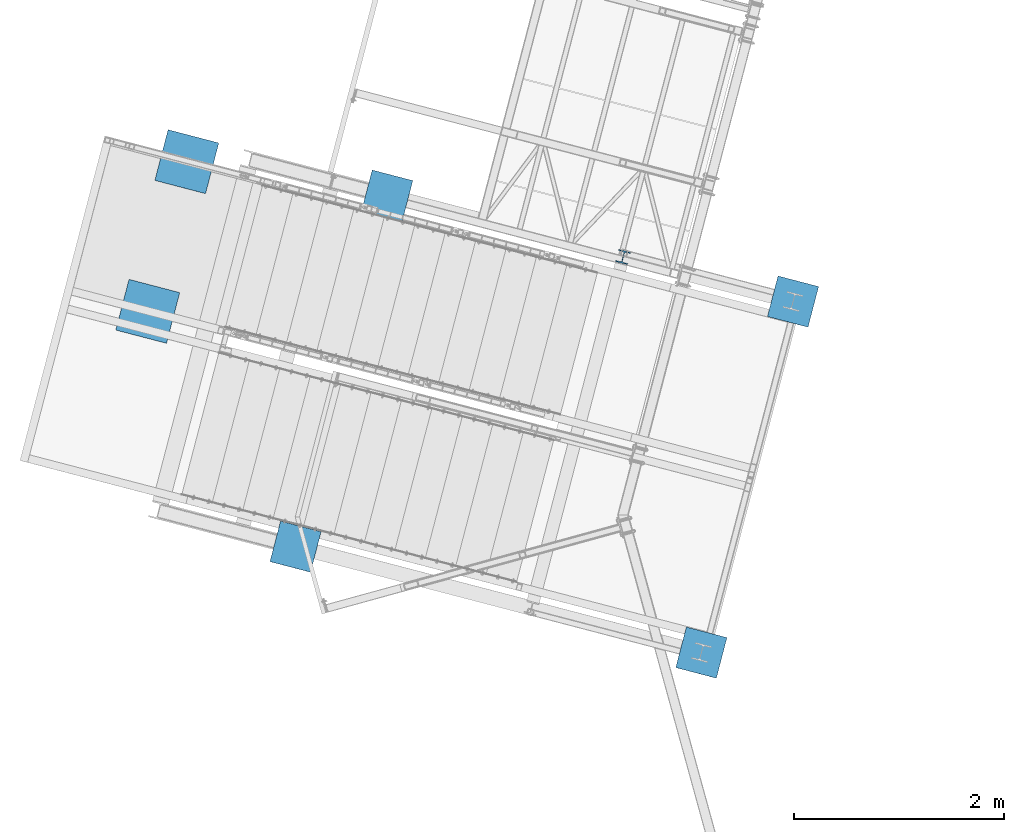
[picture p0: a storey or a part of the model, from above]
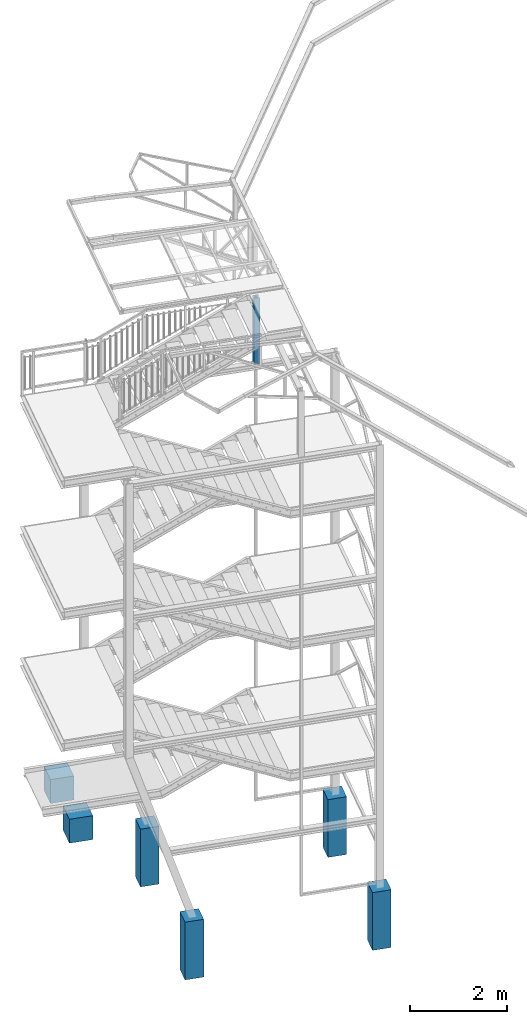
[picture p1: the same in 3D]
Properties of the parts of a building model (IFC2X3), part 1 of 5

# File
Description: ViewDefinition[CoordinationView_V2.0, QuantityTakeOffAddOnView], Option [BaseQuantities:On], Option [GridExport:On], Option [Assemblies:On], Option [Bolts:On], Option [Rebars:On], Option [PourObjects:Off], Option [Welds:Off], Option [SurfaceTreatments:Off], Option [LocationBy:0], Option [ViewColors:Off], Option [SectionedSpine:Off], Option [PropertySets:On], Option [Export all:Off]
File name: IR_026-25_ifc_kładka.ifc
Time: 2025-10-13T10:14:06
Author: INFRARED\aneta.moskala
Organization: Structural Designer
Written by: IFC Database Version: Work
Made in: Tekla Structures Educational 2018, IFC Export Version: 4.0.0.0 Mar 15 2018

# IfcSite, Undefined
RefElevation: 0 mm

# IfcBuildingStorey, Undefined
In: Undefined
Elevation: 0 mm

# IfcBeam: 200*1500, BEAM
In: Undefined
Description: 200*1500; Material: CONCRETE/C45/55
Tekla Common - Bottom elevation: +5.080; Top elevation: +5.280; Phase: 1; Class: 4
Tekla Quantity - Weight: 3339 kg; Volume: 1.4 m3; Gross footprint area: 7 m2; Area per tons: 5 m2; Net surface area: 16.6 m2; Height: 200 mm; Width: 1500 mm; Length: 6146 mm
Pset_BeamCommon - LoadBearing: yes; Reference: Z3
BaseQuantities - Length: 6146 mm; OuterSurfaceArea: 16.6194 m2; NetVolume: 1.39123 m3; NetWeight: 3338.95 kg

# IfcBeam: 350*350 (4)
In: Undefined
Description: 350*350; Material: CONCRETE/C45/55
Tekla Common - Bottom elevation: +3.670; Top elevation: +4.480; Phase: 1; Class: 4
Tekla Quantity - Weight: 238.1 kg; Volume: 0.1 m3; Gross footprint area: 0.1 m2; Area per tons: 5.8 m2; Net surface area: 1.5 m2; Height: 350 mm; Width: 350 mm; Length: 810 mm
Pset_BeamCommon - LoadBearing: yes; Reference: Z1
BaseQuantities - Length: 810 mm; OuterSurfaceArea: 1.379 m2; NetVolume: 0.099225 m3; NetWeight: 238.14 kg

# IfcBeam: 800*350 (3)
In: Undefined
Description: 800*350; Material: CONCRETE/C45/55
Tekla Common - Bottom elevation: +4.480; Top elevation: +5.280; Phase: 1; Class: 4
Tekla Quantity - Height: 800 mm; Width: 350 mm
Pset_BeamCommon - LoadBearing: yes
Name | Weight (kg) | Volume (m3) | Gross footprint area (m2) | Area per tons (m2) | Net surface area (m2) | Tekla Quantity, Length (mm) | Reference | BaseQuantities, Length (mm) | OuterSurfaceArea (m2) | NetVolume (m3) | NetWeight (kg)
BEAM | 3281.2 | 1.4 | 1.6 | 3.7 | 12.1 | 5289.9 | Z4 | 5289.87 | 12.1456 | 1.36717 | 3281.21
BEAM | 3628.8 | 1.4 | 2 | 3.6 | 13 | 5400 | Z2 | 5400 | 12.98 | 1.512 | 3628.8
BEAM | 8295.2 | 3.5 | 4.2 | 3.5 | 29 | 12350 | Z5 | 12350 | 28.9882 | 3.45632 | 8295.16

# IfcBeam: C100*20*2 (12)
In: Undefined
Description: C100*20*2
Tekla Common - Class: 1
Tekla Quantity - Volume: 0 m3; Gross footprint area: 0 m2; Height: 100 mm; Width: 20 mm
Name | Material | Bottom elevation | Top elevation | Phase | Weight (kg) | Area per tons (m2) | Net surface area (m2) | Tekla Quantity, Length (mm) = BaseQuantities, Length (mm) | LoadBearing | Reference | OuterSurfaceArea (m2) | NetVolume (m3) | NetWeight (kg)
KICK_PLATE | STEEL/S235JR | +13.946 | +14.065 | 1 | 3.2 | 129.4 | 0.4 | 1492.5 | yes | F15 | 0.410671 | 0.000404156 | 3.17263
KICK_PLATE | STEEL/S235JR | +13.946 | +14.047 | 1 | 3.2 | 129.4 | 0.4 | 1490 | yes | F7 | 0.411784 | 0.00040528 | 3.18145
KICK_PLATE | STEEL/S235JR | +13.915 | +14.046 | 1 | 5.4 | 129.4 | 0.7 | 2475.5 | yes | F17 | 0.683782 | 0.000673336 | 5.28569
KICK_PLATE | STEEL/S235JR | +13.812 | +13.961 | 1 | 8.2 | 129.4 | 1.1 | 3895 | yes | F10 | 1.07556 | 0.00105944 | 8.3166
KICK_PLATE | STEEL/S235JR | +13.915 | +14.015 | 1 | 3.2 | 129.4 | 0.4 | 1490 | yes | F7 | 0.411784 | 0.00040528 | 3.18145
KICK_PLATE | STEEL/S235JR | +13.861 | +14.015 | 1 | 9 | 129.4 | 1.2 | 4220 | yes | F9 | 1.16346 | 0.00114603 | 8.99636
KICK_PLATE | STEEL/S235JR | +13.865 | +14.014 | 1 | 8.2 | 129.4 | 1.1 | 3862 | yes | F8 | 1.06646 | 0.00105046 | 8.24614
KICK_PLATE | STEEL/S235JR | +13.914 | +14.065 | 1 | 8.6 | 129.4 | 1.1 | 4042 | yes | F6 | 1.11614 | 0.00109942 | 8.63048
KICK_PLATE | STEEL/S235JR | +13.800 | +13.900 | 5 | 4.2 | 129.4 | 0.4 | 1975 | yes | p8 | 0.544689 | 0.000536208 | 4.20923
KICK_PLATE | STEEL/S235JR | +13.800 | +13.900 | 5 | 4.6 | 129.4 | 0.7 | 2182 | yes | F19 | 0.602776 | 0.000593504 | 4.65901
PORĘCZ | STEEL/S235 | +13.811 | +13.911 | 1 | 0.6 | 130.1 | 0.1 | 300 | no | fk79 | 0.0828763 | 0.0000811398 | 0.636947
KICK_PLATE | STEEL/S235JR | +13.800 | +13.965 | 1 | 10.8 | 129.4 | 1.5 | 5060 | yes | F11 | 1.3971 | 0.00137632 | 10.8041

# IfcBeam: C100*50*3 (2)
In: Undefined
Description: C100*50*3; Material: STEEL/S235
Tekla Common - Bottom elevation: +13.925; Phase: 2
Tekla Quantity - Volume: 0 m3; Gross footprint area: 0 m2; Area per tons: 86.3 m2; Height: 100 mm; Width: 50 mm
Name | Top elevation | Class | Weight (kg) | Net surface area (m2) | Tekla Quantity, Length (mm) = BaseQuantities, Length (mm) | LoadBearing | Reference | OuterSurfaceArea (m2) | NetVolume (m3) | NetWeight (kg)
BEAM | +14.026 | 14 | 11.6 | 1 | 2540 | yes | k159 | 1.00192 | 0.00147828 | 11.6045
BEAM | +14.025 | 6 | 7.2 | 0.7 | 1570 | no | k101 | 0.619744 | 0.00091374 | 7.17286

# IfcBeam: C70*40*4 (3)
In: Undefined
Description: C70*40*4; Material: STEEL/S235
Tekla Common - Class: 6
Tekla Quantity - Volume: 0 m3; Height: 70 mm; Width: 40 mm
Pset_BeamCommon - LoadBearing: no
Name | Bottom elevation | Top elevation | Phase | Weight (kg) | Gross footprint area (m2) | Area per tons (m2) | Net surface area (m2) | Tekla Quantity, Length (mm) | Reference | BaseQuantities, Length (mm) | OuterSurfaceArea (m2) | NetVolume (m3) | NetWeight (kg)
BEAM | +13.910 | +13.980 | 2 | 2.7 | 0 | 65.9 | 0.2 | 598.9 | k106 | 598.9 | 0.175014 | 0.000338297 | 2.65563
BEAM | +13.911 | +13.982 | 3 | 11.9 | 0.1 | 65.6 | 0.7 | 2679.8 | Ws13 | 2679.83 | 0.783647 | 0.00152215 | 11.9488
BEAM | +13.910 | +13.980 | 3 | 10.1 | 0.1 | 65.6 | 0.7 | 2257.7 | Ws15 | 2257.68 | 0.660377 | 0.00128236 | 10.0665

# IfcBeam: C80*40*3 (6)
In: Undefined
Description: C80*40*3
Tekla Common - Class: 6
Tekla Quantity - Volume: 0 m3; Height: 80 mm; Width: 40 mm
Name | Material | Bottom elevation | Top elevation | Phase | Weight (kg) | Gross footprint area (m2) | Area per tons (m2) | Net surface area (m2) | Tekla Quantity, Length (mm) | LoadBearing | Reference | BaseQuantities, Length (mm) | OuterSurfaceArea (m2) | NetVolume (m3) | NetWeight (kg)
BEAM | STEEL/S355 | +13.860 | +13.973 | 1 | 8.2 | 0 | 86.7 | 0.7 | 2262 | yes | k166 | 2262 | 0.711192 | 0.00104504 | 8.2036
BEAM | STEEL/S235 | +13.909 | +13.989 | 2 | 5.2 | 0.1 | 86.9 | 0.4 | 1438.6 | no | k103 | 1438.61 | 0.451684 | 0.000663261 | 5.2066
BEAM | STEEL/S355 | +13.806 | +13.955 | 1 | 18.4 | 0 | 86.7 | 1.6 | 5100 | yes | k80 | 5100 | 1.60232 | 0.0023562 | 18.4962
BEAM | STEEL/S355 | +13.809 | +13.944 | 1 | 14.5 | 0 | 86.7 | 1.2 | 3990 | yes | k74 | 3990 | 1.25378 | 0.00184338 | 14.4705
BEAM | STEEL/S235 | +13.910 | +13.990 | 3 | 4.9 | 0.1 | 86.9 | 0.4 | 1366 | no | k72 | 1365.95 | 0.42887 | 0.000629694 | 4.9431
BEAM | STEEL/S235 | +13.910 | +13.990 | 3 | 5.4 | 0.1 | 86.7 | 0.4 | 1500 | no | k70 | 1500 | 0.471924 | 0.000693 | 5.44005

# IfcBeam: D10 (2)
In: Undefined
Description: D10; Material: STEEL/S235
Tekla Common - Phase: 3; Class: 11
Tekla Quantity - Weight: 1.1 kg; Volume: 0 m3; Gross footprint area: 0 m2; Area per tons: 55.3 m2; Net surface area: 0.1 m2; Height: 10 mm; Width: 10 mm
Pset_BeamCommon - LoadBearing: no
Name | Bottom elevation | Top elevation | Tekla Quantity, Length (mm) | Reference | BaseQuantities, Length (mm) | OuterSurfaceArea (m2) | NetVolume (m3) | NetWeight (kg)
BEAM | +13.885 | +13.948 | 1980 | k79 | 1980 | 0.0607585 | 0.000140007 | 1.09906
BEAM | +13.866 | +13.929 | 1978.7 | k78 | 1978.68 | 0.060718 | 0.000139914 | 1.09832

# IfcBeam: HEB140 (10)
In: Undefined
Description: HEB140
Tekla Common - Class: 4
Tekla Quantity - Volume: 0 m3; Area per tons: 23.8 m2; Height: 140 mm; Width: 140 mm
Pset_BeamCommon - LoadBearing: no
Name | Material | Bottom elevation | Top elevation | Phase | Weight (kg) | Gross footprint area (m2) | Net surface area (m2) | Tekla Quantity, Length (mm) | Reference | BaseQuantities, Length (mm) | OuterSurfaceArea (m2) | NetVolume (m3) | NetWeight (kg)
COLUMN | STEEL/S235 | +2.640 | +2.780 | 2 | 111.4 | 0 | 2.7 | 3300 | xx15 | 3300 | 2.6565 | 0.0137676 | 108.076
2 x BEAM | STEEL/S355 | +13.400 | +13.540 | 5 | 8.4 | 0 | 0.2 | 250 | zz2 | 250 | 0.20125 | 0.001043 | 8.18755
BEAM | STEEL/S355 | +13.400 | +13.540 | 5 | 167.4 | 0.7 | 4.2 | 4959.9 | zz8 | 4959.92 | 3.99274 | 0.0206928 | 162.438
2 x BEAM | STEEL/S355 | +13.400 | +13.540 | 5 | 10.8 | 0 | 0.2 | 320 | zz3 | 320 | 0.2576 | 0.001043 | 8.18755
BEAM | STEEL/S355 | +13.400 | +13.540 | 5 | 53.5 | 0.2 | 1.2 | 1584.7 | zz6 | 1584.71 | 1.27569 | 0.0064666 | 50.7628
BEAM | STEEL/S355 | +13.400 | +13.540 | 5 | 94.7 | 0.3 | 2.3 | 2805 | zz9 | 2805 | 2.25803 | 0.0117025 | 91.8643
BEAM | STEEL/S355 | +13.400 | +13.540 | 5 | 9 | 0 | 0.2 | 267.8 | zz27 | 267.81 | 0.215587 | 0.00101888 | 7.99817
BEAM | STEEL/S355 | +13.400 | +13.540 | 5 | 129.8 | 0.5 | 3.2 | 3846 | tt1 | 3846 | 3.09603 | 0.0160455 | 125.957

# IfcBeam: HEB160 (7)
In: Undefined
Description: HEB160
Tekla Quantity - Gross footprint area: 0 m2; Area per tons: 21.5 m2; Height: 160 mm; Width: 160 mm
Pset_BeamCommon - LoadBearing: no
Name | Material | Bottom elevation | Top elevation | Phase | Class | Weight (kg) | Volume (m3) | Net surface area (m2) | Tekla Quantity, Length (mm) | Reference | BaseQuantities, Length (mm) | OuterSurfaceArea (m2) | NetVolume (m3) | NetWeight (kg)
COLUMN | STEEL/S235 | +11.990 | +12.150 | 2 | 4 | 140.7 | 0 | 3.1 | 3300 | xx13 | 3300 | 3.0294 | 0.0172656 | 135.535
COLUMN | STEEL/S235 | +8.690 | +8.850 | 2 | 4 | 140.7 | 0 | 3.1 | 3300 | xx13 | 3300 | 3.0294 | 0.0172656 | 135.535
COLUMN | STEEL/S235 | +5.390 | +5.550 | 2 | 4 | 140.7 | 0 | 3.1 | 3300 | xx13 | 3300 | 3.0294 | 0.0172656 | 135.535
2 x COLUMN | STEEL/S235 | +1.020 | +12.140 | 2 | 4 | 474 | 0.1 | 10.5 | 11120 | xx35 | 11120 | 10.2082 | 0.0581798 | 456.712
2 x BEAM | STEEL/S355 | +13.620 | +13.700 | 1 | 3 | 3.4 | 0 | 0.1 | 79.6 | k45 | 79.6292 | 0.0730996 | 0.00041595 | 3.26521

# IfcBeam: K60/4 (2)
In: Undefined
Description: K60/4; Material: STEEL/S355
Tekla Common - Bottom elevation: +13.848; Top elevation: +13.915; Phase: 1; Class: 9
Tekla Quantity - Weight: 6.2 kg; Volume: 0 m3; Gross footprint area: 0 m2; Area per tons: 34.4 m2; Net surface area: 0.2 m2; Height: 60 mm; Width: 60 mm; Length: 911.6 mm
Pset_BeamCommon - LoadBearing: no; Reference: k43
BaseQuantities - OuterSurfaceArea: 0.209657 m2; NetVolume: 0.000816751 m3
Name | Length (mm) | NetWeight (kg)
BEAM | 911.552 | 6.41149
BEAM | 911.553 | 6.4115

# IfcBeam: L100*50*5 (12)
In: Undefined
Description: L100*50*5; Material: STEEL/S235
Tekla Common - Bottom elevation: +13.715; Top elevation: +13.765; Phase: 5; Class: 11
Tekla Quantity - Volume: 0 m3; Height: 100 mm; Width: 50 mm
Pset_BeamCommon - LoadBearing: no
Name | Weight (kg) | Gross footprint area (m2) | Area per tons (m2) | Net surface area (m2) | Tekla Quantity, Length (mm) = BaseQuantities, Length (mm) | Reference | OuterSurfaceArea (m2) | NetVolume (m3) | NetWeight (kg)
BEAM | 3.9 | 0.1 | 53.1 | 0.2 | 700 | K10 | 0.21145 | 0.0005075 | 3.98387
BEAM | 6.2 | 0.1 | 52.9 | 0.4 | 1080 | K4 | 0.32545 | 0.000783 | 6.14655
BEAM | 3.9 | 0.1 | 53.1 | 0.2 | 690 | K3 | 0.20845 | 0.00050025 | 3.92696
BEAM | 4.6 | 0.1 | 52.9 | 0.2 | 800 | K9 | 0.24145 | 0.00058 | 4.553
BEAM | 0.6 | 0 | 54.8 | 0 | 120 | K15 | 0.03745 | 0.000087 | 0.68295
BEAM | 0.8 | 0 | 54.4 | 0 | 150 | K13 | 0.04645 | 0.00010875 | 0.853688
BEAM | 4.9 | 0.1 | 52.9 | 0.4 | 850 | K14 | 0.25645 | 0.00061625 | 4.83756
BEAM | 3.9 | 0.1 | 53.1 | 0.2 | 700 | K10 | 0.21145 | 0.0005075 | 3.98388
BEAM | 5.2 | 0.1 | 52.9 | 0.4 | 900 | K7 | 0.27145 | 0.0006525 | 5.12212
2 x BEAM | 5.4 | 0.1 | 52.9 | 0.4 | 950 | K11 | 0.28645 | 0.00068875 | 5.40669
BEAM | 5.4 | 0.1 | 52.9 | 0.4 | 950 | K6 | 0.28645 | 0.00068875 | 5.40669

# IfcBeam: L40*3 (2)
In: Undefined
Description: L40*3; Material: STEEL/S235
Tekla Common - Bottom elevation: +13.725; Top elevation: +13.765; Phase: 5; Class: 4
Tekla Quantity - Volume: 0 m3; Gross footprint area: 0 m2; Area per tons: 84.4 m2; Height: 40 mm; Width: 40 mm
Pset_BeamCommon - LoadBearing: no
Name | Weight (kg) | Net surface area (m2) | Tekla Quantity, Length (mm) = BaseQuantities, Length (mm) | Reference | OuterSurfaceArea (m2) | NetVolume (m3) | NetWeight (kg)
BEAM | 1.6 | 0.1 | 885 | D1 | 0.137175 | 0.000204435 | 1.60481
BEAM | 1.9 | 0.2 | 1055 | D3 | 0.163525 | 0.000243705 | 1.91308

# IfcBeam: L40*60*6, BEAM
In: Undefined
Description: L40*60*6; Material: STEEL/S235
Tekla Common - Bottom elevation: +13.984; Top elevation: +14.024; Phase: 3; Class: 4
Tekla Quantity - Weight: 28.5 kg; Volume: 0 m3; Gross footprint area: 0 m2; Area per tons: 45.2 m2; Net surface area: 1.2 m2; Height: 40 mm; Width: 60 mm; Length: 6436 mm
Pset_BeamCommon - LoadBearing: no; Reference: xx21
BaseQuantities - Length: 6436 mm; OuterSurfaceArea: 1.28723 m2; NetVolume: 0.00362685 m3; NetWeight: 28.4708 kg

# IfcBeam: L50*3 (6)
In: Undefined
Description: L50*3; Material: STEEL/S235
Tekla Common - Bottom elevation: +13.715; Top elevation: +13.765; Phase: 5; Class: 11
Tekla Quantity - Volume: 0 m3; Area per tons: 84.9 m2; Net surface area: 0.2 m2; Height: 50 mm; Width: 50 mm
Pset_BeamCommon - LoadBearing: no
Name | Weight (kg) | Gross footprint area (m2) | Tekla Quantity, Length (mm) = BaseQuantities, Length (mm) | Reference | OuterSurfaceArea (m2) | NetVolume (m3) | NetWeight (kg)
BEAM | 2.7 | 0.1 | 1200 | K5 | 0.2328 | 0.0003492 | 2.74122
BEAM | 2.2 | 0 | 980 | K1 | 0.19012 | 0.00028518 | 2.23866
BEAM | 1.8 | 0 | 780 | K2 | 0.15132 | 0.00022698 | 1.78179
BEAM | 1.8 | 0 | 800 | K8 | 0.1552 | 0.0002328 | 1.82748
2 x BEAM | 2.2 | 0 | 950 | K12 | 0.1843 | 0.00027645 | 2.17013

# IfcBeam: L70*5, BEAM
In: Undefined
Description: L70*5; Material: STEEL/S235
Tekla Common - Bottom elevation: +13.665; Top elevation: +13.785; Phase: 5; Class: 1
Tekla Quantity - Weight: 0.6 kg; Volume: 0 m3; Gross footprint area: 0 m2; Area per tons: 51.3 m2; Net surface area: 0 m2; Height: 70 mm; Width: 70 mm; Length: 120 mm
Pset_BeamCommon - LoadBearing: no; Reference: F20
BaseQuantities - Length: 120 mm; OuterSurfaceArea: 0.03264 m2; NetVolume: 0.000081 m3; NetWeight: 0.63585 kg

# IfcBeam: L80*50*3, PORĘCZ
In: Undefined
Description: L80*50*3; Material: STEEL/S235
Tekla Common - Bottom elevation: +13.350; Top elevation: +13.430; Phase: 2; Class: 1
Tekla Quantity - Weight: 0.1 kg; Volume: 0 m3; Gross footprint area: 0 m2; Area per tons: 92 m2; Net surface area: 0 m2; Height: 80 mm; Width: 50 mm; Length: 50 mm
Pset_BeamCommon - LoadBearing: yes; Reference: 5
BaseQuantities - Length: 50.0001 mm; OuterSurfaceArea: 0.013762 m2; NetVolume: 0.00001905 m3; NetWeight: 0.149543 kg

# IfcBeam: L85*5, BEAM
In: Undefined
Description: L85*5; Material: STEEL/S235
Tekla Common - Bottom elevation: +13.665; Top elevation: +13.785; Phase: 5; Class: 1
Tekla Quantity - Weight: 0.8 kg; Volume: 0 m3; Gross footprint area: 0 m2; Area per tons: 54.6 m2; Net surface area: 0 m2; Height: 85 mm; Width: 85 mm; Length: 120 mm
Pset_BeamCommon - LoadBearing: no; Reference: F21
BaseQuantities - Length: 120 mm; OuterSurfaceArea: 0.04245 m2; NetVolume: 0.000099 m3; NetWeight: 0.77715 kg

# IfcBeam: RHS100*60*6 (2)
In: Undefined
Description: RHS100*60*6; Material: STEEL/S235
Tekla Common - Phase: 3; Class: 4
Tekla Quantity - Weight: 89.6 kg; Volume: 0 m3; Gross footprint area: 0.3 m2; Area per tons: 22.6 m2; Net surface area: 1.9 m2; Height: 100 mm; Width: 60 mm; Length: 6476 mm
Pset_BeamCommon - LoadBearing: no
BaseQuantities - Length: 6476 mm; OuterSurfaceArea: 2.02685 m2; NetVolume: 0.0114161 m3; NetWeight: 89.6161 kg
Name | Bottom elevation | Top elevation | Reference
BEAM | +12.781 | +12.881 | xx22
BEAM | +13.780 | +13.880 | xx19

# IfcBeam: RHS100*80*4 (3)
In: Undefined
Description: RHS100*80*4
Tekla Quantity - Volume: 0 m3; Area per tons: 33.2 m2; Height: 100 mm; Width: 80 mm
Tekla Common - Top elevation: +14.025; Phase: 2
Name | Material | Weight (kg) | Gross footprint area (m2) | Net surface area (m2) | Tekla Quantity, Length (mm) | Bottom elevation | Class | LoadBearing | Reference | BaseQuantities, Length (mm) | OuterSurfaceArea (m2) | NetVolume (m3) | NetWeight (kg)
BEAM | STEEL/S355 | 36.4 | 0.3 | 1.2 | 3412 | +13.925 | 14 | no | k119 | 3412 | 1.20993 | 0.00463987 | 36.4229
2 x BEAM | STEEL/S235 | 31.3 | 0 | 1 | 2905.5 | +13.781 | 6 | yes | k47 | 2905.54 | 1.04124 | 0.00399286 | 31.3439

# IfcBeam: RHS120*4 (2)
In: Undefined
Description: RHS120*4; Material: STEEL/S355
Tekla Common - Phase: 1; Class: 11
Tekla Quantity - Volume: 0 m3; Gross footprint area: 0 m2; Area per tons: 33 m2; Height: 120 mm; Width: 120 mm
Pset_BeamCommon - LoadBearing: no
Name | Bottom elevation | Top elevation | Weight (kg) | Net surface area (m2) | Tekla Quantity, Length (mm) | Reference | BaseQuantities, Length (mm) | OuterSurfaceArea (m2) | NetVolume (m3) | NetWeight (kg)
BEAM | +13.652 | +13.941 | 193.6 | 6.4 | 13286 | k37 | 13286 | 6.3792 | 0.0246588 | 193.572
BEAM | +13.821 | +14.019 | 88.2 | 3 | 6070.3 | k2 | 6070.25 | 2.90826 | 0.0112377 | 88.2161

# IfcBeam: RHS120*60*3, BEAM
In: Undefined
Description: RHS120*60*3; Material: STEEL/S355
Tekla Quantity - Weight: 11.9 kg; Volume: 0 m3; Gross footprint area: 0 m2; Area per tons: 43.7 m2; Net surface area: 0.4 m2; Height: 120 mm; Width: 60 mm; Length: 1485 mm
Tekla Common - Bottom elevation: +13.796; Top elevation: +13.916; Phase: 1; Class: 14
Pset_BeamCommon - LoadBearing: no; Reference: k65
BaseQuantities - Length: 1485 mm; OuterSurfaceArea: 0.520616 m2; NetVolume: 0.00151902 m3; NetWeight: 11.9243 kg

# IfcBeam: RHS50*3 (8)
In: Undefined
Description: RHS50*3; Material: STEEL/S235
Tekla Quantity - Volume: 0 m3; Height: 50 mm; Width: 50 mm
Name | Bottom elevation | Top elevation | Phase | Class | Weight (kg) | Gross footprint area (m2) | Area per tons (m2) | Net surface area (m2) | Tekla Quantity, Length (mm) | LoadBearing | Reference | BaseQuantities, Length (mm) | OuterSurfaceArea (m2) | NetVolume (m3) | NetWeight (kg)
PORĘCZ | +13.615 | +13.665 | 3 | 5 | 6 | 0.1 | 45.3 | 0.4 | 1348 | yes | fk117 | 1348.01 | 0.270202 | 0.000760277 | 5.96818
PORĘCZ | +13.324 | +13.374 | 2 | 4 | 0 | 0 | 60.1 | 0 | 19 | yes | fk116 | 18.9883 | 0.00252067 | 0.00000534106 | 0.0419273
PORĘCZ | +13.324 | +13.374 | 2 | 4 | 0.5 | 0 | 46.4 | 0 | 110 | yes | 3 | 110 | 0.0226 | 0.00006204 | 0.487014
PORĘCZ | +13.430 | +13.480 | 2 | 4 | 0.5 | 0 | 46.4 | 0 | 110 | yes | 4 | 110 | 0.0226 | 0.00006204 | 0.487014
PORĘCZ | +14.850 | +14.900 | 5 | 4 | 8.4 | 0.1 | 45.3 | 0.4 | 1924.3 | yes | xx45 | 1924.3 | 0.380584 | 0.0010712 | 8.40895
2 x PORĘCZ | +13.980 | +14.030 | 2 | 5 | 9 | 0.1 | 45.2 | 0.4 | 2054.9 | no | fk56 | 2054.9 | 0.410408 | 0.00115564 | 9.07174
PORĘCZ | +13.430 | +13.480 | 2 | 4 | 6.2 | 0.1 | 45.3 | 0.4 | 1390 | yes | fk60 | 1390 | 0.2786 | 0.00078396 | 6.15409

# IfcBeam: SHS100*5, BEAM
In: Undefined
Description: SHS100*5; Material: STEEL/S235
Tekla Quantity - Weight: 96.9 kg; Volume: 0 m3; Gross footprint area: 0 m2; Area per tons: 26.8 m2; Net surface area: 2.6 m2; Height: 100 mm; Width: 100 mm; Length: 6524.6 mm
Tekla Common - Bottom elevation: +12.781; Top elevation: +12.882; Phase: 2; Class: 4
Pset_BeamCommon - LoadBearing: no; Reference: xx60
BaseQuantities - Length: 6524.64 mm; OuterSurfaceArea: 2.6012 m2; NetVolume: 0.0123459 m3; NetWeight: 96.915 kg

# IfcBeam: SHS50*3 (2)
In: Undefined
Description: SHS50*3; Material: STEEL/S235
Tekla Common - Phase: 3; Class: 5
Tekla Quantity - Volume: 0 m3; Height: 50 mm; Width: 50 mm
Name | Bottom elevation | Top elevation | Weight (kg) | Gross footprint area (m2) | Area per tons (m2) | Net surface area (m2) | Tekla Quantity, Length (mm) | LoadBearing | Reference | BaseQuantities, Length (mm) | OuterSurfaceArea (m2) | NetVolume (m3) | NetWeight (kg)
PORĘCZ | +13.615 | +13.665 | 0.5 | 0 | 46.6 | 0 | 142.7 | yes | xx65 | 142.728 | 0.0242698 | 0.0000663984 | 0.521228
PORĘCZ | +13.990 | +14.040 | 9.2 | 0.1 | 45.2 | 0.4 | 2111 | no | fk17 | 2110.99 | 0.421636 | 0.0011873 | 9.32029

# IfcBeam: SHS60*3 (16)
In: Undefined
Description: SHS60*3
Tekla Quantity - Volume: 0 m3; Gross footprint area: 0 m2; Height: 60 mm; Width: 60 mm
Name | Material | Bottom elevation | Top elevation | Phase | Class | Weight (kg) | Area per tons (m2) | Net surface area (m2) | Tekla Quantity, Length (mm) | LoadBearing | Reference | BaseQuantities, Length (mm) | OuterSurfaceArea (m2) | NetVolume (m3) | NetWeight (kg)
BEAM | STEEL/S355 | +13.686 | +13.905 | 1 | 6 | 7.3 | 44.8 | 0.4 | 1400 | no | k61 | 1399.96 | 0.330434 | 0.000939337 | 7.3738
BEAM | STEEL/S355 | +13.693 | +13.925 | 1 | 6 | 7.8 | 44.8 | 0.4 | 1464.1 | no | k54 | 1464.12 | 0.351257 | 0.000999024 | 7.84234
BEAM | STEEL/S355 | +13.654 | +13.887 | 1 | 6 | 7.8 | 44.8 | 0.4 | 1464.1 | no | k54 | 1464.12 | 0.351257 | 0.000999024 | 7.84234
2 x BEAM | STEEL/S235 | +16.306 | +16.518 | 5 | 12 | 4.5 | 45 | 0.2 | 841.2 | yes | k117 | 841.18 | 0.202603 | 0.000575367 | 4.51663
3 x BEAM | STEEL/S235 | +16.286 | +16.637 | 5 | 12 | 10 | 44.8 | 0.4 | 1856.5 | yes | k113 | 1856.51 | 0.446283 | 0.00126985 | 9.96836
BEAM | STEEL/S235 | +16.286 | +16.637 | 5 | 12 | 10 | 44.8 | 0.4 | 1856.5 | yes | k73 | 1856.51 | 0.446283 | 0.00126985 | 9.96836
BEAM | STEEL/S355 | +13.716 | +13.947 | 1 | 6 | 8 | 44.8 | 0.4 | 1508.5 | no | k59 | 1508.5 | 0.358119 | 0.00101851 | 7.9953
BEAM | STEEL/S355 | +13.686 | +13.905 | 1 | 6 | 7.3 | 44.8 | 0.4 | 1399.5 | no | k61 | 1399.48 | 0.330319 | 0.000939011 | 7.37124
BEAM | STEEL/S355 | +13.713 | +13.945 | 1 | 6 | 7.8 | 44.8 | 0.4 | 1463.6 | no | k54 | 1463.63 | 0.351141 | 0.000998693 | 7.83974
BEAM | STEEL/S355 | +13.693 | +13.925 | 1 | 6 | 7.8 | 44.8 | 0.4 | 1463.6 | no | k54 | 1463.63 | 0.351141 | 0.000998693 | 7.83974
BEAM | STEEL/S355 | +13.652 | +13.884 | 1 | 6 | 7.8 | 44.8 | 0.4 | 1463.6 | no | k54 | 1463.63 | 0.351141 | 0.000998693 | 7.83974
BEAM | STEEL/S355 | +13.729 | +13.965 | 1 | 6 | 8 | 44.8 | 0.4 | 1508.2 | no | k59 | 1508.19 | 0.358059 | 0.00101834 | 7.99396
BEAM | STEEL/S355 | +13.713 | +13.945 | 1 | 6 | 7.8 | 44.8 | 0.4 | 1464.1 | no | k54 | 1464.12 | 0.351257 | 0.000999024 | 7.84234

# IfcBeam: SHS60*4 (10)
In: Undefined
Description: SHS60*4; Material: STEEL/S235
Tekla Common - Phase: 2; Class: 4
Tekla Quantity - Volume: 0 m3; Gross footprint area: 0 m2; Area per tons: 34.2 m2; Net surface area: 0.7 m2; Height: 60 mm; Width: 60 mm
Pset_BeamCommon - LoadBearing: no
Name | Bottom elevation | Top elevation | Weight (kg) | Tekla Quantity, Length (mm) = BaseQuantities, Length (mm) | Reference | OuterSurfaceArea (m2) | NetVolume (m3) | NetWeight (kg)
2 x BEAM | +2.780 | +5.400 | 18.4 | 2620 | xx17 | 0.62976 | 0.00234752 | 18.428
2 x BEAM | +8.840 | +12.000 | 22.2 | 3160 | xx18 | 0.75936 | 0.00283136 | 22.2262
2 x BEAM | +5.540 | +8.700 | 22.2 | 3160 | xx18 | 0.75936 | 0.00283136 | 22.2262
COLUMN | +12.040 | +12.100 | 23.2 | 3300 | xx37 | 0.79296 | 0.0029568 | 23.2109
COLUMN | +8.740 | +8.800 | 23.2 | 3300 | xx37 | 0.79296 | 0.0029568 | 23.2109
COLUMN | +5.440 | +5.500 | 23.2 | 3300 | xx37 | 0.79296 | 0.0029568 | 23.2109
COLUMN | +1.880 | +1.940 | 23.2 | 3300 | xx26 | 0.79296 | 0.0029568 | 23.2109

# IfcBeam: SHS80*4 (8)
In: Undefined
Description: SHS80*4; Material: STEEL/S235
Tekla Quantity - Volume: 0 m3; Area per tons: 33.6 m2; Net surface area: 0.7 m2; Height: 80 mm; Width: 80 mm
Pset_BeamCommon - LoadBearing: yes
Name | Bottom elevation | Top elevation | Phase | Class | Weight (kg) | Gross footprint area (m2) | Tekla Quantity, Length (mm) | Reference | BaseQuantities, Length (mm) | OuterSurfaceArea (m2) | NetVolume (m3) | NetWeight (kg)
BEAM | +16.460 | +16.540 | 5 | 12 | 24.7 | 0.2 | 2590 | k116 | 2590 | 0.83008 | 0.00314944 | 24.7231
BEAM | +16.284 | +16.364 | 5 | 12 | 24.7 | 0.2 | 2590 | k116 | 2590 | 0.83008 | 0.00314944 | 24.7231
BEAM | +13.801 | +13.989 | 2 | 6 | 20.8 | 0 | 2172.2 | k49 | 2172.23 | 0.695433 | 0.00263778 | 20.7066
BEAM | +13.801 | +13.989 | 2 | 6 | 20.8 | 0 | 2172.2 | k49 | 2172.28 | 0.695451 | 0.00263785 | 20.7071
BEAM | +13.802 | +13.990 | 3 | 6 | 20.8 | 0 | 2172.2 | k49 | 2172.16 | 0.695414 | 0.0026377 | 20.706
3 x BEAM | +13.801 | +13.990 | 3 | 6 | 21 | 0 | 2192.4 | k67 | 2192.42 | 0.701897 | 0.00266234 | 20.8994

# IfcBeam: UPE200 (3)
In: Undefined
Description: UPE200; Material: STEEL/S235
Tekla Common - Phase: 2; Class: 4
Tekla Quantity - Weight: 81.6 kg; Volume: 0 m3; Gross footprint area: 0 m2; Area per tons: 27.9 m2; Net surface area: 2.3 m2; Height: 200 mm; Width: 80 mm; Length: 3300 mm
Pset_BeamCommon - LoadBearing: no; Reference: xx36
BaseQuantities - Length: 3300 mm; OuterSurfaceArea: 2.277 m2; NetVolume: 0.0102135 m3; NetWeight: 80.176 kg
Name | Bottom elevation | Top elevation
COLUMN | +10.500 | +10.700
COLUMN | +7.200 | +7.400
COLUMN | +3.900 | +4.100

# IfcBeam: UPN140, BEAM
In: Undefined
Description: UPN140; Material: STEEL/S355
Tekla Common - Bottom elevation: +13.655; Top elevation: +13.795; Phase: 5; Class: 4
Tekla Quantity - Weight: 35.6 kg; Volume: 0 m3; Gross footprint area: 0.1 m2; Area per tons: 30.6 m2; Net surface area: 1.1 m2; Height: 140 mm; Width: 60 mm; Length: 2225 mm
Pset_BeamCommon - LoadBearing: no; Reference: zz9
BaseQuantities - Length: 2225 mm; OuterSurfaceArea: 1.09025 m2; NetVolume: 0.00450006 m3; NetWeight: 35.3255 kg

# IfcBeam: UPN200 (5)
In: Undefined
Description: UPN200
Tekla Common - Class: 4
Tekla Quantity - Volume: 0 m3; Gross footprint area: 0 m2; Area per tons: 26.1 m2; Height: 200 mm; Width: 75 mm
Pset_BeamCommon - LoadBearing: no
Name | Material | Bottom elevation | Top elevation | Phase | Weight (kg) | Net surface area (m2) | Tekla Quantity, Length (mm) = BaseQuantities, Length (mm) | Reference | OuterSurfaceArea (m2) | NetVolume (m3) | NetWeight (kg)
BELKA | STEEL/S235 | +12.150 | +12.350 | 2 | 80.9 | 2.2 | 3200 | xx10 | 2.112 | 0.0103344 | 81.125
BELKA | STEEL/S235 | +8.850 | +9.050 | 2 | 80.9 | 2.2 | 3200 | xx10 | 2.112 | 0.0103344 | 81.125
BELKA | STEEL/S235 | +5.550 | +5.750 | 2 | 80.9 | 2.2 | 3200 | xx10 | 2.112 | 0.0103344 | 81.125
BEAM | STEEL/S355 | +13.565 | +13.765 | 5 | 8.6 | 0.2 | 341 | zz7 | 0.22506 | 0.00110126 | 8.64489
BEAM | STEEL/S355 | +13.565 | +13.765 | 5 | 8.6 | 0.2 | 341 | zz11 | 0.22506 | 0.00110126 | 8.64489

# IfcColumn: 400*400 (4)
In: Undefined
Description: 400*400; Material: CONCRETE/C25/30
Tekla Common - Bottom elevation: -0.430; Top elevation: +1.020; Phase: 2; Class: 4
Tekla Quantity - Weight: 556.8 kg; Volume: 0.2 m3; Gross footprint area: 0.2 m2; Area per tons: 4.7 m2; Net surface area: 2.6 m2; Height: 400 mm; Width: 400 mm; Length: 1450 mm
Pset_ColumnCommon - LoadBearing: yes; Reference: xx16
BaseQuantities - Length: 1450 mm; OuterSurfaceArea: 2.64 m2; NetVolume: 0.232 m3; NetWeight: 556.8 kg

# IfcColumn: 500*500 (2)
In: Undefined
Description: 500*500; Material: CONCRETE/C25/30
Tekla Common - Bottom elevation: +2.180; Top elevation: +2.780; Phase: 2; Class: 4
Tekla Quantity - Weight: 360 kg; Volume: 0.2 m3; Gross footprint area: 0.3 m2; Area per tons: 4.7 m2; Net surface area: 1.8 m2; Height: 500 mm; Width: 500 mm; Length: 600 mm
Pset_ColumnCommon - LoadBearing: yes; Reference: xx12
BaseQuantities - Length: 600 mm; OuterSurfaceArea: 1.7 m2; NetVolume: 0.15 m3; NetWeight: 360 kg

# IfcColumn: HEB120, BEAM
In: Undefined
Description: HEB120; Material: STEEL/S235
Tekla Common - Bottom elevation: +12.140; Top elevation: +13.800; Phase: 2; Class: 4
Tekla Quantity - Weight: 44.3 kg; Volume: 0 m3; Gross footprint area: 0 m2; Area per tons: 25.7 m2; Net surface area: 1.2 m2; Height: 120 mm; Width: 120 mm; Length: 1660 mm
Pset_ColumnCommon - LoadBearing: no; Reference: xx45
BaseQuantities - Length: 1660 mm; OuterSurfaceArea: 1.13876 m2; NetVolume: 0.00543982 m3; NetWeight: 42.7026 kg

# IfcColumn: HEB140 (5)
In: Undefined
Description: HEB140; Material: STEEL/S355
Tekla Common - Bottom elevation: +8.070; Top elevation: +13.540; Phase: 5; Class: 4
Tekla Quantity - Weight: 184.6 kg; Volume: 0 m3; Gross footprint area: 0 m2; Area per tons: 23.8 m2; Net surface area: 4.4 m2; Height: 140 mm; Width: 140 mm; Length: 5469.6 mm
Pset_ColumnCommon - LoadBearing: no; Reference: zz1
BaseQuantities - Length: 5469.58 mm; OuterSurfaceArea: 4.40301 m2; NetVolume: 0.0228191 m3; NetWeight: 179.13 kg

# IfcColumn: L60*3, BEAM
In: Undefined
Description: L60*3; Material: STEEL/S235
Tekla Quantity - Weight: 0.2 kg; Volume: 0 m3; Gross footprint area: 0 m2; Area per tons: 90.3 m2; Net surface area: 0 m2; Height: 60 mm; Width: 60 mm; Length: 80 mm
Tekla Common - Bottom elevation: +13.874; Top elevation: +13.955; Phase: 1; Class: 1
Pset_ColumnCommon - LoadBearing: no; Reference: F18
BaseQuantities - Length: 80 mm; OuterSurfaceArea: 0.019902 m2; NetVolume: 0.00002808 m3; NetWeight: 0.220428 kg

# IfcColumn: L70*5 (2)
In: Undefined
Description: L70*5; Material: STEEL/S235
Tekla Common - Bottom elevation: +13.665; Top elevation: +13.785; Phase: 5; Class: 1
Tekla Quantity - Weight: 0.6 kg; Volume: 0 m3; Gross footprint area: 0 m2; Area per tons: 51.3 m2; Net surface area: 0 m2; Height: 70 mm; Width: 70 mm; Length: 120 mm
Pset_ColumnCommon - LoadBearing: no; Reference: F20
BaseQuantities - Length: 120 mm; OuterSurfaceArea: 0.03264 m2; NetVolume: 0.000081 m3; NetWeight: 0.63585 kg

# IfcColumn: L85*5 (2)
In: Undefined
Description: L85*5; Material: STEEL/S235
Tekla Common - Bottom elevation: +13.665; Top elevation: +13.785; Phase: 5; Class: 1
Tekla Quantity - Weight: 0.8 kg; Volume: 0 m3; Gross footprint area: 0 m2; Area per tons: 54.6 m2; Net surface area: 0 m2; Height: 85 mm; Width: 85 mm; Length: 120 mm
Pset_ColumnCommon - LoadBearing: no; Reference: F21
BaseQuantities - Length: 120 mm; OuterSurfaceArea: 0.04245 m2; NetVolume: 0.000099 m3; NetWeight: 0.77715 kg

# IfcColumn: RHS60*40*6, BEAM
In: Undefined
Description: RHS60*40*6; Material: STEEL/S235
Tekla Common - Bottom elevation: +13.880; Top elevation: +13.984; Phase: 3; Class: 4
Tekla Quantity - Weight: 0.8 kg; Volume: 0 m3; Gross footprint area: 0 m2; Area per tons: 25 m2; Net surface area: 0 m2; Height: 60 mm; Width: 40 mm; Length: 103.9 mm
Pset_ColumnCommon - LoadBearing: no; Reference: xx6
BaseQuantities - Length: 103.914 mm; OuterSurfaceArea: 0.0214944 m2; NetVolume: 0.000109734 m3; NetWeight: 0.861409 kg

# IfcColumn: SHS100*8 (3)
In: Undefined
Description: SHS100*8; Material: STEEL/S235
Tekla Common - Bottom elevation: +12.882; Top elevation: +13.782; Phase: 2; Class: 4
Tekla Quantity - Weight: 20.8 kg; Volume: 0 m3; Gross footprint area: 0 m2; Area per tons: 17.5 m2; Net surface area: 0.4 m2; Height: 100 mm; Width: 100 mm; Length: 900 mm
Pset_ColumnCommon - LoadBearing: no; Reference: B11
BaseQuantities - Length: 900 mm; OuterSurfaceArea: 0.3632 m2; NetVolume: 0.0026496 m3; NetWeight: 20.7994 kg

# IfcColumn: SHS50*3 (5)
In: Undefined
Description: SHS50*3; Material: STEEL/S235
Tekla Quantity - Volume: 0 m3; Gross footprint area: 0 m2; Area per tons: 45.3 m2; Net surface area: 0.2 m2; Height: 50 mm; Width: 50 mm
Pset_ColumnCommon - LoadBearing: yes
Name | Bottom elevation | Top elevation | Phase | Class | Weight (kg) | Tekla Quantity, Length (mm) = BaseQuantities, Length (mm) | Reference | OuterSurfaceArea (m2) | NetVolume (m3) | NetWeight (kg)
STANCHION | +13.665 | +14.845 | 5 | 10 | 5.2 | 1180 | fb24 | 0.2366 | 0.00066552 | 5.22433
STANCHION | +13.765 | +14.850 | 5 | 4 | 4.9 | 1085 | xx46 | 0.2176 | 0.00061194 | 4.80373
STANCHION | +13.795 | +14.850 | 5 | 4 | 4.6 | 1055 | xx44 | 0.2116 | 0.00059502 | 4.67091
STANCHION | +13.795 | +14.900 | 5 | 4 | 4.9 | 1105 | xx41 | 0.216724 | 0.00060912 | 4.78159
STANCHION | +12.575 | +13.615 | 3 | 10 | 4.6 | 1040 | fb13 | 0.2086 | 0.00058656 | 4.6045

# IfcDiscreteAccessory: ANGLE (168)
In: Undefined
Tekla Quantity - Volume: 0 m3; Gross footprint area: 0 m2; Net surface area: 0 m2
Pset_PlateCommon - LoadBearing: yes
Name | Description | Material | Bottom elevation | Top elevation | Phase | Class | Weight (kg) | Area per tons (m2) | Height (mm) | Width (mm) | Length (mm) | Reference | NetArea (m2) | GrossArea (m2) | CrossSectionArea (m2) | NetVolume (m3) | GrossVolume (m3)
ANGLE | BL85X10 | STEEL/S355 | +13.796 | +13.916 | 1 | 99 | 0.8 | 30.6 | 85 | 10 | 120 | k125 | 0.0245 | 0.0245 | 0.00085 | 0.000102 | 0.000102
ANGLE | BL85X10 | STEEL/S355 | +13.786 | +13.906 | 1 | 99 | 0.8 | 30.6 | 85 | 10 | 120 | k125 | 0.0245 | 0.0245 | 0.00085 | 0.000102 | 0.000102
ANGLE | BL85X10 | STEEL/S355 | +13.776 | +13.896 | 1 | 99 | 0.8 | 30.6 | 85 | 10 | 120 | k125 | 0.0245 | 0.0245 | 0.00085 | 0.000102 | 0.000102
ANGLE | BL85X10 | STEEL/S355 | +13.766 | +13.886 | 1 | 99 | 0.8 | 30.6 | 85 | 10 | 120 | k125 | 0.0245 | 0.0245 | 0.00085 | 0.000102 | 0.000102
2 x ANGLE | 3*30 | STEEL/S235JR | +13.823 | +13.853 | 3 | 1 | 0.2 | 94.5 | 3 | 30 | 300 | bs5 | 0.0190273 | 0.01998 | 0.00009 | 0.00002565 | 0.000027
2 x ANGLE | 3*30 | STEEL/S235JR | +13.676 | +13.706 | 3 | 1 | 0.2 | 94.5 | 3 | 30 | 300 | bs5 | 0.0190273 | 0.01998 | 0.00009 | 0.00002565 | 0.000027
2 x ANGLE | 3*30 | STEEL/S235JR | +13.528 | +13.558 | 3 | 1 | 0.2 | 94.5 | 3 | 30 | 300 | bs5 | 0.0190273 | 0.01998 | 0.00009 | 0.00002565 | 0.000027
2 x ANGLE | 3*30 | STEEL/S235JR | +13.381 | +13.411 | 3 | 1 | 0.2 | 94.5 | 3 | 30 | 300 | bs5 | 0.0190273 | 0.01998 | 0.00009 | 0.00002565 | 0.000027
2 x ANGLE | 3*30 | STEEL/S235JR | +13.233 | +13.263 | 3 | 1 | 0.2 | 94.5 | 3 | 30 | 300 | bs5 | 0.0190273 | 0.01998 | 0.00009 | 0.00002565 | 0.000027
2 x ANGLE | 3*30 | STEEL/S235JR | +13.086 | +13.116 | 3 | 1 | 0.2 | 94.5 | 3 | 30 | 300 | bs5 | 0.0190273 | 0.01998 | 0.00009 | 0.00002565 | 0.000027
2 x ANGLE | 3*30 | STEEL/S235JR | +12.939 | +12.969 | 3 | 1 | 0.2 | 94.5 | 3 | 30 | 300 | bs5 | 0.0190273 | 0.01998 | 0.00009 | 0.00002565 | 0.000027
2 x ANGLE | 3*30 | STEEL/S235JR | +12.791 | +12.821 | 3 | 1 | 0.2 | 94.5 | 3 | 30 | 300 | bs5 | 0.0190273 | 0.01998 | 0.00009 | 0.00002565 | 0.000027
2 x ANGLE | 3*30 | STEEL/S235JR | +12.644 | +12.674 | 3 | 1 | 0.2 | 94.5 | 3 | 30 | 300 | bs5 | 0.0190273 | 0.01998 | 0.00009 | 0.00002565 | 0.000027
2 x ANGLE | 3*40 | STEEL/S235JR | +13.810 | +13.850 | 2 | 1 | 0.3 | 92.1 | 3 | 40 | 300 | bs2 | 0.02604 | 0.02604 | 0.00012 | 0.000036 | 0.000036
2 x ANGLE | 3*40 | STEEL/S235JR | +13.660 | +13.700 | 2 | 1 | 0.3 | 92.1 | 3 | 40 | 300 | bs2 | 0.02604 | 0.02604 | 0.00012 | 0.000036 | 0.000036
2 x ANGLE | 3*40 | STEEL/S235JR | +13.510 | +13.550 | 2 | 1 | 0.3 | 92.1 | 3 | 40 | 300 | bs2 | 0.02604 | 0.02604 | 0.00012 | 0.000036 | 0.000036
2 x ANGLE | 3*40 | STEEL/S235JR | +13.360 | +13.400 | 2 | 1 | 0.3 | 92.1 | 3 | 40 | 300 | bs2 | 0.02604 | 0.02604 | 0.00012 | 0.000036 | 0.000036
2 x ANGLE | 3*40 | STEEL/S235JR | +13.210 | +13.250 | 2 | 1 | 0.3 | 92.1 | 3 | 40 | 300 | bs2 | 0.02604 | 0.02604 | 0.00012 | 0.000036 | 0.000036
2 x ANGLE | 3*40 | STEEL/S235JR | +13.060 | +13.100 | 2 | 1 | 0.3 | 92.1 | 3 | 40 | 300 | bs2 | 0.02604 | 0.02604 | 0.00012 | 0.000036 | 0.000036
2 x ANGLE | 3*40 | STEEL/S235JR | +12.910 | +12.950 | 2 | 1 | 0.3 | 92.1 | 3 | 40 | 300 | bs2 | 0.02604 | 0.02604 | 0.00012 | 0.000036 | 0.000036
2 x ANGLE | 3*40 | STEEL/S235JR | +12.760 | +12.800 | 2 | 1 | 0.3 | 92.1 | 3 | 40 | 300 | bs2 | 0.02604 | 0.02604 | 0.00012 | 0.000036 | 0.000036
2 x ANGLE | 3*40 | STEEL/S235JR | +12.610 | +12.650 | 2 | 1 | 0.3 | 92.1 | 3 | 40 | 300 | bs2 | 0.02604 | 0.02604 | 0.00012 | 0.000036 | 0.000036
2 x ANGLE | 3*40 | STEEL/S235JR | +12.460 | +12.500 | 2 | 1 | 0.3 | 92.1 | 3 | 40 | 300 | bs2 | 0.02604 | 0.02604 | 0.00012 | 0.000036 | 0.000036
2 x ANGLE | 3*40 | STEEL/S235JR | +12.310 | +12.350 | 2 | 1 | 0.3 | 92.1 | 3 | 40 | 300 | bs2 | 0.02604 | 0.02604 | 0.00012 | 0.000036 | 0.000036
2 x ANGLE | 3*40 | STEEL/S235JR | +12.160 | +12.200 | 2 | 1 | 0.3 | 92.1 | 3 | 40 | 300 | bs2 | 0.02604 | 0.02604 | 0.00012 | 0.000036 | 0.000036
2 x ANGLE | 3*40 | STEEL/S235JR | +12.010 | +12.050 | 2 | 1 | 0.3 | 92.1 | 3 | 40 | 300 | bs2 | 0.02604 | 0.02604 | 0.00012 | 0.000036 | 0.000036
2 x ANGLE | 3*40 | STEEL/S235JR | +11.860 | +11.900 | 2 | 1 | 0.3 | 92.1 | 3 | 40 | 300 | bs2 | 0.02604 | 0.02604 | 0.00012 | 0.000036 | 0.000036
2 x ANGLE | 3*40 | STEEL/S235JR | +11.710 | +11.750 | 2 | 1 | 0.3 | 92.1 | 3 | 40 | 300 | bs2 | 0.02604 | 0.02604 | 0.00012 | 0.000036 | 0.000036
2 x ANGLE | 3*40 | STEEL/S235JR | +11.560 | +11.600 | 2 | 1 | 0.3 | 92.1 | 3 | 40 | 300 | bs2 | 0.02604 | 0.02604 | 0.00012 | 0.000036 | 0.000036
2 x ANGLE | 3*40 | STEEL/S235JR | +11.410 | +11.450 | 2 | 1 | 0.3 | 92.1 | 3 | 40 | 300 | bs2 | 0.02604 | 0.02604 | 0.00012 | 0.000036 | 0.000036
2 x ANGLE | 3*40 | STEEL/S235JR | +11.260 | +11.300 | 2 | 1 | 0.3 | 92.1 | 3 | 40 | 300 | bs2 | 0.02604 | 0.02604 | 0.00012 | 0.000036 | 0.000036
2 x ANGLE | 3*40 | STEEL/S235JR | +11.110 | +11.150 | 2 | 1 | 0.3 | 92.1 | 3 | 40 | 300 | bs2 | 0.02604 | 0.02604 | 0.00012 | 0.000036 | 0.000036
2 x ANGLE | 3*40 | STEEL/S235JR | +10.960 | +11.000 | 2 | 1 | 0.3 | 92.1 | 3 | 40 | 300 | bs2 | 0.02604 | 0.02604 | 0.00012 | 0.000036 | 0.000036
2 x ANGLE | 3*40 | STEEL/S235JR | +10.810 | +10.850 | 2 | 1 | 0.3 | 92.1 | 3 | 40 | 300 | bs2 | 0.02604 | 0.02604 | 0.00012 | 0.000036 | 0.000036
2 x ANGLE | 3*40 | STEEL/S235JR | +10.660 | +10.700 | 2 | 1 | 0.3 | 92.1 | 3 | 40 | 300 | bs2 | 0.02604 | 0.02604 | 0.00012 | 0.000036 | 0.000036
2 x ANGLE | 3*40 | STEEL/S235JR | +10.510 | +10.550 | 2 | 1 | 0.3 | 92.1 | 3 | 40 | 300 | bs2 | 0.02604 | 0.02604 | 0.00012 | 0.000036 | 0.000036
2 x ANGLE | 3*40 | STEEL/S235JR | +10.360 | +10.400 | 2 | 1 | 0.3 | 92.1 | 3 | 40 | 300 | bs2 | 0.02604 | 0.02604 | 0.00012 | 0.000036 | 0.000036
2 x ANGLE | 3*40 | STEEL/S235JR | +10.210 | +10.250 | 2 | 1 | 0.3 | 92.1 | 3 | 40 | 300 | bs2 | 0.02604 | 0.02604 | 0.00012 | 0.000036 | 0.000036
2 x ANGLE | 3*40 | STEEL/S235JR | +10.060 | +10.100 | 2 | 1 | 0.3 | 92.1 | 3 | 40 | 300 | bs2 | 0.02604 | 0.02604 | 0.00012 | 0.000036 | 0.000036
2 x ANGLE | 3*40 | STEEL/S235JR | +9.910 | +9.950 | 2 | 1 | 0.3 | 92.1 | 3 | 40 | 300 | bs2 | 0.02604 | 0.02604 | 0.00012 | 0.000036 | 0.000036
2 x ANGLE | 3*40 | STEEL/S235JR | +9.760 | +9.800 | 2 | 1 | 0.3 | 92.1 | 3 | 40 | 300 | bs2 | 0.02604 | 0.02604 | 0.00012 | 0.000036 | 0.000036
2 x ANGLE | 3*40 | STEEL/S235JR | +9.610 | +9.650 | 2 | 1 | 0.3 | 92.1 | 3 | 40 | 300 | bs2 | 0.02604 | 0.02604 | 0.00012 | 0.000036 | 0.000036
2 x ANGLE | 3*40 | STEEL/S235JR | +9.460 | +9.500 | 2 | 1 | 0.3 | 92.1 | 3 | 40 | 300 | bs2 | 0.02604 | 0.02604 | 0.00012 | 0.000036 | 0.000036
2 x ANGLE | 3*40 | STEEL/S235JR | +9.310 | +9.350 | 2 | 1 | 0.3 | 92.1 | 3 | 40 | 300 | bs2 | 0.02604 | 0.02604 | 0.00012 | 0.000036 | 0.000036
2 x ANGLE | 3*40 | STEEL/S235JR | +9.160 | +9.200 | 2 | 1 | 0.3 | 92.1 | 3 | 40 | 300 | bs2 | 0.02604 | 0.02604 | 0.00012 | 0.000036 | 0.000036
2 x ANGLE | 3*40 | STEEL/S235JR | +9.010 | +9.050 | 2 | 1 | 0.3 | 92.1 | 3 | 40 | 300 | bs2 | 0.02604 | 0.02604 | 0.00012 | 0.000036 | 0.000036
2 x ANGLE | 3*40 | STEEL/S235JR | +8.860 | +8.900 | 2 | 1 | 0.3 | 92.1 | 3 | 40 | 300 | bs2 | 0.02604 | 0.02604 | 0.00012 | 0.000036 | 0.000036
2 x ANGLE | 3*40 | STEEL/S235JR | +8.710 | +8.750 | 2 | 1 | 0.3 | 92.1 | 3 | 40 | 300 | bs2 | 0.02604 | 0.02604 | 0.00012 | 0.000036 | 0.000036
2 x ANGLE | 3*40 | STEEL/S235JR | +8.560 | +8.600 | 2 | 1 | 0.3 | 92.1 | 3 | 40 | 300 | bs2 | 0.02604 | 0.02604 | 0.00012 | 0.000036 | 0.000036
2 x ANGLE | 3*40 | STEEL/S235JR | +8.410 | +8.450 | 2 | 1 | 0.3 | 92.1 | 3 | 40 | 300 | bs2 | 0.02604 | 0.02604 | 0.00012 | 0.000036 | 0.000036
2 x ANGLE | 3*40 | STEEL/S235JR | +8.260 | +8.300 | 2 | 1 | 0.3 | 92.1 | 3 | 40 | 300 | bs2 | 0.02604 | 0.02604 | 0.00012 | 0.000036 | 0.000036
2 x ANGLE | 3*40 | STEEL/S235JR | +8.110 | +8.150 | 2 | 1 | 0.3 | 92.1 | 3 | 40 | 300 | bs2 | 0.02604 | 0.02604 | 0.00012 | 0.000036 | 0.000036
2 x ANGLE | 3*40 | STEEL/S235JR | +7.960 | +8.000 | 2 | 1 | 0.3 | 92.1 | 3 | 40 | 300 | bs2 | 0.02604 | 0.02604 | 0.00012 | 0.000036 | 0.000036
2 x ANGLE | 3*40 | STEEL/S235JR | +7.810 | +7.850 | 2 | 1 | 0.3 | 92.1 | 3 | 40 | 300 | bs2 | 0.02604 | 0.02604 | 0.00012 | 0.000036 | 0.000036
2 x ANGLE | 3*40 | STEEL/S235JR | +7.660 | +7.700 | 2 | 1 | 0.3 | 92.1 | 3 | 40 | 300 | bs2 | 0.02604 | 0.02604 | 0.00012 | 0.000036 | 0.000036
2 x ANGLE | 3*40 | STEEL/S235JR | +7.510 | +7.550 | 2 | 1 | 0.3 | 92.1 | 3 | 40 | 300 | bs2 | 0.02604 | 0.02604 | 0.00012 | 0.000036 | 0.000036
2 x ANGLE | 3*40 | STEEL/S235JR | +7.360 | +7.400 | 2 | 1 | 0.3 | 92.1 | 3 | 40 | 300 | bs2 | 0.02604 | 0.02604 | 0.00012 | 0.000036 | 0.000036
2 x ANGLE | 3*40 | STEEL/S235JR | +7.210 | +7.250 | 2 | 1 | 0.3 | 92.1 | 3 | 40 | 300 | bs2 | 0.02604 | 0.02604 | 0.00012 | 0.000036 | 0.000036
2 x ANGLE | 3*40 | STEEL/S235JR | +7.060 | +7.100 | 2 | 1 | 0.3 | 92.1 | 3 | 40 | 300 | bs2 | 0.02604 | 0.02604 | 0.00012 | 0.000036 | 0.000036
2 x ANGLE | 3*40 | STEEL/S235JR | +6.910 | +6.950 | 2 | 1 | 0.3 | 92.1 | 3 | 40 | 300 | bs2 | 0.02604 | 0.02604 | 0.00012 | 0.000036 | 0.000036
2 x ANGLE | 3*40 | STEEL/S235JR | +6.760 | +6.800 | 2 | 1 | 0.3 | 92.1 | 3 | 40 | 300 | bs2 | 0.02604 | 0.02604 | 0.00012 | 0.000036 | 0.000036
2 x ANGLE | 3*40 | STEEL/S235JR | +6.610 | +6.650 | 2 | 1 | 0.3 | 92.1 | 3 | 40 | 300 | bs2 | 0.02604 | 0.02604 | 0.00012 | 0.000036 | 0.000036
2 x ANGLE | 3*40 | STEEL/S235JR | +6.460 | +6.500 | 2 | 1 | 0.3 | 92.1 | 3 | 40 | 300 | bs2 | 0.02604 | 0.02604 | 0.00012 | 0.000036 | 0.000036
2 x ANGLE | 3*40 | STEEL/S235JR | +6.310 | +6.350 | 2 | 1 | 0.3 | 92.1 | 3 | 40 | 300 | bs2 | 0.02604 | 0.02604 | 0.00012 | 0.000036 | 0.000036
2 x ANGLE | 3*40 | STEEL/S235JR | +6.160 | +6.200 | 2 | 1 | 0.3 | 92.1 | 3 | 40 | 300 | bs2 | 0.02604 | 0.02604 | 0.00012 | 0.000036 | 0.000036
2 x ANGLE | 3*40 | STEEL/S235JR | +6.010 | +6.050 | 2 | 1 | 0.3 | 92.1 | 3 | 40 | 300 | bs2 | 0.02604 | 0.02604 | 0.00012 | 0.000036 | 0.000036
2 x ANGLE | 3*40 | STEEL/S235JR | +5.860 | +5.900 | 2 | 1 | 0.3 | 92.1 | 3 | 40 | 300 | bs2 | 0.02604 | 0.02604 | 0.00012 | 0.000036 | 0.000036
2 x ANGLE | 3*40 | STEEL/S235JR | +5.710 | +5.750 | 2 | 1 | 0.3 | 92.1 | 3 | 40 | 300 | bs2 | 0.02604 | 0.02604 | 0.00012 | 0.000036 | 0.000036
2 x ANGLE | 3*40 | STEEL/S235JR | +5.560 | +5.600 | 2 | 1 | 0.3 | 92.1 | 3 | 40 | 300 | bs2 | 0.02604 | 0.02604 | 0.00012 | 0.000036 | 0.000036
2 x ANGLE | 3*40 | STEEL/S235JR | +5.410 | +5.450 | 2 | 1 | 0.3 | 92.1 | 3 | 40 | 300 | bs2 | 0.02604 | 0.02604 | 0.00012 | 0.000036 | 0.000036
2 x ANGLE | 3*40 | STEEL/S235JR | +5.260 | +5.300 | 2 | 1 | 0.3 | 92.1 | 3 | 40 | 300 | bs2 | 0.02604 | 0.02604 | 0.00012 | 0.000036 | 0.000036
2 x ANGLE | 3*40 | STEEL/S235JR | +5.110 | +5.150 | 2 | 1 | 0.3 | 92.1 | 3 | 40 | 300 | bs2 | 0.02604 | 0.02604 | 0.00012 | 0.000036 | 0.000036
2 x ANGLE | 3*40 | STEEL/S235JR | +4.960 | +5.000 | 2 | 1 | 0.3 | 92.1 | 3 | 40 | 300 | bs2 | 0.02604 | 0.02604 | 0.00012 | 0.000036 | 0.000036
2 x ANGLE | 3*40 | STEEL/S235JR | +4.810 | +4.850 | 2 | 1 | 0.3 | 92.1 | 3 | 40 | 300 | bs2 | 0.02604 | 0.02604 | 0.00012 | 0.000036 | 0.000036
2 x ANGLE | 3*40 | STEEL/S235JR | +4.660 | +4.700 | 2 | 1 | 0.3 | 92.1 | 3 | 40 | 300 | bs2 | 0.02604 | 0.02604 | 0.00012 | 0.000036 | 0.000036
2 x ANGLE | 3*40 | STEEL/S235JR | +4.510 | +4.550 | 2 | 1 | 0.3 | 92.1 | 3 | 40 | 300 | bs2 | 0.02604 | 0.02604 | 0.00012 | 0.000036 | 0.000036
2 x ANGLE | 3*40 | STEEL/S235JR | +4.360 | +4.400 | 2 | 1 | 0.3 | 92.1 | 3 | 40 | 300 | bs2 | 0.02604 | 0.02604 | 0.00012 | 0.000036 | 0.000036
2 x ANGLE | 3*40 | STEEL/S235JR | +4.210 | +4.250 | 2 | 1 | 0.3 | 92.1 | 3 | 40 | 300 | bs2 | 0.02604 | 0.02604 | 0.00012 | 0.000036 | 0.000036
2 x ANGLE | 3*40 | STEEL/S235JR | +4.060 | +4.100 | 2 | 1 | 0.3 | 92.1 | 3 | 40 | 300 | bs2 | 0.02604 | 0.02604 | 0.00012 | 0.000036 | 0.000036
2 x ANGLE | 3*40 | STEEL/S235JR | +3.910 | +3.950 | 2 | 1 | 0.3 | 92.1 | 3 | 40 | 300 | bs2 | 0.02604 | 0.02604 | 0.00012 | 0.000036 | 0.000036
2 x ANGLE | 3*40 | STEEL/S235JR | +3.760 | +3.800 | 2 | 1 | 0.3 | 92.1 | 3 | 40 | 300 | bs2 | 0.02604 | 0.02604 | 0.00012 | 0.000036 | 0.000036
2 x ANGLE | 3*40 | STEEL/S235JR | +3.610 | +3.650 | 2 | 1 | 0.3 | 92.1 | 3 | 40 | 300 | bs2 | 0.02604 | 0.02604 | 0.00012 | 0.000036 | 0.000036
2 x ANGLE | 3*40 | STEEL/S235JR | +3.460 | +3.500 | 2 | 1 | 0.3 | 92.1 | 3 | 40 | 300 | bs2 | 0.02604 | 0.02604 | 0.00012 | 0.000036 | 0.000036
2 x ANGLE | 3*40 | STEEL/S235JR | +3.310 | +3.350 | 2 | 1 | 0.3 | 92.1 | 3 | 40 | 300 | bs2 | 0.02604 | 0.02604 | 0.00012 | 0.000036 | 0.000036
2 x ANGLE | 3*40 | STEEL/S235JR | +3.160 | +3.200 | 2 | 1 | 0.3 | 92.1 | 3 | 40 | 300 | bs2 | 0.02604 | 0.02604 | 0.00012 | 0.000036 | 0.000036
2 x ANGLE | 3*40 | STEEL/S235JR | +3.010 | +3.050 | 2 | 1 | 0.3 | 92.1 | 3 | 40 | 300 | bs2 | 0.02604 | 0.02604 | 0.00012 | 0.000036 | 0.000036

# IfcDiscreteAccessory: BEAM (311)
In: Undefined
Tekla Quantity - Volume: 0 m3
Name | Description | Material | Bottom elevation | Top elevation | Phase | Class | Weight (kg) | Gross footprint area (m2) | Area per tons (m2) | Net surface area (m2) | Height (mm) | Width (mm) | Length (mm) | LoadBearing | Reference | NetArea (m2) | GrossArea (m2) | CrossSectionArea (m2) | NetVolume (m3) | GrossVolume (m3)
BEAM | SHS40*3 | STEEL/S355 | +13.976 | +14.016 | 2 | 5 | 2.8 | 0 | 46.3 | 0.1 | 40 | 40 | 870.2 | no | k165 | 0.12789 | 0.150187 | 0.00041866 | 0.000351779 | 0.000414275
BEAM | SHS40*3 | STEEL/S355 | +13.976 | +14.016 | 2 | 5 | 3.1 | 0 | 46.1 | 0.1 | 40 | 40 | 934.4 | no | k164 | 0.144613 | 0.150248 | 0.00041866 | 0.000399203 | 0.000415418
2 x BEAM | SHS40*3 | STEEL/S355 | +13.976 | +14.016 | 2 | 5 | 3.1 | 0 | 46.1 | 0.1 | 40 | 40 | 934.4 | no | k163 | 0.144754 | 0.150248 | 0.00041866 | 0.000399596 | 0.000415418
BEAM | SHS60*3 | STEEL/S355 | +13.404 | +13.465 | 1 | 6 | 0.5 | 0 | 46.1 | 0 | 60 | 60 | 92.6 | yes | k64 | 0.0229558 | 0.0229558 | 0.00065866 | 0.000063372 | 0.000063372
2 x BEAM | SHS60*3 | STEEL/S355 | +12.956 | +13.740 | 1 | 6 | 3.9 | 0 | 45 | 0.2 | 60 | 60 | 783.8 | yes | k63 | 0.175495 | 0.175495 | 0.00065866 | 0.000497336 | 0.000497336
2 x BEAM | SHS60*3 | STEEL/S355 | +12.778 | +13.788 | 1 | 6 | 7.3 | 0 | 44.8 | 0.4 | 60 | 60 | 1427.5 | no | k62 | 0.327359 | 0.327359 | 0.00065866 | 0.000929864 | 0.000929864
BEAM | SHS60*3 | STEEL/S355 | +12.854 | +13.809 | 1 | 6 | 6.9 | 0 | 45 | 0.4 | 60 | 60 | 1349 | no | k56 | 0.308515 | 0.308515 | 0.00065866 | 0.000876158 | 0.000876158
BEAM | SHS60*3 | STEEL/S355 | +12.816 | +13.770 | 1 | 6 | 6.9 | 0 | 45 | 0.4 | 60 | 60 | 1349 | no | k56 | 0.308515 | 0.308515 | 0.00065866 | 0.000876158 | 0.000876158
BEAM | C70*40*4 | STEEL/S235 | +13.910 | +13.980 | 2 | 6 | 3.4 | 0 | 65.8 | 0.2 | 70 | 40 | 755.8 | no | k158 | 0.220825 | 0.220825 | 0.000584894 | 0.000427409 | 0.000427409
4 x BEAM | SHS50*3 | STEEL/S355 | +13.976 | +14.026 | 2 | 12 | 3.6 | 0 | 45.3 | 0.2 | 50 | 50 | 820 | yes | k157 | 0.1646 | 0.1646 | 0.00053866 | 0.00046248 | 0.00046248
BEAM | SHS80*4 | STEEL/S355 | +13.946 | +14.026 | 2 | 14 | 7.8 | 0.1 | 33.7 | 0.4 | 80 | 80 | 820 | yes | k156 | 0.26368 | 0.26368 | 0.00117095 | 0.000997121 | 0.000997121
BEAM | SHS80*4 | STEEL/S355 | +13.777 | +14.026 | 2 | 7 | 1.9 | 0 | 34.4 | 0.1 | 80 | 80 | 249 | no | k155 | 0.0653445 | 0.0653445 | 0.00117095 | 0.000241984 | 0.000241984
2 x BEAM | RHS100*80*4 | STEEL/S355 | +13.926 | +14.026 | 2 | 14 | 36.4 | 0.3 | 33.2 | 1.2 | 100 | 80 | 3412 | no | k119 | 1.20993 | 1.20993 | 0.00133095 | 0.00463987 | 0.00463987
4 x BEAM | SHS50*3 | STEEL/S355 | +13.975 | +14.026 | 2 | 12 | 6.3 | 0.1 | 45.3 | 0.4 | 50 | 50 | 1415 | yes | k154 | 0.2836 | 0.2836 | 0.00053866 | 0.00079806 | 0.00079806
BEAM | SHS60*4 | STEEL/S355 | +13.311 | +13.926 | 2 | 9 | 4.2 | 0 | 34.4 | 0.1 | 60 | 60 | 614.9 | no | k152 | 0.144479 | 0.144479 | 0.00085095 | 0.000535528 | 0.000535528
BEAM | SHS60*4 | STEEL/S355 | +13.278 | +13.977 | 2 | 9 | 6.3 | 0 | 34.4 | 0.2 | 60 | 60 | 945.3 | no | k153 | 0.218908 | 0.232826 | 0.00085095 | 0.000812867 | 0.000864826
BEAM | SHS80*4 | STEEL/S355 | +12.878 | +14.026 | 2 | 7 | 10.3 | 0 | 33.7 | 0.4 | 80 | 80 | 1148 | no | k150 | 0.345751 | 0.345751 | 0.00117095 | 0.00130716 | 0.00130716
BEAM | SHS80*4 | STEEL/S355 | +12.785 | +13.926 | 2 | 7 | 21 | 0 | 33.6 | 0.7 | 80 | 80 | 2287.5 | yes | k148 | 0.704403 | 0.704403 | 0.00117095 | 0.00266905 | 0.00266905
BEAM | SHS60*4 | STEEL/S355 | +13.311 | +13.925 | 2 | 9 | 4.2 | 0 | 34.4 | 0.1 | 60 | 60 | 614.9 | no | k152 | 0.144479 | 0.144479 | 0.00085095 | 0.000535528 | 0.000535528
BEAM | SHS60*4 | STEEL/S355 | +13.277 | +13.925 | 2 | 9 | 6.2 | 0 | 34.4 | 0.2 | 60 | 60 | 909 | no | k151 | 0.21223 | 0.215857 | 0.00085095 | 0.000788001 | 0.000801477
BEAM | SHS80*4 | STEEL/S355 | +12.878 | +14.025 | 2 | 7 | 10.3 | 0 | 33.7 | 0.4 | 80 | 80 | 1148 | no | k150 | 0.345751 | 0.345751 | 0.00117095 | 0.00130716 | 0.00130716
BEAM | SHS100*5 | STEEL/S235 | +13.777 | +13.881 | 2 | 4 | 97.1 | 0 | 26.8 | 2.6 | 100 | 100 | 6524.6 | no | xx42 | 2.60651 | 2.60651 | 0.00182961 | 0.0123713 | 0.0123713
BEAM | SHS100*5 | STEEL/S235 | +12.777 | +12.881 | 2 | 4 | 97.1 | 0 | 26.8 | 2.6 | 100 | 100 | 6524.1 | no | xx42 | 2.6063 | 2.6063 | 0.00182961 | 0.0123703 | 0.0123703
BEAM | SHS80*4 | STEEL/S355 | +12.785 | +13.925 | 2 | 7 | 21 | 0 | 33.6 | 0.7 | 80 | 80 | 2287.5 | yes | k148 | 0.704403 | 0.704403 | 0.00117095 | 0.00266905 | 0.00266905
BEAM | SHS80*4 | STEEL/S355 | +13.945 | +14.026 | 2 | 14 | 13.5 | 0.1 | 33.6 | 0.4 | 80 | 80 | 1415 | yes | k147 | 0.45408 | 0.45408 | 0.00117095 | 0.00172064 | 0.00172064
BEAM | L40*60*6 | STEEL/S235 | +13.984 | +14.024 | 3 | 4 | 29 | 0 | 45.2 | 1.2 | 40 | 60 | 6559.4 | no | xx69 | 1.3119 | 1.3119 | 0.000583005 | 0.00369642 | 0.00369642
2 x BEAM | SHS60*3 | STEEL/S235 | +15.884 | +16.284 | 5 | 12 | 2.7 | 0 | 45.1 | 0.1 | 60 | 60 | 565.7 | no | k133 | 0.122383 | 0.122383 | 0.00065866 | 0.000345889 | 0.000345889
2 x BEAM | SHS60*3 | STEEL/S235 | +16.060 | +16.460 | 5 | 12 | 2.7 | 0 | 45.1 | 0.1 | 60 | 60 | 565.7 | no | k133 | 0.122383 | 0.122383 | 0.00065866 | 0.000345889 | 0.000345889
BEAM | L60*3 | STEEL/S235 | +13.870 | +13.951 | 1 | 1 | 0.2 | 0 | 90.3 | 0 | 60 | 60 | 80 | no | k127 | 0.019902 | 0.019902 | 0.000355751 | 0.00002808 | 0.00002808
BEAM | L60*3 | STEEL/S235 | +13.923 | +14.004 | 1 | 1 | 0.2 | 0 | 90.3 | 0 | 60 | 60 | 80 | no | k127 | 0.019902 | 0.019902 | 0.000355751 | 0.00002808 | 0.00002808
BEAM | K80/4 | STEEL/S355 | +13.578 | +13.799 | 1 | 2 | 1.9 | 0 | 33.6 | 0.1 | 80 | 80 | 220 | no | k126 | 0.0682 | 0.0682 | 0.001174 | 0.00026752 | 0.00025828
BEAM | K60/4 | STEEL/S355 | +13.796 | +13.865 | 1 | 9 | 10.3 | 0 | 34.4 | 0.4 | 60 | 60 | 1530.6 | no | k124 | 0.352031 | 0.352031 | 0.000854 | 0.00129769 | 0.0013071
BEAM | K60/4 | STEEL/S355 | +13.806 | +13.875 | 1 | 9 | 10.3 | 0 | 34.4 | 0.4 | 60 | 60 | 1530.6 | no | k124 | 0.352031 | 0.352031 | 0.000854 | 0.00129769 | 0.0013071
BEAM | K60/4 | STEEL/S355 | +13.816 | +13.886 | 1 | 9 | 10.3 | 0 | 34.4 | 0.4 | 60 | 60 | 1530.6 | no | k124 | 0.352031 | 0.352031 | 0.000854 | 0.00129769 | 0.0013071
BEAM | RHS100*60*3 | STEEL/S355 | +12.785 | +13.776 | 1 | 7 | 12.2 | 0 | 43.9 | 0.4 | 100 | 60 | 1784.8 | yes | k123 | 0.533737 | 0.549948 | 0.00089866 | 0.00154901 | 0.00159646
BEAM | RHS100*60*3 | STEEL/S355 | +12.806 | +13.796 | 1 | 7 | 12.2 | 0 | 43.9 | 0.4 | 100 | 60 | 1784.7 | yes | k123 | 0.533735 | 0.549948 | 0.00089866 | 0.001549 | 0.00159646
BEAM | RHS120*60*3 | STEEL/S355 | +13.785 | +13.906 | 1 | 14 | 11.6 | 0 | 43.6 | 0.4 | 120 | 60 | 1425 | no | k118 | 0.509686 | 0.509686 | 0.00101866 | 0.0014877 | 0.0014877
BEAM | RHS120*60*3 | STEEL/S355 | +13.765 | +13.916 | 1 | 14 | 19.8 | 0 | 43.6 | 1 | 120 | 60 | 2475 | yes | k122 | 0.863484 | 0.863484 | 0.00101866 | 0.00252126 | 0.00252126
BEAM | RHS120*60*3 | STEEL/S355 | +13.765 | +13.886 | 1 | 14 | 11.9 | 0 | 43.7 | 0.4 | 120 | 60 | 1485 | no | k65 | 0.520616 | 0.520616 | 0.00101866 | 0.00151902 | 0.00151902
BEAM | RHS120*60*3 | STEEL/S355 | +13.775 | +13.896 | 1 | 14 | 11.6 | 0 | 43.6 | 0.4 | 120 | 60 | 1425 | no | k118 | 0.509686 | 0.509686 | 0.00101866 | 0.0014877 | 0.0014877
BEAM | SHS80*4 | STEEL/S235 | +13.808 | +16.460 | 5 | 12 | 25.3 | 0 | 33.6 | 0.7 | 80 | 80 | 2651.8 | yes | k115 | 0.849859 | 0.849859 | 0.00117095 | 0.0032246 | 0.0032246
2 x BEAM | SHS80*4 | STEEL/S235 | +13.808 | +16.284 | 5 | 12 | 23.6 | 0 | 33.6 | 0.7 | 80 | 80 | 2475.8 | yes | k114 | 0.793539 | 0.793539 | 0.00117095 | 0.00301059 | 0.00301059
BEAM | SHS80*4 | STEEL/S235 | +13.807 | +16.460 | 5 | 12 | 25.3 | 0 | 33.6 | 1 | 80 | 80 | 2652.8 | yes | k115 | 0.850179 | 0.850179 | 0.00117095 | 0.00322582 | 0.00322582
BEAM | SHS50*4 | STEEL/S235 | +13.335 | +13.880 | 2 | 4 | 3.1 | 0 | 34.9 | 0.1 | 50 | 50 | 544.7 | yes | xx27 | 0.106916 | 0.106916 | 0.00069095 | 0.000390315 | 0.000390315
BEAM | SHS50*4 | STEEL/S235 | +12.780 | +13.860 | 2 | 4 | 12.9 | 0 | 34.7 | 0.4 | 50 | 50 | 2259.1 | yes | xx26 | 0.447086 | 0.447086 | 0.00069095 | 0.00164189 | 0.00164189
BEAM | SHS50*4 | STEEL/S235 | +13.830 | +13.980 | 2 | 4 | 0.6 | 0 | 36.3 | 0 | 50 | 50 | 150 | yes | xx25 | 0.0227703 | 0.0227703 | 0.00069095 | 0.0000799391 | 0.0000799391
BEAM | SHS50*4 | STEEL/S235 | +13.830 | +13.980 | 2 | 4 | 11.4 | 0 | 34.7 | 0.4 | 50 | 50 | 2005.3 | yes | xx41 | 0.396538 | 0.396538 | 0.00069095 | 0.00145565 | 0.00145565
BEAM | SHS80*4 | STEEL/S235 | +13.909 | +13.989 | 2 | 6 | 6.9 | 0.1 | 33.7 | 0.2 | 80 | 80 | 730.5 | no | k102 | 0.23471 | 0.23471 | 0.00117095 | 0.000887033 | 0.000887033
BEAM | SHS60*4 | STEEL/S235 | +13.344 | +13.851 | 2 | 6 | 3.4 | 0 | 34.4 | 0.1 | 60 | 60 | 506.2 | yes | k69 | 0.118368 | 0.118368 | 0.00085095 | 0.00043809 | 0.00043809
BEAM | SHS60*4 | STEEL/S235 | +12.787 | +13.908 | 2 | 6 | 16.4 | 0 | 34.2 | 0.7 | 60 | 60 | 2410 | yes | k68 | 0.560755 | 0.560755 | 0.00085095 | 0.00208719 | 0.00208719
BEAM | C80*40*3 | STEEL/S235 | +13.909 | +13.989 | 2 | 6 | 3.4 | 0 | 86.9 | 0.4 | 80 | 40 | 961 | no | k105 | 0.301727 | 0.301727 | 0.000471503 | 0.000442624 | 0.000442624
BEAM | SHS80*4 | STEEL/S235 | +13.909 | +13.989 | 2 | 6 | 6.9 | 0.1 | 33.7 | 0.2 | 80 | 80 | 730.5 | no | k102 | 0.234697 | 0.234697 | 0.00117095 | 0.000886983 | 0.000886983
BEAM | SHS60*4 | STEEL/S235 | +13.345 | +13.851 | 2 | 6 | 3.4 | 0 | 34.4 | 0.1 | 60 | 60 | 505.5 | yes | k69 | 0.118214 | 0.118214 | 0.00085095 | 0.000437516 | 0.000437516
BEAM | SHS60*4 | STEEL/S235 | +12.788 | +13.907 | 2 | 6 | 16.4 | 0 | 34.2 | 0.7 | 60 | 60 | 2408.8 | yes | k104 | 0.560452 | 0.560452 | 0.00085095 | 0.00208607 | 0.00208607
BEAM | RHS100*80*4 | STEEL/S235 | +13.925 | +14.025 | 2 | 6 | 5.6 | 0 | 33.3 | 0.2 | 100 | 80 | 519.1 | no | k51 | 0.186979 | 0.186979 | 0.00133095 | 0.000712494 | 0.000712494
BEAM | RHS100*80*4 | STEEL/S235 | +13.925 | +14.025 | 2 | 6 | 5.6 | 0 | 33.3 | 0.2 | 100 | 80 | 519.1 | no | k51 | 0.186979 | 0.186979 | 0.00133095 | 0.000712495 | 0.000712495
BEAM | SHS60*4 | STEEL/S235 | +13.344 | +13.830 | 2 | 6 | 3.3 | 0 | 34.4 | 0.1 | 60 | 60 | 486.3 | yes | k162 | 0.113604 | 0.113604 | 0.00085095 | 0.000420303 | 0.000420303
BEAM | SHS60*4 | STEEL/S235 | +12.787 | +13.885 | 2 | 6 | 16.1 | 0 | 34.2 | 0.4 | 60 | 60 | 2362.9 | yes | k50 | 0.549449 | 0.549449 | 0.00085095 | 0.00204499 | 0.00204499
BEAM | SHS60*4 | STEEL/S235 | +13.344 | +13.830 | 2 | 6 | 3.3 | 0 | 34.4 | 0.1 | 60 | 60 | 486.3 | yes | k162 | 0.113605 | 0.113605 | 0.00085095 | 0.000420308 | 0.000420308
BEAM | SHS60*4 | STEEL/S235 | +12.787 | +13.885 | 2 | 6 | 16.1 | 0 | 34.2 | 0.4 | 60 | 60 | 2362.9 | yes | k50 | 0.549452 | 0.549452 | 0.00085095 | 0.002045 | 0.002045
BEAM | SHS100*5 | STEEL/S235 | +13.781 | +13.882 | 2 | 4 | 97.1 | 0 | 26.8 | 2.6 | 100 | 100 | 6524.4 | no | xx63 | 2.60641 | 2.60641 | 0.00182961 | 0.0123708 | 0.0123708
BEAM | SHS100*5 | STEEL/S235 | +13.781 | +13.882 | 2 | 4 | 96.9 | 0 | 26.8 | 2.6 | 100 | 100 | 6524.6 | no | xx62 | 2.6012 | 2.6012 | 0.00182961 | 0.0123459 | 0.0123459
BEAM | SHS100*5 | STEEL/S235 | +12.781 | +12.882 | 2 | 4 | 97.1 | 0 | 26.8 | 2.6 | 100 | 100 | 6524.4 | no | xx61 | 2.60641 | 2.60641 | 0.00182961 | 0.0123708 | 0.0123708
BEAM | SHS60*4 | STEEL/S235 | +1.110 | +1.170 | 2 | 4 | 11.6 | 0.1 | 34.2 | 0.4 | 60 | 60 | 1700 | no | xx59 | 0.397459 | 0.401959 | 0.00085095 | 0.00147832 | 0.00149632
2 x BEAM | SHS60*4 | STEEL/S235 | +1.110 | +2.640 | 2 | 4 | 10.6 | 0 | 34.2 | 0.4 | 60 | 60 | 1530 | no | xx57 | 0.361159 | 0.361159 | 0.00085095 | 0.001344 | 0.001344
BEAM | SHS60*4 | STEEL/S235 | +1.110 | +1.170 | 2 | 4 | 11.6 | 0.1 | 34.2 | 0.4 | 60 | 60 | 1700 | no | xx58 | 0.397459 | 0.401959 | 0.00085095 | 0.00147832 | 0.00149632
BEAM | HEB120 | STEEL/S235 | +13.680 | +13.800 | 2 | 4 | 89.1 | 0 | 25.7 | 2.4 | 120 | 120 | 3340 | no | xx56 | 2.29124 | 2.29124 | 0.0034 | 0.0109452 | 0.011356
BEAM | HEB120 | STEEL/S235 | +12.140 | +13.800 | 2 | 4 | 44.3 | 0 | 25.7 | 1.2 | 120 | 120 | 1660 | no | xx45 | 1.13876 | 1.13876 | 0.0034 | 0.00543982 | 0.005644
BEAM | K80/4 | STEEL/S355 | +13.648 | +13.865 | 1 | 2 | 1.9 | 0 | 33.6 | 0.1 | 80 | 80 | 216 | no | k82 | 0.06696 | 0.06696 | 0.001174 | 0.000262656 | 0.000253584
BEAM | K80/4 | STEEL/S355 | +13.652 | +13.873 | 1 | 2 | 1.9 | 0 | 33.6 | 0.1 | 80 | 80 | 220 | no | k81 | 0.0682 | 0.0682 | 0.001174 | 0.00026752 | 0.00025828
BEAM | SHS60*3 | STEEL/S355 | +13.404 | +13.465 | 1 | 6 | 0.5 | 0 | 46.1 | 0 | 60 | 60 | 92.6 | yes | k64 | 0.0229558 | 0.0229558 | 0.00065866 | 0.0000633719 | 0.0000633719
BEAM | SHS60*3 | STEEL/S355 | +12.875 | +13.829 | 1 | 6 | 6.9 | 0 | 45 | 0.4 | 60 | 60 | 1348.3 | no | k56 | 0.308352 | 0.308352 | 0.00065866 | 0.000875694 | 0.000875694
BEAM | SHS60*3 | STEEL/S355 | +12.855 | +13.809 | 1 | 6 | 6.9 | 0 | 45 | 0.4 | 60 | 60 | 1348.3 | no | k56 | 0.308352 | 0.308352 | 0.00065866 | 0.000875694 | 0.000875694
BEAM | SHS60*3 | STEEL/S355 | +12.814 | +13.768 | 1 | 6 | 6.9 | 0 | 45 | 0.4 | 60 | 60 | 1348.3 | no | k56 | 0.308352 | 0.308352 | 0.00065866 | 0.000875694 | 0.000875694
BEAM | D10 | STEEL/S235 | +13.857 | +13.894 | 3 | 11 | 0.6 | 0 | 55.4 | 0 | 10 | 10 | 1047.8 | no | k77 | 0.0322196 | 0.0328319 | 0.0000707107 | 0.000074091 | 0.0000755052
BEAM | D10 | STEEL/S235 | +13.920 | +13.957 | 3 | 11 | 0.6 | 0 | 55.4 | 0 | 10 | 10 | 1047.8 | no | k77 | 0.0322196 | 0.0328319 | 0.0000707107 | 0.000074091 | 0.0000755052
BEAM | SHS50*4 | STEEL/S355 | +13.337 | +13.881 | 3 | 4 | 3.1 | 0 | 34.9 | 0.1 | 50 | 50 | 544.7 | yes | xx31 | 0.106916 | 0.106916 | 0.00069095 | 0.000390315 | 0.000390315
BEAM | SHS50*4 | STEEL/S355 | +12.781 | +13.862 | 3 | 4 | 12.9 | 0 | 34.7 | 0.4 | 50 | 50 | 2259.1 | yes | xx30 | 0.447075 | 0.447075 | 0.00069095 | 0.00164185 | 0.00164185
BEAM | SHS50*4 | STEEL/S355 | +13.831 | +13.981 | 3 | 4 | 0.6 | 0 | 36.3 | 0 | 50 | 50 | 150 | yes | xx29 | 0.0227703 | 0.0227703 | 0.00069095 | 0.0000799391 | 0.0000799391
BEAM | SHS50*4 | STEEL/S355 | +13.832 | +13.981 | 3 | 4 | 11.4 | 0 | 34.7 | 0.4 | 50 | 50 | 1995.1 | yes | xx28 | 0.394493 | 0.396243 | 0.00069095 | 0.00144812 | 0.00145457
BEAM | C80*40*3 | STEEL/S235 | +13.910 | +13.990 | 3 | 6 | 4.6 | 0.1 | 86.9 | 0.4 | 80 | 40 | 1304.5 | no | k76 | 0.409582 | 0.409582 | 0.000471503 | 0.000601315 | 0.000601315
BEAM | SHS80*4 | STEEL/S235 | +13.910 | +13.990 | 3 | 6 | 9.4 | 0.1 | 33.7 | 0.4 | 80 | 80 | 995 | no | k75 | 0.319375 | 0.319375 | 0.00117095 | 0.00120876 | 0.00120876
BEAM | SHS60*4 | STEEL/S235 | +13.345 | +13.852 | 3 | 6 | 3.4 | 0 | 34.4 | 0.1 | 60 | 60 | 506.2 | yes | k69 | 0.118381 | 0.118381 | 0.00085095 | 0.000438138 | 0.000438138
BEAM | SHS60*4 | STEEL/S235 | +12.788 | +13.909 | 3 | 6 | 16.4 | 0 | 34.2 | 0.7 | 60 | 60 | 2410.6 | yes | k68 | 0.560885 | 0.560885 | 0.00085095 | 0.00208768 | 0.00208768
3 x BEAM | SHS80*4 | STEEL/S235 | +13.910 | +13.990 | 3 | 6 | 9.2 | 0.1 | 33.7 | 0.4 | 80 | 80 | 974.8 | no | k71 | 0.312907 | 0.312907 | 0.00117095 | 0.00118418 | 0.00118418
3 x BEAM | SHS60*4 | STEEL/S235 | +13.344 | +13.851 | 3 | 6 | 3.4 | 0 | 34.4 | 0.1 | 60 | 60 | 506.2 | yes | k69 | 0.11838 | 0.11838 | 0.00085095 | 0.000438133 | 0.000438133
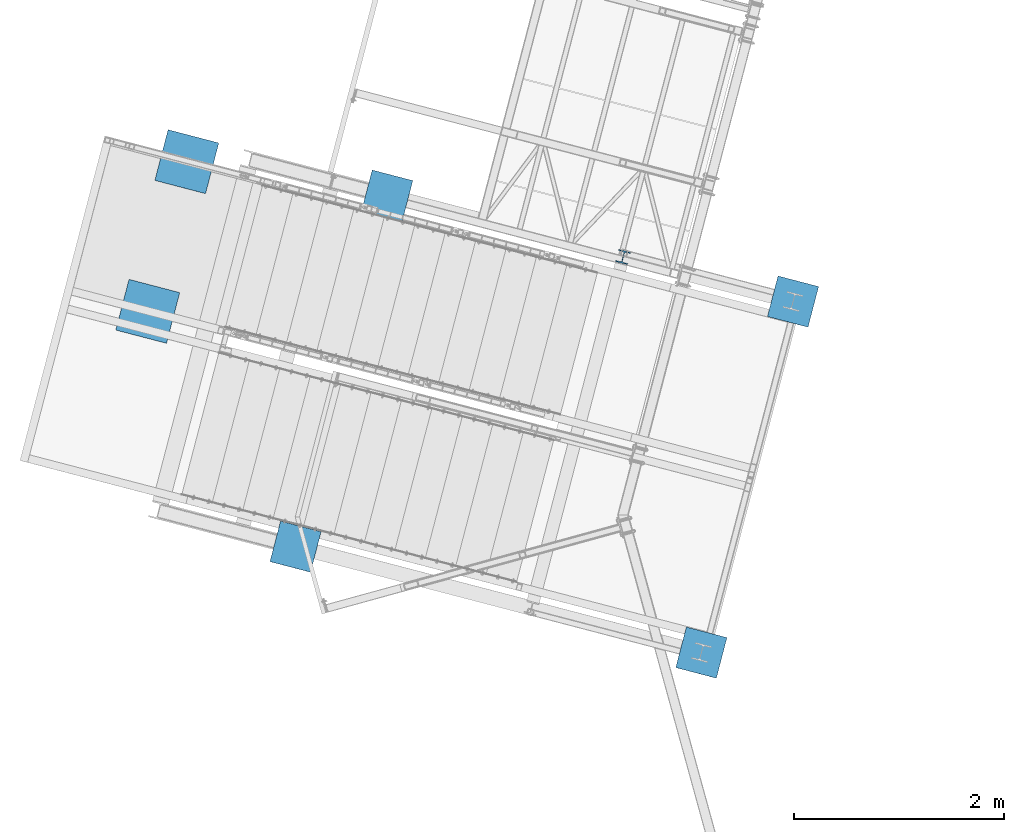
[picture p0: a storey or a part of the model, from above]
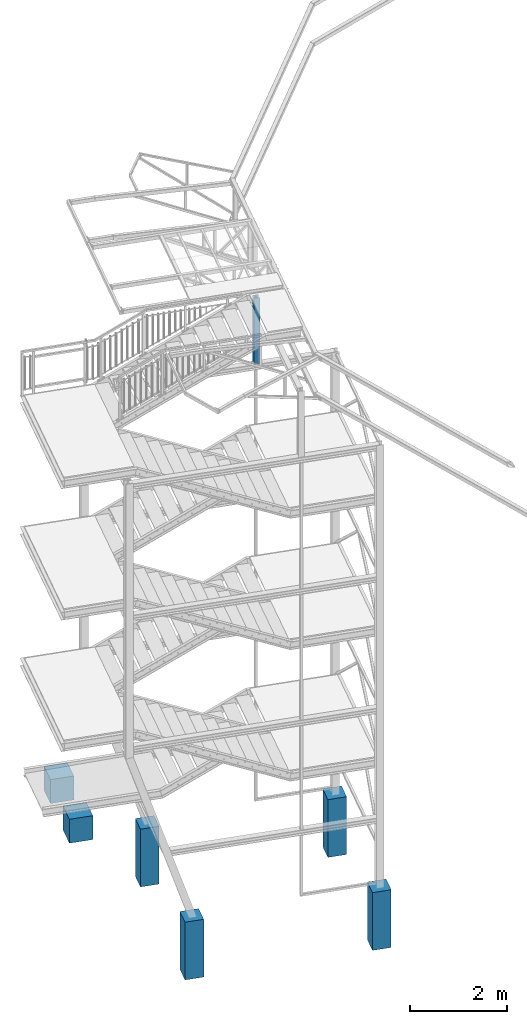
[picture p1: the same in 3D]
Properties of the parts of a building model (IFC2X3), part 2 of 5

# IfcDiscreteAccessory: BEAM (311)
Name | Description | Material | Bottom elevation | Top elevation | Phase | Class | Weight (kg) | Gross footprint area (m2) | Area per tons (m2) | Net surface area (m2) | Height (mm) | Width (mm) | Length (mm) | LoadBearing | Reference | NetArea (m2) | GrossArea (m2) | CrossSectionArea (m2) | NetVolume (m3) | GrossVolume (m3)
3 x BEAM | SHS60*4 | STEEL/S235 | +12.787 | +13.908 | 3 | 6 | 16.4 | 0 | 34.2 | 0.7 | 60 | 60 | 2410.6 | yes | k68 | 0.560869 | 0.560869 | 0.00085095 | 0.00208762 | 0.00208762
BEAM | SHS50*4 | STEEL/S235 | +13.336 | +13.880 | 3 | 4 | 3.1 | 0 | 34.9 | 0.1 | 50 | 50 | 544.7 | yes | xx27 | 0.106916 | 0.106916 | 0.00069095 | 0.000390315 | 0.000390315
BEAM | SHS50*4 | STEEL/S235 | +12.780 | +13.861 | 3 | 4 | 12.9 | 0 | 34.7 | 0.4 | 50 | 50 | 2259.1 | yes | xx26 | 0.447064 | 0.447064 | 0.00069095 | 0.00164181 | 0.00164181
BEAM | SHS50*4 | STEEL/S235 | +13.830 | +13.980 | 3 | 4 | 0.6 | 0 | 36.3 | 0 | 50 | 50 | 150 | yes | xx25 | 0.0227703 | 0.0227703 | 0.00069095 | 0.0000799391 | 0.0000799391
BEAM | SHS50*4 | STEEL/S235 | +13.831 | +13.980 | 3 | 4 | 11.4 | 0 | 34.7 | 0.4 | 50 | 50 | 2002.6 | yes | xx5 | 0.396243 | 0.396243 | 0.00069095 | 0.00145457 | 0.00145457
BEAM | SHS100*5 | STEEL/S235 | +12.781 | +12.881 | 3 | 4 | 97.7 | 0.7 | 26.8 | 2.6 | 100 | 100 | 6577.9 | no | xx24 | 2.62266 | 2.62266 | 0.00182961 | 0.0124475 | 0.0124475
BEAM | SHS100*5 | STEEL/S235 | +13.780 | +13.880 | 3 | 4 | 97.7 | 0.7 | 26.8 | 2.6 | 100 | 100 | 6577.9 | no | xx23 | 2.62266 | 2.62266 | 0.00182961 | 0.0124475 | 0.0124475
2 x BEAM | L40*3 | STEEL/S235 | +13.960 | +14.000 | 3 | 9 | 0.8 | 0 | 84.4 | 0.1 | 40 | 40 | 470 | no | k66 | 0.07285 | 0.07285 | 0.000234 | 0.00010857 | 0.00010998
BEAM | SHS60*3 | STEEL/S355 | +12.880 | +13.842 | 1 | 6 | 6.9 | 0 | 45 | 0.4 | 60 | 60 | 1355.6 | no | k58 | 0.307328 | 0.318455 | 0.00065866 | 0.000872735 | 0.000904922
BEAM | SHS60*3 | STEEL/S355 | +12.874 | +13.829 | 1 | 6 | 6.9 | 0 | 45 | 0.4 | 60 | 60 | 1349 | no | k56 | 0.308515 | 0.308515 | 0.00065866 | 0.000876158 | 0.000876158
2 x BEAM | HEB140 | STEEL/S355 | +13.400 | +13.540 | 5 | 4 | 10.8 | 0 | 23.8 | 0.2 | 140 | 140 | 320 | no | zz3 | 0.2576 | 0.2576 | 0.0043 | 0.001043 | 0.001376
BEAM | HEB140 | STEEL/S355 | +13.400 | +13.540 | 5 | 4 | 53.3 | 0.2 | 23.8 | 1.2 | 140 | 140 | 1578.2 | no | zz30 | 1.27045 | 1.27045 | 0.0043 | 0.0064858 | 0.00678624
BEAM | UPN140 | STEEL/S355 | +13.655 | +13.795 | 5 | 4 | 31.6 | 0.1 | 30.6 | 1 | 140 | 60 | 1971.3 | no | zz16 | 0.965951 | 0.965951 | 0.00204 | 0.00398058 | 0.00402151
BEAM | UPN140 | STEEL/S355 | +13.655 | +13.795 | 5 | 4 | 48.2 | 0.2 | 30.6 | 1.5 | 140 | 60 | 3011 | no | zz15 | 1.47539 | 1.47539 | 0.00204 | 0.0060772 | 0.00614244
BEAM | UPN140 | STEEL/S355 | +13.655 | +13.795 | 5 | 4 | 35.3 | 0.1 | 30.6 | 1.1 | 140 | 60 | 2201.3 | no | zz14 | 1.07861 | 1.07861 | 0.00204 | 0.00443263 | 0.00449056
BEAM | UPN140 | STEEL/S355 | +13.655 | +13.795 | 5 | 4 | 20.2 | 0.1 | 30.6 | 0.7 | 140 | 60 | 1261.5 | no | zz13 | 0.618134 | 0.618134 | 0.00204 | 0.00253278 | 0.00257346
BEAM | UPN140 | STEEL/S355 | +13.655 | +13.795 | 5 | 4 | 44.3 | 0.2 | 30.6 | 1.5 | 140 | 60 | 2765.8 | no | zz12 | 1.35523 | 1.35523 | 0.00204 | 0.0056008 | 0.00564218
BEAM | UPN140 | STEEL/S355 | +13.655 | +13.795 | 5 | 4 | 27.7 | 0.1 | 30.6 | 1 | 140 | 60 | 1730.2 | no | zz11 | 0.847782 | 0.847782 | 0.00204 | 0.00348816 | 0.00352954
BEAM | HEB140 | STEEL/S355 | +13.400 | +13.540 | 5 | 4 | 188.9 | 0.7 | 23.8 | 4.4 | 140 | 140 | 5596.4 | no | zz10 | 4.50512 | 4.50512 | 0.0043 | 0.0227642 | 0.0240646
BEAM | UPN140 | STEEL/S355 | +13.655 | +13.795 | 5 | 4 | 42.6 | 0.2 | 30.6 | 1.2 | 140 | 60 | 2658.6 | no | zz8 | 1.30272 | 1.30272 | 0.00204 | 0.00536009 | 0.00542356
BEAM | HEB140 | STEEL/S355 | +13.400 | +13.540 | 5 | 4 | 9.6 | 0 | 23.8 | 0.2 | 140 | 140 | 284.7 | no | zz2 | 0.229191 | 0.229191 | 0.0043 | 0.001043 | 0.00122425
BEAM | HEB160 | STEEL/S355 | +13.741 | +13.817 | 1 | 3 | 3.3 | 0 | 21.5 | 0.1 | 160 | 160 | 76.7 | no | k46 | 0.0703817 | 0.0703817 | 0.00543 | 0.000374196 | 0.00041631
2 x BEAM | K80/4 | STEEL/S355 | +12.597 | +12.836 | 1 | 2 | 2.8 | 0 | 33.6 | 0.1 | 80 | 80 | 302 | no | k29 | 0.0936137 | 0.0936137 | 0.001174 | 0.000328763 | 0.000354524
2 x BEAM | K80/4 | STEEL/S355 | +10.883 | +11.126 | 1 | 4 | 2.3 | 0 | 33.6 | 0.1 | 80 | 80 | 245.5 | no | xx10 | 0.0761047 | 0.0761047 | 0.001174 | 0.000235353 | 0.000288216
BEAM | K80/4 | STEEL/S355 | +12.547 | +12.797 | 1 | 2 | 2.9 | 0 | 33.6 | 0.1 | 80 | 80 | 317.9 | no | k31 | 0.0985418 | 0.0985418 | 0.001174 | 0.000349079 | 0.000373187
2 x BEAM | K80/4 | STEEL/S355 | +10.881 | +11.123 | 1 | 4 | 2.3 | 0 | 33.6 | 0.1 | 80 | 80 | 245.5 | no | xx11 | 0.0761051 | 0.0761051 | 0.001174 | 0.000237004 | 0.000288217
2 x BEAM | K60/4 | STEEL/S355 | +13.908 | +13.977 | 1 | 9 | 8.4 | 0 | 34.4 | 0.4 | 60 | 60 | 1247 | no | k6 | 0.286821 | 0.286821 | 0.000854 | 0.00106419 | 0.00106498
BEAM | K60/4 | STEEL/S355 | +13.918 | +13.987 | 1 | 9 | 8.4 | 0 | 34.4 | 0.4 | 60 | 60 | 1260.6 | no | k44 | 0.289931 | 0.289931 | 0.000854 | 0.00104183 | 0.00107653
BEAM | RHS120*60*3 | STEEL/S355 | +13.887 | +14.008 | 1 | 14 | 16.6 | 0 | 43.6 | 0.7 | 120 | 60 | 2020 | no | k4 | 0.722055 | 0.722055 | 0.00101866 | 0.00210888 | 0.00210888
2 x BEAM | K60/4 | STEEL/S355 | +13.857 | +13.926 | 1 | 9 | 8.4 | 0 | 34.4 | 0.4 | 60 | 60 | 1247 | no | k6 | 0.286821 | 0.286821 | 0.000854 | 0.00106419 | 0.00106498
BEAM | RHS120*60*3 | STEEL/S355 | +13.826 | +13.947 | 1 | 14 | 16.6 | 0 | 43.6 | 0.7 | 120 | 60 | 2020 | no | k4 | 0.722055 | 0.722055 | 0.00101866 | 0.00210888 | 0.00210888
2 x BEAM | K60/4 | STEEL/S355 | +13.888 | +13.957 | 1 | 9 | 8.4 | 0 | 34.4 | 0.4 | 60 | 60 | 1247 | no | k6 | 0.286821 | 0.286821 | 0.000854 | 0.00106419 | 0.00106498
2 x BEAM | K60/4 | STEEL/S355 | +13.898 | +13.967 | 1 | 9 | 8.4 | 0 | 34.4 | 0.4 | 60 | 60 | 1247 | no | k6 | 0.286821 | 0.286821 | 0.000854 | 0.00106419 | 0.00106498
BEAM | RHS120*60*3 | STEEL/S355 | +13.867 | +13.988 | 1 | 14 | 16.6 | 0 | 43.6 | 0.7 | 120 | 60 | 2020 | no | k4 | 0.722055 | 0.722055 | 0.00101866 | 0.00210888 | 0.00210888
BEAM | K80/4 | STEEL/S355 | +12.956 | +13.695 | 1 | 2 | 12.9 | 0 | 33.6 | 0.4 | 80 | 80 | 1404.5 | no | k42 | 0.435394 | 0.435394 | 0.001174 | 0.00164337 | 0.00164888
BEAM | K80/4 | STEEL/S355 | +13.651 | +13.818 | 1 | 2 | 2.5 | 0 | 33.6 | 0.1 | 80 | 80 | 268.4 | no | k41 | 0.0832175 | 0.0832175 | 0.001174 | 0.000281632 | 0.000315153
2 x BEAM | K80/4 | STEEL/S355 | +12.996 | +13.858 | 1 | 2 | 16.1 | 0 | 33.6 | 0.4 | 80 | 80 | 1753.9 | no | k16 | 0.543712 | 0.543712 | 0.001174 | 0.00200379 | 0.00205909
BEAM | K80/4 | STEEL/S355 | +12.958 | +13.856 | 1 | 2 | 16.1 | 0 | 33.6 | 0.4 | 80 | 80 | 1753.9 | no | k15 | 0.543712 | 0.543712 | 0.001174 | 0.00200381 | 0.00205909
BEAM | K80/4 | STEEL/S355 | +12.875 | +13.695 | 1 | 2 | 13.2 | 0 | 33.6 | 0.4 | 80 | 80 | 1448.2 | no | k55 | 0.448953 | 0.448953 | 0.001174 | 0.00173068 | 0.00170023
BEAM | K80/4 | STEEL/S355 | +13.651 | +13.818 | 1 | 2 | 2.5 | 0 | 33.6 | 0.1 | 80 | 80 | 268.4 | no | k41 | 0.0832184 | 0.0832184 | 0.001174 | 0.000281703 | 0.000315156
BEAM | K80/4 | STEEL/S355 | +13.931 | +14.018 | 1 | 2 | 19.5 | 0 | 33.6 | 0.7 | 80 | 80 | 2105.4 | no | k40 | 0.652689 | 0.652689 | 0.001174 | 0.00253518 | 0.0024718
BEAM | K60/4 | STEEL/S355 | +13.683 | +13.753 | 1 | 9 | 8.2 | 0 | 34.4 | 0.4 | 60 | 60 | 1233.2 | no | k39 | 0.283636 | 0.283636 | 0.000854 | 0.00103049 | 0.00105315
2 x BEAM | K60/4 | STEEL/S355 | +13.693 | +13.763 | 1 | 9 | 8.4 | 0 | 34.4 | 0.4 | 60 | 60 | 1249.6 | no | k5 | 0.28741 | 0.28741 | 0.000854 | 0.00106664 | 0.00106716
BEAM | RHS120*60*3 | STEEL/S355 | +13.663 | +13.783 | 1 | 14 | 16.6 | 0 | 43.6 | 0.7 | 120 | 60 | 2020 | no | k4 | 0.722055 | 0.722055 | 0.00101866 | 0.00210888 | 0.00210888
BEAM | K80/4 | STEEL/S355 | +12.776 | +13.692 | 1 | 2 | 16.1 | 0 | 33.6 | 0.4 | 80 | 80 | 1761.3 | no | k38 | 0.545989 | 0.545989 | 0.001174 | 0.00202435 | 0.00206771
2 x BEAM | K80/4 | STEEL/S355 | +12.833 | +13.695 | 1 | 2 | 16.1 | 0 | 33.6 | 0.4 | 80 | 80 | 1761.3 | no | k18 | 0.545989 | 0.545989 | 0.001174 | 0.00201173 | 0.00206771
2 x BEAM | K80/4 | STEEL/S355 | +12.836 | +13.733 | 1 | 2 | 16.1 | 0 | 33.6 | 0.4 | 80 | 80 | 1761.3 | no | k18 | 0.545989 | 0.545989 | 0.001174 | 0.00201173 | 0.00206771
2 x BEAM | K80/4 | STEEL/S355 | +12.874 | +13.736 | 1 | 2 | 16.1 | 0 | 33.6 | 0.4 | 80 | 80 | 1761.3 | no | k18 | 0.545989 | 0.545989 | 0.001174 | 0.00201173 | 0.00206771
BEAM | K80/4 | STEEL/S355 | +12.835 | +13.814 | 1 | 2 | 16.3 | 0 | 33.6 | 0.4 | 80 | 80 | 1769.9 | no | k53 | 0.54866 | 0.54866 | 0.001174 | 0.00207731 | 0.00207783
2 x BEAM | K80/4 | STEEL/S355 | +12.877 | +13.774 | 1 | 2 | 16.1 | 0 | 33.6 | 0.4 | 80 | 80 | 1761.3 | no | k18 | 0.545989 | 0.545989 | 0.001174 | 0.00201173 | 0.00206771
BEAM | K80/4 | STEEL/S355 | +12.834 | +13.777 | 1 | 2 | 16.6 | 0 | 33.6 | 0.7 | 80 | 80 | 1804.8 | no | k52 | 0.559503 | 0.559503 | 0.001174 | 0.00209951 | 0.00211889
BEAM | K80/4 | STEEL/S355 | +12.776 | +13.692 | 1 | 2 | 16.1 | 0 | 33.6 | 0.4 | 80 | 80 | 1761.3 | no | k38 | 0.545989 | 0.545989 | 0.001174 | 0.00202425 | 0.00206771
2 x BEAM | K60/4 | STEEL/S355 | +13.704 | +13.773 | 1 | 9 | 8.4 | 0 | 34.4 | 0.4 | 60 | 60 | 1249.6 | no | k5 | 0.28741 | 0.28741 | 0.000854 | 0.00106664 | 0.00106716
2 x BEAM | K60/4 | STEEL/S355 | +13.714 | +13.783 | 1 | 9 | 8.4 | 0 | 34.4 | 0.4 | 60 | 60 | 1249.6 | no | k5 | 0.28741 | 0.28741 | 0.000854 | 0.00106664 | 0.00106716
BEAM | RHS120*60*3 | STEEL/S355 | +13.683 | +13.804 | 1 | 14 | 16.6 | 0 | 43.6 | 0.7 | 120 | 60 | 2020 | no | k4 | 0.722055 | 0.722055 | 0.00101866 | 0.00210888 | 0.00210888
2 x BEAM | K60/4 | STEEL/S355 | +13.724 | +13.793 | 1 | 9 | 8.4 | 0 | 34.4 | 0.4 | 60 | 60 | 1249.6 | no | k5 | 0.28741 | 0.28741 | 0.000854 | 0.00106664 | 0.00106716
2 x BEAM | K60/4 | STEEL/S355 | +13.734 | +13.804 | 1 | 9 | 8.4 | 0 | 34.4 | 0.4 | 60 | 60 | 1249.6 | no | k5 | 0.28741 | 0.28741 | 0.000854 | 0.00106664 | 0.00106716
BEAM | RHS120*60*3 | STEEL/S355 | +13.703 | +13.824 | 1 | 14 | 16.6 | 0 | 43.6 | 0.7 | 120 | 60 | 2020 | no | k4 | 0.722055 | 0.722055 | 0.00101866 | 0.00210888 | 0.00210888
2 x BEAM | K60/4 | STEEL/S355 | +13.744 | +13.814 | 1 | 9 | 8.4 | 0 | 34.4 | 0.4 | 60 | 60 | 1249.6 | no | k5 | 0.28741 | 0.28741 | 0.000854 | 0.00106664 | 0.00106716
2 x BEAM | K60/4 | STEEL/S355 | +13.755 | +13.824 | 1 | 9 | 8.4 | 0 | 34.4 | 0.4 | 60 | 60 | 1249.6 | no | k5 | 0.28741 | 0.28741 | 0.000854 | 0.00106664 | 0.00106716
BEAM | RHS120*60*3 | STEEL/S355 | +13.724 | +13.845 | 1 | 14 | 16.6 | 0 | 43.6 | 0.7 | 120 | 60 | 2020 | no | k4 | 0.722055 | 0.722055 | 0.00101866 | 0.00210888 | 0.00210888
2 x BEAM | K60/4 | STEEL/S355 | +13.765 | +13.834 | 1 | 9 | 8.4 | 0 | 34.4 | 0.4 | 60 | 60 | 1249.6 | no | k5 | 0.28741 | 0.28741 | 0.000854 | 0.00106664 | 0.00106716
2 x BEAM | K60/4 | STEEL/S355 | +13.775 | +13.845 | 1 | 9 | 8.4 | 0 | 34.4 | 0.4 | 60 | 60 | 1249.6 | no | k5 | 0.28741 | 0.28741 | 0.000854 | 0.00106664 | 0.00106716
BEAM | RHS120*60*3 | STEEL/S355 | +13.744 | +13.865 | 1 | 14 | 16.6 | 0 | 43.6 | 0.7 | 120 | 60 | 2020 | no | k4 | 0.722055 | 0.722055 | 0.00101866 | 0.00210888 | 0.00210888
2 x BEAM | K60/4 | STEEL/S355 | +13.785 | +13.855 | 1 | 9 | 8.4 | 0 | 34.4 | 0.4 | 60 | 60 | 1249.6 | no | k5 | 0.28741 | 0.28741 | 0.000854 | 0.00106664 | 0.00106716
2 x BEAM | K60/4 | STEEL/S355 | +13.796 | +13.865 | 1 | 9 | 8.4 | 0 | 34.4 | 0.4 | 60 | 60 | 1249.6 | no | k5 | 0.28741 | 0.28741 | 0.000854 | 0.00106664 | 0.00106716
BEAM | RHS120*60*3 | STEEL/S355 | +13.765 | +13.886 | 1 | 14 | 16.6 | 0 | 43.6 | 0.7 | 120 | 60 | 2020 | no | k4 | 0.722055 | 0.722055 | 0.00101866 | 0.00210888 | 0.00210888
2 x BEAM | K60/4 | STEEL/S355 | +13.806 | +13.875 | 1 | 9 | 8.4 | 0 | 34.4 | 0.4 | 60 | 60 | 1249.6 | no | k5 | 0.28741 | 0.28741 | 0.000854 | 0.00106664 | 0.00106716
2 x BEAM | K60/4 | STEEL/S355 | +13.816 | +13.886 | 1 | 9 | 8.4 | 0 | 34.4 | 0.4 | 60 | 60 | 1249.6 | no | k5 | 0.28741 | 0.28741 | 0.000854 | 0.00106664 | 0.00106716
BEAM | RHS120*60*3 | STEEL/S355 | +13.785 | +13.906 | 1 | 14 | 16.6 | 0 | 43.6 | 0.7 | 120 | 60 | 2020 | no | k4 | 0.722055 | 0.722055 | 0.00101866 | 0.00210888 | 0.00210888
BEAM | BL12*80 | STEEL/S235 | +13.585 | +13.653 | 1 | 1 | 0.5 | 0 | 28.2 | 0 | 80 | 12 | 67.5 | no | b10 | 0.0143107 | 0.0143107 | 0.00096 | 0.0000646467 | 0.0000646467
BEAM | BL12*80 | STEEL/S235 | +13.585 | +13.653 | 1 | 1 | 0.5 | 0 | 28.2 | 0 | 80 | 12 | 67.7 | no | b10 | 0.0143655 | 0.0143655 | 0.00096 | 0.0000649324 | 0.0000649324
BEAM | BL12*140 | STEEL/S235 | +13.585 | +13.654 | 1 | 1 | 0.8 | 0 | 26.8 | 0 | 140 | 12 | 68.4 | no | b9 | 0.0238768 | 0.0238768 | 0.00168 | 0.000113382 | 0.000113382
BEAM | BL12*80 | STEEL/S235 | +13.585 | +13.660 | 1 | 1 | 0.6 | 0 | 27.8 | 0 | 80 | 12 | 74.7 | no | b8 | 0.0156258 | 0.0156258 | 0.00096 | 0.0000715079 | 0.0000715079
BEAM | BL12*80 | STEEL/S235 | +13.585 | +13.660 | 1 | 1 | 0.6 | 0 | 27.8 | 0 | 80 | 12 | 75 | no | b8 | 0.0156827 | 0.0156827 | 0.00096 | 0.000071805 | 0.000071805
BEAM | BL12*140 | STEEL/S235 | +13.585 | +13.661 | 1 | 1 | 1 | 0 | 26.4 | 0 | 140 | 12 | 75.5 | no | b7 | 0.0260531 | 0.0260531 | 0.00168 | 0.000125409 | 0.000125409
BEAM | K80/4 | STEEL/S355 | +12.918 | +13.814 | 1 | 2 | 15.9 | 0 | 33.6 | 0.4 | 80 | 80 | 1726.3 | no | k36 | 0.535146 | 0.535146 | 0.001174 | 0.00198953 | 0.00202665
BEAM | K80/4 | STEEL/S355 | +13.929 | +14.011 | 1 | 2 | 2.5 | 0 | 33.6 | 0.1 | 80 | 80 | 268.3 | no | k35 | 0.0831861 | 0.0831861 | 0.001174 | 0.000313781 | 0.000315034
BEAM | K80/4 | STEEL/S355 | +13.913 | +14.010 | 1 | 2 | 12.5 | 0 | 33.6 | 0.4 | 80 | 80 | 1352.9 | no | k34 | 0.419402 | 0.419402 | 0.001174 | 0.00145623 | 0.00158831
BEAM | RHS120*4 | STEEL/S355 | +12.818 | +12.997 | 1 | 11 | 68.6 | 0 | 33 | 2.3 | 120 | 120 | 4730.5 | no | k33 | 2.2607 | 2.2607 | 0.00181095 | 0.00873365 | 0.00873365
BEAM | RHS120*4 | STEEL/S355 | +12.818 | +12.997 | 1 | 11 | 68.6 | 0 | 33 | 2.3 | 120 | 120 | 4723.7 | no | k32 | 2.26071 | 2.26071 | 0.00181095 | 0.00873384 | 0.00873384
2 x BEAM | K90/4 | STEEL/S355 | +10.623 | +13.439 | 1 | 4 | 36 | 0 | 33.3 | 1.2 | 90 | 90 | 3441.7 | no | xx15 | 1.20459 | 1.20459 | 0.001334 | 0.00456903 | 0.0045912
BEAM | K90/4 | STEEL/S355 | +8.030 | +10.579 | 1 | 4 | 38.6 | 0 | 33.3 | 1.2 | 90 | 90 | 3688.2 | no | xx14 | 1.29086 | 1.29086 | 0.001334 | 0.00494632 | 0.00492002
BEAM | K90/4 | STEEL/S355 | +8.030 | +10.579 | 1 | 4 | 38.6 | 0 | 33.3 | 1.2 | 90 | 90 | 3688.2 | no | xx14 | 1.29084 | 1.29084 | 0.001334 | 0.00494624 | 0.00491994
2 x BEAM | K90/4 | STEEL/S355 | +5.467 | +8.013 | 1 | 4 | 50.1 | 0 | 33.3 | 1.8 | 90 | 90 | 4781 | no | xx13 | 1.67336 | 1.67336 | 0.001334 | 0.00649648 | 0.00637791
2 x BEAM | HEB160 | STEEL/S355 | +5.280 | +10.601 | 1 | 4 | 235.8 | 0 | 21.5 | 5.2 | 160 | 160 | 5531.3 | no | xx12 | 5.07774 | 5.07774 | 0.00543 | 0.0287717 | 0.030035
BEAM | K80/4 | STEEL/S355 | +12.547 | +12.797 | 1 | 2 | 2.9 | 0 | 33.6 | 0.1 | 80 | 80 | 317.9 | no | k31 | 0.0985417 | 0.0985417 | 0.001174 | 0.000349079 | 0.000373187
BEAM | RHS120*4 | STEEL/S355 | +13.659 | +13.941 | 1 | 11 | 185.3 | 0 | 33 | 6.1 | 120 | 120 | 12721.2 | no | k27 | 6.10809 | 6.10809 | 0.00181095 | 0.0236105 | 0.0236105
BEAM | K40/4 | STEEL/S355 | +7.990 | +8.030 | 1 | 4 | 14.1 | 0.1 | 35.8 | 0.4 | 40 | 40 | 3374.7 | no | xx4 | 0.506201 | 0.506201 | 0.000534 | 0.00193761 | 0.00180208
BEAM | K40/4 | STEEL/S355 | +10.570 | +10.610 | 1 | 4 | 8.2 | 0.1 | 35.8 | 0.4 | 40 | 40 | 1980 | no | xx3 | 0.297 | 0.297 | 0.000534 | 0.00114048 | 0.00105732
BEAM | K80/4 | STEEL/S355 | +12.834 | +12.915 | 1 | 2 | 18.7 | 0 | 33.6 | 0.7 | 80 | 80 | 2020 | no | k7 | 0.6262 | 0.6262 | 0.001174 | 0.00245632 | 0.00237148
BEAM | K80/4 | STEEL/S355 | +12.838 | +12.919 | 1 | 2 | 18.7 | 0 | 33.6 | 0.7 | 80 | 80 | 2020 | no | k7 | 0.6262 | 0.6262 | 0.001174 | 0.00245632 | 0.00237148
BEAM | HEB160 | STEEL/S355 | +13.741 | +13.817 | 1 | 3 | 3.3 | 0 | 21.5 | 0.1 | 160 | 160 | 76.7 | no | k26 | 0.0703917 | 0.0703917 | 0.00543 | 0.000373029 | 0.000416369
BEAM | K60/4 | STEEL/S355 | +12.749 | +13.674 | 1 | 9 | 9 | 0 | 34.4 | 0.4 | 60 | 60 | 1353.3 | no | k25 | 0.311263 | 0.311263 | 0.000854 | 0.001166 | 0.00115573
BEAM | K60/4 | STEEL/S355 | +12.749 | +13.674 | 1 | 9 | 9 | 0 | 34.4 | 0.4 | 60 | 60 | 1353.3 | no | k24 | 0.311263 | 0.311263 | 0.000854 | 0.00116365 | 0.00115573
2 x BEAM | K60/4 | STEEL/S355 | +12.794 | +13.694 | 1 | 9 | 9 | 0 | 34.4 | 0.4 | 60 | 60 | 1337.2 | no | k22 | 0.307549 | 0.307549 | 0.000854 | 0.00115934 | 0.00114194
2 x BEAM | K60/4 | STEEL/S355 | +12.815 | +13.714 | 1 | 9 | 9 | 0 | 34.4 | 0.4 | 60 | 60 | 1337.2 | no | k22 | 0.307549 | 0.307549 | 0.000854 | 0.00115934 | 0.00114194
2 x BEAM | K60/4 | STEEL/S355 | +12.835 | +13.735 | 1 | 9 | 9 | 0 | 34.4 | 0.4 | 60 | 60 | 1337.2 | no | k22 | 0.307549 | 0.307549 | 0.000854 | 0.00115934 | 0.00114194
2 x BEAM | K60/4 | STEEL/S355 | +12.856 | +13.755 | 1 | 9 | 9 | 0 | 34.4 | 0.4 | 60 | 60 | 1337.2 | no | k22 | 0.307549 | 0.307549 | 0.000854 | 0.00115934 | 0.00114194
2 x BEAM | K60/4 | STEEL/S355 | +12.876 | +13.776 | 1 | 9 | 9 | 0 | 34.4 | 0.4 | 60 | 60 | 1337.2 | no | k22 | 0.307549 | 0.307549 | 0.000854 | 0.00115934 | 0.00114194
2 x BEAM | K60/4 | STEEL/S355 | +12.897 | +13.796 | 1 | 9 | 9 | 0 | 34.4 | 0.4 | 60 | 60 | 1337.2 | no | k22 | 0.307549 | 0.307549 | 0.000854 | 0.00115934 | 0.00114194
BEAM | K60/4 | STEEL/S355 | +12.937 | +13.837 | 1 | 9 | 9 | 0 | 34.4 | 0.4 | 60 | 60 | 1337.2 | no | k22 | 0.307549 | 0.307549 | 0.000854 | 0.00115934 | 0.00114194
BEAM | K60/4 | STEEL/S355 | +12.937 | +13.837 | 1 | 9 | 9 | 0 | 34.4 | 0.4 | 60 | 60 | 1350.8 | no | k23 | 0.31069 | 0.31069 | 0.000854 | 0.00116254 | 0.0011536
BEAM | K60/4 | STEEL/S355 | +12.978 | +13.878 | 1 | 9 | 9 | 0 | 34.4 | 0.4 | 60 | 60 | 1337.2 | no | k22 | 0.307549 | 0.307549 | 0.000854 | 0.00115934 | 0.00114194
BEAM | K60/4 | STEEL/S355 | +12.978 | +13.878 | 1 | 9 | 9 | 0 | 34.4 | 0.4 | 60 | 60 | 1350.8 | no | k23 | 0.31069 | 0.31069 | 0.000854 | 0.00116254 | 0.0011536
2 x BEAM | K60/4 | STEEL/S355 | +12.958 | +13.858 | 1 | 9 | 9 | 0 | 34.4 | 0.4 | 60 | 60 | 1337.2 | no | k22 | 0.307549 | 0.307549 | 0.000854 | 0.00115934 | 0.00114194
BEAM | K80/4 | STEEL/S355 | +12.997 | +13.878 | 1 | 2 | 8 | 0 | 33.6 | 0.4 | 80 | 80 | 880 | no | k9 | 0.2728 | 0.2728 | 0.001174 | 0.00107008 | 0.00103312
2 x BEAM | K80/4 | STEEL/S355 | +12.977 | +13.858 | 1 | 2 | 8 | 0 | 33.6 | 0.4 | 80 | 80 | 880 | no | k8 | 0.2728 | 0.2728 | 0.001174 | 0.00107008 | 0.00103312
2 x BEAM | K80/4 | STEEL/S355 | +12.956 | +13.837 | 1 | 2 | 8 | 0 | 33.6 | 0.4 | 80 | 80 | 880 | no | k8 | 0.2728 | 0.2728 | 0.001174 | 0.00107008 | 0.00103312
BEAM | K80/4 | STEEL/S355 | +12.794 | +13.674 | 1 | 2 | 8 | 0 | 33.6 | 0.4 | 80 | 80 | 879 | no | k21 | 0.27249 | 0.27249 | 0.001174 | 0.00104993 | 0.00103195
2 x BEAM | K80/4 | STEEL/S355 | +12.813 | +13.694 | 1 | 2 | 8 | 0 | 33.6 | 0.4 | 80 | 80 | 880 | no | k9 | 0.2728 | 0.2728 | 0.001174 | 0.00107008 | 0.00103312
2 x BEAM | K80/4 | STEEL/S355 | +12.834 | +13.715 | 1 | 2 | 8 | 0 | 33.6 | 0.4 | 80 | 80 | 880 | no | k9 | 0.2728 | 0.2728 | 0.001174 | 0.00107008 | 0.00103312
2 x BEAM | K80/4 | STEEL/S355 | +12.854 | +13.735 | 1 | 2 | 8 | 0 | 33.6 | 0.4 | 80 | 80 | 880 | no | k9 | 0.2728 | 0.2728 | 0.001174 | 0.00107008 | 0.00103312
2 x BEAM | K80/4 | STEEL/S355 | +12.875 | +13.756 | 1 | 2 | 8 | 0 | 33.6 | 0.4 | 80 | 80 | 880 | no | k9 | 0.2728 | 0.2728 | 0.001174 | 0.00107008 | 0.00103312
2 x BEAM | K80/4 | STEEL/S355 | +12.895 | +13.776 | 1 | 2 | 8 | 0 | 33.6 | 0.4 | 80 | 80 | 880 | no | k9 | 0.2728 | 0.2728 | 0.001174 | 0.00107008 | 0.00103312
BEAM | K80/4 | STEEL/S355 | +12.916 | +13.796 | 1 | 2 | 8 | 0 | 33.6 | 0.4 | 80 | 80 | 880 | no | k8 | 0.2728 | 0.2728 | 0.001174 | 0.00107008 | 0.00103312
BEAM | RHS120*4 | STEEL/S355 | +12.878 | +13.891 | 1 | 11 | 19.8 | 0 | 33.1 | 0.7 | 120 | 120 | 1445.7 | no | k20 | 0.654737 | 0.654737 | 0.00181095 | 0.00252228 | 0.00252228
BEAM | RHS120*4 | STEEL/S355 | +12.673 | +13.656 | 1 | 11 | 25.4 | 0 | 33.1 | 0.7 | 120 | 120 | 1853 | no | k19 | 0.838436 | 0.838852 | 0.00181095 | 0.00323051 | 0.00323281
BEAM | RHS120*4 | STEEL/S355 | +12.878 | +13.898 | 1 | 11 | 25.9 | 0 | 33.1 | 1 | 120 | 120 | 1888 | no | k17 | 0.854691 | 0.854691 | 0.00181095 | 0.00329394 | 0.00329394
BEAM | K80/4 | STEEL/S355 | +12.876 | +13.856 | 1 | 2 | 16.6 | 0 | 33.6 | 0.7 | 80 | 80 | 1797.6 | no | k48 | 0.557267 | 0.557267 | 0.001174 | 0.00209108 | 0.00211043
BEAM | RHS120*4 | STEEL/S355 | +12.673 | +13.662 | 1 | 11 | 19.2 | 0 | 33.1 | 0.7 | 120 | 120 | 1403.6 | no | k14 | 0.635258 | 0.635714 | 0.00181095 | 0.00244622 | 0.00244886
BEAM | K80/4 | STEEL/S355 | +12.937 | +13.878 | 1 | 2 | 8.7 | 0 | 33.6 | 0.4 | 80 | 80 | 940 | no | k13 | 0.2914 | 0.2914 | 0.001174 | 0.00114304 | 0.00110356
BEAM | K80/4 | STEEL/S355 | +12.897 | +12.978 | 1 | 2 | 18.7 | 0 | 33.6 | 0.7 | 80 | 80 | 2020 | no | k7 | 0.6262 | 0.6262 | 0.001174 | 0.00245632 | 0.00237148
BEAM | RHS120*4 | STEEL/S355 | +12.673 | +12.935 | 1 | 11 | 162.4 | 0 | 33 | 5.4 | 120 | 120 | 11163.1 | no | k12 | 5.35144 | 5.35144 | 0.00181095 | 0.0206847 | 0.0206847
BEAM | RHS120*4 | STEEL/S355 | +12.673 | +12.935 | 1 | 11 | 162.4 | 0 | 33 | 5.4 | 120 | 120 | 11170.6 | no | k11 | 5.35148 | 5.35148 | 0.00181095 | 0.0206847 | 0.0206847
BEAM | K80/4 | STEEL/S355 | +12.795 | +13.674 | 1 | 2 | 8 | 0 | 33.6 | 0.4 | 80 | 80 | 879 | no | k10 | 0.27249 | 0.27249 | 0.001174 | 0.0010333 | 0.00103195
BEAM | K80/4 | STEEL/S355 | +12.916 | +13.796 | 1 | 2 | 8 | 0 | 33.6 | 0.4 | 80 | 80 | 880 | no | k9 | 0.2728 | 0.2728 | 0.001174 | 0.00107008 | 0.00103312
BEAM | K80/4 | STEEL/S355 | +12.877 | +12.958 | 1 | 2 | 18.7 | 0 | 33.6 | 0.7 | 80 | 80 | 2020 | no | k7 | 0.6262 | 0.6262 | 0.001174 | 0.00245632 | 0.00237148
BEAM | K80/4 | STEEL/S355 | +12.693 | +12.774 | 1 | 2 | 18.7 | 0 | 33.6 | 0.7 | 80 | 80 | 2020 | no | k7 | 0.6262 | 0.6262 | 0.001174 | 0.00245632 | 0.00237148
BEAM | K80/4 | STEEL/S355 | +12.713 | +12.794 | 1 | 2 | 18.7 | 0 | 33.6 | 0.7 | 80 | 80 | 2020 | no | k7 | 0.6262 | 0.6262 | 0.001174 | 0.00245632 | 0.00237148
BEAM | K80/4 | STEEL/S355 | +12.734 | +12.815 | 1 | 2 | 18.7 | 0 | 33.6 | 0.7 | 80 | 80 | 2020 | no | k7 | 0.6262 | 0.6262 | 0.001174 | 0.00245632 | 0.00237148
BEAM | K80/4 | STEEL/S355 | +12.754 | +12.835 | 1 | 2 | 18.7 | 0 | 33.6 | 0.7 | 80 | 80 | 2020 | no | k7 | 0.6262 | 0.6262 | 0.001174 | 0.00245632 | 0.00237148
BEAM | K80/4 | STEEL/S355 | +12.775 | +12.856 | 1 | 2 | 18.7 | 0 | 33.6 | 0.7 | 80 | 80 | 2020 | no | k7 | 0.6262 | 0.6262 | 0.001174 | 0.00245632 | 0.00237148
BEAM | K80/4 | STEEL/S355 | +12.795 | +12.876 | 1 | 2 | 18.7 | 0 | 33.6 | 0.7 | 80 | 80 | 2020 | no | k7 | 0.6262 | 0.6262 | 0.001174 | 0.00245632 | 0.00237148
BEAM | K80/4 | STEEL/S355 | +12.856 | +12.937 | 1 | 2 | 18.7 | 0 | 33.6 | 0.7 | 80 | 80 | 2020 | no | k7 | 0.6262 | 0.6262 | 0.001174 | 0.00245632 | 0.00237148
BEAM | K80/4 | STEEL/S355 | +12.816 | +12.897 | 1 | 2 | 18.7 | 0 | 33.6 | 0.7 | 80 | 80 | 2020 | no | k7 | 0.6262 | 0.6262 | 0.001174 | 0.00245632 | 0.00237148
2 x BEAM | K60/4 | STEEL/S355 | +13.867 | +13.937 | 1 | 9 | 8.4 | 0 | 34.4 | 0.4 | 60 | 60 | 1247 | no | k6 | 0.286821 | 0.286821 | 0.000854 | 0.00106419 | 0.00106498
2 x BEAM | K60/4 | STEEL/S355 | +13.877 | +13.947 | 1 | 9 | 8.4 | 0 | 34.4 | 0.4 | 60 | 60 | 1247 | no | k6 | 0.286821 | 0.286821 | 0.000854 | 0.00106419 | 0.00106498
BEAM | RHS120*60*3 | STEEL/S355 | +13.877 | +13.998 | 1 | 14 | 16.6 | 0 | 43.6 | 0.7 | 120 | 60 | 2020 | no | k4 | 0.722055 | 0.722055 | 0.00101866 | 0.00210888 | 0.00210888
BEAM | RHS120*60*3 | STEEL/S355 | +13.857 | +13.978 | 1 | 14 | 16.6 | 0 | 43.6 | 0.7 | 120 | 60 | 2020 | no | k4 | 0.722055 | 0.722055 | 0.00101866 | 0.00210888 | 0.00210888
BEAM | RHS120*60*3 | STEEL/S355 | +13.847 | +13.967 | 1 | 14 | 16.6 | 0 | 43.6 | 0.7 | 120 | 60 | 2020 | no | k4 | 0.722055 | 0.722055 | 0.00101866 | 0.00210888 | 0.00210888
BEAM | RHS120*60*3 | STEEL/S355 | +13.673 | +13.794 | 1 | 14 | 16.6 | 0 | 43.6 | 0.7 | 120 | 60 | 2020 | no | k4 | 0.722055 | 0.722055 | 0.00101866 | 0.00210888 | 0.00210888
BEAM | RHS120*60*3 | STEEL/S355 | +13.693 | +13.814 | 1 | 14 | 16.6 | 0 | 43.6 | 0.7 | 120 | 60 | 2020 | no | k4 | 0.722055 | 0.722055 | 0.00101866 | 0.00210888 | 0.00210888
BEAM | RHS120*60*3 | STEEL/S355 | +13.714 | +13.834 | 1 | 14 | 16.6 | 0 | 43.6 | 0.7 | 120 | 60 | 2020 | no | k4 | 0.722055 | 0.722055 | 0.00101866 | 0.00210888 | 0.00210888
BEAM | RHS120*60*3 | STEEL/S355 | +13.734 | +13.855 | 1 | 14 | 16.6 | 0 | 43.6 | 0.7 | 120 | 60 | 2020 | no | k4 | 0.722055 | 0.722055 | 0.00101866 | 0.00210888 | 0.00210888
BEAM | RHS120*60*3 | STEEL/S355 | +13.755 | +13.875 | 1 | 14 | 16.6 | 0 | 43.6 | 0.7 | 120 | 60 | 2020 | no | k4 | 0.722055 | 0.722055 | 0.00101866 | 0.00210888 | 0.00210888
BEAM | RHS120*60*3 | STEEL/S355 | +13.775 | +13.896 | 1 | 14 | 16.6 | 0 | 43.6 | 0.7 | 120 | 60 | 2020 | no | k4 | 0.722055 | 0.722055 | 0.00101866 | 0.00210888 | 0.00210888
2 x BEAM | K60/4 | STEEL/S355 | +13.826 | +13.896 | 1 | 9 | 8.4 | 0 | 34.4 | 0.4 | 60 | 60 | 1249.6 | no | k5 | 0.28741 | 0.28741 | 0.000854 | 0.00106664 | 0.00106716
2 x BEAM | K60/4 | STEEL/S355 | +13.837 | +13.906 | 1 | 9 | 8.4 | 0 | 34.4 | 0.4 | 60 | 60 | 1249.6 | no | k5 | 0.28741 | 0.28741 | 0.000854 | 0.00106664 | 0.00106716
BEAM | RHS120*60*3 | STEEL/S355 | +13.836 | +13.957 | 1 | 14 | 16.6 | 0 | 43.6 | 0.7 | 120 | 60 | 2020 | no | k4 | 0.722055 | 0.722055 | 0.00101866 | 0.00210888 | 0.00210888
BEAM | RHS120*60*3 | STEEL/S355 | +13.796 | +13.916 | 1 | 14 | 16.6 | 0 | 43.6 | 0.7 | 120 | 60 | 2020 | no | k4 | 0.722055 | 0.722055 | 0.00101866 | 0.00210888 | 0.00210888
BEAM | RHS120*60*3 | STEEL/S355 | +13.806 | +13.927 | 1 | 14 | 16.6 | 0 | 43.6 | 0.7 | 120 | 60 | 2020 | no | k4 | 0.722055 | 0.722055 | 0.00101866 | 0.00210888 | 0.00210888
BEAM | RHS120*60*3 | STEEL/S355 | +13.816 | +13.937 | 1 | 14 | 16.6 | 0 | 43.6 | 0.7 | 120 | 60 | 2020 | no | k4 | 0.722055 | 0.722055 | 0.00101866 | 0.00210888 | 0.00210888
BEAM | HEB160 | STEEL/S355 | +10.580 | +13.585 | 1 | 4 | 128.1 | 0 | 21.5 | 2.8 | 160 | 160 | 3005.6 | no | xx2 | 2.7591 | 2.7591 | 0.00543 | 0.015669 | 0.0163202
BEAM | K80/4 | STEEL/S355 | +13.672 | +13.760 | 1 | 2 | 19.5 | 0 | 33.6 | 0.7 | 80 | 80 | 2109.8 | no | k3 | 0.654041 | 0.654041 | 0.001174 | 0.00253993 | 0.00247692
BEAM | HEB160 | STEEL/S355 | +10.580 | +13.585 | 1 | 4 | 128.1 | 0 | 21.5 | 2.8 | 160 | 160 | 3005.5 | no | xx1 | 2.75909 | 2.75909 | 0.00543 | 0.015669 | 0.0163201
BEAM | RHS120*4 | STEEL/S355 | +13.821 | +14.012 | 1 | 11 | 80.2 | 0 | 33 | 2.6 | 120 | 120 | 5519.3 | no | k1 | 2.64379 | 2.68634 | 0.00181095 | 0.0102151 | 0.0103797

# IfcDiscreteAccessory: BELKA (32)
In: Undefined
Material: STEEL/S235
Tekla Quantity - Volume: 0 m3; Height: 200 mm
Pset_PlateCommon - LoadBearing: yes
Name | Description | Bottom elevation | Top elevation | Phase | Class | Weight (kg) | Gross footprint area (m2) | Area per tons (m2) | Net surface area (m2) | Width (mm) | Length (mm) | Reference | NetArea (m2) = GrossArea (m2) | CrossSectionArea (m2) | NetVolume (m3) | GrossVolume (m3)
BELKA | UPE200 | +13.840 | +14.040 | 3 | 3 | 12.6 | 0 | 27.9 | 0.4 | 80 | 508 | k112 | 0.35052 | 0.00315 | 0.00150012 | 0.0016002
BELKA | UPE200 | +13.840 | +14.040 | 3 | 3 | 12.6 | 0 | 27.9 | 0.4 | 80 | 508 | k111 | 0.35052 | 0.00315 | 0.00150012 | 0.0016002
BELKA | UPE200 | +12.582 | +12.714 | 3 | 3 | 3.3 | 0 | 27.9 | 0.1 | 80 | 132 | k110 | 0.09108 | 0.00315 | 0.000216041 | 0.0004158
BELKA | UPE200 | +12.581 | +12.714 | 3 | 3 | 3.3 | 0 | 27.9 | 0.1 | 80 | 132.3 | k109 | 0.0912835 | 0.00315 | 0.000216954 | 0.000416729
BELKA | UPN200 | +13.800 | +14.000 | 2 | 4 | 19.5 | 0.1 | 26.1 | 0.4 | 75 | 770 | k100 | 0.5082 | 0.00322 | 0.00241048 | 0.0024794
BELKA | UPN200 | +13.800 | +14.000 | 2 | 4 | 19.5 | 0.1 | 26.1 | 0.4 | 75 | 770 | k99 | 0.5082 | 0.00322 | 0.00241048 | 0.0024794
BELKA | UPN200 | +12.150 | +12.350 | 2 | 4 | 37.6 | 0.1 | 26.1 | 1 | 75 | 1487.2 | k96 | 0.981561 | 0.00322 | 0.00472672 | 0.00478883
BELKA | UPN200 | +12.150 | +12.350 | 2 | 4 | 37.6 | 0.1 | 26.1 | 1 | 75 | 1487.2 | k95 | 0.981561 | 0.00322 | 0.00472672 | 0.00478883
BELKA | UPN200 | +12.150 | +12.350 | 2 | 4 | 39.4 | 0.1 | 26.1 | 1.1 | 75 | 1560 | k94 | 1.0296 | 0.00322 | 0.00496178 | 0.0050232
BELKA | UPN200 | +12.150 | +12.350 | 2 | 4 | 39.4 | 0.1 | 26.1 | 1.1 | 75 | 1560 | k93 | 1.0296 | 0.00322 | 0.00496178 | 0.0050232
BELKA | UPN200 | +10.500 | +10.700 | 2 | 4 | 47.1 | 0.1 | 26.1 | 1.2 | 75 | 1862.2 | k92 | 1.22906 | 0.00322 | 0.00593778 | 0.00599633
BELKA | UPN200 | +10.500 | +10.700 | 2 | 4 | 47.1 | 0.1 | 26.1 | 1.2 | 75 | 1862.2 | k91 | 1.22906 | 0.00322 | 0.00593778 | 0.00599633
BELKA | UPN200 | +10.500 | +10.700 | 2 | 4 | 48.9 | 0.1 | 26.1 | 1.2 | 75 | 1935 | k88 | 1.2771 | 0.00322 | 0.00617284 | 0.0062307
BELKA | UPN200 | +10.500 | +10.700 | 2 | 4 | 48.9 | 0.1 | 26.1 | 1.2 | 75 | 1935 | k87 | 1.2771 | 0.00322 | 0.00617284 | 0.0062307
BELKA | UPN200 | +8.850 | +9.050 | 2 | 4 | 37.6 | 0.1 | 26.1 | 1 | 75 | 1487.2 | k96 | 0.981561 | 0.00322 | 0.00472672 | 0.00478883
BELKA | UPN200 | +8.850 | +9.050 | 2 | 4 | 37.6 | 0.1 | 26.1 | 1 | 75 | 1487.2 | k95 | 0.981561 | 0.00322 | 0.00472672 | 0.00478883
BELKA | UPN200 | +8.850 | +9.050 | 2 | 4 | 39.4 | 0.1 | 26.1 | 1.1 | 75 | 1560 | k94 | 1.0296 | 0.00322 | 0.00496178 | 0.0050232
BELKA | UPN200 | +8.850 | +9.050 | 2 | 4 | 39.4 | 0.1 | 26.1 | 1.1 | 75 | 1560 | k93 | 1.0296 | 0.00322 | 0.00496178 | 0.0050232
BELKA | UPN200 | +7.200 | +7.400 | 2 | 4 | 47.1 | 0.1 | 26.1 | 1.2 | 75 | 1862.2 | k92 | 1.22906 | 0.00322 | 0.00593778 | 0.00599633
BELKA | UPN200 | +7.200 | +7.400 | 2 | 4 | 47.1 | 0.1 | 26.1 | 1.2 | 75 | 1862.2 | k91 | 1.22906 | 0.00322 | 0.00593778 | 0.00599633
BELKA | UPN200 | +7.200 | +7.400 | 2 | 4 | 48.9 | 0.1 | 26.1 | 1.2 | 75 | 1935 | k88 | 1.2771 | 0.00322 | 0.00617284 | 0.0062307
BELKA | UPN200 | +7.200 | +7.400 | 2 | 4 | 48.9 | 0.1 | 26.1 | 1.2 | 75 | 1935 | k87 | 1.2771 | 0.00322 | 0.00617284 | 0.0062307
BELKA | UPN200 | +5.550 | +5.750 | 2 | 4 | 37.6 | 0.1 | 26.1 | 1 | 75 | 1487.2 | k96 | 0.981561 | 0.00322 | 0.00472672 | 0.00478883
BELKA | UPN200 | +5.550 | +5.750 | 2 | 4 | 37.6 | 0.1 | 26.1 | 1 | 75 | 1487.2 | k95 | 0.981561 | 0.00322 | 0.00472672 | 0.00478883
BELKA | UPN200 | +5.550 | +5.750 | 2 | 4 | 39.4 | 0.1 | 26.1 | 1.1 | 75 | 1560 | k94 | 1.0296 | 0.00322 | 0.00496178 | 0.0050232
BELKA | UPN200 | +5.550 | +5.750 | 2 | 4 | 39.4 | 0.1 | 26.1 | 1.1 | 75 | 1560 | k93 | 1.0296 | 0.00322 | 0.00496178 | 0.0050232
BELKA | UPN200 | +3.900 | +4.100 | 2 | 4 | 47.1 | 0.1 | 26.1 | 1.2 | 75 | 1862.2 | k92 | 1.22906 | 0.00322 | 0.00593778 | 0.00599633
BELKA | UPN200 | +3.900 | +4.100 | 2 | 4 | 47.1 | 0.1 | 26.1 | 1.2 | 75 | 1862.2 | k91 | 1.22906 | 0.00322 | 0.00593778 | 0.00599633
BELKA | UPN200 | +3.900 | +4.100 | 2 | 4 | 48.9 | 0.1 | 26.1 | 1.2 | 75 | 1935 | k88 | 1.2771 | 0.00322 | 0.00617284 | 0.0062307
BELKA | UPN200 | +3.900 | +4.100 | 2 | 4 | 48.9 | 0.1 | 26.1 | 1.2 | 75 | 1935 | k87 | 1.2771 | 0.00322 | 0.00617284 | 0.0062307
BELKA | UPN200 | +2.780 | +2.980 | 2 | 4 | 64.4 | 0.2 | 26.1 | 1.8 | 75 | 2547.2 | k86 | 1.68116 | 0.00322 | 0.00814999 | 0.00820203
BELKA | UPN200 | +2.780 | +2.980 | 2 | 4 | 64.4 | 0.2 | 26.1 | 1.8 | 75 | 2547.2 | k85 | 1.68116 | 0.00322 | 0.00814999 | 0.00820203

# IfcDiscreteAccessory: BLACHA (288)
In: Undefined
Name | Description | Material | Bottom elevation | Top elevation | Phase | Class | Weight (kg) | Volume (m3) | Gross footprint area (m2) | Area per tons (m2) | Net surface area (m2) | Height (mm) | Width (mm) | Length (mm) | LoadBearing | Reference | NetArea (m2) | GrossArea (m2) | CrossSectionArea (m2) | NetVolume (m3) = GrossVolume (m3)
2 x BLACHA | BL10*55 | STEEL/S235 | +13.858 | +13.944 | 1 | 99 | 0.3 | 0 | 0 | 33.3 | 0 | 55 | 10 | 80 | yes | b73 | 0.0115 | 0.0115 | 0.00055 | 0.000044
BLACHA | BL10*125 | STEEL/S235 | +13.885 | +13.968 | 1 | 99 | 0.8 | 0 | 0 | 30.7 | 0 | 125 | 10 | 80 | yes | b72 | 0.0241 | 0.0241 | 0.00125 | 0.0001
BLACHA | BL10*125 | STEEL/S235 | +13.886 | +13.968 | 1 | 99 | 0.8 | 0 | 0 | 30.7 | 0 | 125 | 10 | 80 | yes | b71 | 0.0241 | 0.0241 | 0.00125 | 0.0001
2 x BLACHA | BL10*120 | STEEL/S235 | +13.865 | +13.947 | 1 | 99 | 0.8 | 0 | 0 | 30.7 | 0 | 120 | 10 | 80 | yes | b37 | 0.0232 | 0.0232 | 0.0012 | 0.000096
2 x BLACHA | BL10*120 | STEEL/S235 | +13.866 | +13.949 | 1 | 99 | 0.8 | 0 | 0 | 30.7 | 0 | 120 | 10 | 80 | yes | b38 | 0.0232 | 0.0232 | 0.0012 | 0.000096
2 x BLACHA | BL10*60 | STEEL/S235 | +13.925 | +14.025 | 2 | 99 | 0.5 | 0 | 0 | 32.3 | 0 | 60 | 10 | 100 | yes | b70 | 0.0152 | 0.0152 | 0.0006 | 0.00006
BLACHA | BL10*120 | STEEL/S235 | +13.813 | +13.933 | 1 | 99 | 0.8 | 0 | 0 | 31 | 0 | 120 | 10 | 75 | yes | fb8 | 0.0219 | 0.0219 | 0.0012 | 0.00009
BLACHA | BL10*120 | STEEL/S235 | +13.776 | +13.896 | 1 | 99 | 0.6 | 0 | 0 | 31 | 0 | 120 | 10 | 75 | yes | fb8 | 0.0219 | 0.0219 | 0.0012 | 0.00009
2 x BLACHA | BL10*120 | STEEL/S235 | +13.796 | +13.917 | 1 | 99 | 0.6 | 0 | 0 | 31 | 0 | 120 | 10 | 75 | yes | fb8 | 0.0219 | 0.0219 | 0.0012 | 0.0000900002
BLACHA | BL10*120 | STEEL/S235 | +13.793 | +13.913 | 1 | 99 | 0.6 | 0 | 0 | 31 | 0 | 120 | 10 | 75 | yes | fb8 | 0.0219 | 0.0219 | 0.0012 | 0.00009
BLACHA | BL10*120 | STEEL/S235 | +13.801 | +13.921 | 1 | 99 | 0.6 | 0 | 0 | 31 | 0 | 120 | 10 | 75 | yes | fb8 | 0.0219 | 0.0219 | 0.0012 | 0.00009
2 x BLACHA | BL5*50 | STEEL/S235 | +14.116 | +15.042 | 1 | 1 | 1.8 | 0 | 0 | 56.3 | 0.1 | 50 | 5 | 926 | no | b43 | 0.10236 | 0.0463 | 0.000025 | 0.0002315
BLACHA | BL5*50 | STEEL/S235 | +14.113 | +15.039 | 1 | 1 | 1.8 | 0 | 0 | 56.3 | 0.1 | 50 | 5 | 926 | no | b43 | 0.10236 | 0.0463 | 0.000025 | 0.0002315
BLACHA | BL5*50 | STEEL/S235 | +14.120 | +15.046 | 1 | 1 | 1.8 | 0 | 0 | 56.3 | 0.1 | 50 | 5 | 926 | no | b43 | 0.10236 | 0.0463 | 0.000025 | 0.0002315
2 x BLACHA | BL12*190 | STEEL/S355 | +13.339 | +13.529 | 1 | 99 | 1.3 | 0 | 0 | 26.2 | 0 | 190 | 12 | 70 | yes | b24 | 0.03284 | 0.03284 | 0.00228 | 0.0001596
2 x BLACHA | BL12*70 | STEEL/S355 | +12.696 | +12.946 | 1 | 99 | 1.6 | 0 | 0 | 25.9 | 0 | 70 | 12 | 250 | yes | b25 | 0.04268 | 0.04268 | 0.00084 | 0.00021
BLACHA | BL10*120 | STEEL/S235 | +13.824 | +13.906 | 1 | 99 | 0.8 | 0 | 0 | 30.7 | 0 | 120 | 10 | 80 | yes | b37 | 0.0232 | 0.0232 | 0.0012 | 0.000096
BLACHA | BL10*120 | STEEL/S235 | +13.825 | +13.907 | 1 | 99 | 0.8 | 0 | 0 | 30.7 | 0 | 120 | 10 | 80 | yes | b38 | 0.0232 | 0.0232 | 0.0012 | 0.000096
BLACHA | BL10*120 | STEEL/S235 | +13.808 | +13.890 | 1 | 99 | 0.8 | 0 | 0 | 30.7 | 0 | 120 | 10 | 80 | yes | b38 | 0.0232 | 0.0232 | 0.0012 | 0.000096
BLACHA | BL10*120 | STEEL/S235 | +13.807 | +13.889 | 1 | 99 | 0.8 | 0 | 0 | 30.7 | 0 | 120 | 10 | 80 | yes | b37 | 0.0232 | 0.0232 | 0.0012 | 0.000096
BLACHA | BL12*90 | STEEL/S355 | +12.851 | +12.943 | 1 | 99 | 1.8 | 0 | 0 | 25.3 | 0 | 90 | 12 | 210 | yes | b23 | 0.045 | 0.045 | 0.00108 | 0.0002268
2 x BLACHA | BL10*120 | STEEL/S235 | +13.845 | +13.927 | 1 | 99 | 0.8 | 0 | 0 | 30.7 | 0 | 120 | 10 | 80 | yes | b37 | 0.0232 | 0.0232 | 0.0012 | 0.000096
2 x BLACHA | BL10*120 | STEEL/S235 | +13.846 | +13.928 | 1 | 99 | 0.8 | 0 | 0 | 30.7 | 0 | 120 | 10 | 80 | yes | b38 | 0.0232 | 0.0232 | 0.0012 | 0.000096
2 x BLACHA | BL12*190 | STEEL/S355 | +13.628 | +13.819 | 1 | 99 | 1.3 | 0 | 0 | 26.2 | 0 | 190 | 12 | 70 | yes | b24 | 0.03284 | 0.03284 | 0.00228 | 0.0001596
BLACHA | BL12*90 | STEEL/S355 | +12.812 | +12.905 | 1 | 99 | 1.8 | 0 | 0 | 25.3 | 0 | 90 | 12 | 210 | yes | b23 | 0.045 | 0.045 | 0.00108 | 0.0002268
BLACHA | BL12*190 | STEEL/S355 | +13.590 | +13.780 | 1 | 99 | 1.3 | 0 | 0 | 26.2 | 0 | 190 | 12 | 70 | yes | b24 | 0.03284 | 0.03284 | 0.00228 | 0.0001596
2 x BLACHA | BL10*140 | STEEL/S235 | +13.926 | +14.026 | 2 | 99 | 1.1 | 0 | 0 | 29.8 | 0 | 140 | 10 | 100 | yes | b68 | 0.0328 | 0.0328 | 0.0014 | 0.00014
2 x BLACHA | BL10*140 | STEEL/S235 | +13.926 | +14.026 | 2 | 99 | 1.1 | 0 | 0 | 29.8 | 0 | 140 | 10 | 100 | yes | b69 | 0.0328 | 0.0328 | 0.0014 | 0.00014
BLACHA | BL10*140 | STEEL/S235 | +13.925 | +14.025 | 2 | 99 | 1.1 | 0 | 0 | 29.8 | 0 | 140 | 10 | 100 | yes | b69 | 0.0328 | 0.0328 | 0.0014 | 0.00014
BLACHA | BL10*140 | STEEL/S235 | +13.925 | +14.025 | 2 | 99 | 1.1 | 0 | 0 | 29.8 | 0 | 140 | 10 | 100 | yes | b68 | 0.0328 | 0.0328 | 0.0014 | 0.00014
BLACHA | BL40X5 | STEEL/S235 | +13.918 | +13.972 | 2 | 99 | 0.1 | 0 | 0 | 62 | 0 | 40 | 5 | 54 | yes | x2 | 0.00526 | 0.00526 | 0.0002 | 0.0000108
3 x BLACHA | BL16*100 | STEEL/S235 | +13.782 | +13.882 | 2 | 99 | 2.8 | 0 | 0 | 19.6 | 0.1 | 100 | 16 | 220 | yes | b42 | 0.05424 | 0.05424 | 0.0016 | 0.000352
BLACHA | BL16*100 | STEEL/S235 | +12.782 | +12.882 | 2 | 99 | 2.8 | 0 | 0 | 19.6 | 0.1 | 100 | 16 | 220 | yes | b42 | 0.05424 | 0.05424 | 0.0016 | 0.000352
BLACHA | BL16*100 | STEEL/S235 | +12.781 | +12.881 | 2 | 99 | 2.8 | 0 | 0 | 19.6 | 0.1 | 100 | 16 | 220 | yes | b42 | 0.05424 | 0.05424 | 0.0016 | 0.000352
4 x BLACHA | BL8*80 | STEEL/S235 | +16.540 | +16.630 | 5 | 1 | 0.3 | 0 | 0 | 38.1 | 0 | 80 | 8 | 90 | no | b55 | 0.0159844 | 0.0072 | 0.000064 | 0.00005344
3 x BLACHA | BL8*80 | STEEL/S235 | +16.364 | +16.454 | 5 | 1 | 0.3 | 0 | 0 | 38.1 | 0 | 80 | 8 | 90 | no | b55 | 0.0159844 | 0.0072 | 0.000064 | 0.00005344
BLACHA | BL10*120 | STEEL/S235 | +13.654 | +13.774 | 1 | 99 | 0.6 | 0 | 0 | 31 | 0 | 120 | 10 | 75 | yes | fb8 | 0.0219 | 0.0219 | 0.0012 | 0.00009
BLACHA | BL10*120 | STEEL/S235 | +13.666 | +13.786 | 1 | 99 | 0.6 | 0 | 0 | 31 | 0 | 120 | 10 | 75 | yes | fb8 | 0.0219 | 0.0219 | 0.0012 | 0.00009
BLACHA | BL10*120 | STEEL/S235 | +13.679 | +13.799 | 1 | 99 | 0.6 | 0 | 0 | 31 | 0 | 120 | 10 | 75 | yes | fb8 | 0.0219 | 0.0219 | 0.0012 | 0.00009
BLACHA | BL10*120 | STEEL/S235 | +13.691 | +13.811 | 1 | 99 | 0.6 | 0 | 0 | 31 | 0 | 120 | 10 | 75 | yes | fb8 | 0.0219 | 0.0219 | 0.0012 | 0.00009
BLACHA | BL10*120 | STEEL/S235 | +13.703 | +13.823 | 1 | 99 | 0.6 | 0 | 0 | 31 | 0 | 120 | 10 | 75 | yes | fb8 | 0.0219 | 0.0219 | 0.0012 | 0.00009
BLACHA | BL10*120 | STEEL/S235 | +13.715 | +13.836 | 1 | 99 | 0.6 | 0 | 0 | 31 | 0 | 120 | 10 | 75 | yes | fb8 | 0.0219 | 0.0219 | 0.0012 | 0.00009
BLACHA | BL10*120 | STEEL/S235 | +13.728 | +13.848 | 1 | 99 | 0.6 | 0 | 0 | 31 | 0 | 120 | 10 | 75 | yes | fb8 | 0.0219 | 0.0219 | 0.0012 | 0.00009
BLACHA | BL10*120 | STEEL/S235 | +13.740 | +13.860 | 1 | 99 | 0.6 | 0 | 0 | 31 | 0 | 120 | 10 | 75 | yes | fb8 | 0.0219 | 0.0219 | 0.0012 | 0.00009
BLACHA | BL10*120 | STEEL/S235 | +13.752 | +13.872 | 1 | 99 | 0.6 | 0 | 0 | 31 | 0 | 120 | 10 | 75 | yes | fb8 | 0.0219 | 0.0219 | 0.0012 | 0.00009
BLACHA | BL10*120 | STEEL/S235 | +13.765 | +13.885 | 1 | 99 | 0.6 | 0 | 0 | 31 | 0 | 120 | 10 | 75 | yes | fb8 | 0.0219 | 0.0219 | 0.0012 | 0.00009
BLACHA | BL10*120 | STEEL/S235 | +13.777 | +13.897 | 1 | 99 | 0.6 | 0 | 0 | 31 | 0 | 120 | 10 | 75 | yes | fb8 | 0.0219 | 0.0219 | 0.0012 | 0.00009
BLACHA | BL10*120 | STEEL/S235 | +13.789 | +13.909 | 1 | 99 | 0.6 | 0 | 0 | 31 | 0 | 120 | 10 | 75 | yes | fb8 | 0.0219 | 0.0219 | 0.0012 | 0.00009
6 x BLACHA | BL5*120 | STEEL/S355 | +13.821 | +13.941 | 1 | 99 | 1.1 | 0 | 0 | 54.1 | 0.1 | 120 | 5 | 240 | yes | L2 | 0.0612 | 0.0612 | 0.0006 | 0.000144
4 x BLACHA | BL20*120 | STEEL/S355 | +13.821 | +13.941 | 1 | 99 | 4.5 | 0 | 0 | 15.9 | 0.1 | 120 | 20 | 240 | yes | b6 | 0.072 | 0.072 | 0.0024 | 0.000576
BLACHA | BL10*120 | STEEL/S235 | +13.802 | +13.922 | 1 | 99 | 0.6 | 0 | 0 | 31 | 0 | 120 | 10 | 75 | yes | fb8 | 0.0219 | 0.0219 | 0.0012 | 0.00009
BLACHA | BL10*120 | STEEL/S235 | +13.814 | +13.934 | 1 | 99 | 0.6 | 0 | 0 | 31 | 0 | 120 | 10 | 75 | yes | fb8 | 0.0219 | 0.0219 | 0.0012 | 0.00009
2 x BLACHA | BL10*60 | STEEL/S235 | +13.848 | +13.908 | 1 | 99 | 0.3 | 0 | 0 | 34 | 0 | 60 | 10 | 60 | yes | b13 | 0.0096 | 0.0096 | 0.0006 | 0.000036
2 x BLACHA | BL10*60 | STEEL/S235 | +13.872 | +13.883 | 1 | 99 | 0.3 | 0 | 0 | 32.9 | 0 | 60 | 10 | 80 | yes | b12 | 0.0124 | 0.0048 | 0.0001 | 0.000048
BLACHA | BL10*97 | STEEL/S355 | +13.862 | +13.873 | 1 | 99 | 0.5 | 0 | 0 | 31.5 | 0 | 97 | 10 | 94.1 | yes | b11 | 0.0172774 | 0.00912791 | 0.0001 | 0.0000699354
6 x BLACHA | BL5*50 | STEEL/S235 | +12.633 | +13.665 | 3 | 1 | 1.9 | 0 | 0 | 56.3 | 0.1 | 50 | 5 | 1032 | no | b45 | 0.11402 | 0.0516 | 0.000025 | 0.000258
7 x BLACHA | BL10*170 | STEEL/S235 | +12.565 | +12.575 | 3 | 1 | 0.8 | 0 | 0 | 30.6 | 0 | 170 | 10 | 70 | yes | b44 | 0.0286 | 0.0286 | 0.0017 | 0.000119
BLACHA | BL5*50 | STEEL/S235 | +13.969 | +14.898 | 5 | 1 | 1.8 | 0 | 0 | 56.3 | 0.1 | 50 | 5 | 929 | no | b63 | 0.10269 | 0.04645 | 0.000025 | 0.00023225
3 x BLACHA | BL5*50 | STEEL/S235 | +13.969 | +14.895 | 5 | 1 | 1.8 | 0 | 0 | 56.3 | 0.1 | 50 | 5 | 926 | no | b43 | 0.10236 | 0.0463 | 0.000025 | 0.0002315
3 x BLACHA | BL12*200 | STEEL/S235 | +13.796 | +13.808 | 5 | 99 | 1.5 | 0 | 0 | 25.7 | 0 | 200 | 12 | 80 | yes | b56 | 0.03872 | 0.03872 | 0.0024 | 0.000192
3 x BLACHA | BL5*50 | STEEL/S235 | +14.083 | +15.009 | 1 | 1 | 1.8 | 0 | 0 | 56.3 | 0.1 | 50 | 5 | 926 | no | b43 | 0.10236 | 0.0463 | 0.000025 | 0.0002315
BLACHA | BL5*50 | STEEL/S235 | +14.086 | +15.012 | 1 | 1 | 1.8 | 0 | 0 | 56.3 | 0.1 | 50 | 5 | 926 | no | b43 | 0.10236 | 0.0463 | 0.000025 | 0.0002315
2 x BLACHA | BL10*120 | STEEL/S235 | +13.764 | +13.885 | 1 | 99 | 0.6 | 0 | 0 | 31 | 0 | 120 | 10 | 75 | yes | fb8 | 0.0219 | 0.0219 | 0.0012 | 0.00009
BLACHA | BL5*50 | STEEL/S235 | +14.030 | +14.956 | 1 | 1 | 1.8 | 0 | 0 | 56.3 | 0.1 | 50 | 5 | 926 | no | b43 | 0.10236 | 0.0463 | 0.000025 | 0.0002315
BLACHA | BL10*120 | STEEL/S235 | +13.674 | +13.794 | 1 | 99 | 0.6 | 0 | 0 | 31 | 0 | 120 | 10 | 75 | yes | fb8 | 0.0219 | 0.0219 | 0.0012 | 0.00009
BLACHA | BL10*120 | STEEL/S235 | +13.686 | +13.806 | 1 | 99 | 0.6 | 0 | 0 | 31 | 0 | 120 | 10 | 75 | yes | fb8 | 0.0219 | 0.0219 | 0.0012 | 0.00009
BLACHA | BL10*120 | STEEL/S235 | +13.699 | +13.819 | 1 | 99 | 0.6 | 0 | 0 | 31 | 0 | 120 | 10 | 75 | yes | fb8 | 0.0219 | 0.0219 | 0.0012 | 0.00009
BLACHA | BL10*120 | STEEL/S235 | +13.711 | +13.831 | 1 | 99 | 0.6 | 0 | 0 | 31 | 0 | 120 | 10 | 75 | yes | fb8 | 0.0219 | 0.0219 | 0.0012 | 0.00009
BLACHA | BL10*120 | STEEL/S235 | +13.723 | +13.844 | 1 | 99 | 0.6 | 0 | 0 | 31 | 0 | 120 | 10 | 75 | yes | fb8 | 0.0219 | 0.0219 | 0.0012 | 0.00009
BLACHA | BL10*120 | STEEL/S235 | +13.736 | +13.856 | 1 | 99 | 0.6 | 0 | 0 | 31 | 0 | 120 | 10 | 75 | yes | fb8 | 0.0219 | 0.0219 | 0.0012 | 0.00009
BLACHA | BL10*120 | STEEL/S235 | +13.767 | +13.887 | 1 | 99 | 0.6 | 0 | 0 | 31 | 0 | 120 | 10 | 75 | yes | fb8 | 0.0219 | 0.0219 | 0.0012 | 0.00009
BLACHA | BL10*120 | STEEL/S235 | +13.785 | +13.905 | 1 | 99 | 0.6 | 0 | 0 | 31 | 0 | 120 | 10 | 75 | yes | fb8 | 0.0219 | 0.0219 | 0.0012 | 0.00009
BLACHA | BL5*50 | STEEL/S235 | +13.980 | +14.906 | 1 | 1 | 1.8 | 0 | 0 | 56.3 | 0.1 | 50 | 5 | 926 | no | b61 | 0.10236 | 0.0463 | 0.000025 | 0.0002315
BLACHA | BL5*50 | STEEL/S235 | +13.868 | +14.906 | 1 | 1 | 1.9 | 0 | 0 | 56.3 | 0.1 | 50 | 5 | 1038 | no | b60 | 0.11468 | 0.0519 | 0.000025 | 0.0002595
BLACHA | BL12*200 | STEEL/S235 | +13.795 | +13.807 | 5 | 99 | 1.5 | 0 | 0 | 25.7 | 0 | 200 | 12 | 80 | yes | b56 | 0.03872 | 0.03872 | 0.0024 | 0.000192
BLACHA | BL8*80 | STEEL/S235 | +16.364 | +16.454 | 5 | 1 | 0.3 | 0 | 0 | 38.1 | 0 | 80 | 8 | 90 | no | b41 | 0.0159844 | 0.0072 | 0.000064 | 0.00005344
2 x BLACHA | BL8*60 | STEEL/S235 | +16.459 | +16.519 | 5 | 99 | 0.2 | 0 | 0 | 40.3 | 0 | 60 | 8 | 60 | yes | b54 | 0.00912 | 0.00912 | 0.00048 | 0.0000288
2 x BLACHA | BL8*60 | STEEL/S235 | +16.460 | +16.532 | 5 | 99 | 0.3 | 0 | 0 | 39.7 | 0 | 60 | 8 | 70 | yes | b53 | 0.01048 | 0.0042 | 0.000064 | 0.0000336
2 x BLACHA | BL8*75 | STEEL/S235 | +16.462 | +16.539 | 5 | 99 | 0.3 | 0 | 0 | 39.1 | 0 | 74.7 | 8 | 77.7 | yes | b52 | 0.0120835 | 0.00580643 | 0.000064 | 0.0000393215
2 x BLACHA | BL8*60 | STEEL/S235 | +16.305 | +16.365 | 5 | 99 | 0.2 | 0 | 0 | 40.3 | 0 | 60 | 8 | 60 | yes | b54 | 0.00912 | 0.00912 | 0.00048 | 0.0000288
2 x BLACHA | BL8*60 | STEEL/S235 | +16.292 | +16.364 | 5 | 99 | 0.3 | 0 | 0 | 39.7 | 0 | 60 | 8 | 70 | yes | b53 | 0.01048 | 0.0042 | 0.000064 | 0.0000336
2 x BLACHA | BL8*75 | STEEL/S235 | +16.285 | +16.363 | 5 | 99 | 0.3 | 0 | 0 | 39.1 | 0 | 74.7 | 8 | 77.7 | yes | b52 | 0.0120835 | 0.00580643 | 0.000064 | 0.0000393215
4 x BLACHA | BL1*60 | STEEL/S235 | +16.286 | +16.345 | 5 | 1 | 0 | 0 | 0 | 263.3 | 0 | 60 | 1 | 60 | no | b51 | 0.00744 | 0.0036 | 0.000001 | 0.0000036
2 x BLACHA | BL1*60 | STEEL/S235 | +16.577 | +16.637 | 5 | 1 | 0 | 0 | 0 | 263.3 | 0 | 60 | 1 | 60 | no | xx66 | 0.00744 | 0.0036 | 0.000001 | 0.0000036
2 x BLACHA | BL1*60 | STEEL/S235 | +16.577 | +16.637 | 5 | 1 | 0 | 0 | 0 | 263.3 | 0 | 60 | 1 | 60 | no | b51 | 0.00744 | 0.0036 | 0.000001 | 0.0000036
2 x BLACHA | BL3*80 | STEEL/S235 | +16.460 | +16.540 | 5 | 1 | 0.2 | 0 | 0 | 91.3 | 0 | 80 | 3 | 80 | no | b50 | 0.01376 | 0.0064 | 0.000009 | 0.0000192
2 x BLACHA | BL3*80 | STEEL/S235 | +16.284 | +16.364 | 5 | 1 | 0.2 | 0 | 0 | 91.3 | 0 | 80 | 3 | 80 | no | b50 | 0.01376 | 0.0064 | 0.000009 | 0.0000192
BLACHA | BL10*170 | STEEL/S235 | +12.565 | +12.575 | 3 | 1 | 0.8 | 0 | 0 | 31.2 | 0 | 170 | 10 | 60 | yes | b49 | 0.025 | 0.025 | 0.0017 | 0.000102
2 x BLACHA | BL12*170 | STEEL/S235 | +13.814 | +13.899 | 3 | 99 | 1.1 | 0 | 0 | 26.4 | 0 | 170 | 12 | 70 | yes | fb21 | 0.02956 | 0.02956 | 0.00204 | 0.0001428
2 x BLACHA | BL12*170 | STEEL/S235 | +13.452 | +13.538 | 3 | 99 | 1.1 | 0 | 0 | 26.4 | 0 | 170 | 12 | 70 | yes | fb21 | 0.02956 | 0.02956 | 0.00204 | 0.0001428
2 x BLACHA | BL12*170 | STEEL/S235 | +13.091 | +13.177 | 3 | 99 | 1.1 | 0 | 0 | 26.4 | 0 | 170 | 12 | 70 | yes | fb21 | 0.02956 | 0.02956 | 0.00204 | 0.0001428
2 x BLACHA | BL12*170 | STEEL/S235 | +12.729 | +12.815 | 3 | 99 | 1.1 | 0 | 0 | 26.4 | 0 | 170 | 12 | 70 | yes | fb21 | 0.02956 | 0.02956 | 0.00204 | 0.0001428
BLACHA | BL16*150 | STEEL/S235 | +12.566 | +12.582 | 3 | 99 | 4.2 | 0 | 0 | 18.8 | 0.1 | 150 | 16 | 220 | yes | b47 | 0.07784 | 0.07784 | 0.0024 | 0.000528
BLACHA | BL16*150 | STEEL/S235 | +12.565 | +12.581 | 3 | 99 | 4.2 | 0 | 0 | 18.8 | 0.1 | 150 | 16 | 220 | yes | b47 | 0.07784 | 0.07784 | 0.0024 | 0.000528
BLACHA | BL110X6 | STEEL/S355 | +13.920 | +13.970 | 2 | 99 | 0.3 | 0 | 0 | 49.9 | 0 | 110 | 6 | 50 | yes | b20 | 0.01292 | 0.01292 | 0.00066 | 0.000033
2 x BLACHA | BL10*140 | STEEL/S235 | +13.909 | +13.989 | 2 | 99 | 0.8 | 0 | 0 | 30.4 | 0 | 140 | 10 | 80 | yes | b31 | 0.0268 | 0.0268 | 0.0014 | 0.000112
2 x BLACHA | BL10*140 | STEEL/S235 | +13.909 | +13.989 | 2 | 99 | 0.8 | 0 | 0 | 30.4 | 0 | 140 | 10 | 80 | yes | b30 | 0.0268 | 0.0268 | 0.0014 | 0.000112
BLACHA | BL12*180 | STEEL/S235 | +12.781 | +12.861 | 2 | 99 | 1.5 | 0 | 0 | 25.7 | 0 | 180 | 12 | 80 | yes | b28 | 0.0350407 | 0.0350407 | 0.00216 | 0.000172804
4 x BLACHA | BL12*100 | STEEL/S235 | +13.781 | +13.881 | 2 | 99 | 1.9 | 0 | 0 | 25.1 | 0 | 100 | 12 | 200 | yes | b29 | 0.0472 | 0.0472 | 0.0012 | 0.00024
BLACHA | BL12*180 | STEEL/S235 | +12.782 | +12.862 | 2 | 99 | 1.5 | 0 | 0 | 25.7 | 0 | 180 | 12 | 80 | yes | b28 | 0.0350404 | 0.0350404 | 0.00216 | 0.000172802
2 x BLACHA | BL12*180 | STEEL/S235 | +12.781 | +12.861 | 2 | 99 | 1.5 | 0 | 0 | 25.7 | 0 | 180 | 12 | 80 | yes | b28 | 0.03504 | 0.03504 | 0.00216 | 0.0001728
2 x BLACHA | BL10*140 | STEEL/S235 | +13.925 | +14.025 | 2 | 99 | 1.1 | 0 | 0 | 29.8 | 0 | 140 | 10 | 100 | yes | b40 | 0.0328 | 0.0328 | 0.0014 | 0.00014
2 x BLACHA | BL10*140 | STEEL/S235 | +13.925 | +14.025 | 2 | 99 | 1.1 | 0 | 0 | 29.8 | 0 | 140 | 10 | 100 | yes | b39 | 0.0327808 | 0.0327808 | 0.0014 | 0.00013991
2 x BLACHA | BL12*170 | STEEL/S235 | +12.416 | +12.503 | 2 | 99 | 1.1 | 0 | 0 | 26.4 | 0 | 170 | 12 | 70 | yes | fb19 | 0.02956 | 0.02956 | 0.00204 | 0.0001428
2 x BLACHA | BL12*170 | STEEL/S235 | +12.866 | +12.953 | 2 | 99 | 1.1 | 0 | 0 | 26.4 | 0 | 170 | 12 | 70 | yes | fb19 | 0.02956 | 0.02956 | 0.00204 | 0.0001428
2 x BLACHA | BL12*170 | STEEL/S235 | +13.316 | +13.403 | 2 | 99 | 1.1 | 0 | 0 | 26.4 | 0 | 170 | 12 | 70 | yes | fb19 | 0.02956 | 0.02956 | 0.00204 | 0.0001428
2 x BLACHA | BL12*170 | STEEL/S235 | +13.766 | +13.853 | 2 | 99 | 1.1 | 0 | 0 | 26.4 | 0 | 170 | 12 | 70 | yes | fb19 | 0.02956 | 0.02956 | 0.00204 | 0.0001428
BLACHA | BL5*50 | STEEL/S235 | +12.449 | +13.480 | 2 | 1 | 1.9 | 0 | 0 | 56.3 | 0.1 | 50 | 5 | 1031 | no | b45 | 0.11391 | 0.05155 | 0.000025 | 0.00025775
BLACHA | BL5*50 | STEEL/S235 | +14.034 | +14.960 | 1 | 1 | 1.8 | 0 | 0 | 56.3 | 0.1 | 50 | 5 | 926 | no | b43 | 0.10236 | 0.0463 | 0.000025 | 0.0002315
BLACHA | BL5*50 | STEEL/S235 | +14.080 | +15.006 | 1 | 1 | 1.8 | 0 | 0 | 56.3 | 0.1 | 50 | 5 | 926 | no | b43 | 0.10236 | 0.0463 | 0.000025 | 0.0002315
BLACHA | BL10*120 | STEEL/S235 | +13.661 | +13.782 | 1 | 99 | 0.6 | 0 | 0 | 31 | 0 | 120 | 10 | 75 | yes | fb8 | 0.0219 | 0.0219 | 0.0012 | 0.00009
BLACHA | BL10*120 | STEEL/S235 | +13.748 | +13.868 | 1 | 99 | 0.6 | 0 | 0 | 31 | 0 | 120 | 10 | 75 | yes | fb8 | 0.0219 | 0.0219 | 0.0012 | 0.00009
BLACHA | BL10*120 | STEEL/S235 | +13.761 | +13.881 | 1 | 99 | 0.6 | 0 | 0 | 31 | 0 | 120 | 10 | 75 | yes | fb8 | 0.0219 | 0.0219 | 0.0012 | 0.00009
BLACHA | BL12*190 | STEEL/S355 | +13.651 | +13.842 | 1 | 99 | 1.3 | 0 | 0 | 26.2 | 0 | 190 | 12 | 70 | yes | b24 | 0.03284 | 0.03284 | 0.00228 | 0.0001596
BLACHA | BL12*190 | STEEL/S355 | +13.665 | +13.856 | 1 | 99 | 1.3 | 0 | 0 | 26.2 | 0 | 190 | 12 | 70 | yes | b24 | 0.03284 | 0.03284 | 0.00228 | 0.0001596
BLACHA | BL10*120 | STEEL/S235 | +13.824 | +13.907 | 1 | 99 | 0.8 | 0 | 0 | 30.7 | 0 | 120 | 10 | 80 | yes | b37 | 0.0232 | 0.0232 | 0.0012 | 0.000096
BLACHA | BL10*120 | STEEL/S235 | +13.826 | +13.908 | 1 | 99 | 0.8 | 0 | 0 | 30.7 | 0 | 120 | 10 | 80 | yes | b38 | 0.0232 | 0.0232 | 0.0012 | 0.000096
BLACHA | BL10*120 | STEEL/S235 | +13.804 | +13.886 | 1 | 99 | 0.8 | 0 | 0 | 30.7 | 0 | 120 | 10 | 80 | yes | b37 | 0.0232 | 0.0232 | 0.0012 | 0.000096
BLACHA | BL10*120 | STEEL/S235 | +13.805 | +13.887 | 1 | 99 | 0.8 | 0 | 0 | 30.7 | 0 | 120 | 10 | 80 | yes | b38 | 0.0232 | 0.0232 | 0.0012 | 0.000096
BLACHA | BL10*120 | STEEL/S235 | +13.867 | +13.950 | 1 | 99 | 0.8 | 0 | 0 | 30.7 | 0 | 120 | 10 | 80 | yes | b37 | 0.0231966 | 0.0231966 | 0.0012 | 0.0000959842
BLACHA | BL10*120 | STEEL/S235 | +13.868 | +13.951 | 1 | 99 | 0.8 | 0 | 0 | 30.7 | 0 | 120 | 10 | 80 | yes | b38 | 0.0232 | 0.0232 | 0.0012 | 0.000096
2 x BLACHA | BL12*90 | STEEL/S355 | +12.871 | +12.964 | 1 | 99 | 1.8 | 0 | 0 | 25.3 | 0 | 90 | 12 | 210 | yes | b23 | 0.045 | 0.045 | 0.00108 | 0.0002268
BLACHA | BL12*90 | STEEL/S355 | +12.851 | +12.944 | 1 | 99 | 1.8 | 0 | 0 | 25.3 | 0 | 90 | 12 | 210 | yes | b23 | 0.045 | 0.045 | 0.00108 | 0.0002268
BLACHA | BL12*190 | STEEL/S355 | +13.587 | +13.778 | 1 | 99 | 1.3 | 0 | 0 | 26.2 | 0 | 190 | 12 | 70 | yes | b24 | 0.03284 | 0.03284 | 0.00228 | 0.0001596
BLACHA | BL12*90 | STEEL/S355 | +12.810 | +12.903 | 1 | 99 | 1.8 | 0 | 0 | 25.3 | 0 | 90 | 12 | 210 | yes | b23 | 0.045 | 0.045 | 0.00108 | 0.0002268
2 x BLACHA | BL12*190 | STEEL/S355 | +13.648 | +13.839 | 1 | 99 | 1.3 | 0 | 0 | 26.2 | 0 | 190 | 12 | 70 | yes | b24 | 0.03284 | 0.03284 | 0.00228 | 0.0001596
BLACHA | BL12*110 | STEEL/S355 | +12.876 | +12.989 | 1 | 99 | 2.2 | 0 | 0 | 24.8 | 0.1 | 110 | 12 | 210 | yes | b22 | 0.05388 | 0.05388 | 0.00132 | 0.0002772
BLACHA | BL40X5 | STEEL/S235 | +13.919 | +13.974 | 3 | 99 | 0.1 | 0 | 0 | 62 | 0 | 40 | 5 | 54 | yes | x2 | 0.00526 | 0.00526 | 0.0002 | 0.0000108
BLACHA | BL40X5 | STEEL/S235 | +13.918 | +13.972 | 3 | 99 | 0.1 | 0 | 0 | 62 | 0 | 40 | 5 | 54 | yes | x2 | 0.00526 | 0.00526 | 0.0002 | 0.0000108
BLACHA | BL110X6 | STEEL/S355 | +13.921 | +13.972 | 3 | 99 | 0.3 | 0 | 0 | 49.9 | 0 | 110 | 6 | 50 | yes | b21 | 0.01292 | 0.01292 | 0.00066 | 0.000033
BLACHA | BL110X6 | STEEL/S355 | +13.920 | +13.970 | 3 | 99 | 0.3 | 0 | 0 | 49.9 | 0 | 110 | 6 | 50 | yes | b20 | 0.01292 | 0.01292 | 0.00066 | 0.000033
BLACHA | BL8*50 | STEEL/S235 | +13.935 | +13.950 | 3 | 99 | 0.3 | 0 | 0 | 42.5 | 0 | 50 | 8 | 150 | yes | b36 | 0.01788 | 0.0075 | 0.000064 | 0.0000536
BLACHA | BL8*80 | STEEL/S235 | +13.930 | +13.943 | 3 | 99 | 0.3 | 0 | 0 | 39.2 | 0 | 80.4 | 8 | 98.8 | yes | b35 | 0.012783 | 0.00793704 | 0.000064 | 0.0000415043
BLACHA | BL8*50 | STEEL/S235 | +13.864 | +13.879 | 3 | 99 | 0.3 | 0 | 0 | 43.1 | 0 | 50 | 8 | 150 | yes | b34 | 0.0172008 | 0.0075 | 0.000064 | 0.000050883
BLACHA | BL8*80 | STEEL/S235 | +13.855 | +13.868 | 3 | 99 | 0.3 | 0 | 0 | 39.2 | 0 | 80.4 | 8 | 98.8 | yes | b33 | 0.012783 | 0.00793704 | 0.000064 | 0.0000415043
4 x BLACHA | BL10*140 | STEEL/S235 | +13.910 | +13.990 | 3 | 99 | 0.8 | 0 | 0 | 30.4 | 0 | 140 | 10 | 80 | yes | b30 | 0.0268 | 0.0268 | 0.0014 | 0.000112
4 x BLACHA | BL10*140 | STEEL/S235 | +13.910 | +13.990 | 3 | 99 | 0.8 | 0 | 0 | 30.4 | 0 | 140 | 10 | 80 | yes | b31 | 0.0268 | 0.0268 | 0.0014 | 0.000112
BLACHA | BL12*180 | STEEL/S235 | +12.782 | +12.862 | 3 | 99 | 1.5 | 0 | 0 | 25.7 | 0 | 180 | 12 | 80 | yes | b28 | 0.03504 | 0.03504 | 0.00216 | 0.0001728
BLACHA | BL12*100 | STEEL/S235 | +13.782 | +13.882 | 3 | 99 | 1.9 | 0 | 0 | 25.1 | 0 | 100 | 12 | 200 | yes | b29 | 0.0472 | 0.0472 | 0.0012 | 0.00024
3 x BLACHA | BL12*180 | STEEL/S235 | +12.781 | +12.861 | 3 | 99 | 1.5 | 0 | 0 | 25.7 | 0 | 180 | 12 | 80 | yes | b28 | 0.03504 | 0.03504 | 0.00216 | 0.0001728
3 x BLACHA | BL12*100 | STEEL/S235 | +13.781 | +13.881 | 3 | 99 | 1.9 | 0 | 0 | 25.1 | 0 | 100 | 12 | 200 | yes | b29 | 0.0472 | 0.0472 | 0.0012 | 0.00024
2 x BLACHA | BL16*170 | STEEL/S355 | +12.481 | +12.599 | 1 | 99 | 3.6 | 0 | 0 | 18.9 | 0.1 | 170 | 16 | 170 | yes | b2 | 0.06868 | 0.06868 | 0.00272 | 0.0004624
2 x BLACHA | BL16*170 | STEEL/S355 | +12.506 | +12.624 | 1 | 99 | 3.6 | 0 | 0 | 18.9 | 0.1 | 170 | 16 | 170 | yes | b2 | 0.06868 | 0.06868 | 0.00272 | 0.0004624
2 x BLACHA | BL15*180 | STEEL/S355 | +13.726 | +13.741 | 1 | 99 | 3.8 | 0 | 0 | 19.8 | 0.1 | 180 | 15 | 180 | yes | b1 | 0.0756 | 0.0756 | 0.0027 | 0.000486
2 x BLACHA | BL15*180 | STEEL/S355 | +13.700 | +13.715 | 1 | 99 | 3.8 | 0 | 0 | 19.8 | 0.1 | 180 | 15 | 180 | yes | b1 | 0.0756 | 0.0756 | 0.0027 | 0.000486
2 x BLACHA | BL5*180 | STEEL/S355 | +13.715 | +13.720 | 1 | 99 | 1.3 | 0 | 0 | 53.8 | 0.1 | 180 | 5 | 180 | yes | L4 | 0.0684 | 0.0684 | 0.0009 | 0.000162
2 x BLACHA | BL5*180 | STEEL/S355 | +13.720 | +13.725 | 1 | 99 | 1.3 | 0 | 0 | 53.8 | 0.1 | 180 | 5 | 180 | yes | L4 | 0.0684 | 0.0684 | 0.0009 | 0.000162
2 x BLACHA | BL15*180 | STEEL/S355 | +13.605 | +13.620 | 1 | 1 | 3.8 | 0 | 0 | 19.8 | 0.1 | 180 | 15 | 180 | no | b1 | 0.0756 | 0.0324 | 0.000225 | 0.000486
BLACHA | BL20*290 | STEEL/S355 | +5.260 | +5.280 | 1 | 1 | 13.2 | 0 | 0.1 | 14.5 | 0.2 | 290 | 20 | 290 | no | x1 | 0.1914 | 0.0841 | 0.0004 | 0.001682
6 x BLACHA | BL5*270 | STEEL/S355 | +12.740 | +13.010 | 1 | 99 | 1.8 | 0 | 0 | 53.5 | 0.1 | 270 | 5 | 160 | yes | L3 | 0.0907 | 0.0907 | 0.00135 | 0.000216
2 x BLACHA | BL16*270 | STEEL/S355 | +12.740 | +13.010 | 1 | 99 | 5.4 | 0 | 0 | 18.5 | 0.1 | 270 | 16 | 160 | yes | b4 | 0.10016 | 0.10016 | 0.00432 | 0.0006912
2 x BLACHA | BL16*170 | STEEL/S355 | +12.532 | +12.648 | 1 | 99 | 3.6 | 0 | 0 | 18.9 | 0.1 | 170 | 16 | 170 | yes | b2 | 0.06868 | 0.06868 | 0.00272 | 0.0004624
2 x BLACHA | BL16*170 | STEEL/S355 | +12.557 | +12.673 | 1 | 99 | 3.6 | 0 | 0 | 18.9 | 0.1 | 170 | 16 | 170 | yes | b2 | 0.06868 | 0.06868 | 0.00272 | 0.0004624
2 x BLACHA | BL16*170 | STEEL/S355 | +11.050 | +11.166 | 1 | 99 | 3.6 | 0 | 0 | 18.9 | 0.1 | 170 | 16 | 170 | yes | b2 | 0.06868 | 0.06868 | 0.00272 | 0.0004624
2 x BLACHA | BL16*170 | STEEL/S355 | +11.063 | +11.180 | 1 | 99 | 3.6 | 0 | 0 | 18.9 | 0.1 | 170 | 16 | 170 | yes | b2 | 0.06868 | 0.06868 | 0.00272 | 0.0004624
2 x BLACHA | BL16*170 | STEEL/S355 | +11.059 | +11.177 | 1 | 99 | 3.6 | 0 | 0 | 18.9 | 0.1 | 170 | 16 | 170 | yes | b2 | 0.06868 | 0.06868 | 0.00272 | 0.0004624
2 x BLACHA | BL16*170 | STEEL/S355 | +11.046 | +11.164 | 1 | 99 | 3.6 | 0 | 0 | 18.9 | 0.1 | 170 | 16 | 170 | yes | b2 | 0.06868 | 0.06868 | 0.00272 | 0.0004624
2 x BLACHA | BL10*60 | STEEL/S235 | +13.855 | +13.915 | 1 | 99 | 0.3 | 0 | 0 | 34 | 0 | 60 | 10 | 60 | yes | b13 | 0.0096 | 0.0096 | 0.0006 | 0.000036
2 x BLACHA | BL10*60 | STEEL/S235 | +13.880 | +13.891 | 1 | 99 | 0.3 | 0 | 0 | 32.6 | 0 | 60 | 10 | 90 | yes | b15 | 0.0138 | 0.0054 | 0.0001 | 0.000054
BLACHA | BL10*102 | STEEL/S355 | +13.870 | +13.881 | 1 | 99 | 2.6 | 0 | 0 | 28.7 | 0.1 | 102 | 10 | 346.8 | yes | b14 | 0.0744583 | 0.0353817 | 0.0001 | 0.000330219
BLACHA | BL10*97 | STEEL/S355 | +13.862 | +13.873 | 1 | 99 | 0.5 | 0 | 0 | 31.5 | 0 | 97 | 10 | 94.1 | yes | b11 | 0.0172774 | 0.0091279 | 0.0001 | 0.0000699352
2 x BLACHA | BL16*170 | STEEL/S355 | +13.604 | +13.758 | 1 | 99 | 3.6 | 0 | 0 | 18.9 | 0.1 | 170 | 16 | 170 | yes | b2 | 0.06868 | 0.06868 | 0.00272 | 0.0004624
2 x BLACHA | BL16*170 | STEEL/S355 | +13.588 | +13.741 | 1 | 99 | 3.6 | 0 | 0 | 18.9 | 0.1 | 170 | 16 | 170 | yes | b2 | 0.06868 | 0.06868 | 0.00272 | 0.0004624
6 x BLACHA | BL5*270 | STEEL/S355 | +12.743 | +13.013 | 1 | 99 | 1.8 | 0 | 0 | 53.5 | 0.1 | 270 | 5 | 160 | yes | L3 | 0.0907 | 0.0907 | 0.00135 | 0.000216
2 x BLACHA | BL16*270 | STEEL/S355 | +12.743 | +13.013 | 1 | 99 | 5.4 | 0 | 0 | 18.5 | 0.1 | 270 | 16 | 160 | yes | b4 | 0.10016 | 0.10016 | 0.00432 | 0.0006912
2 x BLACHA | BL15*160 | STEEL/S355 | +13.570 | +13.585 | 1 | 1 | 5.2 | 0 | 0 | 19.5 | 0.1 | 160 | 15 | 270 | no | b3 | 0.0993 | 0.0432 | 0.000225 | 0.000648
2 x BLACHA | BL20*180 | STEEL/S235 | +13.585 | +13.605 | 1 | 1 | 5.2 | 0 | 0 | 15.6 | 0.1 | 180 | 20 | 180 | no | xx9 | 0.0792 | 0.0324 | 0.0004 | 0.000648
BLACHA | BL1000*2140 | MISCELLANEOUS/DUMMY | -1.000 | +0.000 | 5 | 1 | 0 | 55.6 | 55.6 | 0 | 167.6 | 2140 | 1000 | 26000 | no | yy1 | 167.56 | 55.64 | 1 | 55.64

# IfcDiscreteAccessory: COLUMN (24)
In: Undefined
Material: STEEL/S235
Tekla Common - Phase: 2; Class: 4
Tekla Quantity - Volume: 0 m3
Pset_PlateCommon - LoadBearing: no
Name | Description | Bottom elevation | Top elevation | Weight (kg) | Gross footprint area (m2) | Area per tons (m2) | Net surface area (m2) | Height (mm) = Width (mm) | Length (mm) | Reference | NetArea (m2) | GrossArea (m2) | CrossSectionArea (m2) | NetVolume (m3) | GrossVolume (m3)
2 x COLUMN | HEB140 | +12.000 | +12.140 | 180.3 | 0.7 | 23.8 | 4.4 | 140 | 5340 | xx55 | 4.2987 | 4.2987 | 0.0043 | 0.0222445 | 0.022962
2 x COLUMN | HEB140 | +8.700 | +8.840 | 180.3 | 0.7 | 23.8 | 4.4 | 140 | 5340 | xx55 | 4.2987 | 4.2987 | 0.0043 | 0.0222445 | 0.022962
2 x COLUMN | HEB140 | +5.400 | +5.540 | 180.3 | 0.7 | 23.8 | 4.4 | 140 | 5340 | xx55 | 4.2987 | 4.2987 | 0.0043 | 0.0222445 | 0.022962
2 x COLUMN | HEB140 | +2.640 | +2.780 | 153.5 | 0.7 | 23.8 | 3.7 | 140 | 4548.8 | xx54 | 3.66179 | 3.66179 | 0.0043 | 0.0188499 | 0.0195599
2 x COLUMN | SHS60*4 | +10.700 | +12.040 | 14.5 | 0 | 34.2 | 0.4 | 60 | 2133.5 | xx53 | 0.497623 | 0.509904 | 0.00085095 | 0.00185244 | 0.00189852
2 x COLUMN | SHS60*4 | +7.400 | +8.740 | 14.5 | 0 | 34.2 | 0.4 | 60 | 2133.5 | xx53 | 0.497623 | 0.509904 | 0.00085095 | 0.00185244 | 0.00189852
2 x COLUMN | SHS60*4 | +4.100 | +5.440 | 14.5 | 0 | 34.2 | 0.4 | 60 | 2133.5 | xx53 | 0.497623 | 0.509904 | 0.00085095 | 0.00185244 | 0.00189852
2 x COLUMN | SHS60*4 | +8.811 | +10.500 | 15.9 | 0 | 34.2 | 0.4 | 60 | 2324.3 | xx52 | 0.544774 | 0.544774 | 0.00085095 | 0.00202875 | 0.00202875
2 x COLUMN | SHS60*4 | +5.500 | +7.200 | 16.1 | 0 | 34.2 | 0.7 | 60 | 2351.8 | xx51 | 0.553047 | 0.554682 | 0.00085095 | 0.00205975 | 0.00206574
2 x COLUMN | SHS60*4 | +1.960 | +3.900 | 17.3 | 0 | 34.2 | 0.7 | 60 | 2518.9 | xx50 | 0.591258 | 0.591258 | 0.00085095 | 0.00220222 | 0.00220222
COLUMN | HEB160 | +1.020 | +5.282 | 191.7 | 0 | 21.5 | 4.2 | 160 | 4497.1 | xx48 | 4.12831 | 4.12831 | 0.00543 | 0.0233308 | 0.0244191
2 x COLUMN | HEB160 | +5.258 | +12.160 | 294.2 | 0 | 21.5 | 6.4 | 160 | 6902.4 | xx49 | 6.3364 | 6.3364 | 0.00543 | 0.0360485 | 0.03748
COLUMN | HEB160 | +1.020 | +5.283 | 191.7 | 0 | 21.5 | 4.2 | 160 | 4497.1 | xx48 | 4.12831 | 4.12831 | 0.00543 | 0.0233308 | 0.0244191

# IfcDiscreteAccessory: KICK_PLATE (2)
In: Undefined
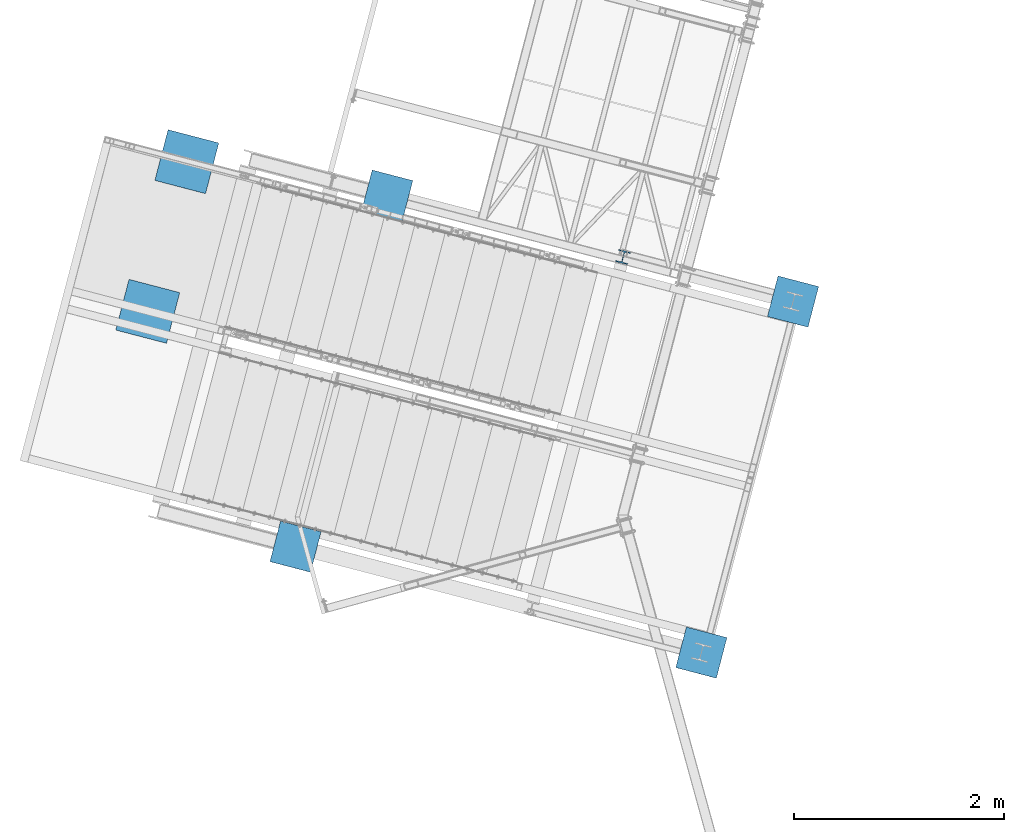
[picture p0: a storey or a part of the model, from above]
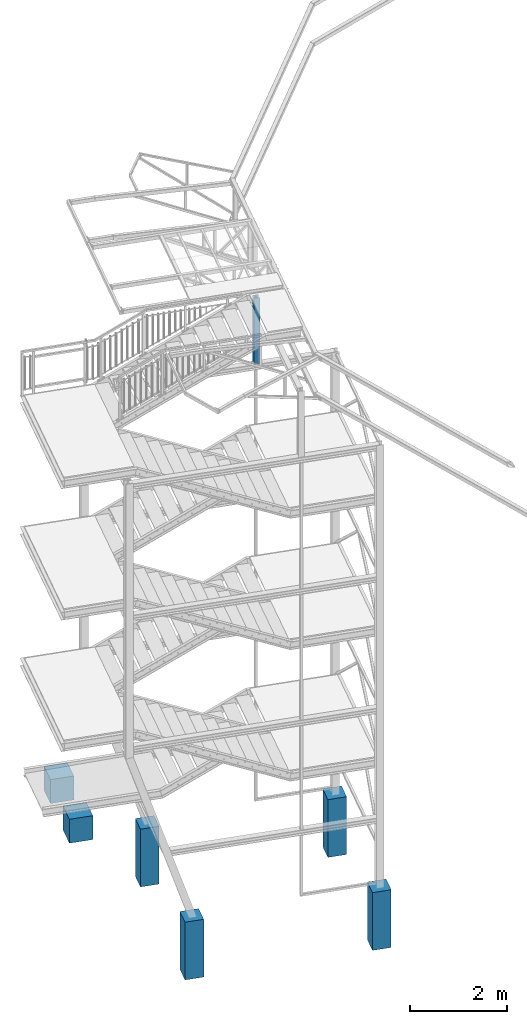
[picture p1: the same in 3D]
Properties of the parts of a building model (IFC2X3), part 3 of 5

# IfcDiscreteAccessory: KICK_PLATE (2)
Description: C100*20*2; Material: STEEL/S235JR
Tekla Common - Class: 1
Tekla Quantity - Weight: 0.2 kg; Volume: 0 m3; Gross footprint area: 0 m2; Net surface area: 0 m2; Height: 100 mm; Width: 20 mm
BaseQuantities - CrossSectionArea: 0.000276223 m2
Name | Bottom elevation | Top elevation | Phase | Area per tons (m2) | Length (mm) | LoadBearing | Reference | NetArea (m2) = GrossArea (m2) | NetVolume (m3) = GrossVolume (m3)
KICK_PLATE | +13.811 | +13.911 | 1 | 132.4 | 84 | no | p16 | 0.0232603 | 0.0000223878
KICK_PLATE | +13.800 | +13.900 | 5 | 132.2 | 100 | yes | p15 | 0.0271885 | 0.0000262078

# IfcDiscreteAccessory: KRATA (3)
In: Undefined
Tekla Quantity - Gross footprint area: 0 m2
Pset_PlateCommon - LoadBearing: no
Name | Description | Material | Bottom elevation | Top elevation | Phase = Class | Weight (kg) | Volume (m3) | Area per tons (m2) | Net surface area (m2) | Height (mm) | Width (mm) | Length (mm) | Reference | NetArea (m2) | GrossArea (m2) | CrossSectionArea (m2) | NetVolume (m3) = GrossVolume (m3)
KRATA | BL10*100 | STEEL/S355 | +12.776 | +12.942 | 1 | 0.8 | 0 | 30.4 | 0 | 100 | 10 | 150 | b62 | 0.0278792 | 0.015 | 0.0001 | 0.000116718
KRATA | BL10*100 | STEEL/S355 | +12.796 | +12.963 | 1 | 0.8 | 0 | 30.4 | 0 | 100 | 10 | 150 | b62 | 0.0278792 | 0.015 | 0.0001 | 0.000116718
KRATA | BL1400*30 | STEEL/S235 | +2.850 | +2.930 | 2 | 889.9 | 0.1 | 8.7 | 7.8 | 1400 | 30 | 2699 | q3 | 7.80314 | 7.80314 | 0.042 | 0.113358

# IfcDiscreteAccessory: PORĘCZ (577)
In: Undefined
Material: STEEL/S235
Tekla Quantity - Volume: 0 m3
Name | Description | Bottom elevation | Top elevation | Phase | Class | Weight (kg) | Gross footprint area (m2) | Area per tons (m2) | Net surface area (m2) | Height (mm) | Width (mm) | Length (mm) | LoadBearing | Reference | NetArea (m2) | GrossArea (m2) | CrossSectionArea (m2) | NetVolume (m3) | GrossVolume (m3)
PORĘCZ | RHS50*3 | +14.996 | +15.060 | 1 | 5 | 4.9 | 0 | 45.3 | 0.2 | 50 | 50 | 1141.7 | yes | fk73 | 0.224063 | 0.224063 | 0.00053866 | 0.000629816 | 0.000629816
2 x PORĘCZ | BL40*3 | +14.875 | +14.890 | 1 | 5 | 0.8 | 0 | 91.6 | 0.1 | 40 | 3 | 915.7 | yes | fk23 | 0.0789897 | 0.0833757 | 0.00012 | 0.000109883 | 0.000116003
PORĘCZ | BL40*3 | +14.184 | +14.886 | 1 | 7 | 0.8 | 0 | 91.6 | 0.1 | 40 | 3 | 702 | yes | fk26 | 0.060612 | 0.060612 | 0.00012 | 0.00008424 | 0.00008424
PORĘCZ | BL40*3 | +14.183 | +14.885 | 1 | 7 | 0.8 | 0 | 91.6 | 0.1 | 40 | 3 | 702 | yes | fk26 | 0.060612 | 0.060612 | 0.00012 | 0.00008424 | 0.00008424
PORĘCZ | BL40*3 | +14.181 | +14.883 | 1 | 7 | 0.8 | 0 | 91.6 | 0.1 | 40 | 3 | 702 | yes | fk26 | 0.060612 | 0.060612 | 0.00012 | 0.00008424 | 0.00008424
PORĘCZ | BL40*3 | +14.180 | +14.882 | 1 | 7 | 0.8 | 0 | 91.6 | 0.1 | 40 | 3 | 702 | yes | fk26 | 0.060612 | 0.060612 | 0.00012 | 0.00008424 | 0.00008424
PORĘCZ | BL40*3 | +14.178 | +14.880 | 1 | 7 | 0.8 | 0 | 91.6 | 0.1 | 40 | 3 | 702 | yes | fk26 | 0.060612 | 0.060612 | 0.00012 | 0.00008424 | 0.00008424
PORĘCZ | BL40*3 | +14.176 | +14.878 | 1 | 7 | 0.8 | 0 | 91.6 | 0.1 | 40 | 3 | 702 | yes | fk26 | 0.060612 | 0.060612 | 0.00012 | 0.00008424 | 0.00008424
PORĘCZ | BL40*3 | +14.175 | +14.877 | 1 | 7 | 0.8 | 0 | 91.6 | 0.1 | 40 | 3 | 702 | yes | fk26 | 0.060612 | 0.060612 | 0.00012 | 0.00008424 | 0.00008424
PORĘCZ | BL40*3 | +14.173 | +14.875 | 1 | 7 | 0.8 | 0 | 91.6 | 0.1 | 40 | 3 | 702 | yes | fk26 | 0.060612 | 0.060612 | 0.00012 | 0.00008424 | 0.00008424
2 x PORĘCZ | BL40*3 | +14.170 | +14.185 | 1 | 5 | 0.8 | 0 | 91.6 | 0.1 | 40 | 3 | 915.7 | yes | fk23 | 0.0789897 | 0.0833757 | 0.00012 | 0.000109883 | 0.000116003
2 x PORĘCZ | SHS50*3 | +14.860 | +15.060 | 1 | 5 | 0.8 | 0 | 46.1 | 0 | 50 | 50 | 200 | yes | fk28 | 0.0357243 | 0.0357243 | 0.00053866 | 0.0000987 | 0.0000987
PORĘCZ | BL40*3 | +14.136 | +14.147 | 1 | 5 | 0.6 | 0 | 91.6 | 0.1 | 40 | 3 | 643 | yes | fk72 | 0.055538 | 0.055538 | 0.00012 | 0.00007716 | 0.00007716
PORĘCZ | BL40*3 | +14.145 | +14.847 | 1 | 7 | 0.6 | 0 | 91.6 | 0.1 | 40 | 3 | 702 | yes | fk26 | 0.060612 | 0.060612 | 0.00012 | 0.00008424 | 0.00008424
2 x PORĘCZ | BL40*3 | +14.146 | +14.848 | 1 | 7 | 0.6 | 0 | 91.6 | 0.1 | 40 | 3 | 702 | yes | fk26 | 0.060612 | 0.060612 | 0.00012 | 0.00008424 | 0.00008424
PORĘCZ | BL40*3 | +14.841 | +14.852 | 1 | 5 | 0.6 | 0 | 91.6 | 0.1 | 40 | 3 | 643 | yes | fk72 | 0.055538 | 0.055538 | 0.00012 | 0.00007716 | 0.00007716
2 x PORĘCZ | BL40*3 | +14.140 | +14.842 | 1 | 7 | 0.6 | 0 | 91.6 | 0.1 | 40 | 3 | 702 | yes | fk26 | 0.060612 | 0.060612 | 0.00012 | 0.00008424 | 0.00008424
PORĘCZ | BL40*3 | +14.142 | +14.844 | 1 | 7 | 0.6 | 0 | 91.6 | 0.1 | 40 | 3 | 702 | yes | fk26 | 0.060612 | 0.060612 | 0.00012 | 0.00008424 | 0.00008424
2 x PORĘCZ | BL40*3 | +14.143 | +14.845 | 1 | 7 | 0.6 | 0 | 91.6 | 0.1 | 40 | 3 | 702 | yes | fk26 | 0.060612 | 0.060612 | 0.00012 | 0.00008424 | 0.00008424
PORĘCZ | BL40*3 | +14.145 | +14.156 | 1 | 5 | 0.6 | 0 | 91.6 | 0.1 | 40 | 3 | 641 | yes | fk22 | 0.055366 | 0.055366 | 0.00012 | 0.00007692 | 0.00007692
PORĘCZ | BL40*3 | +14.154 | +14.856 | 1 | 7 | 0.6 | 0 | 91.6 | 0.1 | 40 | 3 | 702 | yes | fk26 | 0.060612 | 0.060612 | 0.00012 | 0.00008424 | 0.00008424
2 x PORĘCZ | BL40*3 | +14.155 | +14.857 | 1 | 7 | 0.6 | 0 | 91.6 | 0.1 | 40 | 3 | 702 | yes | fk26 | 0.060612 | 0.060612 | 0.00012 | 0.00008424 | 0.00008424
PORĘCZ | BL40*3 | +14.850 | +14.861 | 1 | 5 | 0.6 | 0 | 91.6 | 0.1 | 40 | 3 | 641 | yes | fk22 | 0.055366 | 0.055366 | 0.00012 | 0.00007692 | 0.00007692
2 x PORĘCZ | BL40*3 | +14.149 | +14.851 | 1 | 7 | 0.6 | 0 | 91.6 | 0.1 | 40 | 3 | 702 | yes | fk26 | 0.060612 | 0.060612 | 0.00012 | 0.00008424 | 0.00008424
PORĘCZ | BL40*3 | +14.151 | +14.853 | 1 | 7 | 0.6 | 0 | 91.6 | 0.1 | 40 | 3 | 702 | yes | fk26 | 0.060612 | 0.060612 | 0.00012 | 0.00008424 | 0.00008424
2 x PORĘCZ | BL40*3 | +14.152 | +14.854 | 1 | 7 | 0.6 | 0 | 91.6 | 0.1 | 40 | 3 | 702 | yes | fk26 | 0.060612 | 0.060612 | 0.00012 | 0.00008424 | 0.00008424
PORĘCZ | BL40*3 | +14.168 | +14.870 | 1 | 7 | 0.6 | 0 | 91.6 | 0.1 | 40 | 3 | 702 | yes | fk26 | 0.060612 | 0.060612 | 0.00012 | 0.00008424 | 0.00008424
2 x PORĘCZ | BL40*3 | +14.166 | +14.868 | 1 | 7 | 0.6 | 0 | 91.6 | 0.1 | 40 | 3 | 702 | yes | fk26 | 0.060612 | 0.060612 | 0.00012 | 0.00008424 | 0.00008424
PORĘCZ | RHS50*3 | +14.962 | +15.039 | 1 | 5 | 9.4 | 0 | 45.2 | 0.4 | 50 | 50 | 2125 | yes | fk71 | 0.4256 | 0.4256 | 0.00053866 | 0.0011985 | 0.0011985
PORĘCZ | RHS50*3 | +14.992 | +15.042 | 1 | 5 | 1 | 0 | 45.9 | 0 | 50 | 50 | 260 | yes | fk93 | 0.0477243 | 0.0477243 | 0.00053866 | 0.00013254 | 0.00013254
PORĘCZ | SHS50*3 | +14.992 | +15.046 | 1 | 5 | 1.3 | 0 | 45.7 | 0.1 | 50 | 50 | 325.8 | yes | fk62 | 0.0608854 | 0.0608854 | 0.00053866 | 0.000169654 | 0.000169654
PORĘCZ | BL40*3 | +14.870 | +14.877 | 1 | 5 | 0.3 | 0 | 92.3 | 0 | 40 | 3 | 320.8 | yes | fk24 | 0.026159 | 0.026159 | 0.00012 | 0.0000360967 | 0.0000360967
PORĘCZ | BL40*3 | +14.171 | +14.873 | 1 | 7 | 0.6 | 0 | 91.6 | 0.1 | 40 | 3 | 702 | yes | fk26 | 0.060612 | 0.060612 | 0.00012 | 0.00008424 | 0.00008424
2 x PORĘCZ | BL40*3 | +14.170 | +14.872 | 1 | 7 | 0.6 | 0 | 91.6 | 0.1 | 40 | 3 | 702 | yes | fk26 | 0.060612 | 0.060612 | 0.00012 | 0.00008424 | 0.00008424
PORĘCZ | BL40*3 | +14.165 | +14.172 | 1 | 5 | 0.3 | 0 | 92.3 | 0 | 40 | 3 | 320.8 | yes | fk24 | 0.026159 | 0.026159 | 0.00012 | 0.0000360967 | 0.0000360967
12 x PORĘCZ | BL40*3 | +14.168 | +14.871 | 1 | 7 | 0.6 | 0 | 91.6 | 0.1 | 40 | 3 | 702 | yes | fk26 | 0.060612 | 0.060612 | 0.00012 | 0.00008424 | 0.00008424
PORĘCZ | BL40*3 | +14.870 | +14.874 | 1 | 5 | 0.2 | 0 | 92.6 | 0 | 40 | 3 | 255 | yes | fk94 | 0.0204997 | 0.0204997 | 0.00012 | 0.0000282 | 0.0000282
PORĘCZ | BL40*3 | +14.870 | +14.874 | 1 | 5 | 0.8 | 0 | 91.6 | 0.1 | 40 | 3 | 934 | yes | fk95 | 0.080564 | 0.08065 | 0.00012 | 0.00011208 | 0.0001122
PORĘCZ | BL40*3 | +14.870 | +14.874 | 1 | 5 | 0.2 | 0 | 92.6 | 0 | 40 | 3 | 240 | yes | fk91 | 0.0192097 | 0.0192097 | 0.00012 | 0.0000264 | 0.0000264
PORĘCZ | RHS50*3 | +14.992 | +15.042 | 1 | 5 | 4.6 | 0 | 45.3 | 0.2 | 50 | 50 | 1035 | yes | fk102 | 0.2076 | 0.2076 | 0.00053866 | 0.00058374 | 0.00058374
PORĘCZ | RHS50*3 | +14.989 | +15.042 | 1 | 5 | 1 | 0 | 45.9 | 0 | 50 | 50 | 245 | yes | fk96 | 0.0447243 | 0.0447243 | 0.00053866 | 0.00012408 | 0.00012408
PORĘCZ | BL40*3 | +14.868 | +14.874 | 1 | 5 | 0.2 | 0 | 92.6 | 0 | 40 | 3 | 240 | yes | fk91 | 0.0192097 | 0.0192097 | 0.00012 | 0.0000264 | 0.0000264
PORĘCZ | BL40*3 | +14.165 | +14.169 | 1 | 5 | 0.2 | 0 | 92.6 | 0 | 40 | 3 | 255 | yes | fk94 | 0.0204997 | 0.0204997 | 0.00012 | 0.0000282 | 0.0000282
PORĘCZ | BL40*3 | +14.165 | +14.169 | 1 | 5 | 0.8 | 0 | 91.6 | 0.1 | 40 | 3 | 934 | yes | fk95 | 0.080564 | 0.08065 | 0.00012 | 0.00011208 | 0.0001122
PORĘCZ | BL40*3 | +14.165 | +14.169 | 1 | 5 | 0.2 | 0 | 92.6 | 0 | 40 | 3 | 240 | yes | fk91 | 0.0192097 | 0.0192097 | 0.00012 | 0.0000264 | 0.0000264
PORĘCZ | RHS50*3 | +14.992 | +15.042 | 1 | 5 | 1 | 0 | 45.9 | 0 | 50 | 50 | 245 | yes | fk96 | 0.0447243 | 0.0447243 | 0.00053866 | 0.00012408 | 0.00012408
PORĘCZ | BL40*3 | +14.163 | +14.169 | 1 | 5 | 0.2 | 0 | 92.6 | 0 | 40 | 3 | 240 | yes | fk91 | 0.0192097 | 0.0192097 | 0.00012 | 0.0000264 | 0.0000264
PORĘCZ | BL40*3 | +14.154 | +14.165 | 1 | 5 | 0.6 | 0 | 91.6 | 0.1 | 40 | 3 | 641 | yes | fk22 | 0.055366 | 0.055366 | 0.00012 | 0.00007692 | 0.00007692
PORĘCZ | BL40*3 | +14.162 | +14.864 | 1 | 7 | 0.6 | 0 | 91.6 | 0.1 | 40 | 3 | 702 | yes | fk26 | 0.060612 | 0.060612 | 0.00012 | 0.00008424 | 0.00008424
2 x PORĘCZ | BL40*3 | +14.164 | +14.866 | 1 | 7 | 0.6 | 0 | 91.6 | 0.1 | 40 | 3 | 702 | yes | fk26 | 0.060612 | 0.060612 | 0.00012 | 0.00008424 | 0.00008424
PORĘCZ | BL40*3 | +14.859 | +14.870 | 1 | 5 | 0.6 | 0 | 91.6 | 0.1 | 40 | 3 | 641 | yes | fk22 | 0.055366 | 0.055366 | 0.00012 | 0.00007692 | 0.00007692
2 x PORĘCZ | BL40*3 | +14.158 | +14.860 | 1 | 7 | 0.6 | 0 | 91.6 | 0.1 | 40 | 3 | 702 | yes | fk26 | 0.060612 | 0.060612 | 0.00012 | 0.00008424 | 0.00008424
PORĘCZ | BL40*3 | +14.159 | +14.861 | 1 | 7 | 0.6 | 0 | 91.6 | 0.1 | 40 | 3 | 702 | yes | fk26 | 0.060612 | 0.060612 | 0.00012 | 0.00008424 | 0.00008424
2 x PORĘCZ | BL40*3 | +14.161 | +14.863 | 1 | 7 | 0.6 | 0 | 91.6 | 0.1 | 40 | 3 | 702 | yes | fk26 | 0.060612 | 0.060612 | 0.00012 | 0.00008424 | 0.00008424
PORĘCZ | BL40*3 | +13.494 | +13.497 | 3 | 5 | 0.2 | 0 | 92.3 | 0 | 40 | 3 | 260.1 | yes | fk120 | 0.0226071 | 0.0226071 | 0.00012 | 0.0000312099 | 0.0000312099
29 x PORĘCZ | BL40*3 | +12.687 | +13.494 | 3 | 7 | 0.8 | 0 | 91.6 | 0.1 | 40 | 3 | 807 | yes | fk34 | 0.069642 | 0.069642 | 0.00012 | 0.00009684 | 0.00009684
PORĘCZ | BL40*3 | +12.684 | +12.687 | 3 | 5 | 0.2 | 0 | 92.3 | 0 | 40 | 3 | 260.1 | yes | fk120 | 0.0226071 | 0.0226071 | 0.00012 | 0.0000312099 | 0.0000312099
2 x PORĘCZ | BL40*3 | +13.494 | +13.497 | 3 | 5 | 0.6 | 0 | 91.6 | 0.1 | 40 | 3 | 599 | yes | fk33 | 0.0517544 | 0.0517544 | 0.00012 | 0.0000718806 | 0.0000718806
2 x PORĘCZ | BL40*3 | +12.684 | +12.687 | 3 | 5 | 0.6 | 0 | 91.6 | 0.1 | 40 | 3 | 599 | yes | fk33 | 0.0517544 | 0.0517544 | 0.00012 | 0.0000718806 | 0.0000718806
PORĘCZ | RHS50*3 | +13.615 | +13.665 | 3 | 5 | 0.5 | 0 | 46.4 | 0 | 50 | 50 | 110 | yes | fk115 | 0.0226 | 0.0226 | 0.00053866 | 0.00006204 | 0.00006204
4 x PORĘCZ | BL40*3 | +13.494 | +13.497 | 3 | 5 | 0.3 | 0 | 92.3 | 0 | 40 | 3 | 290 | yes | fk21 | 0.0235097 | 0.0235097 | 0.00012 | 0.0000324 | 0.0000324
2 x PORĘCZ | BL40*3 | +12.684 | +12.687 | 3 | 5 | 0.3 | 0 | 92.3 | 0 | 40 | 3 | 290 | yes | fk21 | 0.0235097 | 0.0235097 | 0.00012 | 0.0000324 | 0.0000324
PORĘCZ | BL40*3 | +13.494 | +13.497 | 3 | 5 | 0.8 | 0 | 91.6 | 0.1 | 40 | 3 | 950 | yes | fk119 | 0.08194 | 0.084133 | 0.00012 | 0.000114 | 0.00011706
4 x PORĘCZ | RHS50*3 | +13.615 | +13.665 | 3 | 5 | 1.3 | 0 | 45.8 | 0.1 | 50 | 50 | 295 | yes | fk32 | 0.0547243 | 0.0547243 | 0.00053866 | 0.00015228 | 0.00015228
PORĘCZ | BL40*3 | +12.684 | +12.687 | 3 | 5 | 0.8 | 0 | 91.6 | 0.1 | 40 | 3 | 950 | yes | fk119 | 0.08194 | 0.084133 | 0.00012 | 0.000114 | 0.00011706
PORĘCZ | RHS50*3 | +13.615 | +13.665 | 3 | 5 | 5.8 | 0.1 | 45.3 | 0.4 | 50 | 50 | 1310.1 | yes | fk118 | 0.262616 | 0.262616 | 0.00053866 | 0.000738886 | 0.000738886
3 x PORĘCZ | BL40*3 | +14.033 | +14.735 | 1 | 7 | 0.6 | 0 | 91.6 | 0.1 | 40 | 3 | 701.5 | yes | fk26 | 0.060569 | 0.060569 | 0.00012 | 0.00008418 | 0.00008418
2 x PORĘCZ | BL40*3 | +14.034 | +14.736 | 1 | 7 | 0.6 | 0 | 91.6 | 0.1 | 40 | 3 | 702 | yes | fk26 | 0.060612 | 0.060612 | 0.00012 | 0.00008424 | 0.00008424
PORĘCZ | BL40*3 | +14.036 | +14.738 | 1 | 7 | 0.6 | 0 | 91.6 | 0.1 | 40 | 3 | 702 | yes | fk26 | 0.060612 | 0.060612 | 0.00012 | 0.00008424 | 0.00008424
PORĘCZ | RHS50*3 | +13.324 | +13.480 | 2 | 4 | 0.6 | 0 | 46.3 | 0 | 50 | 50 | 179.3 | yes | fk114 | 0.0316749 | 0.0345886 | 0.00053866 | 0.0000872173 | 0.0000957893
32 x PORĘCZ | BL40*3 | +14.022 | +14.724 | 5 | 7 | 0.6 | 0 | 91.6 | 0.1 | 40 | 3 | 702 | yes | fk26 | 0.060612 | 0.060612 | 0.00012 | 0.00008424 | 0.00008424
PORĘCZ | BL40*3 | +14.019 | +14.022 | 5 | 5 | 0.3 | 0 | 92.3 | 0 | 40 | 3 | 294.8 | yes | fk36 | 0.0239187 | 0.0239187 | 0.00012 | 0.0000329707 | 0.0000329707
PORĘCZ | BL40*3 | +14.019 | +14.022 | 5 | 5 | 0.1 | 0 | 94.7 | 0 | 40 | 3 | 145.4 | yes | fk109 | 0.00940413 | 0.00940413 | 0.00012 | 0.0000126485 | 0.0000126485
PORĘCZ | BL40*3 | +14.724 | +14.727 | 5 | 5 | 0.3 | 0 | 92.5 | 0 | 40 | 3 | 285.8 | yes | fk110 | 0.0231479 | 0.0231479 | 0.00012 | 0.0000318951 | 0.0000318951
PORĘCZ | BL40*3 | +14.724 | +14.727 | 5 | 5 | 0.1 | 0 | 94.7 | 0 | 40 | 3 | 145.4 | yes | fk109 | 0.00940415 | 0.00940415 | 0.00012 | 0.0000126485 | 0.0000126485
PORĘCZ | RHS50*3 | +14.845 | +14.895 | 5 | 5 | 0.5 | 0 | 47 | 0 | 50 | 50 | 155.4 | yes | fk108 | 0.0219276 | 0.0219276 | 0.00053866 | 0.0000594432 | 0.0000594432
PORĘCZ | RHS50*3 | +14.845 | +14.895 | 5 | 5 | 1.3 | 0 | 45.8 | 0.1 | 50 | 50 | 290.8 | yes | fk107 | 0.0538163 | 0.0538163 | 0.00053866 | 0.00014972 | 0.00014972
PORĘCZ | RHS50*3 | +14.845 | +14.895 | 5 | 5 | 0.3 | 0 | 47.1 | 0 | 50 | 50 | 109.3 | yes | fk106 | 0.0175834 | 0.0175834 | 0.00053866 | 0.0000475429 | 0.0000475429
PORĘCZ | BL40*3 | +14.724 | +14.727 | 5 | 5 | 0.1 | 0 | 94.9 | 0 | 40 | 3 | 105.8 | yes | fk105 | 0.00766875 | 0.00766875 | 0.00012 | 0.0000102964 | 0.0000102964
PORĘCZ | BL40*3 | +14.019 | +14.022 | 5 | 5 | 0.1 | 0 | 94.9 | 0 | 40 | 3 | 105.8 | yes | fk105 | 0.00766875 | 0.00766875 | 0.00012 | 0.0000102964 | 0.0000102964
PORĘCZ | RHS50*3 | +14.959 | +15.009 | 1 | 5 | 1 | 0 | 45.9 | 0 | 50 | 50 | 260 | yes | fk93 | 0.0477243 | 0.0477243 | 0.00053866 | 0.00013254 | 0.00013254
PORĘCZ | SHS50*3 | +14.956 | +15.009 | 1 | 5 | 1 | 0 | 45.9 | 0 | 50 | 50 | 245 | yes | fk104 | 0.0447036 | 0.0447036 | 0.00053866 | 0.000124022 | 0.000124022
PORĘCZ | BL40*3 | +14.835 | +14.841 | 1 | 5 | 0.2 | 0 | 92.6 | 0 | 40 | 3 | 240 | yes | fk91 | 0.0192008 | 0.0192008 | 0.00012 | 0.0000263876 | 0.0000263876
3 x PORĘCZ | BL40*3 | +14.133 | +14.835 | 1 | 7 | 0.6 | 0 | 91.6 | 0.1 | 40 | 3 | 702 | yes | fk26 | 0.060612 | 0.060612 | 0.00012 | 0.00008424 | 0.00008424
2 x PORĘCZ | BL40*3 | +14.135 | +14.837 | 1 | 7 | 0.6 | 0 | 91.6 | 0.1 | 40 | 3 | 702 | yes | fk26 | 0.060612 | 0.060612 | 0.00012 | 0.00008424 | 0.00008424
PORĘCZ | BL40*3 | +14.130 | +14.136 | 1 | 5 | 0.2 | 0 | 92.6 | 0 | 40 | 3 | 240 | yes | fk91 | 0.0192008 | 0.0192008 | 0.00012 | 0.0000263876 | 0.0000263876
12 x PORĘCZ | BL40*3 | +14.135 | +14.838 | 1 | 7 | 0.6 | 0 | 91.6 | 0.1 | 40 | 3 | 702 | yes | fk26 | 0.060612 | 0.060612 | 0.00012 | 0.00008424 | 0.00008424
2 x PORĘCZ | BL40*3 | +14.137 | +14.839 | 1 | 7 | 0.6 | 0 | 91.6 | 0.1 | 40 | 3 | 702 | yes | fk26 | 0.060612 | 0.060612 | 0.00012 | 0.00008424 | 0.00008424
2 x PORĘCZ | BL40*3 | +14.138 | +14.840 | 1 | 7 | 0.6 | 0 | 91.6 | 0.1 | 40 | 3 | 702 | yes | fk26 | 0.060612 | 0.060612 | 0.00012 | 0.00008424 | 0.00008424
PORĘCZ | BL40*3 | +14.837 | +14.841 | 1 | 5 | 0.2 | 0 | 92.6 | 0 | 40 | 3 | 255 | yes | fk94 | 0.0204997 | 0.0204997 | 0.00012 | 0.0000282 | 0.0000282
PORĘCZ | BL40*3 | +14.837 | +14.841 | 1 | 5 | 0.8 | 0 | 91.6 | 0.1 | 40 | 3 | 934 | yes | fk95 | 0.080564 | 0.08065 | 0.00012 | 0.00011208 | 0.0001122
PORĘCZ | BL40*3 | +14.837 | +14.841 | 1 | 5 | 0.2 | 0 | 92.6 | 0 | 40 | 3 | 240 | yes | fk91 | 0.0192097 | 0.0192097 | 0.00012 | 0.0000264 | 0.0000264
PORĘCZ | RHS50*3 | +14.959 | +15.009 | 1 | 5 | 4.6 | 0 | 45.3 | 0.2 | 50 | 50 | 1035 | yes | fk102 | 0.2076 | 0.2076 | 0.00053866 | 0.00058374 | 0.00058374
PORĘCZ | RHS50*3 | +14.959 | +15.012 | 1 | 5 | 1 | 0 | 45.9 | 0 | 50 | 50 | 245 | yes | fk96 | 0.0447243 | 0.0447243 | 0.00053866 | 0.00012408 | 0.00012408
PORĘCZ | BL40*3 | +14.837 | +14.843 | 1 | 5 | 0.2 | 0 | 92.6 | 0 | 40 | 3 | 240 | yes | fk91 | 0.0192097 | 0.0192097 | 0.00012 | 0.0000264 | 0.0000264
PORĘCZ | SHS50*3 | +14.856 | +14.956 | 1 | 5 | 17.2 | 0 | 45.2 | 0.7 | 50 | 50 | 3894.8 | yes | fk100 | 0.779559 | 0.779559 | 0.00053866 | 0.00219666 | 0.00219666
PORĘCZ | BL40*3 | +14.045 | +14.747 | 1 | 7 | 0.6 | 0 | 91.6 | 0.1 | 40 | 3 | 702 | yes | fk26 | 0.060612 | 0.060612 | 0.00012 | 0.00008424 | 0.00008424
PORĘCZ | BL40*3 | +14.736 | +14.750 | 1 | 5 | 0.8 | 0 | 91.6 | 0.1 | 40 | 3 | 924.8 | yes | fk25 | 0.0797723 | 0.0819653 | 0.00012 | 0.000110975 | 0.000114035
2 x PORĘCZ | BL40*3 | +14.037 | +14.739 | 1 | 7 | 0.6 | 0 | 91.6 | 0.1 | 40 | 3 | 702 | yes | fk26 | 0.060612 | 0.060612 | 0.00012 | 0.00008424 | 0.00008424
PORĘCZ | BL40*3 | +14.039 | +14.741 | 1 | 7 | 0.6 | 0 | 91.6 | 0.1 | 40 | 3 | 702 | yes | fk26 | 0.060612 | 0.060612 | 0.00012 | 0.00008424 | 0.00008424
2 x PORĘCZ | BL40*3 | +14.040 | +14.742 | 1 | 7 | 0.6 | 0 | 91.6 | 0.1 | 40 | 3 | 702 | yes | fk26 | 0.060612 | 0.060612 | 0.00012 | 0.00008424 | 0.00008424
PORĘCZ | BL40*3 | +14.042 | +14.744 | 1 | 7 | 0.6 | 0 | 91.6 | 0.1 | 40 | 3 | 702 | yes | fk26 | 0.060612 | 0.060612 | 0.00012 | 0.00008424 | 0.00008424
2 x PORĘCZ | BL40*3 | +14.043 | +14.745 | 1 | 7 | 0.6 | 0 | 91.6 | 0.1 | 40 | 3 | 702 | yes | fk26 | 0.060612 | 0.060612 | 0.00012 | 0.00008424 | 0.00008424
PORĘCZ | BL40*3 | +14.031 | +14.045 | 1 | 5 | 0.8 | 0 | 91.6 | 0.1 | 40 | 3 | 924.8 | yes | fk25 | 0.0797723 | 0.0819567 | 0.00012 | 0.000110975 | 0.000114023
2 x PORĘCZ | BL40*3 | +14.057 | +14.759 | 1 | 7 | 0.6 | 0 | 91.6 | 0.1 | 40 | 3 | 702 | yes | fk26 | 0.060612 | 0.060612 | 0.00012 | 0.00008424 | 0.00008424
PORĘCZ | BL40*3 | +14.748 | +14.763 | 1 | 5 | 0.8 | 0 | 91.6 | 0.1 | 40 | 3 | 924 | yes | fk25 | 0.079704 | 0.081983 | 0.00012 | 0.00011088 | 0.00011406
2 x PORĘCZ | BL40*3 | +14.047 | +14.749 | 1 | 7 | 0.6 | 0 | 91.6 | 0.1 | 40 | 3 | 702 | yes | fk26 | 0.060612 | 0.060612 | 0.00012 | 0.00008424 | 0.00008424
PORĘCZ | BL40*3 | +14.048 | +14.750 | 1 | 7 | 0.6 | 0 | 91.6 | 0.1 | 40 | 3 | 702 | yes | fk26 | 0.060612 | 0.060612 | 0.00012 | 0.00008424 | 0.00008424
PORĘCZ | BL40*3 | +14.050 | +14.752 | 1 | 7 | 0.6 | 0 | 91.6 | 0.1 | 40 | 3 | 702 | yes | fk26 | 0.060612 | 0.060612 | 0.00012 | 0.00008424 | 0.00008424
2 x PORĘCZ | BL40*3 | +14.051 | +14.753 | 1 | 7 | 0.6 | 0 | 91.6 | 0.1 | 40 | 3 | 702 | yes | fk26 | 0.060612 | 0.060612 | 0.00012 | 0.00008424 | 0.00008424
PORĘCZ | BL40*3 | +14.053 | +14.755 | 1 | 7 | 0.6 | 0 | 91.6 | 0.1 | 40 | 3 | 702 | yes | fk26 | 0.060612 | 0.060612 | 0.00012 | 0.00008424 | 0.00008424
2 x PORĘCZ | BL40*3 | +14.054 | +14.756 | 1 | 7 | 0.6 | 0 | 91.6 | 0.1 | 40 | 3 | 702 | yes | fk26 | 0.060612 | 0.060612 | 0.00012 | 0.00008424 | 0.00008424
PORĘCZ | BL40*3 | +14.056 | +14.758 | 1 | 7 | 0.6 | 0 | 91.6 | 0.1 | 40 | 3 | 702 | yes | fk26 | 0.060612 | 0.060612 | 0.00012 | 0.00008424 | 0.00008424
PORĘCZ | BL40*3 | +14.043 | +14.058 | 1 | 5 | 0.8 | 0 | 91.6 | 0.1 | 40 | 3 | 924 | yes | fk25 | 0.079704 | 0.0819745 | 0.00012 | 0.00011088 | 0.000114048
2 x PORĘCZ | BL40*3 | +14.070 | +14.772 | 1 | 7 | 0.6 | 0 | 91.6 | 0.1 | 40 | 3 | 702 | yes | fk26 | 0.060612 | 0.060612 | 0.00012 | 0.00008424 | 0.00008424
PORĘCZ | BL40*3 | +14.760 | +14.775 | 1 | 5 | 0.8 | 0 | 91.6 | 0.1 | 40 | 3 | 925 | yes | fk25 | 0.07979 | 0.081983 | 0.00012 | 0.000111 | 0.00011406
PORĘCZ | BL40*3 | +14.059 | +14.761 | 1 | 7 | 0.6 | 0 | 91.6 | 0.1 | 40 | 3 | 702 | yes | fk26 | 0.060612 | 0.060612 | 0.00012 | 0.00008424 | 0.00008424
2 x PORĘCZ | BL40*3 | +14.061 | +14.763 | 1 | 7 | 0.6 | 0 | 91.6 | 0.1 | 40 | 3 | 702 | yes | fk26 | 0.060612 | 0.060612 | 0.00012 | 0.00008424 | 0.00008424
PORĘCZ | BL40*3 | +14.062 | +14.764 | 1 | 7 | 0.6 | 0 | 91.6 | 0.1 | 40 | 3 | 702 | yes | fk26 | 0.060612 | 0.060612 | 0.00012 | 0.00008424 | 0.00008424
2 x PORĘCZ | BL40*3 | +14.064 | +14.766 | 1 | 7 | 0.6 | 0 | 91.6 | 0.1 | 40 | 3 | 702 | yes | fk26 | 0.060612 | 0.060612 | 0.00012 | 0.00008424 | 0.00008424
PORĘCZ | BL40*3 | +14.065 | +14.767 | 1 | 7 | 0.6 | 0 | 91.6 | 0.1 | 40 | 3 | 702 | yes | fk26 | 0.060612 | 0.060612 | 0.00012 | 0.00008424 | 0.00008424
2 x PORĘCZ | BL40*3 | +14.067 | +14.769 | 1 | 7 | 0.6 | 0 | 91.6 | 0.1 | 40 | 3 | 702 | yes | fk26 | 0.060612 | 0.060612 | 0.00012 | 0.00008424 | 0.00008424
PORĘCZ | BL40*3 | +14.068 | +14.770 | 1 | 7 | 0.6 | 0 | 91.6 | 0.1 | 40 | 3 | 702 | yes | fk26 | 0.060612 | 0.060612 | 0.00012 | 0.00008424 | 0.00008424
PORĘCZ | BL40*3 | +14.055 | +14.070 | 1 | 5 | 0.8 | 0 | 91.6 | 0.1 | 40 | 3 | 925 | yes | fk25 | 0.07979 | 0.0819745 | 0.00012 | 0.000111 | 0.000114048
PORĘCZ | BL40*3 | +14.082 | +14.784 | 1 | 7 | 0.6 | 0 | 91.6 | 0.1 | 40 | 3 | 702 | yes | fk26 | 0.060612 | 0.060612 | 0.00012 | 0.00008424 | 0.00008424
PORĘCZ | BL40*3 | +14.773 | +14.788 | 1 | 5 | 0.8 | 0 | 91.6 | 0.1 | 40 | 3 | 920 | yes | fk99 | 0.07936 | 0.07936 | 0.00012 | 0.0001104 | 0.0001104
PORĘCZ | BL40*3 | +14.071 | +14.773 | 1 | 7 | 0.6 | 0 | 91.6 | 0.1 | 40 | 3 | 702 | yes | fk26 | 0.060612 | 0.060612 | 0.00012 | 0.00008424 | 0.00008424
PORĘCZ | BL40*3 | +14.073 | +14.775 | 1 | 7 | 0.6 | 0 | 91.6 | 0.1 | 40 | 3 | 702 | yes | fk26 | 0.060612 | 0.060612 | 0.00012 | 0.00008424 | 0.00008424
PORĘCZ | BL40*3 | +14.074 | +14.776 | 1 | 7 | 0.6 | 0 | 91.6 | 0.1 | 40 | 3 | 702 | yes | fk26 | 0.060612 | 0.060612 | 0.00012 | 0.00008424 | 0.00008424
PORĘCZ | BL40*3 | +14.076 | +14.778 | 1 | 7 | 0.6 | 0 | 91.6 | 0.1 | 40 | 3 | 702 | yes | fk26 | 0.060612 | 0.060612 | 0.00012 | 0.00008424 | 0.00008424
PORĘCZ | BL40*3 | +14.078 | +14.779 | 1 | 7 | 0.6 | 0 | 91.6 | 0.1 | 40 | 3 | 702 | yes | fk26 | 0.060612 | 0.060612 | 0.00012 | 0.00008424 | 0.00008424
PORĘCZ | BL40*3 | +14.079 | +14.781 | 1 | 7 | 0.6 | 0 | 91.6 | 0.1 | 40 | 3 | 702 | yes | fk26 | 0.060612 | 0.060612 | 0.00012 | 0.00008424 | 0.00008424
2 x PORĘCZ | BL40*3 | +14.081 | +14.783 | 1 | 7 | 0.6 | 0 | 91.6 | 0.1 | 40 | 3 | 702 | yes | fk26 | 0.060612 | 0.060612 | 0.00012 | 0.00008424 | 0.00008424
PORĘCZ | BL40*3 | +14.068 | +14.083 | 1 | 5 | 0.8 | 0 | 91.6 | 0.1 | 40 | 3 | 920 | yes | fk99 | 0.07936 | 0.07936 | 0.00012 | 0.0001104 | 0.0001104
2 x PORĘCZ | BL40*3 | +14.095 | +14.797 | 1 | 7 | 0.6 | 0 | 91.6 | 0.1 | 40 | 3 | 702 | yes | fk26 | 0.060612 | 0.060612 | 0.00012 | 0.00008424 | 0.00008424
PORĘCZ | BL40*3 | +14.785 | +14.800 | 1 | 5 | 0.8 | 0 | 91.6 | 0.1 | 40 | 3 | 925 | yes | fk25 | 0.07979 | 0.081983 | 0.00012 | 0.000111 | 0.00011406
2 x PORĘCZ | BL40*3 | +14.084 | +14.786 | 1 | 7 | 0.6 | 0 | 91.6 | 0.1 | 40 | 3 | 702 | yes | fk26 | 0.060612 | 0.060612 | 0.00012 | 0.00008424 | 0.00008424
PORĘCZ | BL40*3 | +14.085 | +14.787 | 1 | 7 | 0.6 | 0 | 91.6 | 0.1 | 40 | 3 | 702 | yes | fk26 | 0.060612 | 0.060612 | 0.00012 | 0.00008424 | 0.00008424
2 x PORĘCZ | BL40*3 | +14.087 | +14.789 | 1 | 7 | 0.6 | 0 | 91.6 | 0.1 | 40 | 3 | 702 | yes | fk26 | 0.060612 | 0.060612 | 0.00012 | 0.00008424 | 0.00008424
PORĘCZ | BL40*3 | +14.088 | +14.790 | 1 | 7 | 0.6 | 0 | 91.6 | 0.1 | 40 | 3 | 702 | yes | fk26 | 0.060612 | 0.060612 | 0.00012 | 0.00008424 | 0.00008424
2 x PORĘCZ | BL40*3 | +14.090 | +14.792 | 1 | 7 | 0.6 | 0 | 91.6 | 0.1 | 40 | 3 | 702 | yes | fk26 | 0.060612 | 0.060612 | 0.00012 | 0.00008424 | 0.00008424
PORĘCZ | BL40*3 | +14.091 | +14.793 | 1 | 7 | 0.6 | 0 | 91.6 | 0.1 | 40 | 3 | 702 | yes | fk26 | 0.060612 | 0.060612 | 0.00012 | 0.00008424 | 0.00008424
PORĘCZ | BL40*3 | +14.093 | +14.795 | 1 | 7 | 0.6 | 0 | 91.6 | 0.1 | 40 | 3 | 702 | yes | fk26 | 0.060612 | 0.060612 | 0.00012 | 0.00008424 | 0.00008424
PORĘCZ | BL40*3 | +14.080 | +14.095 | 1 | 5 | 0.8 | 0 | 91.6 | 0.1 | 40 | 3 | 925 | yes | fk25 | 0.07979 | 0.0819745 | 0.00012 | 0.000111 | 0.000114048
2 x PORĘCZ | BL40*3 | +14.107 | +14.809 | 1 | 7 | 0.6 | 0 | 91.6 | 0.1 | 40 | 3 | 702 | yes | fk26 | 0.060612 | 0.060612 | 0.00012 | 0.00008424 | 0.00008424
PORĘCZ | BL40*3 | +14.798 | +14.812 | 1 | 5 | 0.8 | 0 | 91.6 | 0.1 | 40 | 3 | 917.6 | yes | fk98 | 0.0791535 | 0.0813465 | 0.00012 | 0.000110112 | 0.000113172
PORĘCZ | BL40*3 | +14.096 | +14.798 | 1 | 7 | 0.6 | 0 | 91.6 | 0.1 | 40 | 3 | 702 | yes | fk26 | 0.060612 | 0.060612 | 0.00012 | 0.00008424 | 0.00008424
2 x PORĘCZ | BL40*3 | +14.098 | +14.800 | 1 | 7 | 0.6 | 0 | 91.6 | 0.1 | 40 | 3 | 702 | yes | fk26 | 0.060612 | 0.060612 | 0.00012 | 0.00008424 | 0.00008424
PORĘCZ | BL40*3 | +14.099 | +14.801 | 1 | 7 | 0.6 | 0 | 91.6 | 0.1 | 40 | 3 | 702 | yes | fk26 | 0.060612 | 0.060612 | 0.00012 | 0.00008424 | 0.00008424
2 x PORĘCZ | BL40*3 | +14.101 | +14.803 | 1 | 7 | 0.6 | 0 | 91.6 | 0.1 | 40 | 3 | 702 | yes | fk26 | 0.060612 | 0.060612 | 0.00012 | 0.00008424 | 0.00008424
PORĘCZ | BL40*3 | +14.102 | +14.804 | 1 | 7 | 0.6 | 0 | 91.6 | 0.1 | 40 | 3 | 702 | yes | fk26 | 0.060612 | 0.060612 | 0.00012 | 0.00008424 | 0.00008424
2 x PORĘCZ | BL40*3 | +14.104 | +14.806 | 1 | 7 | 0.6 | 0 | 91.6 | 0.1 | 40 | 3 | 702 | yes | fk26 | 0.060612 | 0.060612 | 0.00012 | 0.00008424 | 0.00008424
PORĘCZ | BL40*3 | +14.105 | +14.807 | 1 | 7 | 0.6 | 0 | 91.6 | 0.1 | 40 | 3 | 702 | yes | fk26 | 0.060612 | 0.060612 | 0.00012 | 0.00008424 | 0.00008424
PORĘCZ | BL40*3 | +14.093 | +14.107 | 1 | 5 | 0.8 | 0 | 91.6 | 0.1 | 40 | 3 | 917.6 | yes | fk98 | 0.0791535 | 0.081338 | 0.00012 | 0.000110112 | 0.00011316
PORĘCZ | BL40*3 | +14.119 | +14.821 | 1 | 7 | 0.6 | 0 | 91.6 | 0.1 | 40 | 3 | 702 | yes | fk26 | 0.060612 | 0.060612 | 0.00012 | 0.00008424 | 0.00008424
PORĘCZ | BL40*3 | +14.810 | +14.825 | 1 | 5 | 0.8 | 0 | 91.6 | 0.1 | 40 | 3 | 927.6 | yes | fk97 | 0.0800135 | 0.0822065 | 0.00012 | 0.000111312 | 0.000114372
2 x PORĘCZ | BL40*3 | +14.109 | +14.811 | 1 | 7 | 0.6 | 0 | 91.6 | 0.1 | 40 | 3 | 702 | yes | fk26 | 0.060612 | 0.060612 | 0.00012 | 0.00008424 | 0.00008424
2 x PORĘCZ | BL40*3 | +14.110 | +14.812 | 1 | 7 | 0.6 | 0 | 91.6 | 0.1 | 40 | 3 | 702 | yes | fk26 | 0.060612 | 0.060612 | 0.00012 | 0.00008424 | 0.00008424
2 x PORĘCZ | BL40*3 | +14.112 | +14.814 | 1 | 7 | 0.6 | 0 | 91.6 | 0.1 | 40 | 3 | 702 | yes | fk26 | 0.060612 | 0.060612 | 0.00012 | 0.00008424 | 0.00008424
PORĘCZ | BL40*3 | +14.113 | +14.815 | 1 | 7 | 0.6 | 0 | 91.6 | 0.1 | 40 | 3 | 702 | yes | fk26 | 0.060612 | 0.060612 | 0.00012 | 0.00008424 | 0.00008424
2 x PORĘCZ | BL40*3 | +14.115 | +14.817 | 1 | 7 | 0.6 | 0 | 91.6 | 0.1 | 40 | 3 | 702 | yes | fk26 | 0.060612 | 0.060612 | 0.00012 | 0.00008424 | 0.00008424
PORĘCZ | BL40*3 | +14.116 | +14.818 | 1 | 7 | 0.6 | 0 | 91.6 | 0.1 | 40 | 3 | 702 | yes | fk26 | 0.060612 | 0.060612 | 0.00012 | 0.00008424 | 0.00008424
2 x PORĘCZ | BL40*3 | +14.118 | +14.820 | 1 | 7 | 0.6 | 0 | 91.6 | 0.1 | 40 | 3 | 702 | yes | fk26 | 0.060612 | 0.060612 | 0.00012 | 0.00008424 | 0.00008424
PORĘCZ | BL40*3 | +14.105 | +14.120 | 1 | 5 | 0.8 | 0 | 91.6 | 0.1 | 40 | 3 | 927.6 | yes | fk97 | 0.0800135 | 0.082198 | 0.00012 | 0.000111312 | 0.00011436
2 x PORĘCZ | BL40*3 | +14.132 | +14.834 | 1 | 7 | 0.6 | 0 | 91.6 | 0.1 | 40 | 3 | 702 | yes | fk26 | 0.060612 | 0.060612 | 0.00012 | 0.00008424 | 0.00008424
PORĘCZ | BL40*3 | +14.132 | +14.136 | 1 | 5 | 0.2 | 0 | 92.6 | 0 | 40 | 3 | 255 | yes | fk94 | 0.0204997 | 0.0204997 | 0.00012 | 0.0000282 | 0.0000282
PORĘCZ | BL40*3 | +14.132 | +14.136 | 1 | 5 | 0.8 | 0 | 91.6 | 0.1 | 40 | 3 | 934 | yes | fk95 | 0.080564 | 0.08065 | 0.00012 | 0.00011208 | 0.0001122
PORĘCZ | BL40*3 | +14.132 | +14.136 | 1 | 5 | 0.2 | 0 | 92.6 | 0 | 40 | 3 | 240 | yes | fk91 | 0.0192097 | 0.0192097 | 0.00012 | 0.0000264 | 0.0000264
PORĘCZ | RHS50*3 | +14.959 | +15.009 | 1 | 5 | 1 | 0 | 45.9 | 0 | 50 | 50 | 245 | yes | fk96 | 0.0447243 | 0.0447243 | 0.00053866 | 0.00012408 | 0.00012408
PORĘCZ | BL40*3 | +14.132 | +14.139 | 1 | 5 | 0.2 | 0 | 92.6 | 0 | 40 | 3 | 240 | yes | fk91 | 0.0192097 | 0.0192097 | 0.00012 | 0.0000264 | 0.0000264
PORĘCZ | RHS50*3 | +14.845 | +14.895 | 5 | 5 | 0.6 | 0 | 46.1 | 0 | 50 | 50 | 168.8 | yes | fk89 | 0.0319241 | 0.0319241 | 0.00053866 | 0.0000882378 | 0.0000882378
PORĘCZ | RHS50*3 | +14.845 | +14.895 | 5 | 5 | 0.6 | 0 | 46.2 | 0 | 50 | 50 | 149.6 | yes | fk88 | 0.0280968 | 0.0280968 | 0.00053866 | 0.0000774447 | 0.0000774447
PORĘCZ | BL40*3 | +14.724 | +14.727 | 5 | 5 | 0.1 | 0 | 93 | 0 | 40 | 3 | 166.3 | yes | fk87 | 0.0137083 | 0.0137083 | 0.00012 | 0.000018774 | 0.000018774
PORĘCZ | BL40*3 | +14.019 | +14.022 | 5 | 5 | 0.1 | 0 | 93 | 0 | 40 | 3 | 166.3 | yes | fk87 | 0.0137083 | 0.0137083 | 0.00012 | 0.000018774 | 0.000018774
PORĘCZ | BL40*3 | +14.724 | +14.727 | 5 | 5 | 0.1 | 0 | 93.3 | 0 | 40 | 3 | 147.1 | yes | fk86 | 0.0120626 | 0.0120626 | 0.00012 | 0.0000164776 | 0.0000164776
PORĘCZ | BL40*3 | +14.019 | +14.022 | 5 | 5 | 0.1 | 0 | 93.3 | 0 | 40 | 3 | 147.1 | yes | fk86 | 0.0120626 | 0.0120626 | 0.00012 | 0.0000164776 | 0.0000164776
2 x PORĘCZ | BL40*3 | +14.724 | +14.727 | 5 | 5 | 0.6 | 0 | 91.6 | 0.1 | 40 | 3 | 776.9 | yes | fk80 | 0.0670495 | 0.0671355 | 0.00012 | 0.0000932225 | 0.0000933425
2 x PORĘCZ | BL40*3 | +14.724 | +14.727 | 5 | 5 | 0.8 | 0 | 91.6 | 0.1 | 40 | 3 | 899.6 | yes | fk83 | 0.0776079 | 0.0776939 | 0.00012 | 0.000107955 | 0.000108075
PORĘCZ | SHS50*3 | +14.848 | +14.960 | 1 | 5 | 21.4 | 0 | 45.2 | 1 | 50 | 50 | 4828.3 | yes | fk85 | 0.966256 | 0.966256 | 0.00053866 | 0.00272315 | 0.00272315
PORĘCZ | RHS50*3 | +14.845 | +14.895 | 5 | 5 | 7.6 | 0.1 | 45.3 | 0.4 | 50 | 50 | 1705.7 | yes | fk84 | 0.341741 | 0.341741 | 0.00053866 | 0.000962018 | 0.000962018
2 x PORĘCZ | BL40*3 | +14.019 | +14.022 | 5 | 5 | 0.8 | 0 | 91.6 | 0.1 | 40 | 3 | 899.6 | yes | fk83 | 0.0776079 | 0.0776939 | 0.00012 | 0.000107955 | 0.000108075
PORĘCZ | RHS50*3 | +14.845 | +14.895 | 5 | 5 | 9 | 0.1 | 45.3 | 0.4 | 50 | 50 | 2066.3 | yes | fk82 | 0.408975 | 0.408975 | 0.00053866 | 0.00115127 | 0.00115127
PORĘCZ | RHS50*3 | +14.695 | +14.895 | 5 | 5 | 0.8 | 0 | 46.1 | 0 | 50 | 50 | 200 | yes | fk81 | 0.0357243 | 0.0357243 | 0.00053866 | 0.0000987 | 0.0000987
2 x PORĘCZ | BL40*3 | +14.019 | +14.022 | 5 | 5 | 0.6 | 0 | 91.6 | 0.1 | 40 | 3 | 776.9 | yes | fk80 | 0.0670495 | 0.0671355 | 0.00012 | 0.0000932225 | 0.0000933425
PORĘCZ | BL40*3 | +14.030 | +14.033 | 1 | 5 | 0.1 | 0 | 95.9 | 0 | 40 | 3 | 67.7 | no | fk78 | 0.00523878 | 0.00523878 | 0.00012 | 0.00000695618 | 0.00000695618
PORĘCZ | BL40*3 | +14.030 | +14.033 | 1 | 5 | 0.3 | 0 | 92.3 | 0 | 40 | 3 | 287.4 | no | fk76 | 0.0241279 | 0.0241279 | 0.00012 | 0.0000333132 | 0.0000333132
PORĘCZ | BL40*3 | +14.735 | +14.738 | 1 | 5 | 0 | 0 | 96.8 | 0 | 40 | 3 | 58.8 | no | fk77 | 0.00446846 | 0.00446846 | 0.00012 | 0.00000588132 | 0.00000588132
PORĘCZ | BL40*3 | +14.735 | +14.738 | 1 | 5 | 0.3 | 0 | 92.3 | 0 | 40 | 3 | 287.4 | no | fk76 | 0.0241279 | 0.0241279 | 0.00012 | 0.0000333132 | 0.0000333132
PORĘCZ | SHS50*3 | +14.856 | +14.906 | 1 | 5 | 0.2 | 0 | 48.2 | 0 | 50 | 50 | 59.7 | no | fk75 | 0.0100673 | 0.0100673 | 0.00053866 | 0.0000266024 | 0.0000266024
PORĘCZ | SHS50*3 | +14.856 | +14.906 | 1 | 5 | 1.3 | 0 | 45.7 | 0.1 | 50 | 50 | 289.8 | no | fk74 | 0.0561557 | 0.0561557 | 0.00053866 | 0.000156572 | 0.000156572
2 x PORĘCZ | BL40*3 | +14.729 | +14.732 | 5 | 4 | 0.8 | 0 | 91.6 | 0.1 | 40 | 3 | 848.6 | yes | xx43 | 0.0732238 | 0.0733098 | 0.00012 | 0.000101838 | 0.000101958
14 x PORĘCZ | BL40*3 | +13.922 | +14.729 | 5 | 4 | 0.8 | 0 | 91.6 | 0.1 | 40 | 3 | 807 | yes | xx42 | 0.069642 | 0.069642 | 0.00012 | 0.00009684 | 0.00009684
2 x PORĘCZ | BL40*3 | +13.919 | +13.922 | 5 | 4 | 0.8 | 0 | 91.6 | 0.1 | 40 | 3 | 848.6 | yes | xx43 | 0.0732238 | 0.0733098 | 0.00012 | 0.000101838 | 0.000101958
PORĘCZ | SHS50*3 | +13.615 | +13.665 | 3 | 5 | 0.3 | 0 | 47.4 | 0 | 50 | 50 | 100 | no | xx64 | 0.0157243 | 0.0157243 | 0.00053866 | 0.0000423 | 0.0000423
PORĘCZ | BL40*3 | +12.854 | +13.662 | 3 | 7 | 0.8 | 0 | 91.6 | 0.1 | 40 | 3 | 808.1 | yes | fk2 | 0.0696399 | 0.0696399 | 0.00012 | 0.0000967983 | 0.0000967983
PORĘCZ | BL40*3 | +12.795 | +13.603 | 3 | 7 | 0.8 | 0 | 91.6 | 0.1 | 40 | 3 | 808.1 | yes | fk2 | 0.0696399 | 0.0696399 | 0.00012 | 0.0000967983 | 0.0000967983
PORĘCZ | BL40*3 | +12.735 | +13.543 | 3 | 7 | 0.8 | 0 | 91.6 | 0.1 | 40 | 3 | 808.1 | yes | fk2 | 0.0696399 | 0.0696399 | 0.00012 | 0.0000967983 | 0.0000967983
PORĘCZ | BL40*3 | +13.494 | +13.680 | 3 | 5 | 0.3 | 0 | 92 | 0 | 40 | 3 | 412.3 | yes | fk69 | 0.0356173 | 0.0356173 | 0.00012 | 0.0000493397 | 0.0000493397
PORĘCZ | BL40*3 | +13.494 | +13.497 | 3 | 5 | 0 | 0 | 96.3 | 0 | 40 | 3 | 51.6 | yes | fk70 | 0.00464751 | 0.00464751 | 0.00012 | 0.0000061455 | 0.0000061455
PORĘCZ | BL40*3 | +12.684 | +12.869 | 3 | 5 | 0.3 | 0 | 92 | 0 | 40 | 3 | 411.9 | yes | fk69 | 0.0355853 | 0.0380184 | 0.00012 | 0.0000492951 | 0.0000527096
PORĘCZ | BL40*3 | +12.684 | +12.687 | 3 | 5 | 0.1 | 0 | 95.9 | 0 | 40 | 3 | 56.6 | yes | fk68 | 0.00507751 | 0.00507751 | 0.00012 | 0.0000067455 | 0.0000067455
PORĘCZ | SHS50*3 | +13.615 | +13.665 | 3 | 5 | 0.2 | 0 | 47.9 | 0 | 50 | 50 | 57.1 | yes | fk67 | 0.0108506 | 0.0108506 | 0.00053866 | 0.0000288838 | 0.0000288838
2 x PORĘCZ | BL40*3 | +13.385 | +13.813 | 2 | 5 | 0.8 | 0 | 91.6 | 0.1 | 40 | 3 | 951.8 | yes | fk59 | 0.0819966 | 0.0819966 | 0.00012 | 0.000114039 | 0.000114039
PORĘCZ | BL40*3 | +13.833 | +13.862 | 2 | 5 | 0.1 | 0 | 95.7 | 0 | 40 | 3 | 58.4 | yes | fk58 | 0.0052332 | 0.0052332 | 0.00012 | 0.00000696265 | 0.00000696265
PORĘCZ | BL40*3 | +13.859 | +13.862 | 2 | 5 | 0.8 | 0 | 91.6 | 0.1 | 40 | 3 | 803.5 | no | fk55 | 0.0693098 | 0.0693098 | 0.00012 | 0.0000963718 | 0.0000963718
PORĘCZ | BL40*3 | +13.859 | +13.862 | 2 | 5 | 0.8 | 0 | 91.6 | 0.1 | 40 | 3 | 849 | no | fk57 | 0.073254 | 0.073254 | 0.00012 | 0.00010188 | 0.00010188
2 x PORĘCZ | BL40*3 | +12.613 | +13.418 | 2 | 7 | 0.8 | 0 | 91.6 | 0.1 | 40 | 3 | 805.2 | yes | fk55 | 0.0693861 | 0.0693861 | 0.00012 | 0.0000964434 | 0.0000964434
2 x PORĘCZ | BL40*3 | +12.673 | +13.478 | 2 | 7 | 0.8 | 0 | 91.6 | 0.1 | 40 | 3 | 805.2 | yes | fk55 | 0.0693861 | 0.0693861 | 0.00012 | 0.0000964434 | 0.0000964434
2 x PORĘCZ | BL40*3 | +12.733 | +13.538 | 2 | 7 | 0.8 | 0 | 91.6 | 0.1 | 40 | 3 | 805.2 | yes | fk55 | 0.0693861 | 0.0693861 | 0.00012 | 0.0000964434 | 0.0000964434
2 x PORĘCZ | BL40*3 | +12.793 | +13.598 | 2 | 7 | 0.8 | 0 | 91.6 | 0.1 | 40 | 3 | 805.2 | yes | fk55 | 0.0693861 | 0.0693861 | 0.00012 | 0.0000964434 | 0.0000964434
2 x PORĘCZ | BL40*3 | +12.853 | +13.658 | 2 | 7 | 0.8 | 0 | 91.6 | 0.1 | 40 | 3 | 805.2 | yes | fk55 | 0.0693861 | 0.0693861 | 0.00012 | 0.0000964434 | 0.0000964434
2 x PORĘCZ | BL40*3 | +12.913 | +13.718 | 2 | 7 | 0.8 | 0 | 91.6 | 0.1 | 40 | 3 | 805.2 | yes | fk55 | 0.0693861 | 0.0693861 | 0.00012 | 0.0000964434 | 0.0000964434
2 x PORĘCZ | BL40*3 | +12.973 | +13.778 | 2 | 7 | 0.8 | 0 | 91.6 | 0.1 | 40 | 3 | 805.2 | yes | fk55 | 0.0693861 | 0.0693861 | 0.00012 | 0.0000964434 | 0.0000964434
PORĘCZ | BL40*3 | +13.063 | +13.859 | 2 | 7 | 0.6 | 0 | 91.6 | 0.1 | 40 | 3 | 795.6 | yes | fk54 | 0.0686089 | 0.0686089 | 0.00012 | 0.0000953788 | 0.0000953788
PORĘCZ | BL40*3 | +13.123 | +13.859 | 2 | 7 | 0.6 | 0 | 91.6 | 0.1 | 40 | 3 | 735.6 | yes | fk53 | 0.0634489 | 0.0634489 | 0.00012 | 0.0000881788 | 0.0000881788
PORĘCZ | BL40*3 | +13.183 | +13.859 | 2 | 7 | 0.6 | 0 | 91.6 | 0.1 | 40 | 3 | 675.6 | yes | fk52 | 0.0582889 | 0.0582889 | 0.00012 | 0.0000809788 | 0.0000809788
PORĘCZ | BL40*3 | +13.243 | +13.859 | 2 | 7 | 0.6 | 0 | 91.6 | 0.1 | 40 | 3 | 615.6 | yes | fk51 | 0.0531289 | 0.0531289 | 0.00012 | 0.0000737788 | 0.0000737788
PORĘCZ | BL40*3 | +13.303 | +13.859 | 2 | 7 | 0.5 | 0 | 91.8 | 0 | 40 | 3 | 555.6 | yes | fk50 | 0.0479689 | 0.0479689 | 0.00012 | 0.0000665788 | 0.0000665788
PORĘCZ | BL40*3 | +13.363 | +13.859 | 2 | 7 | 0.5 | 0 | 91.8 | 0 | 40 | 3 | 495.6 | yes | fk49 | 0.0428089 | 0.0428089 | 0.00012 | 0.0000593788 | 0.0000593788
PORĘCZ | BL40*3 | +13.423 | +13.859 | 2 | 7 | 0.3 | 0 | 91.8 | 0 | 40 | 3 | 435.6 | yes | fk48 | 0.0376489 | 0.0376489 | 0.00012 | 0.0000521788 | 0.0000521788
PORĘCZ | BL40*3 | +13.513 | +13.859 | 2 | 7 | 0.3 | 0 | 92.1 | 0 | 40 | 3 | 345.6 | yes | fk47 | 0.0299089 | 0.0299089 | 0.00012 | 0.0000413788 | 0.0000413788
PORĘCZ | BL40*3 | +13.573 | +13.859 | 2 | 7 | 0.3 | 0 | 92.1 | 0 | 40 | 3 | 285.6 | yes | fk46 | 0.0247489 | 0.0247489 | 0.00012 | 0.0000341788 | 0.0000341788
PORĘCZ | BL40*3 | +13.633 | +13.859 | 2 | 7 | 0.2 | 0 | 92.5 | 0 | 40 | 3 | 225.6 | yes | fk45 | 0.0195889 | 0.0195889 | 0.00012 | 0.0000269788 | 0.0000269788
PORĘCZ | BL40*3 | +13.693 | +13.859 | 2 | 7 | 0.2 | 0 | 93 | 0 | 40 | 3 | 165.6 | yes | fk44 | 0.0144289 | 0.0144289 | 0.00012 | 0.0000197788 | 0.0000197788
PORĘCZ | BL40*3 | +13.753 | +13.859 | 2 | 7 | 0.1 | 0 | 93.9 | 0 | 40 | 3 | 105.6 | yes | fk43 | 0.00926894 | 0.00926894 | 0.00012 | 0.0000125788 | 0.0000125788
PORĘCZ | BL40*3 | +13.813 | +13.859 | 2 | 7 | 0 | 0 | 97.3 | 0 | 40 | 3 | 45.6 | yes | fk42 | 0.00410894 | 0.00410894 | 0.00012 | 0.00000537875 | 0.00000537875
2 x PORĘCZ | BL40*3 | +12.578 | +13.006 | 2 | 5 | 0.8 | 0 | 91.6 | 0.1 | 40 | 3 | 950.7 | yes | fk41 | 0.0819005 | 0.0819966 | 0.00012 | 0.000113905 | 0.000114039
2 x PORĘCZ | BL40*3 | +13.028 | +13.456 | 2 | 5 | 0.8 | 0 | 91.6 | 0.1 | 40 | 3 | 950.7 | yes | fk41 | 0.0819005 | 0.0819966 | 0.00012 | 0.000113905 | 0.000114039
PORĘCZ | BL40*3 | +13.478 | +13.859 | 2 | 5 | 0.8 | 0 | 91.8 | 0.1 | 40 | 3 | 850.7 | yes | fk40 | 0.0732368 | 0.0732849 | 0.00012 | 0.000101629 | 0.000101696
PORĘCZ | RHS50*3 | +13.507 | +14.030 | 2 | 5 | 4.9 | 0 | 45.3 | 0.2 | 50 | 50 | 1101.4 | yes | fk66 | 0.216665 | 0.216665 | 0.00053866 | 0.000609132 | 0.000609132
2 x PORĘCZ | BL40*3 | +12.501 | +13.308 | 2 | 7 | 0.8 | 0 | 91.6 | 0.1 | 40 | 3 | 807 | yes | fk34 | 0.069642 | 0.069642 | 0.00012 | 0.00009684 | 0.00009684
PORĘCZ | BL40*3 | +12.543 | +13.348 | 2 | 7 | 0.8 | 0 | 91.6 | 0.1 | 40 | 3 | 805.2 | yes | fk55 | 0.0693861 | 0.0693861 | 0.00012 | 0.0000964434 | 0.0000964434
PORĘCZ | BL40*3 | +13.308 | +13.311 | 2 | 5 | 0.2 | 0 | 92.6 | 0 | 40 | 3 | 181.3 | no | fk65 | 0.0158008 | 0.0158008 | 0.00012 | 0.0000217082 | 0.0000217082
PORĘCZ | BL40*3 | +12.498 | +12.501 | 2 | 5 | 0.2 | 0 | 92.8 | 0 | 40 | 3 | 175.4 | yes | fk64 | 0.0152933 | 0.0152933 | 0.00012 | 0.000021 | 0.000021
PORĘCZ | BL40*3 | +13.308 | +13.385 | 2 | 5 | 0.2 | 0 | 92.8 | 0 | 40 | 3 | 165.9 | yes | fk44 | 0.0144836 | 0.0144836 | 0.00012 | 0.0000198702 | 0.0000198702
PORĘCZ | BL40*3 | +12.498 | +12.556 | 2 | 5 | 0.1 | 0 | 93.5 | 0 | 40 | 3 | 122.4 | yes | fk63 | 0.0106898 | 0.0131119 | 0.00012 | 0.0000145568 | 0.0000179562
PORĘCZ | BL40*3 | +13.308 | +13.311 | 2 | 4 | 0.2 | 0 | 92.6 | 0 | 40 | 3 | 190 | no | fk61 | 0.01658 | 0.01658 | 0.00012 | 0.0000228 | 0.0000228
2 x PORĘCZ | BL40*3 | +12.501 | +13.308 | 2 | 4 | 0.8 | 0 | 91.6 | 0.1 | 40 | 3 | 807 | yes | fk34 | 0.069642 | 0.069642 | 0.00012 | 0.00009684 | 0.00009684
PORĘCZ | BL40*3 | +12.498 | +12.501 | 2 | 4 | 0.2 | 0 | 92.6 | 0 | 40 | 3 | 190 | yes | fk61 | 0.01658 | 0.01658 | 0.00012 | 0.0000228 | 0.0000228
PORĘCZ | SHS50*3 | +13.260 | +13.310 | 2 | 4 | 4.6 | 0.1 | 45.3 | 0.2 | 50 | 50 | 1050 | no | fk38 | 0.2106 | 0.2106 | 0.00053866 | 0.0005922 | 0.0005922
PORĘCZ | BL40*3 | +13.833 | +13.861 | 2 | 5 | 0.1 | 0 | 95.7 | 0 | 40 | 3 | 58.4 | yes | fk58 | 0.0052332 | 0.0052332 | 0.00012 | 0.00000696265 | 0.00000696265
PORĘCZ | BL40*3 | +13.858 | +13.861 | 2 | 5 | 0.8 | 0 | 91.6 | 0.1 | 40 | 3 | 803.5 | no | fk55 | 0.0693098 | 0.0693098 | 0.00012 | 0.0000963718 | 0.0000963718
PORĘCZ | BL40*3 | +13.858 | +13.861 | 2 | 5 | 0.8 | 0 | 91.6 | 0.1 | 40 | 3 | 849 | no | fk57 | 0.073254 | 0.073254 | 0.00012 | 0.00010188 | 0.00010188
PORĘCZ | BL40*3 | +13.063 | +13.858 | 2 | 7 | 0.6 | 0 | 91.6 | 0.1 | 40 | 3 | 795.6 | yes | fk54 | 0.0686089 | 0.0686089 | 0.00012 | 0.0000953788 | 0.0000953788
PORĘCZ | BL40*3 | +13.123 | +13.858 | 2 | 7 | 0.6 | 0 | 91.6 | 0.1 | 40 | 3 | 735.6 | yes | fk53 | 0.0634489 | 0.0634489 | 0.00012 | 0.0000881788 | 0.0000881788
PORĘCZ | BL40*3 | +13.183 | +13.858 | 2 | 7 | 0.6 | 0 | 91.6 | 0.1 | 40 | 3 | 675.6 | yes | fk52 | 0.0582889 | 0.0582889 | 0.00012 | 0.0000809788 | 0.0000809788
PORĘCZ | BL40*3 | +13.243 | +13.858 | 2 | 7 | 0.6 | 0 | 91.6 | 0.1 | 40 | 3 | 615.6 | yes | fk51 | 0.0531289 | 0.0531289 | 0.00012 | 0.0000737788 | 0.0000737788
PORĘCZ | BL40*3 | +13.303 | +13.858 | 2 | 7 | 0.5 | 0 | 91.8 | 0 | 40 | 3 | 555.6 | yes | fk50 | 0.0479689 | 0.0479689 | 0.00012 | 0.0000665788 | 0.0000665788
PORĘCZ | BL40*3 | +13.363 | +13.858 | 2 | 7 | 0.5 | 0 | 91.8 | 0 | 40 | 3 | 495.6 | yes | fk49 | 0.0428089 | 0.0428089 | 0.00012 | 0.0000593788 | 0.0000593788
PORĘCZ | BL40*3 | +13.423 | +13.858 | 2 | 7 | 0.3 | 0 | 91.8 | 0 | 40 | 3 | 435.6 | yes | fk48 | 0.0376489 | 0.0376489 | 0.00012 | 0.0000521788 | 0.0000521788
PORĘCZ | BL40*3 | +13.513 | +13.858 | 2 | 7 | 0.3 | 0 | 92.1 | 0 | 40 | 3 | 345.6 | yes | fk47 | 0.0299089 | 0.0299089 | 0.00012 | 0.0000413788 | 0.0000413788
PORĘCZ | BL40*3 | +13.573 | +13.858 | 2 | 7 | 0.3 | 0 | 92.1 | 0 | 40 | 3 | 285.6 | yes | fk46 | 0.0247489 | 0.0247489 | 0.00012 | 0.0000341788 | 0.0000341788
PORĘCZ | BL40*3 | +13.633 | +13.858 | 2 | 7 | 0.2 | 0 | 92.5 | 0 | 40 | 3 | 225.6 | yes | fk45 | 0.0195889 | 0.0195889 | 0.00012 | 0.0000269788 | 0.0000269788
PORĘCZ | BL40*3 | +13.693 | +13.858 | 2 | 7 | 0.2 | 0 | 92.8 | 0 | 40 | 3 | 165.6 | yes | fk44 | 0.0144289 | 0.0144289 | 0.00012 | 0.0000197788 | 0.0000197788
PORĘCZ | BL40*3 | +13.753 | +13.858 | 2 | 7 | 0.1 | 0 | 93.9 | 0 | 40 | 3 | 105.6 | yes | fk43 | 0.00926894 | 0.00926894 | 0.00012 | 0.0000125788 | 0.0000125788
PORĘCZ | BL40*3 | +13.813 | +13.858 | 2 | 7 | 0 | 0 | 97.3 | 0 | 40 | 3 | 45.6 | yes | fk42 | 0.00410894 | 0.00410894 | 0.00012 | 0.00000537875 | 0.00000537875
PORĘCZ | BL40*3 | +13.478 | +13.858 | 2 | 5 | 0.8 | 0 | 91.8 | 0.1 | 40 | 3 | 850.7 | yes | fk40 | 0.0732368 | 0.0732849 | 0.00012 | 0.000101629 | 0.000101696
PORĘCZ | RHS50*3 | +13.430 | +14.030 | 2 | 5 | 5.4 | 0 | 45.3 | 0.2 | 50 | 50 | 1241.6 | yes | fk39 | 0.246584 | 0.246584 | 0.00053866 | 0.000693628 | 0.000693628
PORĘCZ | SHS50*3 | +12.500 | +12.550 | 2 | 4 | 4.6 | 0.1 | 45.3 | 0.2 | 50 | 50 | 1050 | yes | fk38 | 0.2106 | 0.2106 | 0.00053866 | 0.0005922 | 0.0005922
PORĘCZ | RHS50*3 | +13.430 | +13.480 | 2 | 5 | 0.8 | 0 | 45.9 | 0 | 50 | 50 | 180.9 | yes | fk37 | 0.0356082 | 0.0356082 | 0.00053866 | 0.0000987 | 0.0000987
PORĘCZ | BL40*3 | +12.684 | +12.687 | 3 | 5 | 0.3 | 0 | 92.3 | 0 | 40 | 3 | 294.5 | yes | fk36 | 0.0238967 | 0.0238967 | 0.00012 | 0.00003294 | 0.00003294
PORĘCZ | BL40*3 | +12.684 | +12.687 | 3 | 5 | 0.3 | 0 | 92.3 | 0 | 40 | 3 | 293.8 | yes | fk36 | 0.0238368 | 0.0238368 | 0.00012 | 0.0000328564 | 0.0000328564
PORĘCZ | BL40*3 | +12.845 | +13.653 | 3 | 7 | 0.8 | 0 | 91.6 | 0.1 | 40 | 3 | 808.1 | yes | fk2 | 0.0696399 | 0.0696399 | 0.00012 | 0.0000967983 | 0.0000967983
PORĘCZ | BL40*3 | +13.614 | +13.680 | 3 | 5 | 0.1 | 0 | 93.3 | 0 | 40 | 3 | 140.6 | yes | fk35 | 0.0122335 | 0.0122335 | 0.00012 | 0.0000166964 | 0.0000166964
PORĘCZ | BL40*3 | +12.804 | +12.869 | 3 | 5 | 0.1 | 0 | 93.3 | 0 | 40 | 3 | 140.2 | yes | fk35 | 0.0122015 | 0.0146347 | 0.00012 | 0.0000166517 | 0.0000200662
PORĘCZ | SHS50*3 | +14.910 | +15.009 | 1 | 5 | 17.2 | 0 | 45.2 | 0.7 | 50 | 50 | 3861.8 | yes | fk31 | 0.772956 | 0.772956 | 0.00053866 | 0.00217804 | 0.00217804
PORĘCZ | SHS50*3 | +14.959 | +15.060 | 1 | 5 | 17.8 | 0 | 45.2 | 0.7 | 50 | 50 | 4041.8 | yes | fk30 | 0.80408 | 0.80408 | 0.00053866 | 0.00226546 | 0.00226546
PORĘCZ | BL40*3 | +14.863 | +14.877 | 1 | 5 | 0.8 | 0 | 91.6 | 0.1 | 40 | 3 | 915.7 | yes | fk23 | 0.0789897 | 0.0833757 | 0.00012 | 0.000109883 | 0.000116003
PORĘCZ | BL40*3 | +14.850 | +14.865 | 1 | 5 | 0.8 | 0 | 91.6 | 0.1 | 40 | 3 | 915.7 | yes | fk23 | 0.0789897 | 0.0833757 | 0.00012 | 0.000109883 | 0.000116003
PORĘCZ | BL40*3 | +14.838 | +14.853 | 1 | 5 | 0.8 | 0 | 91.6 | 0.1 | 40 | 3 | 915.7 | yes | fk23 | 0.0789897 | 0.0833757 | 0.00012 | 0.000109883 | 0.000116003
PORĘCZ | BL40*3 | +14.826 | +14.840 | 1 | 5 | 0.8 | 0 | 91.6 | 0.1 | 40 | 3 | 911.2 | yes | fk29 | 0.0786027 | 0.0807957 | 0.00012 | 0.000109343 | 0.000112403
PORĘCZ | BL40*3 | +14.813 | +14.828 | 1 | 5 | 0.8 | 0 | 91.6 | 0.1 | 40 | 3 | 915.7 | yes | fk23 | 0.0789897 | 0.0833757 | 0.00012 | 0.000109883 | 0.000116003
PORĘCZ | BL40*3 | +14.801 | +14.816 | 1 | 5 | 0.8 | 0 | 91.6 | 0.1 | 40 | 3 | 915.7 | yes | fk23 | 0.0789897 | 0.0833757 | 0.00012 | 0.000109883 | 0.000116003
PORĘCZ | BL40*3 | +14.789 | +14.804 | 1 | 5 | 0.8 | 0 | 91.6 | 0.1 | 40 | 3 | 915.7 | yes | fk23 | 0.0789897 | 0.0833757 | 0.00012 | 0.000109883 | 0.000116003
PORĘCZ | BL40*3 | +14.777 | +14.791 | 1 | 5 | 0.8 | 0 | 91.6 | 0.1 | 40 | 3 | 911 | yes | fk29 | 0.0785863 | 0.0807793 | 0.00012 | 0.00010932 | 0.00011238
PORĘCZ | BL40*3 | +14.764 | +14.779 | 1 | 5 | 0.8 | 0 | 91.6 | 0.1 | 40 | 3 | 915.7 | yes | fk23 | 0.0789897 | 0.0833757 | 0.00012 | 0.000109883 | 0.000116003
PORĘCZ | BL40*3 | +14.752 | +14.767 | 1 | 5 | 0.8 | 0 | 91.6 | 0.1 | 40 | 3 | 915.7 | yes | fk23 | 0.0789897 | 0.0833757 | 0.00012 | 0.000109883 | 0.000116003
PORĘCZ | BL40*3 | +14.740 | +14.754 | 1 | 5 | 0.8 | 0 | 91.6 | 0.1 | 40 | 3 | 915.7 | yes | fk23 | 0.0789897 | 0.0833757 | 0.00012 | 0.000109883 | 0.000116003
PORĘCZ | BL40*3 | +14.727 | +14.742 | 1 | 5 | 0.8 | 0 | 91.6 | 0.1 | 40 | 3 | 915.7 | yes | fk23 | 0.0789897 | 0.0833757 | 0.00012 | 0.000109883 | 0.000116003
PORĘCZ | BL40*3 | +14.184 | +14.886 | 1 | 7 | 0.6 | 0 | 91.6 | 0.1 | 40 | 3 | 702 | yes | fk26 | 0.060612 | 0.060612 | 0.00012 | 0.00008424 | 0.00008424
PORĘCZ | BL40*3 | +14.183 | +14.885 | 1 | 7 | 0.6 | 0 | 91.6 | 0.1 | 40 | 3 | 702 | yes | fk26 | 0.060612 | 0.060612 | 0.00012 | 0.00008424 | 0.00008424
PORĘCZ | BL40*3 | +14.181 | +14.883 | 1 | 7 | 0.6 | 0 | 91.6 | 0.1 | 40 | 3 | 702 | yes | fk26 | 0.060612 | 0.060612 | 0.00012 | 0.00008424 | 0.00008424
PORĘCZ | BL40*3 | +14.180 | +14.882 | 1 | 7 | 0.6 | 0 | 91.6 | 0.1 | 40 | 3 | 702 | yes | fk26 | 0.060612 | 0.060612 | 0.00012 | 0.00008424 | 0.00008424
PORĘCZ | BL40*3 | +14.178 | +14.880 | 1 | 7 | 0.6 | 0 | 91.6 | 0.1 | 40 | 3 | 702 | yes | fk26 | 0.060612 | 0.060612 | 0.00012 | 0.00008424 | 0.00008424
PORĘCZ | BL40*3 | +14.176 | +14.878 | 1 | 7 | 0.6 | 0 | 91.6 | 0.1 | 40 | 3 | 702 | yes | fk26 | 0.060612 | 0.060612 | 0.00012 | 0.00008424 | 0.00008424
PORĘCZ | BL40*3 | +14.175 | +14.877 | 1 | 7 | 0.6 | 0 | 91.6 | 0.1 | 40 | 3 | 702 | yes | fk26 | 0.060612 | 0.060612 | 0.00012 | 0.00008424 | 0.00008424
PORĘCZ | BL40*3 | +14.173 | +14.875 | 1 | 7 | 0.6 | 0 | 91.6 | 0.1 | 40 | 3 | 702 | yes | fk26 | 0.060612 | 0.060612 | 0.00012 | 0.00008424 | 0.00008424
PORĘCZ | BL40*3 | +14.172 | +14.874 | 1 | 7 | 0.6 | 0 | 91.6 | 0.1 | 40 | 3 | 702 | yes | fk26 | 0.060612 | 0.060612 | 0.00012 | 0.00008424 | 0.00008424
PORĘCZ | BL40*3 | +14.169 | +14.871 | 1 | 7 | 0.6 | 0 | 91.6 | 0.1 | 40 | 3 | 702 | yes | fk26 | 0.060612 | 0.060612 | 0.00012 | 0.00008424 | 0.00008424
PORĘCZ | BL40*3 | +14.167 | +14.869 | 1 | 7 | 0.6 | 0 | 91.6 | 0.1 | 40 | 3 | 702 | yes | fk26 | 0.060612 | 0.060612 | 0.00012 | 0.00008424 | 0.00008424
PORĘCZ | BL40*3 | +14.163 | +14.865 | 1 | 7 | 0.6 | 0 | 91.6 | 0.1 | 40 | 3 | 702 | yes | fk26 | 0.060612 | 0.060612 | 0.00012 | 0.00008424 | 0.00008424
PORĘCZ | BL40*3 | +14.160 | +14.862 | 1 | 7 | 0.6 | 0 | 91.6 | 0.1 | 40 | 3 | 702 | yes | fk26 | 0.060612 | 0.060612 | 0.00012 | 0.00008424 | 0.00008424
PORĘCZ | BL40*3 | +14.156 | +14.858 | 1 | 7 | 0.6 | 0 | 91.6 | 0.1 | 40 | 3 | 702 | yes | fk26 | 0.060612 | 0.060612 | 0.00012 | 0.00008424 | 0.00008424
PORĘCZ | BL40*3 | +14.153 | +14.855 | 1 | 7 | 0.6 | 0 | 91.6 | 0.1 | 40 | 3 | 702 | yes | fk26 | 0.060612 | 0.060612 | 0.00012 | 0.00008424 | 0.00008424
PORĘCZ | BL40*3 | +14.150 | +14.852 | 1 | 7 | 0.6 | 0 | 91.6 | 0.1 | 40 | 3 | 702 | yes | fk26 | 0.060612 | 0.060612 | 0.00012 | 0.00008424 | 0.00008424
PORĘCZ | BL40*3 | +14.147 | +14.849 | 1 | 7 | 0.6 | 0 | 91.6 | 0.1 | 40 | 3 | 702 | yes | fk26 | 0.060612 | 0.060612 | 0.00012 | 0.00008424 | 0.00008424
PORĘCZ | BL40*3 | +14.144 | +14.846 | 1 | 7 | 0.6 | 0 | 91.6 | 0.1 | 40 | 3 | 702 | yes | fk26 | 0.060612 | 0.060612 | 0.00012 | 0.00008424 | 0.00008424
PORĘCZ | BL40*3 | +14.141 | +14.843 | 1 | 7 | 0.6 | 0 | 91.6 | 0.1 | 40 | 3 | 702 | yes | fk26 | 0.060612 | 0.060612 | 0.00012 | 0.00008424 | 0.00008424
2 x PORĘCZ | BL40*3 | +14.130 | +14.832 | 1 | 7 | 0.6 | 0 | 91.6 | 0.1 | 40 | 3 | 702 | yes | fk26 | 0.060612 | 0.060612 | 0.00012 | 0.00008424 | 0.00008424
2 x PORĘCZ | BL40*3 | +14.129 | +14.831 | 1 | 7 | 0.6 | 0 | 91.6 | 0.1 | 40 | 3 | 702 | yes | fk26 | 0.060612 | 0.060612 | 0.00012 | 0.00008424 | 0.00008424
2 x PORĘCZ | BL40*3 | +14.127 | +14.829 | 1 | 7 | 0.6 | 0 | 91.6 | 0.1 | 40 | 3 | 702 | yes | fk26 | 0.060612 | 0.060612 | 0.00012 | 0.00008424 | 0.00008424
2 x PORĘCZ | BL40*3 | +14.126 | +14.828 | 1 | 7 | 0.6 | 0 | 91.6 | 0.1 | 40 | 3 | 702 | yes | fk26 | 0.060612 | 0.060612 | 0.00012 | 0.00008424 | 0.00008424
2 x PORĘCZ | BL40*3 | +14.124 | +14.826 | 1 | 7 | 0.6 | 0 | 91.6 | 0.1 | 40 | 3 | 702 | yes | fk26 | 0.060612 | 0.060612 | 0.00012 | 0.00008424 | 0.00008424
PORĘCZ | BL40*3 | +14.123 | +14.825 | 1 | 7 | 0.6 | 0 | 91.6 | 0.1 | 40 | 3 | 702 | yes | fk26 | 0.060612 | 0.060612 | 0.00012 | 0.00008424 | 0.00008424
2 x PORĘCZ | BL40*3 | +14.121 | +14.823 | 1 | 7 | 0.6 | 0 | 91.6 | 0.1 | 40 | 3 | 702 | yes | fk26 | 0.060612 | 0.060612 | 0.00012 | 0.00008424 | 0.00008424
PORĘCZ | BL40*3 | +14.120 | +14.822 | 1 | 7 | 0.6 | 0 | 91.6 | 0.1 | 40 | 3 | 702 | yes | fk26 | 0.060612 | 0.060612 | 0.00012 | 0.00008424 | 0.00008424
PORĘCZ | BL40*3 | +14.117 | +14.819 | 1 | 7 | 0.6 | 0 | 91.6 | 0.1 | 40 | 3 | 702 | yes | fk26 | 0.060612 | 0.060612 | 0.00012 | 0.00008424 | 0.00008424
PORĘCZ | BL40*3 | +14.114 | +14.815 | 1 | 7 | 0.6 | 0 | 91.6 | 0.1 | 40 | 3 | 702 | yes | fk26 | 0.060612 | 0.060612 | 0.00012 | 0.00008424 | 0.00008424
PORĘCZ | BL40*3 | +14.106 | +14.808 | 1 | 7 | 0.6 | 0 | 91.6 | 0.1 | 40 | 3 | 702 | yes | fk26 | 0.060612 | 0.060612 | 0.00012 | 0.00008424 | 0.00008424
PORĘCZ | BL40*3 | +14.103 | +14.805 | 1 | 7 | 0.6 | 0 | 91.6 | 0.1 | 40 | 3 | 702 | yes | fk26 | 0.060612 | 0.060612 | 0.00012 | 0.00008424 | 0.00008424
PORĘCZ | BL40*3 | +14.100 | +14.802 | 1 | 7 | 0.6 | 0 | 91.6 | 0.1 | 40 | 3 | 702 | yes | fk26 | 0.060612 | 0.060612 | 0.00012 | 0.00008424 | 0.00008424
PORĘCZ | BL40*3 | +14.097 | +14.799 | 1 | 7 | 0.6 | 0 | 91.6 | 0.1 | 40 | 3 | 702 | yes | fk26 | 0.060612 | 0.060612 | 0.00012 | 0.00008424 | 0.00008424
PORĘCZ | BL40*3 | +14.094 | +14.795 | 1 | 7 | 0.6 | 0 | 91.6 | 0.1 | 40 | 3 | 702 | yes | fk26 | 0.060612 | 0.060612 | 0.00012 | 0.00008424 | 0.00008424
PORĘCZ | BL40*3 | +14.092 | +14.794 | 1 | 7 | 0.6 | 0 | 91.6 | 0.1 | 40 | 3 | 702 | yes | fk26 | 0.060612 | 0.060612 | 0.00012 | 0.00008424 | 0.00008424
PORĘCZ | BL40*3 | +14.089 | +14.791 | 1 | 7 | 0.6 | 0 | 91.6 | 0.1 | 40 | 3 | 702 | yes | fk26 | 0.060612 | 0.060612 | 0.00012 | 0.00008424 | 0.00008424
PORĘCZ | BL40*3 | +14.086 | +14.788 | 1 | 7 | 0.6 | 0 | 91.6 | 0.1 | 40 | 3 | 702 | yes | fk26 | 0.060612 | 0.060612 | 0.00012 | 0.00008424 | 0.00008424
PORĘCZ | BL40*3 | +14.083 | +14.785 | 1 | 7 | 0.6 | 0 | 91.6 | 0.1 | 40 | 3 | 702 | yes | fk26 | 0.060612 | 0.060612 | 0.00012 | 0.00008424 | 0.00008424
PORĘCZ | BL40*3 | +14.080 | +14.782 | 1 | 7 | 0.6 | 0 | 91.6 | 0.1 | 40 | 3 | 702 | yes | fk26 | 0.060612 | 0.060612 | 0.00012 | 0.00008424 | 0.00008424
PORĘCZ | BL40*3 | +14.078 | +14.780 | 1 | 7 | 0.6 | 0 | 91.6 | 0.1 | 40 | 3 | 702 | yes | fk26 | 0.060612 | 0.060612 | 0.00012 | 0.00008424 | 0.00008424
PORĘCZ | BL40*3 | +14.077 | +14.779 | 1 | 7 | 0.6 | 0 | 91.6 | 0.1 | 40 | 3 | 702 | yes | fk26 | 0.060612 | 0.060612 | 0.00012 | 0.00008424 | 0.00008424
PORĘCZ | BL40*3 | +14.075 | +14.777 | 1 | 7 | 0.6 | 0 | 91.6 | 0.1 | 40 | 3 | 702 | yes | fk26 | 0.060612 | 0.060612 | 0.00012 | 0.00008424 | 0.00008424
PORĘCZ | BL40*3 | +14.074 | +14.775 | 1 | 7 | 0.6 | 0 | 91.6 | 0.1 | 40 | 3 | 702 | yes | fk26 | 0.060612 | 0.060612 | 0.00012 | 0.00008424 | 0.00008424
PORĘCZ | BL40*3 | +14.072 | +14.774 | 1 | 7 | 0.6 | 0 | 91.6 | 0.1 | 40 | 3 | 702 | yes | fk26 | 0.060612 | 0.060612 | 0.00012 | 0.00008424 | 0.00008424
PORĘCZ | BL40*3 | +14.069 | +14.771 | 1 | 7 | 0.6 | 0 | 91.6 | 0.1 | 40 | 3 | 702 | yes | fk26 | 0.060612 | 0.060612 | 0.00012 | 0.00008424 | 0.00008424
PORĘCZ | BL40*3 | +14.066 | +14.768 | 1 | 7 | 0.6 | 0 | 91.6 | 0.1 | 40 | 3 | 702 | yes | fk26 | 0.060612 | 0.060612 | 0.00012 | 0.00008424 | 0.00008424
PORĘCZ | BL40*3 | +14.063 | +14.765 | 1 | 7 | 0.6 | 0 | 91.6 | 0.1 | 40 | 3 | 702 | yes | fk26 | 0.060612 | 0.060612 | 0.00012 | 0.00008424 | 0.00008424
PORĘCZ | BL40*3 | +14.060 | +14.762 | 1 | 7 | 0.6 | 0 | 91.6 | 0.1 | 40 | 3 | 702 | yes | fk26 | 0.060612 | 0.060612 | 0.00012 | 0.00008424 | 0.00008424
PORĘCZ | BL40*3 | +14.058 | +14.760 | 1 | 7 | 0.6 | 0 | 91.6 | 0.1 | 40 | 3 | 702 | yes | fk26 | 0.060612 | 0.060612 | 0.00012 | 0.00008424 | 0.00008424
PORĘCZ | BL40*3 | +14.055 | +14.757 | 1 | 7 | 0.6 | 0 | 91.6 | 0.1 | 40 | 3 | 702 | yes | fk26 | 0.060612 | 0.060612 | 0.00012 | 0.00008424 | 0.00008424
PORĘCZ | BL40*3 | +14.052 | +14.754 | 1 | 7 | 0.6 | 0 | 91.6 | 0.1 | 40 | 3 | 702 | yes | fk26 | 0.060612 | 0.060612 | 0.00012 | 0.00008424 | 0.00008424
PORĘCZ | BL40*3 | +14.049 | +14.751 | 1 | 7 | 0.6 | 0 | 91.6 | 0.1 | 40 | 3 | 702 | yes | fk26 | 0.060612 | 0.060612 | 0.00012 | 0.00008424 | 0.00008424
PORĘCZ | BL40*3 | +14.046 | +14.748 | 1 | 7 | 0.6 | 0 | 91.6 | 0.1 | 40 | 3 | 702 | yes | fk26 | 0.060612 | 0.060612 | 0.00012 | 0.00008424 | 0.00008424
PORĘCZ | BL40*3 | +14.044 | +14.746 | 1 | 7 | 0.6 | 0 | 91.6 | 0.1 | 40 | 3 | 702 | yes | fk26 | 0.060612 | 0.060612 | 0.00012 | 0.00008424 | 0.00008424
PORĘCZ | BL40*3 | +14.041 | +14.743 | 1 | 7 | 0.6 | 0 | 91.6 | 0.1 | 40 | 3 | 702 | yes | fk26 | 0.060612 | 0.060612 | 0.00012 | 0.00008424 | 0.00008424
PORĘCZ | BL40*3 | +14.038 | +14.740 | 1 | 7 | 0.6 | 0 | 91.6 | 0.1 | 40 | 3 | 702 | yes | fk26 | 0.060612 | 0.060612 | 0.00012 | 0.00008424 | 0.00008424
PORĘCZ | BL40*3 | +14.035 | +14.737 | 1 | 7 | 0.6 | 0 | 91.6 | 0.1 | 40 | 3 | 702 | yes | fk26 | 0.060612 | 0.060612 | 0.00012 | 0.00008424 | 0.00008424
PORĘCZ | BL40*3 | +14.032 | +14.734 | 1 | 7 | 0.6 | 0 | 91.6 | 0.1 | 40 | 3 | 702 | yes | fk26 | 0.060612 | 0.060612 | 0.00012 | 0.00008424 | 0.00008424
PORĘCZ | BL40*3 | +14.031 | +14.733 | 1 | 7 | 0.6 | 0 | 91.6 | 0.1 | 40 | 3 | 702 | yes | fk26 | 0.060612 | 0.060612 | 0.00012 | 0.00008424 | 0.00008424
PORĘCZ | BL40*3 | +14.029 | +14.731 | 1 | 7 | 0.6 | 0 | 91.6 | 0.1 | 40 | 3 | 702 | yes | fk26 | 0.060612 | 0.060612 | 0.00012 | 0.00008424 | 0.00008424
PORĘCZ | BL40*3 | +14.027 | +14.729 | 1 | 7 | 0.6 | 0 | 91.6 | 0.1 | 40 | 3 | 702 | yes | fk26 | 0.060612 | 0.060612 | 0.00012 | 0.00008424 | 0.00008424
PORĘCZ | BL40*3 | +14.026 | +14.728 | 1 | 7 | 0.6 | 0 | 91.6 | 0.1 | 40 | 3 | 702 | yes | fk26 | 0.060612 | 0.060612 | 0.00012 | 0.00008424 | 0.00008424
PORĘCZ | BL40*3 | +14.158 | +14.172 | 1 | 5 | 0.8 | 0 | 91.6 | 0.1 | 40 | 3 | 915.7 | yes | fk23 | 0.0789897 | 0.0833757 | 0.00012 | 0.000109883 | 0.000116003
PORĘCZ | BL40*3 | +14.145 | +14.160 | 1 | 5 | 0.8 | 0 | 91.6 | 0.1 | 40 | 3 | 915.7 | yes | fk23 | 0.0789897 | 0.0833757 | 0.00012 | 0.000109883 | 0.000116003
PORĘCZ | BL40*3 | +14.133 | +14.148 | 1 | 5 | 0.8 | 0 | 91.6 | 0.1 | 40 | 3 | 915.7 | yes | fk23 | 0.0789897 | 0.0833757 | 0.00012 | 0.000109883 | 0.000116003
PORĘCZ | BL40*3 | +14.121 | +14.135 | 1 | 5 | 0.8 | 0 | 91.6 | 0.1 | 40 | 3 | 911.2 | yes | fk29 | 0.0786027 | 0.0807957 | 0.00012 | 0.000109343 | 0.000112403
PORĘCZ | BL40*3 | +14.109 | +14.123 | 1 | 5 | 0.8 | 0 | 91.6 | 0.1 | 40 | 3 | 915.7 | yes | fk23 | 0.0789897 | 0.0833757 | 0.00012 | 0.000109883 | 0.000116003
PORĘCZ | BL40*3 | +14.096 | +14.111 | 1 | 5 | 0.8 | 0 | 91.6 | 0.1 | 40 | 3 | 915.7 | yes | fk23 | 0.0789897 | 0.0833757 | 0.00012 | 0.000109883 | 0.000116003
PORĘCZ | BL40*3 | +14.084 | +14.099 | 1 | 5 | 0.8 | 0 | 91.6 | 0.1 | 40 | 3 | 915.7 | yes | fk23 | 0.0789897 | 0.0833757 | 0.00012 | 0.000109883 | 0.000116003
PORĘCZ | BL40*3 | +14.072 | +14.086 | 1 | 5 | 0.8 | 0 | 91.6 | 0.1 | 40 | 3 | 911 | yes | fk29 | 0.0785863 | 0.0807793 | 0.00012 | 0.00010932 | 0.00011238
PORĘCZ | BL40*3 | +14.059 | +14.074 | 1 | 5 | 0.8 | 0 | 91.6 | 0.1 | 40 | 3 | 915.7 | yes | fk23 | 0.0789897 | 0.0833757 | 0.00012 | 0.000109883 | 0.000116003
PORĘCZ | BL40*3 | +14.047 | +14.062 | 1 | 5 | 0.8 | 0 | 91.6 | 0.1 | 40 | 3 | 915.7 | yes | fk23 | 0.0789897 | 0.0833757 | 0.00012 | 0.000109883 | 0.000116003
PORĘCZ | BL40*3 | +14.035 | +14.049 | 1 | 5 | 0.8 | 0 | 91.6 | 0.1 | 40 | 3 | 915.7 | yes | fk23 | 0.0789897 | 0.0833757 | 0.00012 | 0.000109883 | 0.000116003
PORĘCZ | BL40*3 | +14.023 | +14.037 | 1 | 5 | 0.8 | 0 | 91.6 | 0.1 | 40 | 3 | 915.7 | yes | fk23 | 0.0789897 | 0.0833757 | 0.00012 | 0.000109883 | 0.000116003
PORĘCZ | SHS50*3 | +14.906 | +15.006 | 1 | 5 | 17.5 | 0 | 45.2 | 0.7 | 50 | 50 | 3950 | yes | fk27 | 0.7906 | 0.7906 | 0.00053866 | 0.0022278 | 0.0022278
PORĘCZ | BL40*3 | +14.822 | +14.837 | 1 | 5 | 0.8 | 0 | 91.6 | 0.1 | 40 | 3 | 925 | yes | fk25 | 0.07979 | 0.07979 | 0.00012 | 0.000111 | 0.000111
PORĘCZ | BL40*3 | +14.123 | +14.824 | 1 | 7 | 0.6 | 0 | 91.6 | 0.1 | 40 | 3 | 702 | yes | fk26 | 0.060612 | 0.060612 | 0.00012 | 0.00008424 | 0.00008424
PORĘCZ | BL40*3 | +14.117 | +14.132 | 1 | 5 | 0.8 | 0 | 91.6 | 0.1 | 40 | 3 | 925 | yes | fk25 | 0.07979 | 0.07979 | 0.00012 | 0.000111 | 0.000111
PORĘCZ | SHS50*3 | +13.733 | +14.040 | 3 | 5 | 2.7 | 0 | 45.4 | 0.1 | 50 | 50 | 622.4 | no | fk20 | 0.120875 | 0.120875 | 0.00053866 | 0.000339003 | 0.000339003
2 x PORĘCZ | BL40*3 | +13.869 | +13.872 | 3 | 5 | 1.5 | 0.1 | 91.6 | 0.1 | 40 | 3 | 1636.1 | no | fk18 | 0.140808 | 0.140808 | 0.00012 | 0.000195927 | 0.000195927
PORĘCZ | BL40*3 | +13.701 | +13.872 | 3 | 5 | 0.3 | 0 | 92 | 0 | 40 | 3 | 379.3 | yes | fk16 | 0.0327861 | 0.0327861 | 0.00012 | 0.0000453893 | 0.0000453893
2 x PORĘCZ | BL40*3 | +13.818 | +13.869 | 3 | 7 | 0 | 0 | 96.7 | 0 | 40 | 3 | 50.4 | yes | fk15 | 0.00452639 | 0.00452639 | 0.00012 | 0.00000596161 | 0.00000596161
2 x PORĘCZ | BL40*3 | +13.759 | +13.869 | 3 | 7 | 0.1 | 0 | 93.9 | 0 | 40 | 3 | 109.8 | yes | fk14 | 0.00963559 | 0.00963559 | 0.00012 | 0.0000130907 | 0.0000130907
2 x PORĘCZ | BL40*3 | +13.700 | +13.869 | 3 | 7 | 0.2 | 0 | 92.8 | 0 | 40 | 3 | 169.2 | yes | fk13 | 0.0147448 | 0.0147448 | 0.00012 | 0.0000202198 | 0.0000202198
2 x PORĘCZ | BL40*3 | +13.640 | +13.869 | 3 | 7 | 0.2 | 0 | 92.5 | 0 | 40 | 3 | 228.7 | yes | fk12 | 0.019854 | 0.019854 | 0.00012 | 0.000027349 | 0.000027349
2 x PORĘCZ | BL40*3 | +13.574 | +13.869 | 3 | 7 | 0.3 | 0 | 92.1 | 0 | 40 | 3 | 294.7 | yes | fk11 | 0.0255307 | 0.0255307 | 0.00012 | 0.00003527 | 0.00003527
2 x PORĘCZ | BL40*3 | +13.515 | +13.869 | 3 | 7 | 0.3 | 0 | 92.1 | 0 | 40 | 3 | 354.1 | yes | fk10 | 0.0306399 | 0.0306399 | 0.00012 | 0.0000423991 | 0.0000423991
2 x PORĘCZ | BL40*3 | +13.455 | +13.869 | 3 | 7 | 0.3 | 0 | 91.8 | 0 | 40 | 3 | 413.5 | yes | fk9 | 0.0357491 | 0.0357491 | 0.00012 | 0.0000495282 | 0.0000495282
2 x PORĘCZ | BL40*3 | +13.396 | +13.869 | 3 | 7 | 0.3 | 0 | 91.8 | 0 | 40 | 3 | 472.9 | yes | fk8 | 0.0408583 | 0.0408583 | 0.00012 | 0.0000566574 | 0.0000566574
2 x PORĘCZ | BL40*3 | +13.337 | +13.869 | 3 | 7 | 0.5 | 0 | 91.8 | 0 | 40 | 3 | 532.3 | yes | fk7 | 0.0459675 | 0.0459675 | 0.00012 | 0.0000637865 | 0.0000637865
2 x PORĘCZ | BL40*3 | +13.277 | +13.869 | 3 | 7 | 0.6 | 0 | 91.8 | 0.1 | 40 | 3 | 591.7 | yes | fk6 | 0.0510767 | 0.0510767 | 0.00012 | 0.0000709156 | 0.0000709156
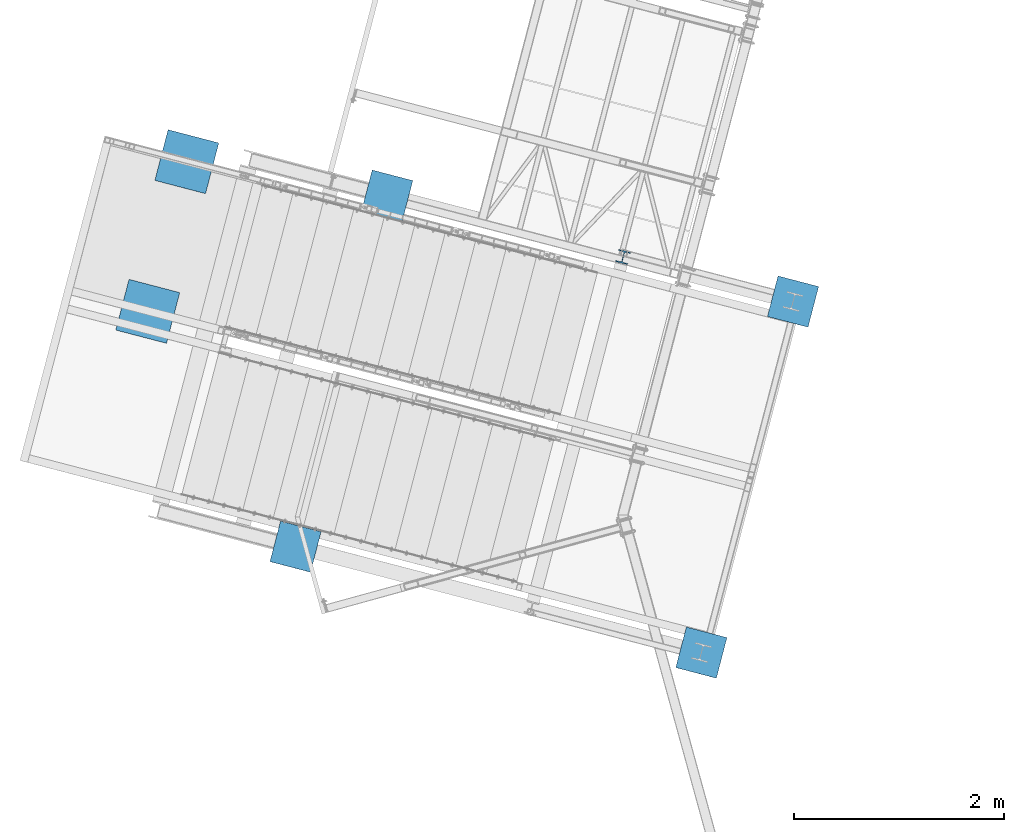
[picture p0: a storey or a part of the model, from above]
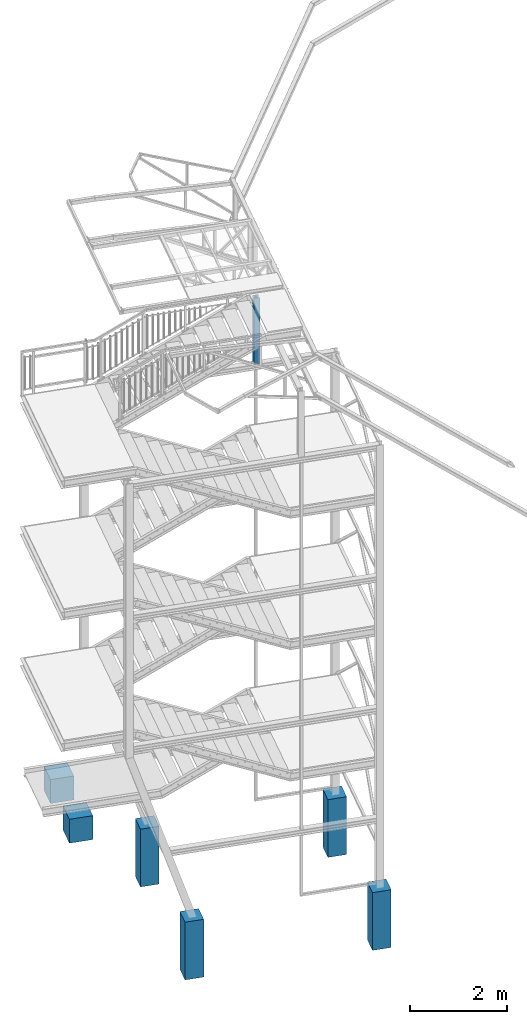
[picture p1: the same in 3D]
Properties of the parts of a building model (IFC2X3), part 4 of 5

# IfcDiscreteAccessory: PORĘCZ (577)
Name | Description | Bottom elevation | Top elevation | Phase | Class | Weight (kg) | Gross footprint area (m2) | Area per tons (m2) | Net surface area (m2) | Height (mm) | Width (mm) | Length (mm) | LoadBearing | Reference | NetArea (m2) | GrossArea (m2) | CrossSectionArea (m2) | NetVolume (m3) | GrossVolume (m3)
2 x PORĘCZ | BL40*3 | +13.211 | +13.869 | 3 | 7 | 0.6 | 0 | 91.6 | 0.1 | 40 | 3 | 657.7 | yes | fk5 | 0.0567535 | 0.0567535 | 0.00012 | 0.0000788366 | 0.0000788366
2 x PORĘCZ | BL40*3 | +13.152 | +13.869 | 3 | 7 | 0.6 | 0 | 91.6 | 0.1 | 40 | 3 | 717.1 | yes | fk4 | 0.0618627 | 0.0618627 | 0.00012 | 0.0000859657 | 0.0000859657
2 x PORĘCZ | BL40*3 | +13.092 | +13.869 | 3 | 7 | 0.6 | 0 | 91.6 | 0.1 | 40 | 3 | 776.5 | yes | fk3 | 0.0669719 | 0.0669719 | 0.00012 | 0.0000930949 | 0.0000930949
2 x PORĘCZ | BL40*3 | +13.033 | +13.841 | 3 | 7 | 0.8 | 0 | 91.6 | 0.1 | 40 | 3 | 808.1 | yes | fk2 | 0.0696399 | 0.0696399 | 0.00012 | 0.0000967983 | 0.0000967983
2 x PORĘCZ | BL40*3 | +12.974 | +13.782 | 3 | 7 | 0.8 | 0 | 91.6 | 0.1 | 40 | 3 | 808.1 | yes | fk2 | 0.0696399 | 0.0696399 | 0.00012 | 0.0000967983 | 0.0000967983
2 x PORĘCZ | BL40*3 | +12.914 | +13.722 | 3 | 7 | 0.8 | 0 | 91.6 | 0.1 | 40 | 3 | 808.1 | yes | fk2 | 0.0696399 | 0.0696399 | 0.00012 | 0.0000967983 | 0.0000967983
2 x PORĘCZ | BL40*3 | +13.617 | +13.958 | 3 | 5 | 0.6 | 0 | 91.6 | 0.1 | 40 | 3 | 762.9 | yes | fk1 | 0.0657458 | 0.0706121 | 0.00012 | 0.0000913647 | 0.0000981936
2 x PORĘCZ | BL40*3 | +13.254 | +13.595 | 3 | 5 | 0.6 | 0 | 91.6 | 0.1 | 40 | 3 | 762.9 | yes | fk1 | 0.0657458 | 0.0682269 | 0.00012 | 0.0000913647 | 0.0000948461
2 x PORĘCZ | BL40*3 | +12.891 | +13.232 | 3 | 5 | 0.6 | 0 | 91.6 | 0.1 | 40 | 3 | 762.9 | yes | fk1 | 0.0657458 | 0.0658418 | 0.00012 | 0.0000913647 | 0.0000914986
PORĘCZ | SHS50*3 | +13.615 | +14.040 | 3 | 5 | 3.7 | 0 | 45.3 | 0.2 | 50 | 50 | 856.9 | no | fk19 | 0.169656 | 0.169656 | 0.00053866 | 0.000476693 | 0.000476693
PORĘCZ | SHS50*3 | +13.990 | +14.040 | 3 | 5 | 9.2 | 0.1 | 45.2 | 0.4 | 50 | 50 | 2111 | no | fk17 | 0.421636 | 0.421636 | 0.00053866 | 0.0011873 | 0.0011873
PORĘCZ | BL40*3 | +13.701 | +13.872 | 3 | 5 | 0.3 | 0 | 92 | 0 | 40 | 3 | 378.8 | yes | fk16 | 0.0327381 | 0.0327861 | 0.00012 | 0.0000453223 | 0.0000453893

# IfcDiscreteAccessory: STANCHION (61)
In: Undefined
Description: SHS50*3; Material: STEEL/S235
Tekla Quantity - Volume: 0 m3; Gross footprint area: 0 m2; Height: 50 mm; Width: 50 mm
Pset_PlateCommon - LoadBearing: yes
BaseQuantities - CrossSectionArea: 0.00053866 m2
Name | Bottom elevation | Top elevation | Phase | Class | Weight (kg) | Area per tons (m2) | Net surface area (m2) | Length (mm) | Reference | NetArea (m2) = GrossArea (m2) | NetVolume (m3) = GrossVolume (m3)
STANCHION | +13.776 | +14.971 | 1 | 10 | 5.4 | 45.3 | 0.2 | 1195 | fb3 | 0.2396 | 0.00067398
2 x STANCHION | +13.797 | +14.992 | 1 | 10 | 5.4 | 45.3 | 0.2 | 1195 | fb6 | 0.2396 | 0.00067398
STANCHION | +13.793 | +14.989 | 1 | 10 | 5.4 | 45.3 | 0.2 | 1195 | fb6 | 0.2396 | 0.00067398
STANCHION | +13.801 | +14.996 | 1 | 10 | 5.4 | 45.3 | 0.2 | 1195 | fb6 | 0.2396 | 0.00067398
2 x STANCHION | +12.575 | +13.615 | 3 | 10 | 4.6 | 45.3 | 0.2 | 1040 | fb26 | 0.2086 | 0.00058656
STANCHION | +12.575 | +13.764 | 3 | 5 | 5.2 | 45.3 | 0.2 | 1188.8 | fb27 | 0.235316 | 0.000661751
4 x STANCHION | +12.575 | +13.615 | 3 | 10 | 4.6 | 45.3 | 0.2 | 1040 | fb13 | 0.2086 | 0.00058656
STANCHION | +13.674 | +14.870 | 1 | 10 | 5.4 | 45.3 | 0.2 | 1195 | fb3 | 0.2396 | 0.00067398
STANCHION | +13.699 | +14.894 | 1 | 10 | 5.4 | 45.3 | 0.2 | 1195 | fb3 | 0.2396 | 0.00067398
STANCHION | +13.711 | +14.907 | 1 | 10 | 5.4 | 45.3 | 0.2 | 1195 | fb25 | 0.2396 | 0.00067398
STANCHION | +13.724 | +14.919 | 1 | 10 | 5.4 | 45.3 | 0.2 | 1195 | fb3 | 0.2396 | 0.00067398
STANCHION | +13.736 | +14.931 | 1 | 10 | 5.4 | 45.3 | 0.2 | 1195 | fb3 | 0.2396 | 0.00067398
2 x STANCHION | +13.764 | +14.959 | 1 | 10 | 5.4 | 45.3 | 0.2 | 1195 | fb6 | 0.2396 | 0.00067398
STANCHION | +13.767 | +14.963 | 1 | 10 | 5.4 | 45.3 | 0.2 | 1195 | fb6 | 0.2396 | 0.00067398
STANCHION | +13.785 | +14.980 | 1 | 10 | 5.4 | 45.3 | 0.2 | 1195 | fb3 | 0.2396 | 0.00067398
3 x STANCHION | +13.665 | +14.845 | 5 | 10 | 5.2 | 45.3 | 0.2 | 1180 | fb23 | 0.2366 | 0.00066552
2 x STANCHION | +13.665 | +14.845 | 5 | 10 | 5.2 | 45.3 | 0.2 | 1180 | fb24 | 0.2366 | 0.00066552
STANCHION | +12.452 | +13.538 | 2 | 10 | 4.6 | 45.3 | 0.2 | 1085.5 | fb20 | 0.212207 | 0.000596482
STANCHION | +12.902 | +13.957 | 2 | 10 | 4.6 | 45.3 | 0.2 | 1054.6 | fb1 | 0.206599 | 0.000580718
STANCHION | +13.352 | +13.980 | 2 | 10 | 2.7 | 45.4 | 0.1 | 628.1 | fb17 | 0.123754 | 0.000347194
STANCHION | +13.802 | +13.980 | 2 | 10 | 0.6 | 45.9 | 0 | 178.1 | fb16 | 0.0337538 | 0.000093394
2 x STANCHION | +12.350 | +13.430 | 2 | 4 | 4.9 | 45.3 | 0.2 | 1080 | fb15 | 0.2166 | 0.00060912
STANCHION | +12.452 | +13.507 | 2 | 10 | 4.6 | 45.3 | 0.2 | 1054.4 | fb1 | 0.206548 | 0.000580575
STANCHION | +12.902 | +13.957 | 2 | 10 | 4.6 | 45.3 | 0.2 | 1054.4 | fb1 | 0.206548 | 0.000580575
STANCHION | +13.352 | +13.980 | 2 | 10 | 2.7 | 45.4 | 0.1 | 627.8 | fb17 | 0.123703 | 0.000347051
STANCHION | +13.802 | +13.980 | 2 | 10 | 0.6 | 45.9 | 0 | 177.8 | fb16 | 0.0337032 | 0.0000932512
STANCHION | +12.350 | +13.430 | 2 | 4 | 4.9 | 45.3 | 0.2 | 1080 | fb14 | 0.2166 | 0.00060912
STANCHION | +13.813 | +15.009 | 1 | 10 | 5.4 | 45.3 | 0.2 | 1195 | fb3 | 0.2396 | 0.00067398
STANCHION | +13.801 | +14.996 | 1 | 10 | 5.4 | 45.3 | 0.2 | 1195 | fb3 | 0.2396 | 0.00067398
STANCHION | +13.789 | +14.984 | 1 | 10 | 5.4 | 45.3 | 0.2 | 1195 | fb3 | 0.2396 | 0.00067398
STANCHION | +13.776 | +14.972 | 1 | 10 | 5.4 | 45.3 | 0.2 | 1195 | fb3 | 0.2396 | 0.00067398
STANCHION | +13.764 | +14.960 | 1 | 10 | 5.4 | 45.3 | 0.2 | 1195 | fb6 | 0.2396 | 0.00067398
STANCHION | +13.752 | +14.947 | 1 | 10 | 5.4 | 45.3 | 0.2 | 1195 | fb3 | 0.2396 | 0.00067398
STANCHION | +13.739 | +14.935 | 1 | 10 | 5.4 | 45.3 | 0.2 | 1195 | fb3 | 0.2396 | 0.00067398
STANCHION | +13.727 | +14.923 | 1 | 10 | 5.4 | 45.3 | 0.2 | 1195 | fb3 | 0.2396 | 0.00067398
STANCHION | +13.715 | +14.910 | 1 | 10 | 5.4 | 45.3 | 0.2 | 1195 | fb11 | 0.2396 | 0.00067398
STANCHION | +13.703 | +14.898 | 1 | 10 | 5.4 | 45.3 | 0.2 | 1195 | fb3 | 0.2396 | 0.00067398
STANCHION | +13.690 | +14.886 | 1 | 10 | 5.4 | 45.3 | 0.2 | 1195 | fb3 | 0.2396 | 0.00067398
STANCHION | +13.678 | +14.874 | 1 | 10 | 5.4 | 45.3 | 0.2 | 1195 | fb3 | 0.2396 | 0.00067398
STANCHION | +13.666 | +14.861 | 1 | 10 | 5.4 | 45.3 | 0.2 | 1195 | fb3 | 0.2396 | 0.00067398
STANCHION | +13.662 | +14.857 | 1 | 10 | 5.4 | 45.3 | 0.2 | 1195 | fb7 | 0.2396 | 0.00067398
STANCHION | +13.748 | +14.944 | 1 | 10 | 5.4 | 45.3 | 0.2 | 1195 | fb3 | 0.2396 | 0.00067398
STANCHION | +13.761 | +14.956 | 1 | 10 | 5.4 | 45.3 | 0.2 | 1195 | fb6 | 0.2396 | 0.00067398
2 x STANCHION | +13.850 | +13.990 | 3 | 10 | 0.6 | 46.3 | 0 | 140.8 | fb5 | 0.0263364 | 0.0000724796
2 x STANCHION | +13.488 | +13.990 | 3 | 10 | 2.2 | 45.4 | 0.1 | 502.3 | fb4 | 0.0986304 | 0.000276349
2 x STANCHION | +13.127 | +13.990 | 3 | 10 | 3.8 | 45.3 | 0.2 | 863.8 | fb2 | 0.170924 | 0.000480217
2 x STANCHION | +12.765 | +13.820 | 3 | 10 | 4.6 | 45.3 | 0.2 | 1054.4 | fb1 | 0.206635 | 0.000580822

# IfcDiscreteAccessory: STOPNIE (82)
In: Undefined
Material: STEEL/S235JR
Tekla Common - Class: 2
Tekla Quantity - Volume: 0 m3; Gross footprint area: 0.3 m2; Net surface area: 1 m2; Height: 300 mm
Pset_PlateCommon - LoadBearing: yes
Name | Description | Bottom elevation | Top elevation | Phase | Weight (kg) | Area per tons (m2) | Width (mm) | Length (mm) | Reference | NetArea (m2) = GrossArea (m2) | CrossSectionArea (m2) | NetVolume (m3) = GrossVolume (m3)
STOPNIE | PL40*300 | +13.853 | +13.893 | 3 | 139.4 | 7.4 | 40 | 1480 | bs4 | 1.0304 | 0.012 | 0.01776
STOPNIE | PL40*300 | +13.706 | +13.746 | 3 | 139.4 | 7.4 | 40 | 1480 | bs4 | 1.0304 | 0.012 | 0.01776
STOPNIE | PL40*300 | +13.558 | +13.598 | 3 | 139.4 | 7.4 | 40 | 1480 | bs4 | 1.0304 | 0.012 | 0.01776
STOPNIE | PL40*300 | +13.411 | +13.451 | 3 | 139.4 | 7.4 | 40 | 1480 | bs4 | 1.0304 | 0.012 | 0.01776
STOPNIE | PL40*300 | +13.263 | +13.303 | 3 | 139.4 | 7.4 | 40 | 1480 | bs4 | 1.0304 | 0.012 | 0.01776
STOPNIE | PL40*300 | +13.116 | +13.156 | 3 | 139.4 | 7.4 | 40 | 1480 | bs4 | 1.0304 | 0.012 | 0.01776
STOPNIE | PL40*300 | +12.969 | +13.009 | 3 | 139.4 | 7.4 | 40 | 1480 | bs4 | 1.0304 | 0.012 | 0.01776
STOPNIE | PL40*300 | +12.821 | +12.861 | 3 | 139.4 | 7.4 | 40 | 1480 | bs4 | 1.0304 | 0.012 | 0.01776
STOPNIE | PL40*300 | +12.674 | +12.714 | 3 | 139.4 | 7.4 | 40 | 1480 | bs4 | 1.0304 | 0.012 | 0.01776
STOPNIE | PL30*300 | +13.850 | +13.880 | 2 | 98.9 | 9.5 | 30 | 1400 | bs1 | 0.942 | 0.009 | 0.0126
STOPNIE | PL30*300 | +13.700 | +13.730 | 2 | 98.9 | 9.5 | 30 | 1400 | bs1 | 0.942 | 0.009 | 0.0126
STOPNIE | PL30*300 | +13.550 | +13.580 | 2 | 98.9 | 9.5 | 30 | 1400 | bs1 | 0.942 | 0.009 | 0.0126
STOPNIE | PL30*300 | +13.400 | +13.430 | 2 | 98.9 | 9.5 | 30 | 1400 | bs1 | 0.942 | 0.009 | 0.0126
STOPNIE | PL30*300 | +13.250 | +13.280 | 2 | 98.9 | 9.5 | 30 | 1400 | bs1 | 0.942 | 0.009 | 0.0126
STOPNIE | PL30*300 | +13.100 | +13.130 | 2 | 98.9 | 9.5 | 30 | 1400 | bs1 | 0.942 | 0.009 | 0.0126
STOPNIE | PL30*300 | +12.950 | +12.980 | 2 | 98.9 | 9.5 | 30 | 1400 | bs1 | 0.942 | 0.009 | 0.0126
STOPNIE | PL30*300 | +12.800 | +12.830 | 2 | 98.9 | 9.5 | 30 | 1400 | bs1 | 0.942 | 0.009 | 0.0126
STOPNIE | PL30*300 | +12.650 | +12.680 | 2 | 98.9 | 9.5 | 30 | 1400 | bs1 | 0.942 | 0.009 | 0.0126
STOPNIE | PL30*300 | +12.500 | +12.530 | 2 | 98.9 | 9.5 | 30 | 1400 | bs1 | 0.942 | 0.009 | 0.0126
STOPNIE | PL30*300 | +12.350 | +12.380 | 2 | 98.9 | 9.5 | 30 | 1400 | bs1 | 0.942 | 0.009 | 0.0126
STOPNIE | PL30*300 | +12.200 | +12.230 | 2 | 98.9 | 9.5 | 30 | 1400 | bs1 | 0.942 | 0.009 | 0.0126
STOPNIE | PL30*300 | +12.050 | +12.080 | 2 | 98.9 | 9.5 | 30 | 1400 | bs1 | 0.942 | 0.009 | 0.0126
STOPNIE | PL30*300 | +11.900 | +11.930 | 2 | 98.9 | 9.5 | 30 | 1400 | bs1 | 0.942 | 0.009 | 0.0126
STOPNIE | PL30*300 | +11.750 | +11.780 | 2 | 98.9 | 9.5 | 30 | 1400 | bs1 | 0.942 | 0.009 | 0.0126
STOPNIE | PL30*300 | +11.600 | +11.630 | 2 | 98.9 | 9.5 | 30 | 1400 | bs1 | 0.942 | 0.009 | 0.0126
STOPNIE | PL30*300 | +11.450 | +11.480 | 2 | 98.9 | 9.5 | 30 | 1400 | bs1 | 0.942 | 0.009 | 0.0126
STOPNIE | PL30*300 | +11.300 | +11.330 | 2 | 98.9 | 9.5 | 30 | 1400 | bs1 | 0.942 | 0.009 | 0.0126
STOPNIE | PL30*300 | +11.150 | +11.180 | 2 | 98.9 | 9.5 | 30 | 1400 | bs1 | 0.942 | 0.009 | 0.0126
STOPNIE | PL30*300 | +11.000 | +11.030 | 2 | 98.9 | 9.5 | 30 | 1400 | bs1 | 0.942 | 0.009 | 0.0126
STOPNIE | PL30*300 | +10.850 | +10.880 | 2 | 98.9 | 9.5 | 30 | 1400 | bs1 | 0.942 | 0.009 | 0.0126
STOPNIE | PL30*300 | +10.700 | +10.730 | 2 | 98.9 | 9.5 | 30 | 1400 | bs1 | 0.942 | 0.009 | 0.0126
STOPNIE | PL30*300 | +10.550 | +10.580 | 2 | 98.9 | 9.5 | 30 | 1400 | bs1 | 0.942 | 0.009 | 0.0126
STOPNIE | PL30*300 | +10.400 | +10.430 | 2 | 98.9 | 9.5 | 30 | 1400 | bs1 | 0.942 | 0.009 | 0.0126
STOPNIE | PL30*300 | +10.250 | +10.280 | 2 | 98.9 | 9.5 | 30 | 1400 | bs1 | 0.942 | 0.009 | 0.0126
STOPNIE | PL30*300 | +10.100 | +10.130 | 2 | 98.9 | 9.5 | 30 | 1400 | bs1 | 0.942 | 0.009 | 0.0126
STOPNIE | PL30*300 | +9.950 | +9.980 | 2 | 98.9 | 9.5 | 30 | 1400 | bs1 | 0.942 | 0.009 | 0.0126
STOPNIE | PL30*300 | +9.800 | +9.830 | 2 | 98.9 | 9.5 | 30 | 1400 | bs1 | 0.942 | 0.009 | 0.0126
STOPNIE | PL30*300 | +9.650 | +9.680 | 2 | 98.9 | 9.5 | 30 | 1400 | bs1 | 0.942 | 0.009 | 0.0126
STOPNIE | PL30*300 | +9.500 | +9.530 | 2 | 98.9 | 9.5 | 30 | 1400 | bs1 | 0.942 | 0.009 | 0.0126
STOPNIE | PL30*300 | +9.350 | +9.380 | 2 | 98.9 | 9.5 | 30 | 1400 | bs1 | 0.942 | 0.009 | 0.0126
STOPNIE | PL30*300 | +9.200 | +9.230 | 2 | 98.9 | 9.5 | 30 | 1400 | bs1 | 0.942 | 0.009 | 0.0126
STOPNIE | PL30*300 | +9.050 | +9.080 | 2 | 98.9 | 9.5 | 30 | 1400 | bs1 | 0.942 | 0.009 | 0.0126
STOPNIE | PL30*300 | +8.900 | +8.930 | 2 | 98.9 | 9.5 | 30 | 1400 | bs1 | 0.942 | 0.009 | 0.0126
STOPNIE | PL30*300 | +8.750 | +8.780 | 2 | 98.9 | 9.5 | 30 | 1400 | bs1 | 0.942 | 0.009 | 0.0126
STOPNIE | PL30*300 | +8.600 | +8.630 | 2 | 98.9 | 9.5 | 30 | 1400 | bs1 | 0.942 | 0.009 | 0.0126
STOPNIE | PL30*300 | +8.450 | +8.480 | 2 | 98.9 | 9.5 | 30 | 1400 | bs1 | 0.942 | 0.009 | 0.0126
STOPNIE | PL30*300 | +8.300 | +8.330 | 2 | 98.9 | 9.5 | 30 | 1400 | bs1 | 0.942 | 0.009 | 0.0126
STOPNIE | PL30*300 | +8.150 | +8.180 | 2 | 98.9 | 9.5 | 30 | 1400 | bs1 | 0.942 | 0.009 | 0.0126
STOPNIE | PL30*300 | +8.000 | +8.030 | 2 | 98.9 | 9.5 | 30 | 1400 | bs1 | 0.942 | 0.009 | 0.0126
STOPNIE | PL30*300 | +7.850 | +7.880 | 2 | 98.9 | 9.5 | 30 | 1400 | bs1 | 0.942 | 0.009 | 0.0126
STOPNIE | PL30*300 | +7.700 | +7.730 | 2 | 98.9 | 9.5 | 30 | 1400 | bs1 | 0.942 | 0.009 | 0.0126
STOPNIE | PL30*300 | +7.550 | +7.580 | 2 | 98.9 | 9.5 | 30 | 1400 | bs1 | 0.942 | 0.009 | 0.0126
STOPNIE | PL30*300 | +7.400 | +7.430 | 2 | 98.9 | 9.5 | 30 | 1400 | bs1 | 0.942 | 0.009 | 0.0126
STOPNIE | PL30*300 | +7.250 | +7.280 | 2 | 98.9 | 9.5 | 30 | 1400 | bs1 | 0.942 | 0.009 | 0.0126
STOPNIE | PL30*300 | +7.100 | +7.130 | 2 | 98.9 | 9.5 | 30 | 1400 | bs1 | 0.942 | 0.009 | 0.0126
STOPNIE | PL30*300 | +6.950 | +6.980 | 2 | 98.9 | 9.5 | 30 | 1400 | bs1 | 0.942 | 0.009 | 0.0126
STOPNIE | PL30*300 | +6.800 | +6.830 | 2 | 98.9 | 9.5 | 30 | 1400 | bs1 | 0.942 | 0.009 | 0.0126
STOPNIE | PL30*300 | +6.650 | +6.680 | 2 | 98.9 | 9.5 | 30 | 1400 | bs1 | 0.942 | 0.009 | 0.0126
STOPNIE | PL30*300 | +6.500 | +6.530 | 2 | 98.9 | 9.5 | 30 | 1400 | bs1 | 0.942 | 0.009 | 0.0126
STOPNIE | PL30*300 | +6.350 | +6.380 | 2 | 98.9 | 9.5 | 30 | 1400 | bs1 | 0.942 | 0.009 | 0.0126
STOPNIE | PL30*300 | +6.200 | +6.230 | 2 | 98.9 | 9.5 | 30 | 1400 | bs1 | 0.942 | 0.009 | 0.0126
STOPNIE | PL30*300 | +6.050 | +6.080 | 2 | 98.9 | 9.5 | 30 | 1400 | bs1 | 0.942 | 0.009 | 0.0126
STOPNIE | PL30*300 | +5.900 | +5.930 | 2 | 98.9 | 9.5 | 30 | 1400 | bs1 | 0.942 | 0.009 | 0.0126
STOPNIE | PL30*300 | +5.750 | +5.780 | 2 | 98.9 | 9.5 | 30 | 1400 | bs1 | 0.942 | 0.009 | 0.0126
STOPNIE | PL30*300 | +5.600 | +5.630 | 2 | 98.9 | 9.5 | 30 | 1400 | bs1 | 0.942 | 0.009 | 0.0126
STOPNIE | PL30*300 | +5.450 | +5.480 | 2 | 98.9 | 9.5 | 30 | 1400 | bs1 | 0.942 | 0.009 | 0.0126
STOPNIE | PL30*300 | +5.300 | +5.330 | 2 | 98.9 | 9.5 | 30 | 1400 | bs1 | 0.942 | 0.009 | 0.0126
STOPNIE | PL30*300 | +5.150 | +5.180 | 2 | 98.9 | 9.5 | 30 | 1400 | bs1 | 0.942 | 0.009 | 0.0126
STOPNIE | PL30*300 | +5.000 | +5.030 | 2 | 98.9 | 9.5 | 30 | 1400 | bs1 | 0.942 | 0.009 | 0.0126
STOPNIE | PL30*300 | +4.850 | +4.880 | 2 | 98.9 | 9.5 | 30 | 1400 | bs1 | 0.942 | 0.009 | 0.0126
STOPNIE | PL30*300 | +4.700 | +4.730 | 2 | 98.9 | 9.5 | 30 | 1400 | bs1 | 0.942 | 0.009 | 0.0126
STOPNIE | PL30*300 | +4.550 | +4.580 | 2 | 98.9 | 9.5 | 30 | 1400 | bs1 | 0.942 | 0.009 | 0.0126
STOPNIE | PL30*300 | +4.400 | +4.430 | 2 | 98.9 | 9.5 | 30 | 1400 | bs1 | 0.942 | 0.009 | 0.0126
STOPNIE | PL30*300 | +4.250 | +4.280 | 2 | 98.9 | 9.5 | 30 | 1400 | bs1 | 0.942 | 0.009 | 0.0126
STOPNIE | PL30*300 | +4.100 | +4.130 | 2 | 98.9 | 9.5 | 30 | 1400 | bs1 | 0.942 | 0.009 | 0.0126
STOPNIE | PL30*300 | +3.950 | +3.980 | 2 | 98.9 | 9.5 | 30 | 1400 | bs1 | 0.942 | 0.009 | 0.0126
STOPNIE | PL30*300 | +3.800 | +3.830 | 2 | 98.9 | 9.5 | 30 | 1400 | bs1 | 0.942 | 0.009 | 0.0126
STOPNIE | PL30*300 | +3.650 | +3.680 | 2 | 98.9 | 9.5 | 30 | 1400 | bs1 | 0.942 | 0.009 | 0.0126
STOPNIE | PL30*300 | +3.500 | +3.530 | 2 | 98.9 | 9.5 | 30 | 1400 | bs1 | 0.942 | 0.009 | 0.0126
STOPNIE | PL30*300 | +3.350 | +3.380 | 2 | 98.9 | 9.5 | 30 | 1400 | bs1 | 0.942 | 0.009 | 0.0126
STOPNIE | PL30*300 | +3.200 | +3.230 | 2 | 98.9 | 9.5 | 30 | 1400 | bs1 | 0.942 | 0.009 | 0.0126
STOPNIE | PL30*300 | +3.050 | +3.080 | 2 | 98.9 | 9.5 | 30 | 1400 | bs1 | 0.942 | 0.009 | 0.0126

# IfcDiscreteAccessory: TURNBUCKLE (2)
In: Undefined
Description: PD20*5; Material: STEEL/S235
Tekla Common - Phase: 3; Class: 1
Tekla Quantity - Weight: 0.2 kg; Volume: 0 m3; Gross footprint area: 0 m2; Area per tons: 45.4 m2; Net surface area: 0 m2; Height: 20 mm; Width: 20 mm; Length: 170 mm
Pset_PlateCommon - LoadBearing: yes; Reference: p1
BaseQuantities - NetArea: 0.0099461 m2; GrossArea: 0.0108598 m2; CrossSectionArea: 0.000225 m2; GrossVolume: 0.00003825 m3
Name | Bottom elevation | Top elevation | NetVolume (m3)
TURNBUCKLE | +13.878 | +13.902 | 0.0000279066
TURNBUCKLE | +13.912 | +13.936 | 0.0000279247

# IfcElementAssembly (421)
In: Undefined
Name | PredefinedType | Assembly/Cast unit weight (kg) | Assembly/Cast unit bottom elevation | Assembly/Cast unit top elevation | Assembly/Cast unit position code | Assembly/Cast unit Mark | Width (mm)
Steel Assembly | RIGID_FRAME | 17.1 | +13.808 | +13.944 | 5-6>/D-C | Ws18 | 55
Steel Assembly | RIGID_FRAME | 10.1 | +13.858 | +13.973 | 5-6/D-C | Ws25 | 55
Steel Assembly | RIGID_FRAME | 19.1 | +12.876 | +13.968 | 5-6/D-C | Ws16 | 975.112
Steel Assembly | RIGID_FRAME | 18.5 | +12.871 | +13.947 | 5-6/D-C | Ws20 | 963.395
Steel Assembly | RIGID_FRAME | 15.4 | +13.925 | +14.026 | <1/D-B | B12 | 60.0044
Steel Assembly | RIGID_FRAME | 9.8 | +13.925 | +14.025 | <1/C-B | Ws7 | 60
Steel Assembly | RIGID_FRAME | 284.8 | +12.781 | +14.026 | <1/C-B | B9 | 2615.31
Steel Assembly | RIGID_FRAME | 3.2 | +13.946 | +14.065 | 6>/D-C | F15 | 20
Steel Assembly | RIGID_FRAME | 292.7 | +13.662 | +15.060 | 6>/C-B | F22 | 12355.9
Steel Assembly | RIGID_FRAME | 5.4 | +13.813 | +15.024 | 6/D-C | F3 | 50
Steel Assembly | RIGID_FRAME | 1767.5 | +12.506 | +13.941 | 5-6>/C-B | B4 | 1411.98
Steel Assembly | RIGID_FRAME | 127.8 | +12.785 | +13.917 | 6>/D-C | B10 | 2625
Steel Assembly | RIGID_FRAME | 3.2 | +13.946 | +14.047 | 6>/D-C | F7 | 20
Steel Assembly | RIGID_FRAME | 22.7 | +12.696 | +13.906 | 6/D-C | Ws24 | 1026.19
Steel Assembly | RIGID_FRAME | 18.5 | +12.812 | +13.889 | 6>/D-C | Ws20 | 963.395
Steel Assembly | RIGID_FRAME | 5.4 | +13.915 | +14.046 | 6>/D-C | F17 | 20
Steel Assembly | RIGID_FRAME | 18.5 | +12.851 | +13.927 | 5-6/D-C | Ws20 | 963.395
Steel Assembly | RIGID_FRAME | 6 | +13.910 | +13.980 | <1/C-B | Ws10 | 417.471
Steel Assembly | RIGID_FRAME | 610.4 | +12.777 | +13.980 | <1/D-B | xx25 | 4981.3
Steel Assembly | RIGID_FRAME | 29 | +14.026 | +14.030 | <1/D-C | A18 | 4
Steel Assembly | RIGID_FRAME | 62.4 | +14.026 | +14.030 | <1/C-B | A19 | 4
Steel Assembly | RIGID_FRAME | 62.4 | +14.025 | +14.030 | <1/C-B | A19 | 4
Steel Assembly | RIGID_FRAME | 0.2 | +13.774 | +13.777 | <1/D-C | A20 | 3
Steel Assembly | RIGID_FRAME | 20.8 | +12.882 | +13.782 | <1/C | B11 | 100
2 x Steel Assembly | RIGID_FRAME | 20.8 | +12.882 | +13.782 | <1/C-B | B11 | 100
Steel Assembly | RIGID_FRAME | 86.4 | +13.795 | +16.630 | 6>/C-B | D7 | 2834.81
Steel Assembly | RIGID_FRAME | 83 | +13.796 | +16.454 | 6>/C-B | D5 | 2657.81
Steel Assembly | RIGID_FRAME | 57.5 | +13.984 | +14.024 | 1-4/A | xx9 | 3331.65
2 x Steel Assembly | RIGID_FRAME | 5.1 | +13.555 | +13.570 | 6>/C-B | B8 | 15
Steel Assembly | RIGID_FRAME | 226.1 | +13.653 | +15.060 | 6>/C-B | F4 | 12742
Steel Assembly | RIGID_FRAME | 925.8 | +12.557 | +14.019 | 4-6/D-C | B1 | 1397.37
3 x Steel Assembly | RIGID_FRAME | 1.1 | +13.821 | +13.941 | 5-6/C-B | L2 | 5
Steel Assembly | RIGID_FRAME | 7.5 | +13.848 | +13.915 | 5-6/C-B | B3 | 60
Steel Assembly | RIGID_FRAME | 88.3 | +12.565 | +13.665 | 2-3/A> | 8 | 1100
Steel Assembly | RIGID_FRAME | 46.1 | +12.565 | +14.040 | 2-3/A> | F2 | 1475
Steel Assembly | RIGID_FRAME | 0.2 | +13.821 | +13.902 | 6>/C-B | F12 | 60
Steel Assembly | RIGID_FRAME | 0.8 | +13.811 | +13.911 | 6>/C-B | F13 | 77.0533
2 x Steel Assembly | RIGID_FRAME | 4 | +13.715 | +13.765 | 6>/C-B | K10 | 50
Steel Assembly | RIGID_FRAME | 4 | +13.715 | +13.765 | 6>/C-B | K3 | 50
Steel Assembly | RIGID_FRAME | 1.9 | +13.725 | +13.765 | 6>/C-B | D3 | 40
Steel Assembly | RIGID_FRAME | 5.4 | +13.715 | +13.765 | 6>/C-B | K6 | 50
Steel Assembly | RIGID_FRAME | 285.4 | -1.000 | +13.795 | 6>/C-B | zz4 | 17732
Steel Assembly | RIGID_FRAME | 2.2 | +13.715 | +13.765 | 6>/C-B | K1 | 50
Steel Assembly | RIGID_FRAME | 1.8 | +13.715 | +13.765 | 6>/C-B | K2 | 50
Steel Assembly | RIGID_FRAME | 6.1 | +13.715 | +13.765 | 6>/C-B | K4 | 50
Steel Assembly | RIGID_FRAME | 2.7 | +13.715 | +13.765 | 6>/C-B | K5 | 50
Steel Assembly | RIGID_FRAME | 4.6 | +13.715 | +13.765 | 6>/C-B | K9 | 50
Steel Assembly | RIGID_FRAME | 1.6 | +13.725 | +13.765 | 6>/C-B | D1 | 40
Steel Assembly | RIGID_FRAME | 0.8 | +13.715 | +13.765 | 6>/C-B | K15 | 50
Steel Assembly | RIGID_FRAME | 0.8 | +13.715 | +13.765 | 6>/C-B | K13 | 50
Steel Assembly | RIGID_FRAME | 4.8 | +13.715 | +13.765 | 6>/C-B | K14 | 50
Steel Assembly | RIGID_FRAME | 0.8 | +13.775 | +13.785 | 6>/C-B | A14 | 10
Steel Assembly | RIGID_FRAME | 0.8 | +13.765 | +13.775 | 6>/C-B | A14 | 10
Steel Assembly | RIGID_FRAME | 0.8 | +13.785 | +13.795 | 6>/C-B | A14 | 10
Steel Assembly | RIGID_FRAME | 1.8 | +13.715 | +13.765 | 6>/C-B | K8 | 50
Steel Assembly | RIGID_FRAME | 5.1 | +13.715 | +13.765 | 6>/C-B | K7 | 50
2 x Steel Assembly | RIGID_FRAME | 2.2 | +13.715 | +13.765 | 6>/C-B | K12 | 50
2 x Steel Assembly | RIGID_FRAME | 5.4 | +13.715 | +13.765 | 6>/C-B | K11 | 50
Steel Assembly | RIGID_FRAME | 1.2 | +13.565 | +13.765 | 6>/C-B | A13 | 10
Steel Assembly | RIGID_FRAME | 0.1 | +13.350 | +13.430 | <1/D-C | 5 | 50
Steel Assembly | RIGID_FRAME | 0.8 | +13.324 | +13.480 | <1/D-C | 2 | 156.266
Steel Assembly | RIGID_FRAME | 0 | +13.324 | +13.374 | <1/D-C | bl1 | 2
Steel Assembly | RIGID_FRAME | 0.5 | +13.324 | +13.374 | <1/D-C | 3 | 50
Steel Assembly | RIGID_FRAME | 0 | +13.430 | +13.480 | <1/D-C | bl1 | 2
Steel Assembly | RIGID_FRAME | 0.5 | +13.430 | +13.480 | <1/D-C | 4 | 50
Steel Assembly | RIGID_FRAME | 88.2 | +13.665 | +14.898 | 6>/C-B | F5 | 3618.47
Steel Assembly | RIGID_FRAME | 4.4 | +13.800 | +13.900 | 6>/C-B | F14 | 100.001
Steel Assembly | RIGID_FRAME | 8.3 | +13.812 | +13.961 | 6>/C-B | F10 | 20
Steel Assembly | RIGID_FRAME | 3.2 | +13.915 | +14.015 | 6>/D-C | F7 | 20
Steel Assembly | RIGID_FRAME | 0.2 | +13.874 | +13.955 | 6>/C-B | F18 | 60
Steel Assembly | RIGID_FRAME | 83.2 | +13.885 | +13.920 | 6>/D-C | KR16 | 25
Steel Assembly | RIGID_FRAME | 169.8 | +13.885 | +13.920 | 6>/D-C | KR15 | 25
Steel Assembly | RIGID_FRAME | 163.8 | +13.896 | +13.941 | 6>/D-C | KR14 | 25
Steel Assembly | RIGID_FRAME | 334.3 | +13.896 | +13.941 | 6>/D-C | KR13 | 25
Steel Assembly | RIGID_FRAME | 9 | +13.861 | +14.015 | 6>/C-B | F9 | 20
Steel Assembly | RIGID_FRAME | 8.3 | +13.865 | +14.014 | 6>/C-B | F8 | 20
Steel Assembly | RIGID_FRAME | 8.6 | +13.914 | +14.065 | 5-6>/C-B | F6 | 20
3 x Steel Assembly | RIGID_FRAME | 0.6 | +13.665 | +13.785 | 6>/C-B | F20 | 70
3 x Steel Assembly | RIGID_FRAME | 0.8 | +13.665 | +13.785 | 6>/C-B | F21 | 85
Steel Assembly | RIGID_FRAME | 4.6 | +13.800 | +13.900 | 6>/C-B | F19 | 20
Steel Assembly | RIGID_FRAME | 18.7 | +13.765 | +13.795 | 6>/C-B | zz12 | 30
2 x Steel Assembly | RIGID_FRAME | 0.8 | +14.729 | +14.732 | 6>/C-B | xx43 | 3
14 x Steel Assembly | RIGID_FRAME | 0.8 | +13.922 | +14.729 | 6>/C-B | xx42 | 3
2 x Steel Assembly | RIGID_FRAME | 0.8 | +13.919 | +13.922 | 6>/C-B | xx43 | 3
Steel Assembly | RIGID_FRAME | 8.3 | +14.850 | +14.900 | 6>/C-B | xx45 | 50
Steel Assembly | RIGID_FRAME | 4.8 | +13.765 | +14.850 | 6>/C-B | xx46 | 50
Steel Assembly | RIGID_FRAME | 4.6 | +13.795 | +14.850 | 6>/C-B | xx44 | 50
Steel Assembly | RIGID_FRAME | 4.8 | +13.795 | +14.900 | 6>/C-B | xx41 | 50
Steel Assembly | RIGID_FRAME | 9.2 | +13.795 | +13.808 | 6>/C-B | KR17 | 3
Steel Assembly | RIGID_FRAME | 8.6 | +14.035 | +14.048 | 4-5/D-C | KR12 | 3
Steel Assembly | RIGID_FRAME | 162.8 | +13.765 | +13.795 | 6>/C-B | KR18 | 30
Steel Assembly | RIGID_FRAME | 271.4 | +13.765 | +13.795 | 6>/C-B | KR19 | 30
2 x Steel Assembly | RIGID_FRAME | 253.1 | +13.765 | +13.795 | 6>/C-B | KR20 | 30
Steel Assembly | RIGID_FRAME | 135.8 | +13.765 | +13.795 | 6>/C-B | KR21 | 30
2 x Steel Assembly | RIGID_FRAME | 262.8 | +13.765 | +13.795 | 6>/C-B | KR22 | 30
Steel Assembly | RIGID_FRAME | 231.1 | +13.765 | +13.795 | 6>/C-B | zz13 | 30
Steel Assembly | RIGID_FRAME | 292 | +13.765 | +13.795 | 6>/C-B | zz19 | 30
2 x Steel Assembly | RIGID_FRAME | 5.4 | +16.292 | +16.532 | 6>/C-B | D4 | 60
Steel Assembly | RIGID_FRAME | 10 | +16.286 | +16.637 | 6>/C-B | D6 | 60
Steel Assembly | RIGID_FRAME | 10 | +16.286 | +16.637 | 6>/C-B | D8 | 60
2 x Steel Assembly | RIGID_FRAME | 10 | +16.286 | +16.637 | 6>/C-B | D2 | 60
Steel Assembly | RIGID_FRAME | 0.8 | +13.615 | +13.665 | 2/A> | xx36 | 50
Steel Assembly | RIGID_FRAME | 51.6 | +12.565 | +14.040 | 2/A> | F1 | 3028.81
Steel Assembly | RIGID_FRAME | 1.9 | +13.875 | +13.975 | 2-3/A | L6 | 16
Steel Assembly | RIGID_FRAME | 1.9 | +13.875 | +13.975 | 2/A | L6 | 16
Steel Assembly | RIGID_FRAME | 95 | +12.566 | +14.040 | 2-3/A> | A11 | 180
Steel Assembly | RIGID_FRAME | 95 | +12.565 | +14.040 | 2/A> | A10 | 180
Steel Assembly | RIGID_FRAME | 139.8 | +13.823 | +13.893 | 2-3/A> | SCH3 | 70
Steel Assembly | RIGID_FRAME | 139.8 | +13.676 | +13.746 | 2-3/A> | SCH3 | 70
Steel Assembly | RIGID_FRAME | 139.8 | +13.528 | +13.598 | 2-3/A> | SCH3 | 70
Steel Assembly | RIGID_FRAME | 139.8 | +13.381 | +13.451 | 2-3/A> | SCH3 | 70
Steel Assembly | RIGID_FRAME | 139.8 | +13.233 | +13.303 | 2-3/A> | SCH3 | 70
Steel Assembly | RIGID_FRAME | 139.8 | +13.086 | +13.156 | 2-3/A> | SCH3 | 70
Steel Assembly | RIGID_FRAME | 139.8 | +12.939 | +13.009 | 2-3/A> | SCH3 | 70
Steel Assembly | RIGID_FRAME | 139.8 | +12.791 | +12.861 | 2-3/A> | SCH3 | 70
Steel Assembly | RIGID_FRAME | 139.8 | +12.644 | +12.714 | 2-3/A> | SCH3 | 70
Steel Assembly | RIGID_FRAME | 60.9 | +12.781 | +14.025 | <1/C-B | Ws12 | 250
Steel Assembly | RIGID_FRAME | 51.6 | +12.781 | +13.989 | <1/D-C | Ws8 | 200
Steel Assembly | RIGID_FRAME | 10.4 | +13.909 | +13.989 | <1/D-C | Ws6 | 523.822
Steel Assembly | RIGID_FRAME | 51.6 | +12.782 | +13.989 | <1/D-C | Ws9 | 200.001
Steel Assembly | RIGID_FRAME | 60.6 | +12.781 | +14.025 | <1/C-B | Ws11 | 200
Steel Assembly | RIGID_FRAME | 46.6 | +12.416 | +14.030 | <1/D-C | 6 | 1614.34
Steel Assembly | RIGID_FRAME | 52.8 | +12.416 | +14.030 | <1/D-C | 7 | 1614.09
Steel Assembly | RIGID_FRAME | 31.7 | +12.350 | +13.480 | <1/D-C | 1 | 1130
Steel Assembly | RIGID_FRAME | 99.5 | +13.810 | +13.880 | <1/D-C | q2 | 70
Steel Assembly | RIGID_FRAME | 99.5 | +13.660 | +13.730 | <1/D-C | q2 | 70
Steel Assembly | RIGID_FRAME | 99.5 | +13.510 | +13.580 | <1/D-C | q2 | 70
Steel Assembly | RIGID_FRAME | 99.5 | +13.360 | +13.430 | <1/D-C | q2 | 70
Steel Assembly | RIGID_FRAME | 99.5 | +13.210 | +13.280 | <1/D-C | q2 | 70
Steel Assembly | RIGID_FRAME | 99.5 | +13.060 | +13.130 | <1/D-C | q2 | 70
Steel Assembly | RIGID_FRAME | 99.5 | +12.910 | +12.980 | <1/D-C | q2 | 70
Steel Assembly | RIGID_FRAME | 99.5 | +12.760 | +12.830 | <1/D-C | q2 | 70
Steel Assembly | RIGID_FRAME | 99.5 | +12.610 | +12.680 | <1/D-C | q2 | 70
Steel Assembly | RIGID_FRAME | 99.5 | +12.460 | +12.530 | <1/D-C | q2 | 70
Steel Assembly | RIGID_FRAME | 99.5 | +12.310 | +12.380 | <1/D-C | q2 | 70
Steel Assembly | RIGID_FRAME | 151.5 | +12.150 | +14.000 | <1/D-C | A7 | 75
Steel Assembly | RIGID_FRAME | 151.5 | +12.150 | +14.000 | <1/D-C | A4 | 75
Steel Assembly | RIGID_FRAME | 99.5 | +12.160 | +12.230 | <1/D-C | q2 | 70
Steel Assembly | RIGID_FRAME | 99.5 | +12.010 | +12.080 | <1/D-C | q2 | 70
Steel Assembly | RIGID_FRAME | 99.5 | +11.860 | +11.930 | <1/D-C | q2 | 70
Steel Assembly | RIGID_FRAME | 99.5 | +11.710 | +11.780 | <1/D-C | q2 | 70
Steel Assembly | RIGID_FRAME | 99.5 | +11.560 | +11.630 | <1/D-C | q2 | 70
Steel Assembly | RIGID_FRAME | 99.5 | +11.410 | +11.480 | <1/D-C | q2 | 70
Steel Assembly | RIGID_FRAME | 99.5 | +11.260 | +11.330 | <1/D-C | q2 | 70
Steel Assembly | RIGID_FRAME | 99.5 | +11.110 | +11.180 | <1/D-C | q2 | 70
Steel Assembly | RIGID_FRAME | 99.5 | +10.960 | +11.030 | <1/D-C | q2 | 70
Steel Assembly | RIGID_FRAME | 99.5 | +10.810 | +10.880 | <1/D-C | q2 | 70
Steel Assembly | RIGID_FRAME | 99.5 | +10.660 | +10.730 | <1/D-C | q2 | 70
Steel Assembly | RIGID_FRAME | 181 | +10.500 | +12.350 | <1/D-C | A2 | 75
Steel Assembly | RIGID_FRAME | 181 | +10.500 | +12.350 | <1/D-C | A5 | 75
Steel Assembly | RIGID_FRAME | 99.5 | +10.510 | +10.580 | <1/D-C | q2 | 70
Steel Assembly | RIGID_FRAME | 99.5 | +10.360 | +10.430 | <1/D-C | q2 | 70
Steel Assembly | RIGID_FRAME | 99.5 | +10.210 | +10.280 | <1/D-C | q2 | 70
Steel Assembly | RIGID_FRAME | 99.5 | +10.060 | +10.130 | <1/D-C | q2 | 70
Steel Assembly | RIGID_FRAME | 99.5 | +9.910 | +9.980 | <1/D-C | q2 | 70
Steel Assembly | RIGID_FRAME | 99.5 | +9.760 | +9.830 | <1/D-C | q2 | 70
Steel Assembly | RIGID_FRAME | 99.5 | +9.610 | +9.680 | <1/D-C | q2 | 70
Steel Assembly | RIGID_FRAME | 99.5 | +9.460 | +9.530 | <1/D-C | q2 | 70
Steel Assembly | RIGID_FRAME | 99.5 | +9.310 | +9.380 | <1/D-C | q2 | 70
Steel Assembly | RIGID_FRAME | 99.5 | +9.160 | +9.230 | <1/D-C | q2 | 70
Steel Assembly | RIGID_FRAME | 99.5 | +9.010 | +9.080 | <1/D-C | q2 | 70
Steel Assembly | RIGID_FRAME | 181 | +8.850 | +10.700 | <1/D-C | A6 | 75
Steel Assembly | RIGID_FRAME | 181 | +8.850 | +10.700 | <1/D-C | A3 | 75
Steel Assembly | RIGID_FRAME | 99.5 | +8.860 | +8.930 | <1/D-C | q2 | 70
Steel Assembly | RIGID_FRAME | 99.5 | +8.710 | +8.780 | <1/D-C | q2 | 70
Steel Assembly | RIGID_FRAME | 99.5 | +8.560 | +8.630 | <1/D-C | q2 | 70
Steel Assembly | RIGID_FRAME | 99.5 | +8.410 | +8.480 | <1/D-C | q2 | 70
Steel Assembly | RIGID_FRAME | 99.5 | +8.260 | +8.330 | <1/D-C | q2 | 70
Steel Assembly | RIGID_FRAME | 99.5 | +8.110 | +8.180 | <1/D-C | q2 | 70
Steel Assembly | RIGID_FRAME | 99.5 | +7.960 | +8.030 | <1/D-C | q2 | 70
Steel Assembly | RIGID_FRAME | 99.5 | +7.810 | +7.880 | <1/D-C | q2 | 70
Steel Assembly | RIGID_FRAME | 99.5 | +7.660 | +7.730 | <1/D-C | q2 | 70
Steel Assembly | RIGID_FRAME | 99.5 | +7.510 | +7.580 | <1/D-C | q2 | 70
Steel Assembly | RIGID_FRAME | 99.5 | +7.360 | +7.430 | <1/D-C | q2 | 70
Steel Assembly | RIGID_FRAME | 181 | +7.200 | +9.050 | <1/D-C | A2 | 75
Steel Assembly | RIGID_FRAME | 181 | +7.200 | +9.050 | <1/D-C | A5 | 75
Steel Assembly | RIGID_FRAME | 99.5 | +7.210 | +7.280 | <1/D-C | q2 | 70
Steel Assembly | RIGID_FRAME | 99.5 | +7.060 | +7.130 | <1/D-C | q2 | 70
Steel Assembly | RIGID_FRAME | 99.5 | +6.910 | +6.980 | <1/D-C | q2 | 70
Steel Assembly | RIGID_FRAME | 99.5 | +6.760 | +6.830 | <1/D-C | q2 | 70
Steel Assembly | RIGID_FRAME | 99.5 | +6.610 | +6.680 | <1/D-C | q2 | 70
Steel Assembly | RIGID_FRAME | 99.5 | +6.460 | +6.530 | <1/D-C | q2 | 70
Steel Assembly | RIGID_FRAME | 99.5 | +6.310 | +6.380 | <1/D-C | q2 | 70
Steel Assembly | RIGID_FRAME | 99.5 | +6.160 | +6.230 | <1/D-C | q2 | 70
Steel Assembly | RIGID_FRAME | 99.5 | +6.010 | +6.080 | <1/D-C | q2 | 70
Steel Assembly | RIGID_FRAME | 99.5 | +5.860 | +5.930 | <1/D-C | q2 | 70
Steel Assembly | RIGID_FRAME | 99.5 | +5.710 | +5.780 | <1/D-C | q2 | 70
Steel Assembly | RIGID_FRAME | 181 | +5.550 | +7.400 | <1/D-C | A6 | 75
Steel Assembly | RIGID_FRAME | 181 | +5.550 | +7.400 | <1/D-C | A3 | 75
Steel Assembly | RIGID_FRAME | 99.5 | +5.560 | +5.630 | <1/D-C | q2 | 70
Steel Assembly | RIGID_FRAME | 99.5 | +5.410 | +5.480 | <1/D-C | q2 | 70
Steel Assembly | RIGID_FRAME | 99.5 | +5.260 | +5.330 | <1/D-C | q2 | 70
Steel Assembly | RIGID_FRAME | 99.5 | +5.110 | +5.180 | <1/D-C | q2 | 70
Steel Assembly | RIGID_FRAME | 99.5 | +4.960 | +5.030 | <1/D-C | q2 | 70
Steel Assembly | RIGID_FRAME | 99.5 | +4.810 | +4.880 | <1/D-C | q2 | 70
Steel Assembly | RIGID_FRAME | 99.5 | +4.660 | +4.730 | <1/D-C | q2 | 70
Steel Assembly | RIGID_FRAME | 99.5 | +4.510 | +4.580 | <1/D-C | q2 | 70
Steel Assembly | RIGID_FRAME | 99.5 | +4.360 | +4.430 | <1/D-C | q2 | 70
Steel Assembly | RIGID_FRAME | 99.5 | +4.210 | +4.280 | <1/D-C | q2 | 70
Steel Assembly | RIGID_FRAME | 99.5 | +4.060 | +4.130 | <1/D-C | q2 | 70
Steel Assembly | RIGID_FRAME | 181 | +3.900 | +5.750 | <1/D-C | A2 | 75
Steel Assembly | RIGID_FRAME | 181 | +3.900 | +5.750 | <1/D-C | A5 | 75
Steel Assembly | RIGID_FRAME | 99.5 | +3.910 | +3.980 | <1/D-C | q2 | 70
Steel Assembly | RIGID_FRAME | 99.5 | +3.760 | +3.830 | <1/D-C | q2 | 70
Steel Assembly | RIGID_FRAME | 99.5 | +3.610 | +3.680 | <1/D-C | q2 | 70
Steel Assembly | RIGID_FRAME | 99.5 | +3.460 | +3.530 | <1/D-C | q2 | 70
Steel Assembly | RIGID_FRAME | 99.5 | +3.310 | +3.380 | <1/D-C | q2 | 70
Steel Assembly | RIGID_FRAME | 99.5 | +3.160 | +3.230 | <1/D-C | q2 | 70
Steel Assembly | RIGID_FRAME | 99.5 | +3.010 | +3.080 | <1/D-C | q2 | 70
Steel Assembly | RIGID_FRAME | 177.8 | +2.780 | +4.100 | <1/D-C | A9 | 75
Steel Assembly | RIGID_FRAME | 177.8 | +2.780 | +4.100 | <1/D-C | A8 | 75
Steel Assembly | RIGID_FRAME | 1676.4 | +1.020 | +12.160 | <1/D-C | xx31 | 5510
Steel Assembly | RIGID_FRAME | 1676.4 | +1.020 | +12.160 | <1/D-C | xx23 | 5510
Steel Assembly | RIGID_FRAME | 177.8 | +12.140 | +13.800 | <1/D-C | xx20 | 120
Steel Assembly | RIGID_FRAME | 52.3 | +10.700 | +12.100 | <1/D-C | xx27 | 60
Steel Assembly | RIGID_FRAME | 52.3 | +7.400 | +8.800 | <1/D-C | xx27 | 60
Steel Assembly | RIGID_FRAME | 52.3 | +4.100 | +5.500 | <1/D-C | xx27 | 60
Steel Assembly | RIGID_FRAME | 113.5 | +8.811 | +10.700 | <1/D-C | xx30 | 80
Steel Assembly | RIGID_FRAME | 113.9 | +5.500 | +7.400 | <1/D-C | xx29 | 80
Steel Assembly | RIGID_FRAME | 116.2 | +1.960 | +4.100 | <1/D-C | xx28 | 80
2 x Steel Assembly | RIGID_FRAME | 18.5 | +2.780 | +5.400 | <1/D-C | xx17 | 60
2 x Steel Assembly | RIGID_FRAME | 22.2 | +8.840 | +12.000 | <1/D-C | xx18 | 60
2 x Steel Assembly | RIGID_FRAME | 22.2 | +5.540 | +8.700 | <1/D-C | xx18 | 60
Steel Assembly | RIGID_FRAME | 247.3 | +14.000 | +14.030 | <1/D-C | q4 | 30
Steel Assembly | RIGID_FRAME | 1077.4 | +12.350 | +12.380 | <1/D-C | q1 | 30
Steel Assembly | RIGID_FRAME | 1077.4 | +9.050 | +9.080 | <1/D-C | q1 | 30
Steel Assembly | RIGID_FRAME | 1077.4 | +5.750 | +5.780 | <1/D-C | q1 | 30
Steel Assembly | RIGID_FRAME | 1346.8 | +10.700 | +10.730 | <1/D-C | q5 | 30
Steel Assembly | RIGID_FRAME | 1346.8 | +7.400 | +7.430 | <1/D-C | q5 | 30
Steel Assembly | RIGID_FRAME | 80.9 | +12.150 | +12.350 | <1/D-C | xx10 | 75
Steel Assembly | RIGID_FRAME | 80.9 | +8.850 | +9.050 | <1/D-C | xx10 | 75
Steel Assembly | RIGID_FRAME | 889.9 | +2.850 | +2.930 | <1/D-C | q3 | 30
Steel Assembly | RIGID_FRAME | 1346.8 | +4.100 | +4.130 | <1/D-C | q5 | 30
Steel Assembly | RIGID_FRAME | 80.9 | +5.550 | +5.750 | <1/D-C | xx10 | 75
2 x COLUMN | REINFORCEMENT_UNIT | 360 | +2.180 | +2.780 | <1/D-C | xx12 | 500 | Tekla Assembly - Cast unit type: Wylewany na miejscu; Cast unit rebar weight: 0 kg
4 x COLUMN | REINFORCEMENT_UNIT | 556.8 | -0.430 | +1.020 | <1/D-C | xx16 | 400 | Tekla Assembly - Cast unit type: Wylewany na miejscu; Cast unit rebar weight: 0 kg
Steel Assembly | RIGID_FRAME | 140.7 | +11.990 | +12.150 | <1/D-C | xx13 | 160
Steel Assembly | RIGID_FRAME | 140.7 | +8.690 | +8.850 | <1/D-C | xx13 | 160
Steel Assembly | RIGID_FRAME | 140.7 | +5.390 | +5.550 | <1/D-C | xx13 | 160
Steel Assembly | RIGID_FRAME | 111.4 | +2.640 | +2.780 | <1/D-C | xx15 | 140
Steel Assembly | RIGID_FRAME | 23.2 | +1.880 | +1.940 | <1/D-C | xx26 | 60
Steel Assembly | RIGID_FRAME | 10.8 | +13.800 | +13.965 | 6>/C-B | F11 | 20
Steel Assembly | RIGID_FRAME | 10 | +13.651 | +13.950 | 5-6/C-B | Ws17 | 192.141
Steel Assembly | RIGID_FRAME | 22.7 | +12.696 | +13.907 | 5-6/C-B | Ws23 | 1026.06
Steel Assembly | RIGID_FRAME | 22.2 | +13.805 | +13.955 | 5-6/C-B | Ws21 | 50
Steel Assembly | RIGID_FRAME | 18.5 | +12.851 | +13.927 | 5-6/C-B | Ws19 | 962.974
Steel Assembly | RIGID_FRAME | 18.5 | +12.810 | +13.886 | 6>/C-B | Ws19 | 962.974
Steel Assembly | RIGID_FRAME | 18.5 | +12.871 | +13.947 | 5-6/C-B | Ws19 | 962.974
Steel Assembly | RIGID_FRAME | 11.9 | +13.911 | +13.982 | 1-2/A> | Ws13 | 40
Steel Assembly | RIGID_FRAME | 243.4 | +12.780 | +13.981 | 1-4/A | xx7 | 5349.08
Steel Assembly | RIGID_FRAME | 10.1 | +13.910 | +13.980 | 2-3/A> | Ws15 | 40
Steel Assembly | RIGID_FRAME | 55.1 | +12.782 | +13.990 | 1-2/A> | Ws1 | 250.001
Steel Assembly | RIGID_FRAME | 54.4 | +12.781 | +13.990 | 2-3/A> | Ws3 | 250
Steel Assembly | RIGID_FRAME | 2.3 | +13.857 | +13.950 | 1-2/A> | St1 | 50
Steel Assembly | RIGID_FRAME | 0.1 | +13.839 | +13.886 | 1-2/B-A | xx34 | 6
Steel Assembly | RIGID_FRAME | 0 | +13.840 | +13.886 | 1-2/B-A | xx33 | 5
Steel Assembly | RIGID_FRAME | 0.1 | +13.837 | +13.884 | 1-2/B-A | xx32 | 5
Steel Assembly | RIGID_FRAME | 2.3 | +13.864 | +13.957 | 1-2/A | St2 | 50
Steel Assembly | RIGID_FRAME | 0.1 | +13.928 | +13.975 | 1-2/A | xx34 | 6
Steel Assembly | RIGID_FRAME | 0 | +13.928 | +13.974 | 1-2/A | xx33 | 5
Steel Assembly | RIGID_FRAME | 0.1 | +13.930 | +13.977 | 1-2/A | xx32 | 5
Steel Assembly | RIGID_FRAME | 11.4 | +13.910 | +13.990 | 1-2/A> | Ws2 | 695.613
Steel Assembly | RIGID_FRAME | 54.1 | +12.781 | +13.990 | 2/A> | Ws14 | 200.001
Steel Assembly | RIGID_FRAME | 7.2 | +13.910 | +13.990 | 2-3/A> | Ws5 | 50
Steel Assembly | RIGID_FRAME | 54.1 | +12.781 | +13.990 | 2-3/A> | Ws4 | 200
Steel Assembly | RIGID_FRAME | 187.3 | +13.780 | +13.880 | 1-4/A | xx8 | 3348.97
CONCRETE_SLAB | REINFORCEMENT_UNIT | 661.7 | +12.545 | +12.565 | 2-3/A> | P2 | 20 | Tekla Assembly - Cast unit type: Wylewany na miejscu; Cast unit rebar weight: 0 kg
Steel Assembly | RIGID_FRAME | 5.4 | +13.780 | +13.975 | 2-3/A | L5 | 16
Steel Assembly | RIGID_FRAME | 5.4 | +13.780 | +13.975 | 2/A | L5 | 16
Steel Assembly | RIGID_FRAME | 0.8 | +13.880 | +13.984 | 2-3/A | xx6 | 40
Steel Assembly | RIGID_FRAME | 246.3 | +14.000 | +14.040 | 2-3/A> | SCH1 | 40
CONCRETE_SLAB | REINFORCEMENT_UNIT | 6616.8 | +12.345 | +12.545 | 2-3/A> | P1 | 200 | Tekla Assembly - Cast unit type: Wylewany na miejscu; Cast unit rebar weight: 0 kg
Steel Assembly | RIGID_FRAME | 8.3 | +13.400 | +13.540 | 6>/B | zz2 | 140
Steel Assembly | RIGID_FRAME | 167.4 | +13.400 | +13.540 | 6>/C-B | zz8 | 140
Steel Assembly | RIGID_FRAME | 210.5 | +13.400 | +13.540 | 6>/C-B | zz5 | 5596.42
3 x Steel Assembly | RIGID_FRAME | 184.6 | +8.070 | +13.540 | 6>/C-B | zz1 | 140
Steel Assembly | RIGID_FRAME | 62.3 | +13.400 | +13.540 | 6>/B | zz10 | 1066.75
Steel Assembly | RIGID_FRAME | 8.6 | +13.565 | +13.765 | 6>/C-B | zz7 | 75
Steel Assembly | RIGID_FRAME | 8.6 | +13.565 | +13.765 | 6>/C-B | zz11 | 75
Steel Assembly | RIGID_FRAME | 63.1 | +13.400 | +13.540 | 6>/C-B | zz3 | 311.368
Steel Assembly | RIGID_FRAME | 8.3 | +13.400 | +13.540 | 6>/C-B | zz2 | 140
Steel Assembly | RIGID_FRAME | 94.7 | +13.400 | +13.540 | 6>/B | zz9 | 140
2 x Steel Assembly | RIGID_FRAME | 184.6 | +8.070 | +13.540 | 6>/B | zz1 | 140
Steel Assembly | RIGID_FRAME | 21.6 | +13.400 | +13.540 | 6>/B | zz6 | 320.001
Steel Assembly | RIGID_FRAME | 129.8 | +13.400 | +13.540 | 6>/C-B | tt1 | 140
Steel Assembly | RIGID_FRAME | 1.1 | +12.502 | +12.612 | 6>/D-C | L1 | 5
Steel Assembly | RIGID_FRAME | 1.1 | +12.502 | +12.612 | 6/C-B | L1 | 5
Steel Assembly | RIGID_FRAME | 1.1 | +12.553 | +12.661 | 5-6/D-C | L1 | 5
Steel Assembly | RIGID_FRAME | 1.1 | +12.553 | +12.661 | 5-6/C-B | L1 | 5
Steel Assembly | RIGID_FRAME | 1.1 | +13.596 | +13.744 | 5-6/C-B | L1 | 5
Steel Assembly | RIGID_FRAME | 1.1 | +13.596 | +13.744 | 5-6/D-C | L1 | 5
3 x Steel Assembly | RIGID_FRAME | 1.1 | +13.821 | +13.941 | 5-6/D-C | L2 | 5
Steel Assembly | RIGID_FRAME | 1.1 | +13.599 | +13.746 | 5-6/C-B | L1 | 5
Steel Assembly | RIGID_FRAME | 1.1 | +13.601 | +13.749 | 5-6/C-B | L1 | 5
Steel Assembly | RIGID_FRAME | 1.1 | +13.599 | +13.746 | 5-6/D-C | L1 | 5
Steel Assembly | RIGID_FRAME | 1.1 | +13.601 | +13.749 | 5-6/D-C | L1 | 5
Steel Assembly | RIGID_FRAME | 23.8 | +11.059 | +12.599 | 5-6/C-B | B5 | 170
Steel Assembly | RIGID_FRAME | 1.1 | +12.498 | +12.608 | 6/C-B | L1 | 5
Steel Assembly | RIGID_FRAME | 1.1 | +12.494 | +12.604 | 6/C-B | L1 | 5
Steel Assembly | RIGID_FRAME | 23.8 | +11.059 | +12.599 | 6>/D-C | B5 | 170
Steel Assembly | RIGID_FRAME | 1.1 | +12.498 | +12.608 | 6>/D-C | L1 | 5
Steel Assembly | RIGID_FRAME | 1.1 | +12.494 | +12.604 | 6>/D-C | L1 | 5
Steel Assembly | RIGID_FRAME | 1.1 | +12.549 | +12.657 | 5-6/D-C | L1 | 5
Steel Assembly | RIGID_FRAME | 1.1 | +12.545 | +12.653 | 5-6/D-C | L1 | 5
Steel Assembly | RIGID_FRAME | 1.1 | +12.549 | +12.657 | 5-6/C-B | L1 | 5
Steel Assembly | RIGID_FRAME | 1.1 | +12.545 | +12.653 | 5-6/C-B | L1 | 5
Steel Assembly | RIGID_FRAME | 11 | +13.605 | +13.715 | 5-6/C-B | S1 | 180.002
Steel Assembly | RIGID_FRAME | 1.2 | +13.715 | +13.720 | 5-6/C-B | L4 | 5
Steel Assembly | RIGID_FRAME | 1.2 | +13.720 | +13.725 | 5-6/C-B | L4 | 5
Steel Assembly | RIGID_FRAME | 1059.8 | +5.260 | +13.605 | 6/D-C | X2 | 8344.99
Steel Assembly | RIGID_FRAME | 1.2 | +13.715 | +13.720 | 6/D-C | L4 | 5
Steel Assembly | RIGID_FRAME | 1.2 | +13.720 | +13.725 | 6/D-C | L4 | 5
Steel Assembly | RIGID_FRAME | 11 | +13.605 | +13.715 | 6/D-C | S1 | 180.002
3 x Steel Assembly | RIGID_FRAME | 1.8 | +12.740 | +13.010 | 5-6/C-B | L3 | 5
3 x Steel Assembly | RIGID_FRAME | 1.8 | +12.740 | +13.010 | 6/D-C | L3 | 5
2 x Steel Assembly | RIGID_FRAME | 1.8 | +13.540 | +13.545 | 6>/C-B | B7 | 5
2 x Steel Assembly | RIGID_FRAME | 1.8 | +13.550 | +13.555 | 6>/C-B | B7 | 5
2 x Steel Assembly | RIGID_FRAME | 1.8 | +13.545 | +13.550 | 6>/C-B | B7 | 5
Steel Assembly | RIGID_FRAME | 24.2 | +11.063 | +12.648 | 5-6/C-B | B2 | 170
Steel Assembly | RIGID_FRAME | 7.5 | +13.848 | +13.915 | 5-6/D-C | B3 | 60
BEAM | REINFORCEMENT_UNIT | 238.1 | +3.670 | +4.480 | 5/C | Z1 | 350 | Tekla Assembly - Cast unit type: Wylewany na miejscu; Cast unit rebar weight: 0 kg
BEAM | REINFORCEMENT_UNIT | 238.1 | +3.670 | +4.480 | 6/C | Z1 | 350 | Tekla Assembly - Cast unit type: Wylewany na miejscu; Cast unit rebar weight: 0 kg
BEAM | REINFORCEMENT_UNIT | 238.1 | +3.670 | +4.480 | 6/B | Z1 | 350 | Tekla Assembly - Cast unit type: Wylewany na miejscu; Cast unit rebar weight: 0 kg
BEAM | REINFORCEMENT_UNIT | 238.1 | +3.670 | +4.480 | 6/D | Z1 | 350 | Tekla Assembly - Cast unit type: Wylewany na miejscu; Cast unit rebar weight: 0 kg
BEAM | REINFORCEMENT_UNIT | 3281.2 | +4.480 | +5.280 | 5-6/C-B | Z4 | 350 | Tekla Assembly - Cast unit type: Wylewany na miejscu; Cast unit rebar weight: 0 kg
BEAM | REINFORCEMENT_UNIT | 3339 | +5.080 | +5.280 | 5-6/D-C | Z3 | 1500 | Tekla Assembly - Cast unit type: Wylewany na miejscu; Cast unit rebar weight: 0 kg
BEAM | REINFORCEMENT_UNIT | 3628.8 | +4.480 | +5.280 | 5-6/C | Z2 | 350 | Tekla Assembly - Cast unit type: Wylewany na miejscu; Cast unit rebar weight: 0 kg
BEAM | REINFORCEMENT_UNIT | 8295.2 | +4.480 | +5.280 | 6/D-B | Z5 | 350 | Tekla Assembly - Cast unit type: Wylewany na miejscu; Cast unit rebar weight: 0 kg
Steel Assembly | RIGID_FRAME | 311.7 | +13.998 | +14.044 | 4-5/D-C | KR1 | 25
Steel Assembly | RIGID_FRAME | 258.9 | +13.998 | +14.040 | 4-5/D-C | KR2 | 25
Steel Assembly | RIGID_FRAME | 101.8 | +13.998 | +14.037 | 4-5/D-C | KR3 | 25
2 x Steel Assembly | RIGID_FRAME | 325.9 | +13.977 | +14.022 | 5-6/D-C | KR5 | 25
Steel Assembly | RIGID_FRAME | 84.1 | +13.977 | +14.022 | 5-6/C | KR4 | 25
Steel Assembly | RIGID_FRAME | 325.9 | +13.936 | +13.982 | 5-6/D-C | KR5 | 25
Steel Assembly | RIGID_FRAME | 325.9 | +13.936 | +13.982 | 5-6/C-B | KR5 | 25
Steel Assembly | RIGID_FRAME | 81.5 | +13.936 | +13.982 | 5-6/C-B | KR6 | 25
Steel Assembly | RIGID_FRAME | 325.9 | +13.957 | +14.002 | 5-6/D-C | KR5 | 25
Steel Assembly | RIGID_FRAME | 325.9 | +13.957 | +14.002 | 5-6/D-B | KR5 | 25
Steel Assembly | RIGID_FRAME | 81.9 | +13.916 | +13.961 | 5-6>/C-B | KR7 | 25
Steel Assembly | RIGID_FRAME | 327.6 | +13.916 | +13.961 | 5-6>/C-B | KR8 | 25
Steel Assembly | RIGID_FRAME | 327.6 | +13.916 | +13.961 | 5-6>/D-C | KR8 | 25
Steel Assembly | RIGID_FRAME | 81.9 | +13.896 | +13.941 | 6>/C-B | KR7 | 25
Steel Assembly | RIGID_FRAME | 327.6 | +13.896 | +13.941 | 6>/C-B | KR8 | 25
Steel Assembly | RIGID_FRAME | 327.6 | +13.896 | +13.941 | 6>/D-B | KR8 | 25
Steel Assembly | RIGID_FRAME | 81.9 | +13.875 | +13.920 | 6>/C-B | KR7 | 25
2 x Steel Assembly | RIGID_FRAME | 327.6 | +13.875 | +13.920 | 6>/C-B | KR8 | 25
Steel Assembly | RIGID_FRAME | 81.9 | +13.855 | +13.900 | 6>/C-B | KR7 | 25
2 x Steel Assembly | RIGID_FRAME | 327.6 | +13.855 | +13.900 | 6>/C-B | KR8 | 25
Steel Assembly | RIGID_FRAME | 81.9 | +13.793 | +13.839 | 6>/C-B | KR7 | 25
2 x Steel Assembly | RIGID_FRAME | 327.6 | +13.793 | +13.839 | 6>/C-B | KR8 | 25
Steel Assembly | RIGID_FRAME | 81.9 | +13.834 | +13.880 | 6>/C-B | KR7 | 25
2 x Steel Assembly | RIGID_FRAME | 327.6 | +13.834 | +13.880 | 6>/C-B | KR8 | 25
Steel Assembly | RIGID_FRAME | 239.6 | +12.776 | +13.818 | 6>/C-B | B6 | 2310
3 x Steel Assembly | RIGID_FRAME | 1.8 | +12.743 | +13.013 | 5-6/C-B | L3 | 5
3 x Steel Assembly | RIGID_FRAME | 1.8 | +12.743 | +13.013 | 6/D-C | L3 | 5
Steel Assembly | RIGID_FRAME | 24.2 | +11.063 | +12.648 | 5-6/D-C | B2 | 170
Steel Assembly | RIGID_FRAME | 82.7 | +13.772 | +13.818 | 6>/C-B | KR11 | 25
Steel Assembly | RIGID_FRAME | 81.5 | +13.957 | +14.002 | 5-6/C-B | KR6 | 25
Steel Assembly | RIGID_FRAME | 81.9 | +13.814 | +13.859 | 6>/C-B | KR7 | 25
Steel Assembly | RIGID_FRAME | 297 | +13.773 | +13.818 | 6>/C-B | KR10 | 25
Steel Assembly | RIGID_FRAME | 242.8 | +13.776 | +13.818 | 6>/C-B | KR9 | 25
2 x Steel Assembly | RIGID_FRAME | 327.6 | +13.814 | +13.859 | 6>/C-B | KR8 | 25

# IfcMechanicalFastener: Bolt assembly (597)
In: Undefined
Material: Undefined
Tekla Bolt - Location: Budowa
Name | NominalDiameter (mm) = Washer diameter (mm) | NominalLength (mm) | Washer count | Washer type | Washer name | Nut count | Nut type | Nut name | Slotted hole y (mm) | Slotted hole x (mm) | Bolt hole diameter (mm) | Bolt count | Bolt size (mm) | Bolt length (mm) | Bolt standard | Bolt Name
2 x Bolt assembly | 12 | 40 | 4 | 125A | PODKLADKA-12-125A | 2 | 934 | NAKRETKA-M12-934 | 0 | 0 | 15 | 2 | 12 | 40 | 931 | SRUBA
21 x Bolt assembly | 12 | 45 | 4 | 7089 | PODKLADKA-12-7089 | 2 | 4032 | NAKRETKA-M12-4032 | 15 | 0 | 15 | 2 | 12 | 45 | 4014 | SRUBA
33 x Bolt assembly | 12 | 90 | 4 | 7093 | PODKLADKA-12-7093 | 2 | 4032 | NAKRETKA-M12-4032 | 0 | 0 | 18 | 2 | 12 | 90 | 4014 | SRUBA
42 x Bolt assembly | 10 | 75 | 2 | 7089 | PODKLADKA-10-7089 | 1 | 4032 | NAKRETKA-M10-4032 | 0 | 0 | 13 | 1 | 10 | 75 | 4014 | SRUBA
2 x Bolt assembly | 16 | 45 | 4 | 7089 | PODKLADKA-16-7089 | 2 | 4032 | NAKRETKA-M16-4032 | 20 | 0 | 19 | 2 | 16 | 45 | 4014 | SRUBA
2 x Bolt assembly | 16 | 45 | 4 | 7093 | PODKLADKA-16-7093 | 2 | 4032 | NAKRETKA-M16-4032 | 20 | 0 | 19 | 2 | 16 | 45 | 4014 | SRUBA
7 x Bolt assembly | 16 | 160 | 4 | 7089 | PODKLADKA-16-7089 | 2 | 4032 | NAKRETKA-M16-4032 | 20 | 0 | 19 | 2 | 16 | 160 | 4014 | SRUBA
6 x Bolt assembly | 16 | 120 | 4 | 7089 | PODKLADKA-16-7089 | 2 | 4032 | NAKRETKA-M16-4032 | 20 | 0 | 19 | 2 | 16 | 120 | 4014 | SRUBA
3 x Bolt assembly | 10 | 40 | 6 | 7089 | PODKLADKA-10-7089 | 2 | 4032 | NAKRETKA-M10-4032 | 0 | 0 | 12 | 2 | 10 | 40 | 4014 | SRUBA
5 x Bolt assembly | 16 | 150 | 4 | 7089 | PODKLADKA-16-7089 | 2 | 4032 | NAKRETKA-M16-4032 | 20 | 0 | 19 | 2 | 16 | 150 | 4014 | SRUBA
6 x Bolt assembly | 16 | 35 | 2 | 125A | PODKLADKA-16-125A | 1 | 934 | NAKRETKA-M16-934 | 15 | 0 | 19 | 1 | 16 | 35 | 931 | SRUBA
2 x Bolt assembly | 16 | 90 | 8 | 7089 | PODKLADKA-16-7089 | 4 | 4032 | NAKRETKA-M16-4032 | 0 | 0 | 26 | 4 | 16 | 90 | 4014 | SRUBA
2 x Bolt assembly | 20 | 90 | 8 | 6916 | PODKLADKA-21-6916 | 4 | 6915 | NAKRETKA-M20-6915 | 0 | 0 | 23 | 4 | 20 | 90 | 6914 | SRUBA
4 x Bolt assembly | 16 | 45 | 2 | 7089 | PODKLADKA-16-7089 | 1 | 4032 | NAKRETKA-M16-4032 | 0 | 0 | 19 | 1 | 16 | 45 | 4017 | SRUBA
8 x Bolt assembly | 12 | 44 | 2 | 7093 | PODKLADKA-12-7093 | 2 | 4032 | NAKRETKA-M12-4032 | 0 | 15 | 17 | 2 | 12 | 44 | 975 | HILTI HVU/HAS M12X160/28
Bolt assembly | 10 | 70 | 4 | 7089 | PODKLADKA-10-7089 | 2 | 4032 | NAKRETKA-M10-4032 | 10 | 0 | 13 | 2 | 10 | 70 | 4014 | SRUBA
4 x Bolt assembly | 10 | 25 | 4 | 7089 | PODKLADKA-10-7089 | 2 | 4032 | NAKRETKA-M10-4032 | 10 | 0 | 13 | 2 | 10 | 25 | 4017 | SRUBA
3 x Bolt assembly | 12 | 45 | 4 | 7089 | PODKLADKA-12-7089 | 2 | 4032 | NAKRETKA-M12-4032 | 0 | 20 | 15 | 2 | 12 | 45 | 4014 | SRUBA
Bolt assembly | 12 | 45 | 2 | 7089 | PODKLADKA-12-7089 | 1 | 4032 | NAKRETKA-M12-4032 | 0 | 20 | 15 | 1 | 12 | 45 | 4014 | SRUBA
2 x Bolt assembly | 12 | 40 | 6 | 7089 | PODKLADKA-12-7089 | 3 | 4032 | NAKRETKA-M12-4032 | 0 | 20 | 15 | 3 | 12 | 40 | 4017 | SRUBA
3 x Bolt assembly | 12 | 35 | 6 | 7089 | PODKLADKA-12-7089 | 3 | 4032 | NAKRETKA-M12-4032 | 0 | 20 | 15 | 3 | 12 | 35 | 4017 | SRUBA
3 x Bolt assembly | 12 | 35 | 4 | 7089 | PODKLADKA-12-7089 | 2 | 4032 | NAKRETKA-M12-4032 | 0 | 20 | 15 | 2 | 12 | 35 | 4017 | SRUBA
Bolt assembly | 16 | 30 | 0 | 7089 | PODKLADKA-16-7089 | 0 | 4032 | NAKRETKA-M16-4032 | 0 | 0 | 19 | 2 | 19 | 30 | 4014 | SRUBA
3 x Bolt assembly | 12 | 45 | 6 | 7089 | PODKLADKA-12-7089 | 3 | 4032 | NAKRETKA-M12-4032 | 0 | 20 | 15 | 3 | 12 | 45 | 4014 | SRUBA
Bolt assembly | 10 | 70 | 2 | 7089 | PODKLADKA-10-7089 | 1 | 4032 | NAKRETKA-M10-4032 | 10 | 0 | 13 | 1 | 10 | 70 | 4014 | SRUBA
Bolt assembly | 10 | 75 | 2 | 7089 | PODKLADKA-10-7089 | 1 | 4032 | NAKRETKA-M10-4032 | 0 | 10 | 13 | 1 | 10 | 75 | 4014 | SRUBA
2 x Bolt assembly | 10 | 40 | 3 | 7089 | PODKLADKA-10-7089 | 1 | 4032 | NAKRETKA-M10-4032 | 0 | 0 | 13 | 1 | 10 | 40 | 4014 | SRUBA
9 x Bolt assembly | 16 | 100 | 4 | 7089 | PODKLADKA-16-7089 | 2 | 4032 | NAKRETKA-M16-4032 | 20 | 0 | 19 | 2 | 16 | 100 | 4014 | SRUBA
6 x Bolt assembly | 12 | 80 | 4 | 7089 | PODKLADKA-12-7089 | 2 | 4032 | NAKRETKA-M12-4032 | 15 | 0 | 15 | 2 | 12 | 80 | 4014 | SRUBA
6 x Bolt assembly | 12 | 45 | 4 | 7089 | PODKLADKA-12-7089 | 2 | 4032 | NAKRETKA-M12-4032 | 20 | 0 | 15 | 2 | 12 | 45 | 4014 | SRUBA
3 x Bolt assembly | 16 | 50 | 4 | 125A | PODKLADKA-16-125A | 2 | 934 | NAKRETKA-M16-934 | 0 | 15 | 19 | 2 | 16 | 50 | 931 | SRUBA
Bolt assembly | 16 | 80 | 4 | 125A | PODKLADKA-16-125A | 2 | 934 | NAKRETKA-M16-934 | 0 | 15 | 19 | 2 | 16 | 80 | 931 | SRUBA
2 x Bolt assembly | 16 | 100 | 2 | 125A | PODKLADKA-16-125A | 1 | 934 | NAKRETKA-M16-934 | 15 | 0 | 19 | 1 | 16 | 100 | 931 | SRUBA
4 x Bolt assembly | 10 | 40 | 4 | 7089 | PODKLADKA-10-7089 | 2 | 4032 | NAKRETKA-M10-4032 | 0 | 0 | 13 | 2 | 10 | 40 | 4014 | SRUBA
8 x Bolt assembly | 12 | 45 | 4 | 7089 | PODKLADKA-12-7089 | 2 | 4032 | NAKRETKA-M12-4032 | 0 | 15 | 15 | 2 | 12 | 45 | 4014 | SRUBA
2 x Bolt assembly | 16 | 50 | 4 | 7089 | PODKLADKA-16-7089 | 2 | 4032 | NAKRETKA-M16-4032 | 0 | 40 | 19 | 2 | 16 | 50 | 4014 | SRUBA
2 x Bolt assembly | 16 | 58 | 2 | 7093 | PODKLADKA-16-7093 | 2 | 4032 | NAKRETKA-M16-4032 | 0 | 25 | 21 | 2 | 16 | 58 | 975 | HILTI HVU/HAS M16X190/38
164 x Bolt assembly | 12 | 35 | 2 | 125A | PODKLADKA-12-125A | 1 | 934 | NAKRETKA-M12-934 | 0 | 20 | 15 | 1 | 12 | 35 | 931 | SRUBA
164 x Bolt assembly | 12 | 35 | 2 | 125A | PODKLADKA-12-125A | 1 | 934 | NAKRETKA-M12-934 | 0 | 0 | 15 | 1 | 12 | 35 | 931 | SRUBA
3 x Bolt assembly | 10 | 35 | 4 | 125A | PODKLADKA-10-125A | 2 | 934 | NAKRETKA-M10-934 | 20 | 0 | 12 | 2 | 10 | 35 | 931 | SRUBA
5 x Bolt assembly | 16 | 140 | 4 | 7089 | PODKLADKA-16-7089 | 2 | 4032 | NAKRETKA-M16-4032 | 0 | 20 | 19 | 2 | 16 | 140 | 4014 | SRUBA
5 x Bolt assembly | 16 | 140 | 4 | 7089 | PODKLADKA-16-7089 | 2 | 4032 | NAKRETKA-M16-4032 | 20 | 0 | 19 | 2 | 16 | 140 | 4014 | SRUBA
8 x Bolt assembly | 12 | 50 | 4 | 7089 | PODKLADKA-12-7089 | 2 | 4032 | NAKRETKA-M12-4032 | 0 | 15 | 15 | 2 | 12 | 50 | 4014 | SRUBA
4 x Bolt assembly | 10 | 70 | 2 | 7089 | PODKLADKA-10-7089 | 1 | 4032 | NAKRETKA-M10-4032 | 0 | 0 | 13 | 1 | 10 | 70 | 4014 | SRUBA
2 x Bolt assembly | 16 | 120 | 4 | 7093 | PODKLADKA-16-7093 | 2 | 4032 | NAKRETKA-M16-4032 | 20 | 0 | 19 | 2 | 16 | 120 | 4014 | SRUBA
2 x Bolt assembly | 12 | 45 | 2 | 7089 | PODKLADKA-12-7089 | 1 | 4032 | NAKRETKA-M12-4032 | 0 | 0 | 15 | 1 | 12 | 45 | 4014 | SRUBA
2 x Bolt assembly | 10 | 6 | 0 | 125A | PODKLADKA-10-125A | 0 | 934 | NAKRETKA-M10-934 | 0 | 0 | 12 | 1 | 12 | 6 | 931 | SRUBA
3 x Bolt assembly | 16 | 100 | 4 | 7089 | PODKLADKA-16-7089 | 2 | 4032 | NAKRETKA-M16-4032 | 0 | 20 | 19 | 2 | 16 | 100 | 4014 | SRUBA
2 x Bolt assembly | 16 | 100 | 8 | 7089 | PODKLADKA-16-7089 | 4 | 4032 | NAKRETKA-M16-4032 | 0 | 30 | 19 | 4 | 16 | 100 | 4014 | SRUBA
6 x Bolt assembly | 16 | 75 | 8 | 6916 | PODKLADKA-16-6916 | 4 | 6915 | NAKRETKA-M16-6915 | 0 | 0 | 19 | 4 | 16 | 75 | 6914 | SRUBA
2 x Bolt assembly | 16 | 65 | 8 | 7089 | PODKLADKA-16-7089 | 4 | 4032 | NAKRETKA-M16-4032 | 0 | 0 | 19 | 4 | 16 | 65 | 4014 | SRUBA
2 x Bolt assembly | 16 | 60 | 8 | 7089 | PODKLADKA-16-7089 | 4 | 4032 | NAKRETKA-M16-4032 | 0 | 0 | 19 | 4 | 16 | 60 | 4014 | SRUBA
4 x Bolt assembly | 16 | 70 | 8 | 7089 | PODKLADKA-16-7089 | 4 | 4032 | NAKRETKA-M16-4032 | 0 | 0 | 19 | 4 | 16 | 70 | 4014 | SRUBA
4 x Bolt assembly | 16 | 60 | 8 | 6916 | PODKLADKA-16-6916 | 4 | 6915 | NAKRETKA-M16-6915 | 0 | 0 | 19 | 4 | 16 | 60 | 6914 | SRUBA
2 x Bolt assembly | 16 | 20.0001 | 0 | 125A | PODKLADKA-16-125A | 0 | 934 | NAKRETKA-M16-934 | 0 | 0 | 18 | 4 | 18 | 20 | 931 | SRUBA

# IfcMember: BL5*170 (18)
In: Undefined
Description: BL5*170; Material: STEEL/S355
Tekla Common - Phase: 1; Class: 99
Tekla Quantity - Weight: 1.1 kg; Volume: 0 m3; Gross footprint area: 0 m2; Area per tons: 54 m2; Net surface area: 0.1 m2; Height: 170 mm; Width: 5 mm; Length: 170 mm
Pset_MemberCommon - LoadBearing: yes; Reference: L1
BaseQuantities - Length: 170 mm; OuterSurfaceArea: 0.0612 m2; GrossSurfaceArea: 0.0612 m2; CrossSectionArea: 0.00085 m2; NetVolume: 0.0001445 m3; GrossVolume: 0.0001445 m3
Name | Bottom elevation | Top elevation | NetWeight (kg) = GrossWeight (kg)
2 x BLACHA | +12.502 | +12.612 | 1.13432
2 x BLACHA | +12.553 | +12.661 | 1.13433
2 x BLACHA | +13.596 | +13.744 | 1.13432
2 x BLACHA | +13.599 | +13.746 | 1.13432
2 x BLACHA | +13.601 | +13.749 | 1.13432
2 x BLACHA | +12.498 | +12.608 | 1.13432
2 x BLACHA | +12.494 | +12.604 | 1.13432
2 x BLACHA | +12.549 | +12.657 | 1.13433
2 x BLACHA | +12.545 | +12.653 | 1.13433

# IfcMember: K80/4 (5)
In: Undefined
Description: K80/4; Material: STEEL/S355
Tekla Common - Phase: 1; Class: 2
Tekla Quantity - Volume: 0 m3; Gross footprint area: 0 m2; Area per tons: 33.6 m2; Height: 80 mm; Width: 80 mm
Pset_MemberCommon - LoadBearing: no
BaseQuantities - CrossSectionArea: 0.001174 m2
Name | Bottom elevation | Top elevation | Weight (kg) | Net surface area (m2) | Tekla Quantity, Length (mm) | Reference | BaseQuantities, Length (mm) | OuterSurfaceArea (m2) = GrossSurfaceArea (m2) | NetVolume (m3) | GrossVolume (m3) | NetWeight (kg) | GrossWeight (kg)
2 x BEAM | +11.103 | +12.608 | 16.9 | 0.7 | 1837.2 | k28 | 1837.24 | 0.569543 | 0.00223408 | 0.00215691 | 17.5375 | 16.9318
2 x BEAM | +11.100 | +12.559 | 16.6 | 0.7 | 1796.7 | k30 | 1796.74 | 0.55699 | 0.00218484 | 0.00210938 | 17.151 | 16.5586
BEAM | +12.915 | +13.777 | 16.1 | 0.4 | 1761.3 | k18 | 1761.26 | 0.545989 | 0.00201173 | 0.00206771 | 15.7921 | 16.2316

# IfcMember: L60*3, BEAM
In: Undefined
Description: L60*3; Material: STEEL/S235
Tekla Common - Bottom elevation: +13.821; Top elevation: +13.902; Phase: 1; Class: 1
Tekla Quantity - Weight: 0.2 kg; Volume: 0 m3; Gross footprint area: 0 m2; Area per tons: 90.3 m2; Net surface area: 0 m2; Height: 60 mm; Width: 60 mm; Length: 80 mm
Pset_MemberCommon - LoadBearing: no; Reference: F12
BaseQuantities - Length: 80 mm; OuterSurfaceArea: 0.019902 m2; GrossSurfaceArea: 0.019902 m2; CrossSectionArea: 0.000355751 m2; NetVolume: 0.00002808 m3; GrossVolume: 0.00002808 m3; NetWeight: 0.220428 kg; GrossWeight: 0.220428 kg

# IfcMember: SHS50*3 (3)
In: Undefined
Description: SHS50*3; Material: STEEL/S235
Tekla Common - Phase: 1; Class: 10
Tekla Quantity - Weight: 5.4 kg; Volume: 0 m3; Gross footprint area: 0 m2; Area per tons: 45.3 m2; Net surface area: 0.2 m2; Height: 50 mm; Width: 50 mm
Pset_MemberCommon - LoadBearing: yes
BaseQuantities - CrossSectionArea: 0.00053866 m2
Name | Bottom elevation | Top elevation | Tekla Quantity, Length (mm) = BaseQuantities, Length (mm) | Reference | OuterSurfaceArea (m2) = GrossSurfaceArea (m2) | NetVolume (m3) = GrossVolume (m3) | NetWeight (kg) = GrossWeight (kg)
STANCHION | +13.813 | +15.024 | 1210 | F3 | 0.2426 | 0.00068244 | 5.35715
STANCHION | +13.686 | +14.882 | 1195 | fb3 | 0.2396 | 0.00067398 | 5.29074
STANCHION | +13.653 | +14.849 | 1195 | fb9 | 0.2396 | 0.00067398 | 5.29074

# IfcMember: UPE200 (2)
In: Undefined
Description: UPE200; Material: STEEL/S235
Tekla Common - Bottom elevation: +12.589; Top elevation: +14.040; Phase: 3; Class: 3
Tekla Quantity - Weight: 74.2 kg; Volume: 0 m3; Gross footprint area: 0 m2; Area per tons: 27.9 m2; Net surface area: 2.1 m2; Height: 200 mm; Width: 80 mm; Length: 3000.8 mm
Pset_MemberCommon - LoadBearing: yes
BaseQuantities - Length: 3000.76 mm; OuterSurfaceArea: 2.07052 m2; GrossSurfaceArea: 2.07052 m2; CrossSectionArea: 0.00315 m2; NetVolume: 0.00902272 m3; GrossVolume: 0.0094524 m3; NetWeight: 70.8283 kg; GrossWeight: 74.2013 kg
Name | Reference
BELKA | k108
BELKA | k107

# IfcMember: UPN200 (14)
In: Undefined
Description: UPN200; Material: STEEL/S235
Tekla Common - Phase: 2; Class: 4
Tekla Quantity - Volume: 0 m3; Gross footprint area: 0 m2; Area per tons: 26.1 m2; Height: 200 mm; Width: 75 mm
Pset_MemberCommon - LoadBearing: yes
BaseQuantities - CrossSectionArea: 0.00322 m2
Name | Bottom elevation | Top elevation | Weight (kg) | Net surface area (m2) | Tekla Quantity, Length (mm) | Reference | BaseQuantities, Length (mm) | OuterSurfaceArea (m2) = GrossSurfaceArea (m2) | NetVolume (m3) | GrossVolume (m3) | NetWeight (kg) | GrossWeight (kg)
BELKA | +12.150 | +14.000 | 94.5 | 2.4 | 3736.7 | k98 | 3736.73 | 2.46624 | 0.0119153 | 0.0120323 | 93.5349 | 94.4532
BELKA | +12.150 | +14.000 | 94.5 | 2.4 | 3736.7 | k97 | 3736.73 | 2.46624 | 0.0119153 | 0.0120323 | 93.5349 | 94.4532
BELKA | +10.500 | +12.350 | 94.5 | 2.4 | 3736.7 | k90 | 3736.73 | 2.46624 | 0.0119153 | 0.0120323 | 93.5349 | 94.4532
BELKA | +10.500 | +12.350 | 94.5 | 2.4 | 3736.7 | k89 | 3736.73 | 2.46624 | 0.0119153 | 0.0120323 | 93.5349 | 94.4532
BELKA | +8.850 | +10.700 | 94.5 | 2.4 | 3736.7 | k90 | 3736.73 | 2.46624 | 0.0119153 | 0.0120323 | 93.5349 | 94.4532
BELKA | +8.850 | +10.700 | 94.5 | 2.4 | 3736.7 | k89 | 3736.73 | 2.46624 | 0.0119153 | 0.0120323 | 93.5349 | 94.4532
BELKA | +7.200 | +9.050 | 94.5 | 2.4 | 3736.7 | k90 | 3736.73 | 2.46624 | 0.0119153 | 0.0120323 | 93.5349 | 94.4532
BELKA | +7.200 | +9.050 | 94.5 | 2.4 | 3736.7 | k89 | 3736.73 | 2.46624 | 0.0119153 | 0.0120323 | 93.5349 | 94.4532
BELKA | +5.550 | +7.400 | 94.5 | 2.4 | 3736.7 | k90 | 3736.73 | 2.46624 | 0.0119153 | 0.0120323 | 93.5349 | 94.4532
BELKA | +5.550 | +7.400 | 94.5 | 2.4 | 3736.7 | k89 | 3736.73 | 2.46624 | 0.0119153 | 0.0120323 | 93.5349 | 94.4532
BELKA | +3.900 | +5.750 | 94.5 | 2.4 | 3736.7 | k90 | 3736.73 | 2.46624 | 0.0119153 | 0.0120323 | 93.5349 | 94.4532
BELKA | +3.900 | +5.750 | 94.5 | 2.4 | 3736.7 | k89 | 3736.73 | 2.46624 | 0.0119153 | 0.0120323 | 93.5349 | 94.4532
BELKA | +2.780 | +4.100 | 64.4 | 1.8 | 2551.6 | k84 | 2551.61 | 1.68406 | 0.00808795 | 0.00821618 | 63.4904 | 64.497
BELKA | +2.780 | +4.100 | 64.4 | 1.8 | 2551.6 | k83 | 2551.61 | 1.68406 | 0.00808795 | 0.00821618 | 63.4904 | 64.497

# IfcPlate: BL10*60 (3)
In: Undefined
Description: BL10*60; Material: STEEL/S235
Tekla Common - Phase: 5; Class: 1
Tekla Quantity - Weight: 0.8 kg; Volume: 0 m3; Gross footprint area: 0 m2; Area per tons: 31 m2; Net surface area: 0 m2; Height: 60 mm; Width: 10 mm; Length: 200 mm
Pset_PlateCommon - LoadBearing: no; Reference: A14
BaseQuantities - Width: 60.0001 mm; NetArea: 0.0292 m2; GrossArea: 0.012 m2; CrossSectionArea: 0.0001 m2; NetVolume: 0.00012 m3; GrossVolume: 0.00012 m3
Name | Bottom elevation | Top elevation
BLACHA | +13.765 | +13.775
BLACHA | +13.775 | +13.785
BLACHA | +13.785 | +13.795

# IfcPlate: BL10*75, BLACHA
In: Undefined
Description: BL10*75; Material: STEEL/S235
Tekla Common - Bottom elevation: +13.565; Top elevation: +13.765; Phase: 5; Class: 4
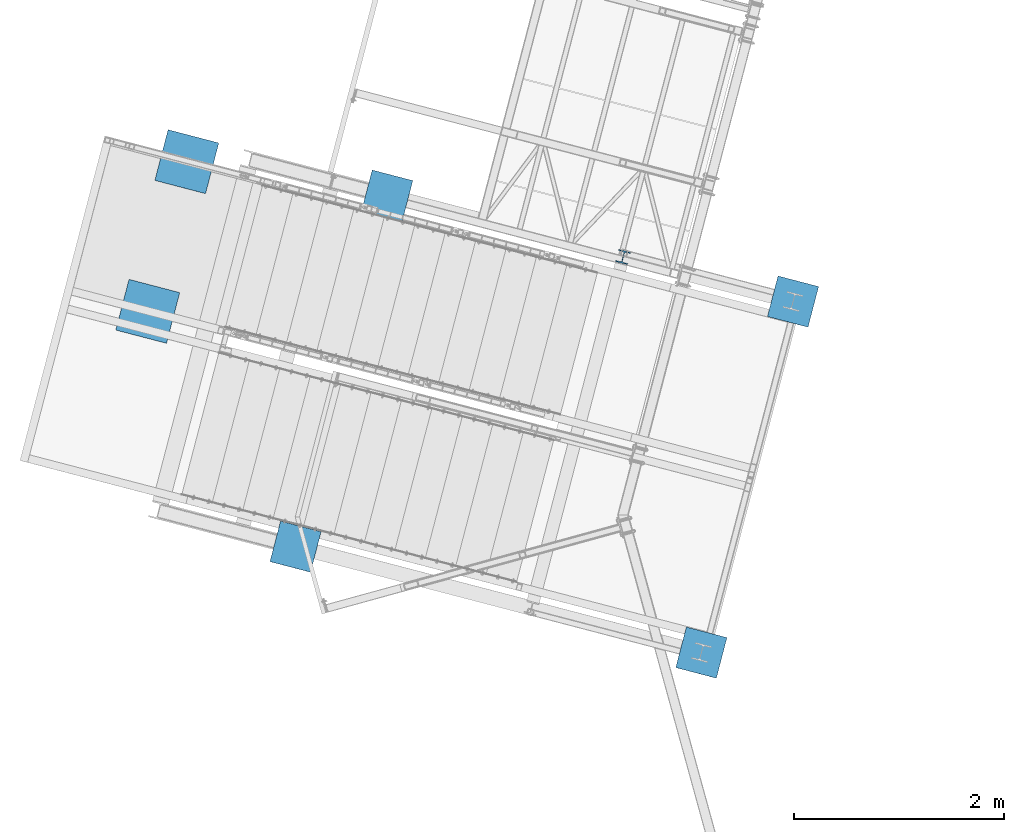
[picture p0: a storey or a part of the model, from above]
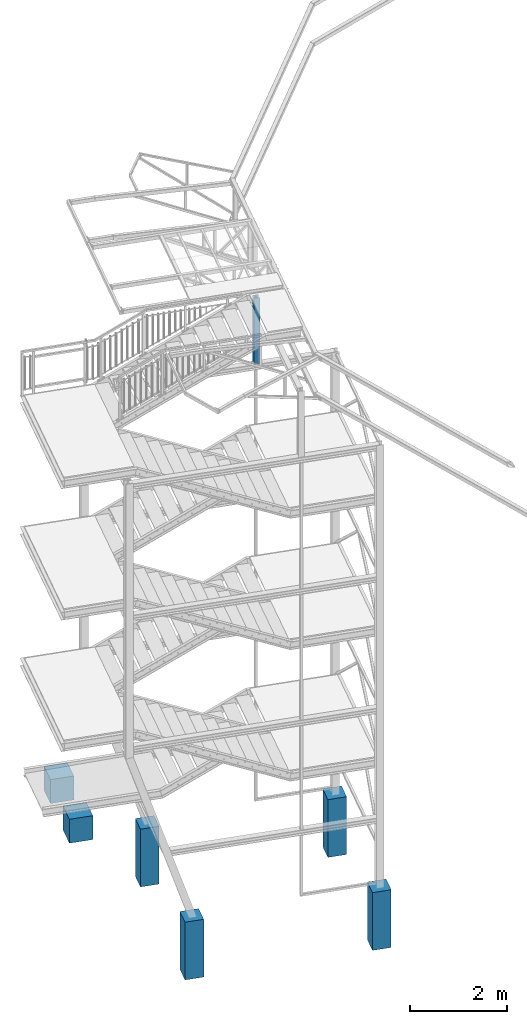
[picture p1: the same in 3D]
Properties of the parts of a building model (IFC2X3), part 5 of 5

# IfcPlate: BL10*75, BLACHA
Tekla Quantity - Weight: 1.3 kg; Volume: 0 m3; Gross footprint area: 0 m2; Area per tons: 30.1 m2; Net surface area: 0 m2; Height: 75 mm; Width: 10 mm; Length: 200 mm
Pset_PlateCommon - LoadBearing: no; Reference: A13
BaseQuantities - Width: 75 mm; NetArea: 0.0355 m2; GrossArea: 0.015 m2; CrossSectionArea: 0.0001 m2; NetVolume: 0.00015 m3; GrossVolume: 0.00015 m3

# IfcPlate: BL15*160 (2)
In: Undefined
Description: BL15*160; Material: STEEL/S355
Tekla Common - Bottom elevation: +13.555; Top elevation: +13.570; Phase: 1; Class: 1
Tekla Quantity - Weight: 5.2 kg; Volume: 0 m3; Gross footprint area: 0 m2; Area per tons: 19.5 m2; Net surface area: 0.1 m2; Height: 160 mm; Width: 15 mm; Length: 270 mm
Pset_PlateCommon - LoadBearing: no; Reference: B8
BaseQuantities - Width: 160 mm; NetArea: 0.0993 m2; GrossArea: 0.0432 m2; CrossSectionArea: 0.000225 m2; NetVolume: 0.000648 m3; GrossVolume: 0.000648 m3

# IfcPlate: BL16*100 (2)
In: Undefined
Description: BL16*100; Material: STEEL/S235
Tekla Common - Bottom elevation: +13.875; Top elevation: +13.975; Phase: 3; Class: 1
Tekla Quantity - Weight: 1.9 kg; Volume: 0 m3; Gross footprint area: 0 m2; Area per tons: 20.1 m2; Net surface area: 0 m2; Height: 100 mm; Width: 16 mm; Length: 159 mm
Pset_PlateCommon - LoadBearing: no; Reference: L6
BaseQuantities - Width: 100 mm; NetArea: 0.040088 m2; GrossArea: 0.0159 m2; CrossSectionArea: 0.000256 m2; NetVolume: 0.0002544 m3; GrossVolume: 0.0002544 m3

# IfcPlate: BL16*195 (2)
In: Undefined
Description: BL16*195; Material: STEEL/S235
Tekla Common - Bottom elevation: +13.780; Top elevation: +13.975; Phase: 3; Class: 1
Tekla Quantity - Weight: 5.4 kg; Volume: 0 m3; Gross footprint area: 0 m2; Area per tons: 18.3 m2; Net surface area: 0.1 m2; Height: 195 mm; Width: 16 mm; Length: 270 mm
Pset_PlateCommon - LoadBearing: no; Reference: L5
BaseQuantities - Width: 195 mm; NetArea: 0.100349 m2; GrossArea: 0.05265 m2; CrossSectionArea: 0.000256 m2; NetVolume: 0.000698 m3; GrossVolume: 0.0008424 m3

# IfcPlate: BL2*50 (2)
In: Undefined
Description: BL2*50; Material: STEEL/S235
Tekla Common - Phase: 2; Class: 4
Tekla Quantity - Weight: 0 kg; Volume: 0 m3; Gross footprint area: 0 m2; Area per tons: 137.6 m2; Net surface area: 0 m2; Height: 50 mm; Width: 2 mm; Length: 50 mm
Pset_PlateCommon - LoadBearing: no; Reference: bl1
BaseQuantities - Width: 49.9988 mm; NetArea: 0.00540216 m2; GrossArea: 0.00250214 m2; CrossSectionArea: 0.000004 m2; NetVolume: 0.00000500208 m3; GrossVolume: 0.00000500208 m3
Name | Bottom elevation | Top elevation
KRATA | +13.324 | +13.374
KRATA | +13.430 | +13.480

# IfcPlate: BL20*290, BLACHA
In: Undefined
Description: BL20*290; Material: STEEL/S355
Tekla Common - Bottom elevation: +5.260; Top elevation: +5.280; Phase: 1; Class: 1
Tekla Quantity - Weight: 13.2 kg; Volume: 0 m3; Gross footprint area: 0.1 m2; Area per tons: 14.5 m2; Net surface area: 0.2 m2; Height: 290 mm; Width: 20 mm; Length: 290 mm
Pset_PlateCommon - LoadBearing: no; Reference: x1
BaseQuantities - Width: 290 mm; NetArea: 0.1914 m2; GrossArea: 0.0841 m2; CrossSectionArea: 0.0004 m2; NetVolume: 0.001682 m3; GrossVolume: 0.001682 m3

# IfcPlate: BL25*1000 (25)
In: Undefined
Description: BL25*1000; Material: STEEL/S275JR
Tekla Common - Phase: 1; Class: 1
Tekla Quantity - Volume: 0 m3; Gross footprint area: 0 m2; Area per tons: 10.3 m2; Height: 1000 mm; Width: 25 mm
Pset_PlateCommon - LoadBearing: no
BaseQuantities - Width: 1000 mm; CrossSectionArea: 0.000625 m2
Name | Bottom elevation | Top elevation | Weight (kg) | Net surface area (m2) | Length (mm) | Reference | NetArea (m2) | GrossArea (m2) | NetVolume (m3) = GrossVolume (m3)
KRATA | +13.896 | +13.941 | 334.3 | 3.4 | 1638 | KR13 | 3.4079 | 1.638 | 0.04095
KRATA | +13.998 | +14.044 | 311.7 | 3.2 | 1656 | KR1 | 3.18165 | 1.65597 | 0.0381809
KRATA | +13.998 | +14.040 | 258.9 | 2.7 | 1397.2 | KR2 | 2.65114 | 1.39717 | 0.0317113
2 x KRATA | +13.977 | +14.022 | 325.9 | 3.3 | 1597 | KR5 | 3.32385 | 1.597 | 0.039925
2 x KRATA | +13.936 | +13.982 | 325.9 | 3.3 | 1597 | KR5 | 3.32385 | 1.597 | 0.039925
2 x KRATA | +13.957 | +14.002 | 325.9 | 3.3 | 1597 | KR5 | 3.32385 | 1.597 | 0.039925
2 x KRATA | +13.916 | +13.961 | 327.6 | 3.3 | 1605 | KR8 | 3.34025 | 1.605 | 0.040125
2 x KRATA | +13.896 | +13.941 | 327.6 | 3.3 | 1605 | KR8 | 3.34025 | 1.605 | 0.040125
2 x KRATA | +13.875 | +13.920 | 327.6 | 3.3 | 1605 | KR8 | 3.34025 | 1.605 | 0.040125
2 x KRATA | +13.855 | +13.900 | 327.6 | 3.3 | 1605 | KR8 | 3.34025 | 1.605 | 0.040125
2 x KRATA | +13.793 | +13.839 | 327.6 | 3.3 | 1605 | KR8 | 3.34025 | 1.605 | 0.040125
2 x KRATA | +13.834 | +13.880 | 327.6 | 3.3 | 1605 | KR8 | 3.34025 | 1.605 | 0.040125
KRATA | +13.773 | +13.818 | 297 | 3 | 1587.2 | KR10 | 3.034 | 1.58724 | 0.0363798
KRATA | +13.776 | +13.818 | 242.8 | 2.4 | 1321.8 | KR9 | 2.4898 | 1.32183 | 0.0297432
2 x KRATA | +13.814 | +13.859 | 327.6 | 3.3 | 1605 | KR8 | 3.34025 | 1.605 | 0.040125

# IfcPlate: BL25*250 (10)
In: Undefined
Description: BL25*250; Material: STEEL/S275JR
Tekla Common - Phase: 1; Class: 1
Tekla Quantity - Volume: 0 m3; Gross footprint area: 0 m2; Area per tons: 10.9 m2; Net surface area: 1 m2; Height: 250 mm; Width: 25 mm
Pset_PlateCommon - LoadBearing: no
BaseQuantities - Width: 250 mm; CrossSectionArea: 0.000625 m2
Name | Bottom elevation | Top elevation | Weight (kg) | Length (mm) | Reference | NetArea (m2) | GrossArea (m2) | NetVolume (m3) = GrossVolume (m3)
KRATA | +13.936 | +13.982 | 81.5 | 1597 | KR6 | 0.89085 | 0.39925 | 0.00998125
KRATA | +13.916 | +13.961 | 81.9 | 1605 | KR7 | 0.89525 | 0.40125 | 0.0100312
KRATA | +13.896 | +13.941 | 81.9 | 1605 | KR7 | 0.89525 | 0.40125 | 0.0100312
KRATA | +13.875 | +13.920 | 81.9 | 1605 | KR7 | 0.89525 | 0.40125 | 0.0100312
KRATA | +13.855 | +13.900 | 81.9 | 1605 | KR7 | 0.89525 | 0.40125 | 0.0100312
KRATA | +13.793 | +13.839 | 81.9 | 1605 | KR7 | 0.89525 | 0.40125 | 0.0100312
KRATA | +13.834 | +13.880 | 81.9 | 1605 | KR7 | 0.89525 | 0.40125 | 0.0100312
KRATA | +13.772 | +13.818 | 82.7 | 1654.3 | KR11 | 0.904436 | 0.413578 | 0.0101332
KRATA | +13.957 | +14.002 | 81.5 | 1597 | KR6 | 0.89085 | 0.39925 | 0.00998125
KRATA | +13.814 | +13.859 | 81.9 | 1605 | KR7 | 0.89525 | 0.40125 | 0.0100312

# IfcPlate: BL25*332, KRATA
In: Undefined
Description: BL25*332; Material: STEEL/S275JR
Tekla Common - Bottom elevation: +13.977; Top elevation: +14.022; Phase: 1; Class: 1
Tekla Quantity - Weight: 84.1 kg; Volume: 0 m3; Gross footprint area: 0 m2; Area per tons: 10.9 m2; Net surface area: 1 m2; Height: 331.9 mm; Width: 25 mm; Length: 1597 mm
Pset_PlateCommon - LoadBearing: no; Reference: KR4
BaseQuantities - Width: 331.859 mm; NetArea: 0.919188 m2; GrossArea: 0.529978 m2; CrossSectionArea: 0.000625 m2; NetVolume: 0.0103067 m3; GrossVolume: 0.0103067 m3

# IfcPlate: BL25*490 (2)
In: Undefined
Description: BL25*490; Material: STEEL/S275JR
Tekla Common - Phase: 1; Class: 1
Tekla Quantity - Volume: 0 m3; Gross footprint area: 0 m2; Height: 490 mm; Width: 25 mm
Pset_PlateCommon - LoadBearing: no
BaseQuantities - Width: 490 mm; CrossSectionArea: 0.000625 m2
Name | Bottom elevation | Top elevation | Weight (kg) | Area per tons (m2) | Net surface area (m2) | Length (mm) | Reference | NetArea (m2) | GrossArea (m2) | NetVolume (m3) = GrossVolume (m3)
KRATA | +13.885 | +13.920 | 83.2 | 10.6 | 1 | 832 | KR16 | 0.88146 | 0.40768 | 0.010192
KRATA | +13.896 | +13.941 | 163.8 | 10.3 | 1.8 | 1638 | KR14 | 1.71164 | 0.80262 | 0.0200655

# IfcPlate: BL25*587, KRATA
In: Undefined
Description: BL25*587; Material: STEEL/S275JR
Tekla Common - Bottom elevation: +13.998; Top elevation: +14.037; Phase: 1; Class: 1
Tekla Quantity - Weight: 101.8 kg; Volume: 0 m3; Gross footprint area: 0 m2; Area per tons: 10.6 m2; Net surface area: 1.1 m2; Height: 587.3 mm; Width: 25 mm; Length: 1138.1 mm
Pset_PlateCommon - LoadBearing: no; Reference: KR3
BaseQuantities - Width: 587.338 mm; NetArea: 1.07475 m2; GrossArea: 0.668452 m2; CrossSectionArea: 0.000625 m2; NetVolume: 0.0124666 m3; GrossVolume: 0.0124666 m3

# IfcPlate: BL25*832, KRATA
In: Undefined
Description: BL25*832; Material: STEEL/S275JR
Tekla Common - Bottom elevation: +13.885; Top elevation: +13.920; Phase: 1; Class: 1
Tekla Quantity - Weight: 169.8 kg; Volume: 0 m3; Gross footprint area: 0 m2; Area per tons: 10.3 m2; Net surface area: 1.8 m2; Height: 832 mm; Width: 25 mm; Length: 1000 mm
Pset_PlateCommon - LoadBearing: no; Reference: KR15
BaseQuantities - Width: 832 mm; NetArea: 1.7556 m2; GrossArea: 0.832 m2; CrossSectionArea: 0.000625 m2; NetVolume: 0.0208 m3; GrossVolume: 0.0208 m3

# IfcPlate: BL3*142, MASKOWNICA
In: Undefined
Description: BL3*142; Material: STEEL/S275JR
Tekla Common - Bottom elevation: +14.035; Top elevation: +14.048; Phase: 1; Class: 1
Tekla Quantity - Weight: 8.6 kg; Volume: 0 m3; Gross footprint area: 0 m2; Area per tons: 86.9 m2; Net surface area: 0.7 m2; Height: 142 mm; Width: 3 mm; Length: 2714.2 mm
Pset_PlateCommon - LoadBearing: no; Reference: KR12
BaseQuantities - Width: 142.024 mm; NetArea: 0.745104 m2; GrossArea: 0.385476 m2; CrossSectionArea: 0.000009 m2; NetVolume: 0.00109216 m3; GrossVolume: 0.00109216 m3

# IfcPlate: BL3*160, MASKOWNICA
In: Undefined
Description: BL3*160; Material: STEEL/S275JR
Tekla Common - Bottom elevation: +13.795; Top elevation: +13.808; Phase: 1; Class: 1
Tekla Quantity - Weight: 9.2 kg; Volume: 0 m3; Gross footprint area: 0 m2; Area per tons: 86.7 m2; Net surface area: 0.7 m2; Height: 159.6 mm; Width: 3 mm; Length: 2541.1 mm
Pset_PlateCommon - LoadBearing: no; Reference: KR17
BaseQuantities - Width: 159.592 mm; NetArea: 0.800379 m2; GrossArea: 0.405547 m2; CrossSectionArea: 0.000009 m2; NetVolume: 0.00117679 m3; GrossVolume: 0.00117679 m3

# IfcPlate: BL3*80, BLACHA
In: Undefined
Description: BL3*80; Material: STEEL/S235
Tekla Common - Bottom elevation: +13.774; Top elevation: +13.777; Phase: 2; Class: 1
Tekla Quantity - Weight: 0.2 kg; Volume: 0 m3; Gross footprint area: 0 m2; Area per tons: 91.3 m2; Net surface area: 0 m2; Height: 80 mm; Width: 3 mm; Length: 80 mm
Pset_PlateCommon - LoadBearing: no; Reference: A20
BaseQuantities - Width: 80 mm; NetArea: 0.01376 m2; GrossArea: 0.0064 m2; CrossSectionArea: 0.000009 m2; NetVolume: 0.0000192 m3; GrossVolume: 0.0000192 m3

# IfcPlate: BL30*1000 (5)
In: Undefined
Description: BL30*1000; Material: STEEL/S275JR
Tekla Common - Bottom elevation: +13.765; Top elevation: +13.795; Phase: 5
Tekla Quantity - Volume: 0 m3; Area per tons: 8.7 m2; Height: 1000 mm; Width: 30 mm
Pset_PlateCommon - LoadBearing: no
BaseQuantities - Width: 1000 mm; CrossSectionArea: 0.0009 m2
Name | Class | Weight (kg) | Gross footprint area (m2) | Net surface area (m2) | Length (mm) | Reference | NetArea (m2) | GrossArea (m2) | NetVolume (m3) = GrossVolume (m3)
2 x KRATA | 1 | 253.1 | 0.9 | 2.2 | 1040 | KR20 | 2.2024 | 1.04 | 0.0312
2 x KRATA | 1 | 262.8 | 1.1 | 2.3 | 1080 | KR22 | 2.2848 | 1.08 | 0.0324
KRATA | 4 | 292 | 1.2 | 2.4 | 1200 | zz19 | 2.532 | 1.2 | 0.036

# IfcPlate: BL30*1286, KRATA
In: Undefined
Description: BL30*1286; Material: STEEL/S275JR
Tekla Common - Bottom elevation: +13.765; Top elevation: +13.795; Phase: 5; Class: 1
Tekla Quantity - Weight: 271.4 kg; Volume: 0 m3; Gross footprint area: 1.1 m2; Area per tons: 8.7 m2; Net surface area: 2.4 m2; Height: 1286.3 mm; Width: 30 mm; Length: 1040.7 mm
Pset_PlateCommon - LoadBearing: no; Reference: KR19
BaseQuantities - Width: 1286.3 mm; NetArea: 2.35407 m2; GrossArea: 1.33869 m2; CrossSectionArea: 0.0009 m2; NetVolume: 0.0334544 m3; GrossVolume: 0.0334544 m3

# IfcPlate: BL30*1500 (3)
In: Undefined
Description: BL30*1500; Material: STEEL/S235
Tekla Common - Phase: 2; Class: 2
Tekla Quantity - Weight: 1077.4 kg; Volume: 0.1 m3; Gross footprint area: 0 m2; Area per tons: 8.7 m2; Net surface area: 9.4 m2; Height: 1500 mm; Width: 30 mm; Length: 3050 mm
Pset_PlateCommon - LoadBearing: no; Reference: q1
BaseQuantities - Width: 1500 mm; NetArea: 9.423 m2; GrossArea: 4.575 m2; CrossSectionArea: 0.0009 m2; NetVolume: 0.13725 m3; GrossVolume: 0.13725 m3
Name | Bottom elevation | Top elevation
KRATA | +12.350 | +12.380
KRATA | +9.050 | +9.080
KRATA | +5.750 | +5.780

# IfcPlate: BL30*1875 (3)
In: Undefined
Description: BL30*1875; Material: STEEL/S235
Tekla Common - Phase: 2; Class: 2
Tekla Quantity - Weight: 1346.8 kg; Volume: 0.2 m3; Gross footprint area: 0 m2; Area per tons: 8.7 m2; Net surface area: 11.7 m2; Height: 1875 mm; Width: 30 mm; Length: 3050 mm
Pset_PlateCommon - LoadBearing: no; Reference: q5
BaseQuantities - Width: 1875 mm; NetArea: 11.733 m2; GrossArea: 5.71875 m2; CrossSectionArea: 0.0009 m2; NetVolume: 0.171562 m3; GrossVolume: 0.171562 m3
Name | Bottom elevation | Top elevation
KRATA | +10.700 | +10.730
KRATA | +7.400 | +7.430
KRATA | +4.100 | +4.130

# IfcPlate: BL30*258, KRATA
In: Undefined
Description: BL30*258; Material: STEEL/S275JR
Tekla Common - Bottom elevation: +13.765; Top elevation: +13.795; Phase: 5; Class: 4
Tekla Quantity - Weight: 18.7 kg; Volume: 0 m3; Gross footprint area: 0.1 m2; Area per tons: 10.6 m2; Net surface area: 0.2 m2; Height: 257.9 mm; Width: 30 mm; Length: 536 mm
Pset_PlateCommon - LoadBearing: no; Reference: zz12
BaseQuantities - Width: 257.873 mm; NetArea: 0.198509 m2; GrossArea: 0.13822 m2; CrossSectionArea: 0.0009 m2; NetVolume: 0.00238597 m3; GrossVolume: 0.00238597 m3

# IfcPlate: BL30*750, KRATA
In: Undefined
Description: BL30*750; Material: STEEL/S235
Tekla Common - Bottom elevation: +14.000; Top elevation: +14.030; Phase: 2; Class: 2
Tekla Quantity - Weight: 247.3 kg; Volume: 0 m3; Gross footprint area: 1.1 m2; Area per tons: 8.9 m2; Net surface area: 2.2 m2; Height: 750 mm; Width: 30 mm; Length: 1400 mm
Pset_PlateCommon - LoadBearing: no; Reference: q4
BaseQuantities - Width: 750 mm; NetArea: 2.229 m2; GrossArea: 1.05 m2; CrossSectionArea: 0.0009 m2; NetVolume: 0.0315 m3; GrossVolume: 0.0315 m3

# IfcPlate: BL30*931, KRATA
In: Undefined
Description: BL30*931; Material: STEEL/S275JR
Tekla Common - Bottom elevation: +13.765; Top elevation: +13.795; Phase: 5; Class: 1
Tekla Quantity - Weight: 162.8 kg; Volume: 0 m3; Gross footprint area: 0.7 m2; Area per tons: 8.9 m2; Net surface area: 1.5 m2; Height: 931.4 mm; Width: 30 mm; Length: 1436.3 mm
Pset_PlateCommon - LoadBearing: no; Reference: KR18
BaseQuantities - Width: 931.363 mm; NetArea: 1.45133 m2; GrossArea: 1.33768 m2; CrossSectionArea: 0.0009 m2; NetVolume: 0.0200652 m3; GrossVolume: 0.0200652 m3

# IfcPlate: BL30*935, KRATA
In: Undefined
Description: BL30*935; Material: STEEL/S275JR
Tekla Common - Bottom elevation: +13.765; Top elevation: +13.795; Phase: 5; Class: 4
Tekla Quantity - Weight: 231.1 kg; Volume: 0 m3; Gross footprint area: 0.9 m2; Area per tons: 8.7 m2; Net surface area: 1.9 m2; Height: 935 mm; Width: 30 mm; Length: 1200 mm
Pset_PlateCommon - LoadBearing: no; Reference: zz13
BaseQuantities - Width: 935 mm; NetArea: 2.01728 m2; GrossArea: 1.122 m2; CrossSectionArea: 0.0009 m2; NetVolume: 0.0284908 m3; GrossVolume: 0.0284908 m3

# IfcPlate: BL30*939, KRATA
In: Undefined
Description: BL30*939; Material: STEEL/S275JR
Tekla Common - Bottom elevation: +13.765; Top elevation: +13.795; Phase: 5; Class: 1
Tekla Quantity - Weight: 135.8 kg; Volume: 0 m3; Gross footprint area: 0.7 m2; Area per tons: 8.9 m2; Net surface area: 1.2 m2; Height: 939 mm; Width: 30 mm; Length: 1080 mm
Pset_PlateCommon - LoadBearing: no; Reference: KR21
BaseQuantities - Width: 939 mm; NetArea: 1.22096 m2; GrossArea: 1.01412 m2; CrossSectionArea: 0.0009 m2; NetVolume: 0.0167463 m3; GrossVolume: 0.0167463 m3

# IfcPlate: BL4*1000 (2)
In: Undefined
Description: BL4*1000; Material: STEEL/S235
Tekla Common - Top elevation: +14.030; Phase: 2; Class: 1
Tekla Quantity - Weight: 62.4 kg; Volume: 0 m3; Gross footprint area: 2 m2; Area per tons: 64.1 m2; Net surface area: 4 m2; Height: 1000 mm; Width: 4 mm; Length: 1988 mm
Pset_PlateCommon - LoadBearing: no; Reference: A19
BaseQuantities - Width: 1000 mm; NetArea: 3.9999 m2; GrossArea: 1.988 m2; CrossSectionArea: 0.000016 m2; NetVolume: 0.007952 m3; GrossVolume: 0.007952 m3
Name | Bottom elevation
BLACHA | +14.026
BLACHA | +14.025

# IfcPlate: BL4*465, BLACHA
In: Undefined
Description: BL4*465; Material: STEEL/S235
Tekla Common - Bottom elevation: +14.026; Top elevation: +14.030; Phase: 2; Class: 1
Tekla Quantity - Weight: 29 kg; Volume: 0 m3; Gross footprint area: 0.9 m2; Area per tons: 64.4 m2; Net surface area: 1.9 m2; Height: 465 mm; Width: 4 mm; Length: 1988 mm
Pset_PlateCommon - LoadBearing: no; Reference: A18
BaseQuantities - Width: 465 mm; NetArea: 1.86846 m2; GrossArea: 0.92442 m2; CrossSectionArea: 0.000016 m2; NetVolume: 0.00369768 m3; GrossVolume: 0.00369768 m3

# IfcPlate: BL40*530, KRATA
In: Undefined
Description: BL40*530; Material: STEEL/S235
Tekla Common - Bottom elevation: +14.000; Top elevation: +14.040; Phase: 3; Class: 2
Tekla Quantity - Weight: 246.3 kg; Volume: 0 m3; Gross footprint area: 0.7 m2; Area per tons: 7 m2; Net surface area: 1.8 m2; Height: 530 mm; Width: 40 mm; Length: 1480 mm
Pset_PlateCommon - LoadBearing: no; Reference: SCH1
BaseQuantities - Width: 530 mm; NetArea: 1.7296 m2; GrossArea: 0.7844 m2; CrossSectionArea: 0.0016 m2; NetVolume: 0.031376 m3; GrossVolume: 0.031376 m3

# IfcPlate: BL5*160 (6)
In: Undefined
Description: BL5*160; Material: STEEL/S355
Tekla Common - Phase: 1; Class: 1
Tekla Quantity - Weight: 1.8 kg; Volume: 0 m3; Gross footprint area: 0 m2; Area per tons: 53.5 m2; Net surface area: 0.1 m2; Height: 160 mm; Width: 5 mm; Length: 270 mm
Pset_PlateCommon - LoadBearing: no; Reference: B7
BaseQuantities - Width: 160 mm; NetArea: 0.0907 m2; GrossArea: 0.0432 m2; CrossSectionArea: 0.000025 m2; NetVolume: 0.000216 m3; GrossVolume: 0.000216 m3
Name | Bottom elevation | Top elevation
2 x BLACHA | +13.540 | +13.545
2 x BLACHA | +13.550 | +13.555
2 x BLACHA | +13.545 | +13.550

# IfcPlate: BL5*25 (2)
In: Undefined
Description: BL5*25; Material: STEEL/S355
Tekla Common - Phase: 3; Class: 1
Tekla Quantity - Weight: 0 kg; Volume: 0 m3; Gross footprint area: 0 m2; Area per tons: 66.8 m2; Net surface area: 0 m2; Height: 25 mm; Width: 5 mm; Length: 45 mm
Pset_PlateCommon - LoadBearing: no; Reference: xx33
BaseQuantities - Width: 25.0011 mm; NetArea: 0.00295008 m2; GrossArea: 0.00112506 m2; CrossSectionArea: 0.000025 m2; NetVolume: 0.00000562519 m3; GrossVolume: 0.00000562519 m3
Name | Bottom elevation | Top elevation
BLACHA | +13.840 | +13.886
BLACHA | +13.928 | +13.974

# IfcPlate: BL5*45 (2)
In: Undefined
Description: BL5*45; Material: STEEL/S355
Tekla Common - Phase: 3; Class: 1
Tekla Quantity - Weight: 0.1 kg; Volume: 0 m3; Gross footprint area: 0 m2; Area per tons: 61.4 m2; Net surface area: 0 m2; Height: 45 mm; Width: 5 mm; Length: 53 mm
Pset_PlateCommon - LoadBearing: no; Reference: xx32
BaseQuantities - Width: 45 mm; NetArea: 0.00575016 m2; GrossArea: 0.0023851 m2; CrossSectionArea: 0.000025 m2; NetVolume: 0.0000119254 m3; GrossVolume: 0.0000119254 m3
Name | Bottom elevation | Top elevation
BLACHA | +13.837 | +13.884
BLACHA | +13.930 | +13.977

# IfcPlate: BL6*45 (2)
In: Undefined
Description: BL6*45; Material: STEEL/S355
Tekla Common - Phase: 3; Class: 1
Tekla Quantity - Weight: 0.1 kg; Volume: 0 m3; Gross footprint area: 0 m2; Area per tons: 53.8 m2; Net surface area: 0 m2; Height: 45 mm; Width: 6 mm; Length: 45 mm
Pset_PlateCommon - LoadBearing: no; Reference: xx34
BaseQuantities - Width: 44.9999 mm; NetArea: 0.00513025 m2; GrossArea: 0.00202516 m2; CrossSectionArea: 0.000036 m2; NetVolume: 0.0000121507 m3; GrossVolume: 0.0000121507 m3
Name | Bottom elevation | Top elevation
BLACHA | +13.839 | +13.886
BLACHA | +13.928 | +13.975

# IfcSlab: 20*3600, CONCRETE_SLAB
In: Undefined
Description: 20*3600; PredefinedType: FLOOR; Material: CONCRETE/C45/55
Tekla Common - Bottom elevation: +12.545; Top elevation: +12.565; Phase: 3; Class: 1
Tekla Quantity - Weight: 661.7 kg; Volume: 0.3 m3; Gross footprint area: 13.8 m2; Area per tons: 42.1 m2; Net surface area: 27.9 m2; Height: 3600 mm; Width: 20 mm; Length: 4000 mm
Pset_SlabCommon - LoadBearing: yes; Reference: P2
BaseQuantities - Width: 20 mm; NetVolume: 0.2757 m3; NetArea: 13.785 m2; NetWeight: 661.681 kg

# IfcSlab: 200*3600, CONCRETE_SLAB
In: Undefined
Description: 200*3600; PredefinedType: FLOOR; Material: CONCRETE/C25/30
Tekla Common - Bottom elevation: +12.345; Top elevation: +12.545; Phase: 3; Class: 12
Tekla Quantity - Weight: 6616.8 kg; Volume: 2.8 m3; Gross footprint area: 13.8 m2; Area per tons: 4.7 m2; Net surface area: 30.6 m2; Height: 3600 mm; Width: 200 mm; Length: 4000 mm
Pset_SlabCommon - LoadBearing: yes; Reference: P1
BaseQuantities - Width: 200 mm; NetVolume: 2.757 m3; NetArea: 13.785 m2; NetWeight: 6616.81 kg
